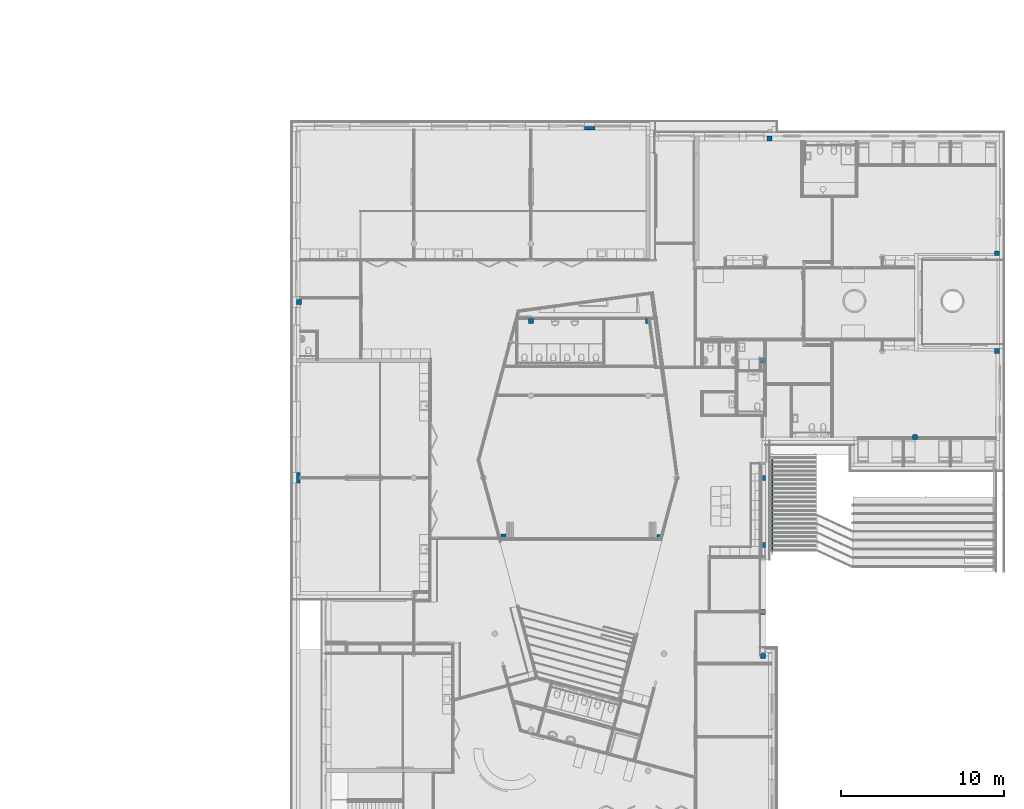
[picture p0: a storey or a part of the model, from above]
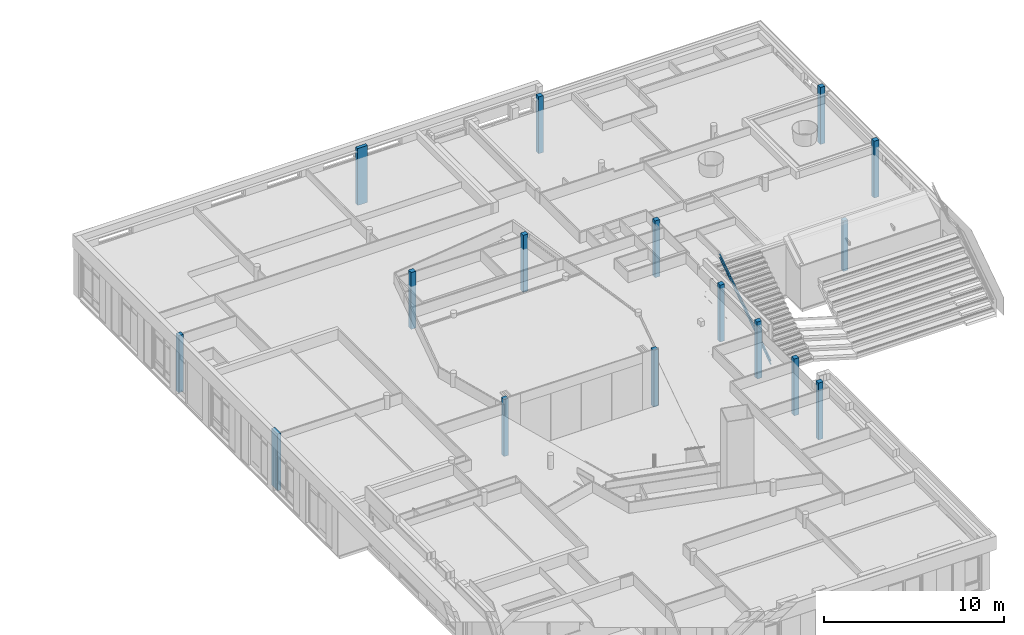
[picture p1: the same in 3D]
Properties of the parts of a building model (IFC2X3), part 1 of 5

# File
Description: ViewDefinition [9, SurfaceGeometryAddOnView, QuantityTakeOffAddOnView, SpaceBoundary2ndLevelAddOnView], Option [Elements to export: Selected elements only], Option [Partial Structure Display: Entire Model], Option [IFC Domain: All], Option [Structural Function: All Elements], Option [Convert Grid elements: On], Option [Convert IFC Annotations and ARCHICAD 2D elements: Off], Option [Convert 2D symbols of Doors and Windows: Off], Option [Export geometries that Participates in Collision Detection only: On], Option [Split complex elements: Off], Option [Material Preservation: Explode all], Option [IFC Site Location: At Project Origin], Option [Curtain Wall export mode: Container Element], Option [Railing export mode: Container Element], Option [Stair export mode: Container Element], Option [Properties To Export: Current Scheme properties only], Option [Space containment: On], Option [IFC Domain For Space Containment: Custom], Option [Bounding Box: On], Option [Geometry to type objects: On], Option [Element Properties: Off], Option [Building Material Properties: Off], Option [Element Parameters: Off], Option [Component Parameters: IFC Component Quantities Only], Option [IFC Base Quantities: On], Option [Door Window Parameters: Off], Option [IFC Space boundaries: On], Option [ARCHICAD Zone Categories as IFC Space classification data: Off], Option [Element Classifications: On]
File name: H:\21002 Kindcentrum De Terp Wieringerwerf\04 Projectgebonden Gegevens\06 Solibri\21002 KC De Terp Wieringerwerf.ifc
Time: 2022-05-06T11:51:14
Author: Architect
Organization: Naam bureau
Written by: The EXPRESS Data Manager Version 5.02.0100.09 : 26 Sep 2013
Made in: IFC file generated by GRAPHISOFT ARCHICAD 24.0.0 NED FULL Windows version (IFC add-on version: 7000 NED FULL).
Authorization: The authorising person

# IfcProject, Kindcentrum De Terp te Wieringerwerf
Phase: DEFINITIEF

# IfcSite, Site
RefLatitude: 51, 27, 0, 0; RefLongitude: 5, 29, 0, 0; RefElevation: 0 mm
BaseQuantities - GrossPerimeter: 0 mm; GrossArea: 0 m2

# IfcBuilding, Naam gebouw
BaseQuantities - GrossFloorArea: 0 m2

# IfcBuildingStorey (3)
In: Naam gebouw
BaseQuantities - NetHeight: 3960 mm; GrossHeight: 3960 mm; Height: 3960 mm; GrossFloorArea: 0 m2
Name | Elevation (mm)
Begane grond | 0
1e verdieping | 3960
2e verdieping | 7920

# IfcBeam: Metaal - Staal AFW 50 x 20 (15)
In: 1e verdieping
Type - PredefinedType: BEAM
Classification: 28.11 KOLOM-/LIGGERCONSTRUCTIES (NL/SfB (4 cijfers)); Balk (ARCHICAD Classification); Material: Metaal - Staal AFW
Pset_BeamCommon - Slope: 0 deg; LoadBearing: yes; IsExternal: no; Reference: Metaal - Staal AFW 50 x 20
BaseQuantities - Width: 50 mm; Depth: 20 mm; CrossSectionArea: 0.001 m2
Component Quantities - Component 1, Skin Thickness: 50 mm; Component 1, Rectangular Component Height: 20 mm; Component 1, Rectangular Component Width: 50 mm; Component 1, Component Cross Section Area: 0.001 m2
Name | Span (mm) | NetSurfaceAreaExtrudedSides (m2) = OuterSurfaceArea (m2) | Length (mm) | TotalSurfaceArea (m2) = GrossSurfaceArea (m2) = NetSurfaceArea (m2) | GrossVolume (m3) | NetVolume (m3) = Component 1, Skin/Component Volume (m3) | Component 1, Mass (kg) | Component 1, Projected Component/Skin Area (m2)
2 x 28_Balk_Regenwaterafvoer-x | 2574.4 | 0.356687 | 2548.45 | 0.358687 | 0.00258018 | 0.00254741 | 20.2519 | 0.0509482
2 x 28_Balk_Regenwaterafvoer-x | 2100.48 | 0.292317 | 2087.98 | 0.294317 | 0.00210625 | 0.00208798 | 16.5994 | 0.0417596
2 x 28_Balk_Regenwaterafvoer-x | 170 | 0.0238 | 170 | 0.0258 | 0.00017 | 0.00017 | 1.3515 | 0.0034
28_Balk_Regenwaterafvoer-x | 389.99 | 0.0545987 | 389.99 | 0.0565987 | 0.00038999 | 0.00038999 | 3.10042 | 0.00779981
2 x 28_Balk_Regenwaterafvoer-x | 390 | 0.0546 | 390 | 0.0566 | 0.00039 | 0.00039 | 3.1005 | 0.0078
28_Balk_Regenwaterafvoer-x | 4014.53 | 0.558376 | 3992.54 | 0.560376 | 0.0040203 | 0.0039884 | 31.7078 | 0.079768
28_Balk_Regenwaterafvoer-x | 4811.55 | 0.672968 | 4812 | 0.674968 | 0.00481732 | 0.00480749 | 38.2195 | 0.0961498
28_Balk_Regenwaterafvoer-x | 2100.48 | 0.292 | 2087.5 | 0.294 | 0.00210625 | 0.0020875 | 16.5956 | 0.04175
28_Balk_Regenwaterafvoer-x | 2100.48 | 0.29225 | 2087.5 | 0.29425 | 0.00210625 | 0.0020875 | 16.5956 | 0.04175
2 x 28_Balk_Regenwaterafvoer-x | 2574.4 | 0.356691 | 2548.45 | 0.358691 | 0.00258018 | 0.00254745 | 20.2522 | 0.050949

# IfcBeam: _TenW_24_tribunetrap tredes 250 x 180 (8)
Type - PredefinedType: BEAM
Classification: 28.11 KOLOM-/LIGGERCONSTRUCTIES (NL/SfB (4 cijfers)); Balk (ARCHICAD Classification)
Pset_BeamCommon - Span: 2000 mm; Slope: 0 deg; LoadBearing: yes; IsExternal: no; Reference: _TenW_24_tribunetrap tredes 250 x 180
BaseQuantities - NetSurfaceAreaExtrudedSides: 1.72 m2; Length: 2000 mm; CrossSectionArea: 0.0135 m2; OuterSurfaceArea: 1.72 m2; TotalSurfaceArea: 1.747 m2; GrossSurfaceArea: 1.747 m2; GrossVolume: 0.027 m3; NetSurfaceArea: 1.747 m2; NetVolume: 0.027 m3
Name | In
2 x 28_Balk_Regenwaterafvoer-x | Begane grond
6 x 28_Balk_Regenwaterafvoer-x | 1e verdieping

# IfcBeam: _TenW_27_installatiescherm 01 115 x 1322 (3)
In: 2e verdieping
Type - PredefinedType: BEAM
Classification: 28.11 KOLOM-/LIGGERCONSTRUCTIES (NL/SfB (4 cijfers)); Balk (ARCHICAD Classification)
Pset_BeamCommon - Slope: 0 deg; LoadBearing: yes; IsExternal: no; Reference: _TenW_27_installatiescherm 01 115 x 1322
BaseQuantities - CrossSectionArea: 0.0318769 m2
Name | Span (mm) | NetSurfaceAreaExtrudedSides (m2) = OuterSurfaceArea (m2) | Length (mm) | TotalSurfaceArea (m2) = GrossSurfaceArea (m2) = NetSurfaceArea (m2) | GrossVolume (m3) | NetVolume (m3)
28_Balk_Regenwaterafvoer-x | 3219.02 | 9.89401 | 3284.82 | 9.95776 | 0.103783 | 0.091714
28_Balk_Regenwaterafvoer-x | 3295.19 | 10.1403 | 3370.12 | 10.2041 | 0.106357 | 0.093978
28_Balk_Regenwaterafvoer-x | 7739.18 | 23.7591 | 7879.9 | 23.8228 | 0.249244 | 0.220283

# IfcBeam: _TenW_27_lichtstraatrand 01 331 x 1666 (3)
In: 2e verdieping
Type - PredefinedType: BEAM
Classification: 28.11 KOLOM-/LIGGERCONSTRUCTIES (NL/SfB (4 cijfers)); Balk (ARCHICAD Classification)
Pset_BeamCommon - Slope: 0 deg; LoadBearing: yes; IsExternal: no; Reference: _TenW_27_lichtstraatrand 01 331 x 1666
BaseQuantities - CrossSectionArea: 0.225205 m2
Name | Span (mm) = Length (mm) | NetSurfaceAreaExtrudedSides (m2) = OuterSurfaceArea (m2) | TotalSurfaceArea (m2) = GrossSurfaceArea (m2) = NetSurfaceArea (m2) | GrossVolume (m3) | NetVolume (m3)
28_Balk_Regenwaterafvoer-x | 9202.83 | 37.3986 | 37.849 | 2.07253 | 2.03806
28_Balk_Regenwaterafvoer-x | 7772.88 | 31.5423 | 31.9927 | 1.75049 | 1.72108
28_Balk_Regenwaterafvoer-x | 6361.7 | 25.7691 | 26.2195 | 1.43269 | 1.4081

# IfcBeam: _TenW_27_lichtstraatrand 02 232 x 1198 (2)
In: 2e verdieping
Type - PredefinedType: BEAM
Classification: 28.11 KOLOM-/LIGGERCONSTRUCTIES (NL/SfB (4 cijfers)); Balk (ARCHICAD Classification)
Pset_BeamCommon - Slope: 0 deg; LoadBearing: yes; IsExternal: no; Reference: _TenW_27_lichtstraatrand 02 232 x 1198
BaseQuantities - CrossSectionArea: 0.142348 m2
Name | Span (mm) = Length (mm) | NetSurfaceAreaExtrudedSides (m2) = OuterSurfaceArea (m2) | TotalSurfaceArea (m2) = GrossSurfaceArea (m2) = NetSurfaceArea (m2) | GrossVolume (m3) | NetVolume (m3)
28_Balk_Regenwaterafvoer-x | 8390.21 | 25.0766 | 25.3613 | 1.19433 | 1.16292
28_Balk_Regenwaterafvoer-x | 6979.04 | 20.8078 | 21.0925 | 0.993451 | 0.966851

# IfcBeam: _TenW_27_lichtstraatrand 02a 232 x 1198, 28_Balk_Regenwaterafvoer-x
In: 2e verdieping
Type - PredefinedType: BEAM
Classification: 28.11 KOLOM-/LIGGERCONSTRUCTIES (NL/SfB (4 cijfers)); Balk (ARCHICAD Classification)
Pset_BeamCommon - Span: 9820.16 mm; Slope: 0 deg; LoadBearing: yes; IsExternal: no; Reference: _TenW_27_lichtstraatrand 02a 232 x 1198
BaseQuantities - NetSurfaceAreaExtrudedSides: 27.0119 m2; Length: 9820.16 mm; CrossSectionArea: 0.142348 m2; OuterSurfaceArea: 27.0119 m2; TotalSurfaceArea: 27.2966 m2; GrossSurfaceArea: 27.2966 m2; GrossVolume: 1.39788 m3; NetSurfaceArea: 27.2966 m2; NetVolume: 1.35556 m3

# IfcBuildingElementPart (990)
Name | In | Material | Mass (kg) | Projected Component/Skin Area (m2) | Skin Thickness (mm) | Rectangular Component Height (mm) | Rectangular Component Width (mm) | Component Cross Section Area (m2) | Skin/Component Volume (m3)
2 x Gipsplaat watervast | Begane grond | Gipsplaat watervast | 85.6406 | 4.89375 | 12.5 | 3630 | 12.5 | 0.045375 | 0.0611719
Isolatie - Steenwol zacht | Begane grond | Isolatie - Steenwol zacht | 16.5164 | 4.89375 | 75 | 3630 | 75 | 0.27225 | 0.367031
Steen - Kalkzandsteen C | Begane grond | Steen - Kalkzandsteen C | 22965.8 | 40.2908 | 300 | 3050 | 300 | 0.915 | 12.0872
Isolatie - Steenwol zacht | Begane grond | Isolatie - Steenwol zacht | 375.609 | 42.0508 | 200 | 3050 | 200 | 0.61 | 8.34687
_TenW_21_Hout betimmering | Begane grond | _TenW_21_Hout betimmering | 420.772 | 42.5022 | 18 | 3050 | 18 | 0.0549 | 0.76504
Steen - Kalkzandsteen C | Begane grond | Steen - Kalkzandsteen C | 11337.6 | 27.8838 | 214 | 3050 | 214 | 0.6527 | 5.96713
Isolatie - Steenwol zacht | Begane grond | Isolatie - Steenwol zacht | 262.543 | 29.4088 | 200 | 3050 | 200 | 0.61 | 5.83429
_TenW_21_Hout betimmering | Begane grond | _TenW_21_Hout betimmering | 301.111 | 30.4153 | 18 | 3050 | 18 | 0.0549 | 0.547475
Steen - Kalkzandsteen C | Begane grond | Steen - Kalkzandsteen C | 16551.1 | 29.037 | 300 | 3050 | 300 | 0.915 | 8.71111
Isolatie - Steenwol zacht | Begane grond | Isolatie - Steenwol zacht | 278.644 | 31.0396 | 200 | 3050 | 200 | 0.61 | 6.19209
_TenW_21_Hout betimmering | Begane grond | _TenW_21_Hout betimmering | 315.021 | 31.8204 | 18 | 3050 | 18 | 0.0549 | 0.572766
Steen - Kalkzandsteen C | Begane grond | Steen - Kalkzandsteen C | 675.052 | 1.66669 | 214 | 3272 | 214 | 0.700208 | 0.355291
Isolatie - Steenwol zacht | Begane grond | Isolatie - Steenwol zacht | 34.1766 | 2.49829 | 304 | 3272 | 304 | 0.994688 | 0.759481
_TenW_21_Steen - Baksteen | Begane grond | _TenW_21_Steen - Baksteen | 81.9614 | 2.56129 | 20 | 3272 | 20 | 0.06544 | 0.0512258
Steen - Kalkzandsteen C | Begane grond | Steen - Kalkzandsteen C | 13204.7 | 32.476 | 214 | 3150 | 214 | 0.6741 | 6.94986
Isolatie - Steenwol zacht | Begane grond | Isolatie - Steenwol zacht | 362.955 | 35.8678 | 264 | 3150 | 264 | 0.8316 | 8.06566
_TenW_21_Steen - Baksteen | Begane grond | _TenW_21_Steen - Baksteen | 519.088 | 16.2215 | 20 | 3150 | 20 | 0.063 | 0.32443
Steen - Kalkzandsteen C | Begane grond | Steen - Kalkzandsteen C | 15236.3 | 37.4724 | 214 | 3150 | 214 | 0.6741 | 8.01909
Isolatie - Steenwol zacht | Begane grond | Isolatie - Steenwol zacht | 437.049 | 41.4889 | 264 | 3150 | 264 | 0.8316 | 9.71219
_TenW_21_Steen - Baksteen | Begane grond | _TenW_21_Steen - Baksteen | 653.201 | 20.4125 | 20 | 3150 | 20 | 0.063 | 0.40825
Steen - Kalkzandsteen C | Begane grond | Steen - Kalkzandsteen C | 2075.95 | 5.10563 | 214 | 3150 | 214 | 0.6741 | 1.0926
Isolatie - Steenwol zacht | Begane grond | Isolatie - Steenwol zacht | 69.2284 | 5.82731 | 264 | 3150 | 264 | 0.8316 | 1.53841
_TenW_21_Steen - Baksteen | Begane grond | _TenW_21_Steen - Baksteen | 213.085 | 6.65891 | 20 | 3150 | 20 | 0.063 | 0.133178
Gipsplaat watervast | Begane grond | Gipsplaat watervast | 225.918 | 12.9096 | 12.5 | 3630 | 12.5 | 0.045375 | 0.16137
Isolatie - Steenwol zacht | Begane grond | Isolatie - Steenwol zacht | 43.5699 | 12.9096 | 75 | 3630 | 75 | 0.27225 | 0.96822
Gipsplaat watervast | Begane grond | Gipsplaat watervast | 233.005 | 13.3146 | 12.5 | 3630 | 12.5 | 0.045375 | 0.166432
4 x Gipsplaat watervast | Begane grond | Gipsplaat watervast | 499.968 | 28.5696 | 12.5 | 3630 | 12.5 | 0.045375 | 0.35712
3 x Isolatie - Steenwol zacht | Begane grond | Isolatie - Steenwol zacht | 96.5743 | 28.6146 | 75 | 3630 | 75 | 0.27225 | 2.14609
Steen - Kalkzandsteen C | Begane grond | Steen - Kalkzandsteen C | 23079.8 | 40.4954 | 300 | 3630 | 300 | 1.089 | 12.1473
Isolatie - Steenwol zacht | Begane grond | Isolatie - Steenwol zacht | 404.639 | 44.9769 | 200 | 3630 | 200 | 0.726 | 8.99198
_TenW_21_Hout betimmering | Begane grond | _TenW_21_Hout betimmering | 477.966 | 48.2794 | 18 | 3630 | 18 | 0.06534 | 0.869028
Steen - Kalkzandsteen C | Begane grond | Steen - Kalkzandsteen C | 5193.13 | 12.7725 | 214 | 3630 | 214 | 0.77682 | 2.73323
Isolatie - Steenwol zacht | Begane grond | Isolatie - Steenwol zacht | 156.064 | 17.3421 | 200 | 3630 | 200 | 0.726 | 3.46809
_TenW_21_Hout betimmering | Begane grond | _TenW_21_Hout betimmering | 193.116 | 19.5067 | 18 | 3630 | 18 | 0.06534 | 0.35112
2 x Gipsplaat watervast | Begane grond | Gipsplaat watervast | 458.405 | 26.1946 | 12.5 | 3630 | 12.5 | 0.045375 | 0.327432
Isolatie - Steenwol zacht | Begane grond | Isolatie - Steenwol zacht | 88.5939 | 26.2501 | 75 | 3630 | 75 | 0.27225 | 1.96875
2 x Gipsplaat watervast | Begane grond | Gipsplaat watervast | 171.255 | 9.786 | 12.5 | 3630 | 12.5 | 0.045375 | 0.122325
2 x Isolatie - Steenwol zacht | Begane grond | Isolatie - Steenwol zacht | 31.6609 | 9.381 | 75 | 3630 | 75 | 0.27225 | 0.703575
2 x Gipsplaat watervast | Begane grond | Gipsplaat watervast | 164.167 | 9.381 | 12.5 | 3630 | 12.5 | 0.045375 | 0.117262
Gipsplaat watervast | Begane grond | Gipsplaat watervast | 282.88 | 16.1646 | 12.5 | 3630 | 12.5 | 0.045375 | 0.202057
Isolatie - Steenwol zacht | Begane grond | Isolatie - Steenwol zacht | 54.4036 | 16.1196 | 75 | 3630 | 75 | 0.27225 | 1.20897
Gipsplaat watervast | Begane grond | Gipsplaat watervast | 277.368 | 15.8496 | 12.5 | 3630 | 12.5 | 0.045375 | 0.19812
Gipsplaat watervast | Begane grond | Gipsplaat watervast | 469.534 | 26.8305 | 12.5 | 3630 | 12.5 | 0.045375 | 0.335381
Isolatie - Steenwol zacht | Begane grond | Isolatie - Steenwol zacht | 90.7402 | 26.886 | 75 | 3630 | 75 | 0.27225 | 2.01645
Gipsplaat watervast | Begane grond | Gipsplaat watervast | 455.542 | 26.031 | 12.5 | 3630 | 12.5 | 0.045375 | 0.325387
Gipsplaat watervast | Begane grond | Gipsplaat watervast | 486.715 | 27.8123 | 12.5 | 3630 | 12.5 | 0.045375 | 0.347654
Isolatie - Steenwol zacht | Begane grond | Isolatie - Steenwol zacht | 96.6002 | 28.6223 | 75 | 3630 | 75 | 0.27225 | 2.14667
Gipsplaat watervast | Begane grond | Gipsplaat watervast | 496.953 | 28.3973 | 12.5 | 3630 | 12.5 | 0.045375 | 0.354966
2 x Gipsplaat watervast | Begane grond | Gipsplaat watervast | 499.784 | 28.5591 | 12.5 | 3630 | 12.5 | 0.045375 | 0.356989
Steen - Kalkzandsteen C | Begane grond | Steen - Kalkzandsteen C | 2688.21 | 6.612 | 214 | 910 | 214 | 0.19474 | 1.41485
Isolatie - Steenwol zacht | Begane grond | Isolatie - Steenwol zacht | 141.331 | 16.9788 | 304 | 910 | 304 | 0.27664 | 3.14069
_TenW_21_Steen - Baksteen | Begane grond | _TenW_21_Steen - Baksteen | 544.486 | 17.0152 | 20 | 910 | 20 | 0.0182 | 0.340304
Steen - Kalkzandsteen C | Begane grond | Steen - Kalkzandsteen C | 3667.16 | 9.01909 | 214 | 910 | 214 | 0.19474 | 1.93008
Isolatie - Steenwol zacht | Begane grond | Isolatie - Steenwol zacht | 308.291 | 27.1253 | 304 | 910 | 304 | 0.27664 | 6.8509
_TenW_21_Steen - Baksteen | Begane grond | _TenW_21_Steen - Baksteen | 869.174 | 27.1617 | 20 | 910 | 20 | 0.0182 | 0.543234
Steen - Kalkzandsteen C | Begane grond | Steen - Kalkzandsteen C | 7966.47 | 19.5929 | 214 | 910 | 214 | 0.19474 | 4.19288
Isolatie - Steenwol zacht | Begane grond | Isolatie - Steenwol zacht | 555.269 | 46.1406 | 304 | 910 | 304 | 0.27664 | 12.3393
_TenW_21_Steen - Baksteen | Begane grond | _TenW_21_Steen - Baksteen | 1485.94 | 46.4355 | 20 | 910 | 20 | 0.0182 | 0.92871
Steen - Kalkzandsteen C | Begane grond | Steen - Kalkzandsteen C | 5615.37 | 13.8106 | 214 | 910 | 214 | 0.19474 | 2.95546
Isolatie - Steenwol zacht | Begane grond | Isolatie - Steenwol zacht | 363.505 | 26.572 | 304 | 910 | 304 | 0.27664 | 8.07789
_TenW_21_Steen - Baksteen | Begane grond | _TenW_21_Steen - Baksteen | 868.009 | 27.1253 | 20 | 910 | 20 | 0.0182 | 0.542506
Steen - Kalkzandsteen C | Begane grond | Steen - Kalkzandsteen C | 21.3239 | 0.0524444 | 214 | 910 | 214 | 0.19474 | 0.0112231
Isolatie - Steenwol zacht | Begane grond | Isolatie - Steenwol zacht | 4.02419 | 0.294166 | 304 | 910 | 304 | 0.27664 | 0.0894264
_TenW_21_Steen - Baksteen | Begane grond | _TenW_21_Steen - Baksteen | 18.2658 | 0.570806 | 20 | 910 | 20 | 0.0182 | 0.0114161
Gipsplaat watervast | Begane grond | Gipsplaat watervast | 62.2125 | 3.555 | 12.5 | 3630 | 12.5 | 0.045375 | 0.0444375
Isolatie - Steenwol zacht | Begane grond | Isolatie - Steenwol zacht | 11.2387 | 3.33 | 75 | 3630 | 75 | 0.27225 | 0.24975
Gipsplaat watervast | Begane grond | Gipsplaat watervast | 56.7 | 3.24 | 12.5 | 3630 | 12.5 | 0.045375 | 0.0405
Gipsplaat watervast | Begane grond | Gipsplaat watervast | 175.448 | 10.0256 | 12.5 | 3630 | 12.5 | 0.045375 | 0.12532
Isolatie - Steenwol zacht | Begane grond | Isolatie - Steenwol zacht | 47.773 | 10.6162 | 100 | 3630 | 100 | 0.363 | 1.06162
Gipsplaat watervast | Begane grond | Gipsplaat watervast | 186.522 | 10.6584 | 12.5 | 3630 | 12.5 | 0.045375 | 0.13323
2 x  | Begane grond |  |  |  |  |  |  |  | 0.089481
3 x _TenW_24_Hout - Multiplex | Begane grond | _TenW_24_Hout - Multiplex | 32.0279 |  |  |  |  |  | 0.0457542
3 x Glas | Begane grond | Glas | 14.8872 |  |  |  |  |  | 0.00682899
Gipsplaat watervast | Begane grond | Gipsplaat watervast | 53.4085 | 3.05192 | 12.5 | 3480 | 12.5 | 0.0435 | 0.0381489
Isolatie - Steenwol zacht | Begane grond | Isolatie - Steenwol zacht | 13.0704 | 2.90454 | 100 | 3480 | 100 | 0.348 | 0.290454
Gipsplaat watervast | Begane grond | Gipsplaat watervast | 46.3998 | 2.65142 | 12.5 | 3480 | 12.5 | 0.0435 | 0.0331427
Gipsplaat watervast | Begane grond | Gipsplaat watervast | 444.637 | 25.4079 | 12.5 | 3630 | 12.5 | 0.045375 | 0.317598
Isolatie - Steenwol zacht | Begane grond | Isolatie - Steenwol zacht | 87.3297 | 25.8755 | 75 | 3630 | 75 | 0.27225 | 1.94066
Gipsplaat watervast | Begane grond | Gipsplaat watervast | 430.082 | 24.5761 | 12.5 | 3630 | 12.5 | 0.045375 | 0.307201
 | Begane grond |  |  |  |  |  |  |  | 0.0799506
Gipsplaat watervast | Begane grond | Gipsplaat watervast | 290.794 | 16.6168 | 12.5 | 3630 | 12.5 | 0.045375 | 0.20771
Isolatie - Steenwol zacht | Begane grond | Isolatie - Steenwol zacht | 70.7551 | 16.659 | 100 | 3630 | 100 | 0.363 | 1.57233
Gipsplaat watervast | Begane grond | Gipsplaat watervast | 288.579 | 16.4902 | 12.5 | 3630 | 12.5 | 0.045375 | 0.206128
_TenW_21_Hout betimmering | Begane grond | _TenW_21_Hout betimmering | 269.164 | 27.1883 | 18 | 2865.85 | 18 | 0.0515853 | 0.48939
Isolatie - Steenwol zacht | Begane grond | Isolatie - Steenwol zacht | 230.2 | 25.5777 | 200 | 2865.85 | 200 | 0.57317 | 5.11554
Steen - Kalkzandsteen C | Begane grond | Steen - Kalkzandsteen C | 10060.4 | 24.7428 | 214 | 2865.85 | 214 | 0.613292 | 5.29496
Gipsplaat watervast | Begane grond | Gipsplaat watervast | 441.568 | 25.2445 | 12.5 | 3670 | 12.5 | 0.045875 | 0.315406
Isolatie - Steenwol zacht | Begane grond | Isolatie - Steenwol zacht | 85.0063 | 25.287 | 75 | 3670 | 75 | 0.27525 | 1.88903
Gipsplaat watervast | Begane grond | Gipsplaat watervast | 425.679 | 24.342 | 12.5 | 3670 | 12.5 | 0.045875 | 0.304056
4 x Gipsplaat watervast | Begane grond | Gipsplaat watervast | 276.58 | 15.8046 | 12.5 | 3670 | 12.5 | 0.045875 | 0.197557
2 x Isolatie - Steenwol zacht | Begane grond | Isolatie - Steenwol zacht | 53.4923 | 15.8496 | 75 | 3670 | 75 | 0.27525 | 1.18872
Gipsplaat watervast | Begane grond | Gipsplaat watervast | 118.403 | 6.76591 | 12.5 | 3990 | 12.5 | 0.049875 | 0.0845736
Isolatie - Steenwol zacht | Begane grond | Isolatie - Steenwol zacht | 22.9273 | 6.79326 | 75 | 3990 | 75 | 0.29925 | 0.509495
Gipsplaat watervast | Begane grond | Gipsplaat watervast | 115.623 | 6.60706 | 12.5 | 3990 | 12.5 | 0.049875 | 0.0825879
Steen - Kalkzandsteen C | Begane grond | Steen - Kalkzandsteen C | 9807.48 | 24.4002 | 214 | 3960 | 214 | 0.84744 | 5.16183
Isolatie - Steenwol zacht | Begane grond | Isolatie - Steenwol zacht | 238.299 | 26.4777 | 200 | 3960 | 200 | 0.792 | 5.29553
_TenW_21_Hout betimmering | Begane grond | _TenW_21_Hout betimmering | 252.537 | 25.6283 | 18 | 3960 | 18 | 0.07128 | 0.459159
Gipsplaat watervast | Begane grond | Gipsplaat watervast | 264.372 | 15.107 | 12.5 | 3630 | 12.5 | 0.045375 | 0.188837
Isolatie - Steenwol zacht | Begane grond | Isolatie - Steenwol zacht | 53.8627 | 16.4741 | 75 | 3630 | 75 | 0.27225 | 1.19695
Gipsplaat watervast | Begane grond | Gipsplaat watervast | 277.272 | 15.8441 | 12.5 | 3630 | 12.5 | 0.045375 | 0.198052
Cement | Begane grond | Cement | 213571 | 1605.8 | 70 |  |  |  | 112.406
Beton gewapend C vloer | Begane grond | Beton gewapend C vloer | 238222 | 1654.32 | 60 |  |  |  | 99.2592
Beton gewapend prefab vloer | Begane grond | Beton gewapend prefab vloer | 1032296 | 1654.32 | 260 |  |  |  | 430.123
Isolatie - Kunststof hard | Begane grond | Isolatie - Kunststof hard | 29777.8 | 1654.32 | 180 |  |  |  | 297.778
2 x Gipsplaat watervast | Begane grond | Gipsplaat watervast | 146.733 | 8.38473 | 12.5 | 2910 | 12.5 | 0.036375 | 0.104809
Isolatie - Steenwol zacht | Begane grond | Isolatie - Steenwol zacht | 28.2985 | 8.38473 | 75 | 2910 | 75 | 0.21825 | 0.628855
2 x Gipsplaat watervast | Begane grond | Gipsplaat watervast | 37.6523 | 2.15156 | 12.5 | 3630 | 12.5 | 0.045375 | 0.0268945
Isolatie - Steenwol zacht | Begane grond | Isolatie - Steenwol zacht | 7.40391 | 2.19375 | 75 | 3630 | 75 | 0.27225 | 0.164531
2 x Gipsplaat watervast | Begane grond | Gipsplaat watervast | 35.4375 | 2.025 | 12.5 | 3630 | 12.5 | 0.045375 | 0.0253125
Isolatie - Steenwol zacht | Begane grond | Isolatie - Steenwol zacht | 6.97676 | 2.06719 | 75 | 3630 | 75 | 0.27225 | 0.155039
Gipsplaat watervast | Begane grond | Gipsplaat watervast | 360.975 | 20.6271 | 12.5 | 3630 | 12.5 | 0.045375 | 0.257839
Isolatie - Steenwol zacht | Begane grond | Isolatie - Steenwol zacht | 89.6737 | 21.9518 | 100 | 3630 | 100 | 0.363 | 1.99275
Gipsplaat watervast | Begane grond | Gipsplaat watervast | 384.157 | 21.9518 | 12.5 | 3630 | 12.5 | 0.045375 | 0.274398
Gipsplaat watervast | Begane grond | Gipsplaat watervast | 253.437 | 14.4821 | 12.5 | 3480 | 12.5 | 0.0435 | 0.181027
Isolatie - Steenwol zacht | Begane grond | Isolatie - Steenwol zacht | 49.1619 | 14.5665 | 75 | 3480 | 75 | 0.261 | 1.09249
Gipsplaat watervast | Begane grond | Gipsplaat watervast | 249.007 | 14.229 | 12.5 | 3480 | 12.5 | 0.0435 | 0.177862
Gipsplaat watervast | Begane grond | Gipsplaat watervast | 364.235 | 20.8134 | 12.5 | 3630 | 12.5 | 0.045375 | 0.260168
Isolatie - Steenwol zacht | Begane grond | Isolatie - Steenwol zacht | 80.5038 | 20.8556 | 100 | 3630 | 100 | 0.363 | 1.78897
Gipsplaat watervast | Begane grond | Gipsplaat watervast | 360.544 | 20.6025 | 12.5 | 3630 | 12.5 | 0.045375 | 0.257531
Gipsplaat watervast | Begane grond | Gipsplaat watervast | 200.074 | 11.4328 | 12.5 | 3480 | 12.5 | 0.0435 | 0.14291
Isolatie - Steenwol zacht | Begane grond | Isolatie - Steenwol zacht | 37.0195 | 10.9688 | 75 | 3480 | 75 | 0.261 | 0.822656
Gipsplaat watervast | Begane grond | Gipsplaat watervast | 191.215 | 10.9266 | 12.5 | 3480 | 12.5 | 0.0435 | 0.136582
2 x Gipsplaat watervast | Begane grond | Gipsplaat watervast | 84.9023 | 4.85156 | 12.5 | 3480 | 12.5 | 0.0435 | 0.0606445
Isolatie - Steenwol zacht | Begane grond | Isolatie - Steenwol zacht | 16.5164 | 4.89375 | 75 | 3480 | 75 | 0.261 | 0.367031
Steen - Kalkzandsteen C | Begane grond | Steen - Kalkzandsteen C | 1382.03 | 4.84924 | 150 | 3680 | 150 | 0.552 | 0.727386
Isolatie - Steenwol zacht | Begane grond | Isolatie - Steenwol zacht | 60.5189 | 6.72432 | 200 | 3680 | 200 | 0.736 | 1.34486
_TenW_21_Hout betimmering | Begane grond | _TenW_21_Hout betimmering | 60.6015 | 6.12136 | 18 | 3680 | 18 | 0.06624 | 0.110185
Steen - Kalkzandsteen C | Begane grond | Steen - Kalkzandsteen C | 1382.03 | 4.84924 | 150 | 3630 | 150 | 0.5445 | 0.727386
Isolatie - Steenwol zacht | Begane grond | Isolatie - Steenwol zacht | 53.9849 | 5.99832 | 200 | 3630 | 200 | 0.726 | 1.19966
_TenW_21_Hout betimmering | Begane grond | _TenW_21_Hout betimmering | 59.9546 | 6.05602 | 18 | 3630 | 18 | 0.06534 | 0.109008
Gipsplaat watervast | Begane grond | Gipsplaat watervast | 199.598 | 11.4056 | 12.5 | 4060 | 12.5 | 0.05075 | 0.14257
Isolatie - Steenwol zacht | Begane grond | Isolatie - Steenwol zacht | 39.4051 | 11.6756 | 75 | 4060 | 75 | 0.3045 | 0.875669
Gipsplaat watervast | Begane grond | Gipsplaat watervast | 200.385 | 11.4506 | 12.5 | 4060 | 12.5 | 0.05075 | 0.143132
Gipsplaat watervast | Begane grond | Gipsplaat watervast | 47.9629 | 2.74074 | 12.5 | 4060 | 12.5 | 0.05075 | 0.0342592
Isolatie - Steenwol zacht | Begane grond | Isolatie - Steenwol zacht | 9.63473 | 2.85474 | 75 | 4060 | 75 | 0.3045 | 0.214105
Gipsplaat watervast | Begane grond | Gipsplaat watervast | 53.8954 | 3.07974 | 12.5 | 4060 | 12.5 | 0.05075 | 0.0384967
Gipsplaat watervast | Begane grond | Gipsplaat watervast | 84.5512 | 4.8315 | 12.5 | 3630 | 12.5 | 0.045375 | 0.0603937
Isolatie - Steenwol zacht | Begane grond | Isolatie - Steenwol zacht | 14.4656 | 4.2861 | 75 | 3630 | 75 | 0.27225 | 0.321457
Gipsplaat watervast | Begane grond | Gipsplaat watervast | 71.3842 | 4.0791 | 12.5 | 3630 | 12.5 | 0.045375 | 0.0509887
Gipsplaat watervast | Begane grond | Gipsplaat watervast | 33.6018 | 1.9201 | 12.5 | 3630 | 12.5 | 0.045375 | 0.0240013
Isolatie - Steenwol zacht | Begane grond | Isolatie - Steenwol zacht | 6.95621 | 2.0611 | 75 | 3630 | 75 | 0.27225 | 0.154582
Gipsplaat watervast | Begane grond | Gipsplaat watervast | 31.1867 | 1.7821 | 12.5 | 3630 | 12.5 | 0.045375 | 0.0222762
Gipsplaat watervast | Begane grond | Gipsplaat watervast | 232.059 | 13.2605 | 12.5 | 3630 | 12.5 | 0.045375 | 0.165757
Isolatie - Steenwol zacht | Begane grond | Isolatie - Steenwol zacht | 44.7543 | 13.2605 | 75 | 3630 | 75 | 0.27225 | 0.994539
Gipsplaat watervast | Begane grond | Gipsplaat watervast | 226.547 | 12.9455 | 12.5 | 3630 | 12.5 | 0.045375 | 0.161819
2 x Gipsplaat watervast | Begane grond | Gipsplaat watervast | 232.218 | 13.2696 | 12.5 | 3630 | 12.5 | 0.045375 | 0.16587
Isolatie - Steenwol zacht | Begane grond | Isolatie - Steenwol zacht | 44.9368 | 13.3146 | 75 | 3630 | 75 | 0.27225 | 0.998595
Gipsplaat watervast | Begane grond | Gipsplaat watervast | 133.077 | 7.60442 | 12.5 | 3630 | 12.5 | 0.045375 | 0.0950553
Isolatie - Steenwol zacht | Begane grond | Isolatie - Steenwol zacht | 25.7459 | 7.62842 | 75 | 3630 | 75 | 0.27225 | 0.572132
Gipsplaat watervast | Begane grond | Gipsplaat watervast | 131.922 | 7.53842 | 12.5 | 3630 | 12.5 | 0.045375 | 0.0942303
Gipsplaat watervast | Begane grond | Gipsplaat watervast | 20.9276 | 1.20189 | 12.5 | 3630 | 12.5 | 0.045375 | 0.0149483
Isolatie - Steenwol zacht | Begane grond | Isolatie - Steenwol zacht | 4.05084 | 1.23642 | 75 | 3630 | 75 | 0.27225 | 0.0900187
Gipsplaat watervast | Begane grond | Gipsplaat watervast | 23.6864 | 1.35954 | 12.5 | 3630 | 12.5 | 0.045375 | 0.0169188
Steen - Kalkzandsteen C | Begane grond | Steen - Kalkzandsteen C | 109.824 | 0.347872 | 214 | 910 | 214 | 0.19474 | 0.057802
Isolatie - Steenwol zacht | Begane grond | Isolatie - Steenwol zacht | 7.42294 | 0.542612 | 304 | 910 | 304 | 0.27664 | 0.164954
_TenW_21_Steen - Baksteen | Begane grond | _TenW_21_Steen - Baksteen | 26.2161 | 0.819252 | 20 | 910 | 20 | 0.0182 | 0.016385
2 x Gipsplaat watervast | Begane grond | Gipsplaat watervast | 138.989 | 7.94224 | 12.5 | 2318 | 12.5 | 0.028975 | 0.099278
Isolatie - Steenwol zacht | Begane grond | Isolatie - Steenwol zacht | 26.8051 | 7.94224 | 75 | 2318 | 75 | 0.17385 | 0.595668
Gipsplaat watervast | Begane grond | Gipsplaat watervast | 47.9248 | 3.15798 | 12.5 | 668 | 12.5 | 0.00835 | 0.034232
Isolatie - Steenwol zacht | Begane grond | Isolatie - Steenwol zacht | 16.4958 | 5.2369 | 75 | 668 | 75 | 0.0501 | 0.366574
Gipsplaat watervast | Begane grond | Gipsplaat watervast | 91.6458 | 5.2369 | 12.5 | 668 | 12.5 | 0.00835 | 0.0654613
Gipsplaat watervast | Begane grond | Gipsplaat watervast | 68.1552 | 3.89458 | 12.5 | 4060 | 12.5 | 0.05075 | 0.0486823
Isolatie - Steenwol zacht | Begane grond | Isolatie - Steenwol zacht | 13.6228 | 4.51071 | 75 | 4060 | 75 | 0.3045 | 0.302728
Gipsplaat watervast | Begane grond | Gipsplaat watervast | 69.0818 | 3.94754 | 12.5 | 4060 | 12.5 | 0.05075 | 0.0493441
Gipsplaat watervast | Begane grond | Gipsplaat watervast | 23.4798 | 1.3417 | 12.5 | 1660 | 12.5 | 0.02075 | 0.0167713
Isolatie - Steenwol zacht | Begane grond | Isolatie - Steenwol zacht | 5.11947 | 1.81075 | 75 | 1660 | 75 | 0.1245 | 0.113766
Gipsplaat watervast | Begane grond | Gipsplaat watervast | 26.6458 | 1.52262 | 12.5 | 1660 | 12.5 | 0.02075 | 0.0190327
4 x Gipsplaat watervast | Begane grond | Gipsplaat watervast | 31.5 | 1.8 | 12.5 | 3630 | 12.5 | 0.045375 | 0.0225
2 x Isolatie - Steenwol zacht | Begane grond | Isolatie - Steenwol zacht | 6.37875 | 1.89 | 75 | 3630 | 75 | 0.27225 | 0.14175
4 x Gipsplaat watervast | Begane grond | Gipsplaat watervast | 100.872 | 5.76413 | 12.5 | 3630 | 12.5 | 0.045375 | 0.0720516
Isolatie - Steenwol zacht | Begane grond | Isolatie - Steenwol zacht | 19.6396 | 5.81913 | 75 | 3630 | 75 | 0.27225 | 0.436435
Gipsplaat watervast | Begane grond | Gipsplaat watervast | 27.1082 | 1.54904 | 12.5 | 3630 | 12.5 | 0.045375 | 0.019363
Isolatie - Steenwol zacht | Begane grond | Isolatie - Steenwol zacht | 5.07809 | 1.51841 | 75 | 3630 | 75 | 0.27225 | 0.112846
Gipsplaat watervast | Begane grond | Gipsplaat watervast | 22.1061 | 1.278 | 12.5 | 3630 | 12.5 | 0.045375 | 0.0157901
Gipsplaat watervast | Begane grond | Gipsplaat watervast | 107.1 | 6.12 | 12.5 | 3630 | 12.5 | 0.045375 | 0.0765
Isolatie - Steenwol zacht | Begane grond | Isolatie - Steenwol zacht | 20.8069 | 6.165 | 75 | 3630 | 75 | 0.27225 | 0.462375
Gipsplaat watervast | Begane grond | Gipsplaat watervast | 112.612 | 6.435 | 12.5 | 3630 | 12.5 | 0.045375 | 0.0804375
Gipsplaat | Begane grond | Gipsplaat | 79.8093 | 8.45085 | 12.5 | 1470 | 12.5 | 0.018375 | 0.0997617
Isolatie - Glaswol zacht | Begane grond | Isolatie - Glaswol zacht | 13.9067 | 9.3715 | 125 | 1470 | 125 | 0.18375 | 0.993339
Gipsplaat | Begane grond | Gipsplaat | 65.9009 | 6.62464 | 12.5 | 1470 | 12.5 | 0.018375 | 0.0823762
Gipsplaat watervast | Begane grond | Gipsplaat watervast | 10.0192 | 0.572525 | 12.5 | 1470 | 12.5 | 0.018375 | 0.00715655
Isolatie - Steenwol zacht | Begane grond | Isolatie - Steenwol zacht | 2.7135 | 1.09712 | 75 | 1470 | 75 | 0.11025 | 0.0603
Gipsplaat watervast | Begane grond | Gipsplaat watervast | 19.1972 | 1.09701 | 12.5 | 1470 | 12.5 | 0.018375 | 0.0137123
Steen - Kalkzandsteen C | Begane grond | Steen - Kalkzandsteen C | 770.868 | 2.7048 | 150 | 750 | 150 | 0.1125 | 0.40572
Isolatie - Steenwol zacht | Begane grond | Isolatie - Steenwol zacht | 34.776 | 3.864 | 200 | 750 | 200 | 0.15 | 0.7728
_TenW_21_Hout betimmering | Begane grond | _TenW_21_Hout betimmering | 38.2536 | 3.864 | 18 | 750 | 18 | 0.0135 | 0.069552
Steen - Kalkzandsteen C | Begane grond | Steen - Kalkzandsteen C | 4608.84 | 9.32686 | 300 | 910 | 300 | 0.273 | 2.4257
Isolatie - Steenwol zacht | Begane grond | Isolatie - Steenwol zacht | 84.2935 | 9.36594 | 200 | 910 | 200 | 0.182 | 1.87319
_TenW_21_Hout betimmering | Begane grond | _TenW_21_Hout betimmering | 91.9916 | 9.29208 | 18 | 910 | 18 | 0.01638 | 0.167257
Gipsplaat watervast | Begane grond | Gipsplaat watervast | 135.163 | 7.72363 | 12.5 | 3480 | 12.5 | 0.0435 | 0.0965453
Isolatie - Steenwol zacht | Begane grond | Isolatie - Steenwol zacht | 31.5305 | 8.01894 | 100 | 3480 | 100 | 0.348 | 0.700677
Gipsplaat watervast | Begane grond | Gipsplaat watervast | 140.331 | 8.01894 | 12.5 | 3480 | 12.5 | 0.0435 | 0.100237
Gipsplaat watervast | Begane grond | Gipsplaat watervast | 356.592 | 20.3767 | 12.5 | 3988.57 | 12.5 | 0.0498571 | 0.254708
Isolatie - Steenwol zacht | Begane grond | Isolatie - Steenwol zacht | 80.5103 | 20.8556 | 100 | 3988.57 | 100 | 0.398857 | 1.78912
Gipsplaat watervast | Begane grond | Gipsplaat watervast | 364.973 | 20.8556 | 12.5 | 3988.57 | 12.5 | 0.0498571 | 0.260695
Gipsplaat watervast | Begane grond | Gipsplaat watervast | 232.575 | 13.29 | 12.5 | 3766.98 | 12.5 | 0.0470872 | 0.166125
Isolatie - Steenwol zacht | Begane grond | Isolatie - Steenwol zacht | 45.9929 | 13.6275 | 75 | 3766.98 | 75 | 0.282523 | 1.02206
Gipsplaat watervast | Begane grond | Gipsplaat watervast | 237.005 | 13.5431 | 12.5 | 3766.98 | 12.5 | 0.0470872 | 0.169289
Gipsplaat watervast | Begane grond | Gipsplaat watervast | 78.1777 | 4.46733 | 12.5 | 3211 | 12.5 | 0.0401375 | 0.0558412
Isolatie - Steenwol zacht | Begane grond | Isolatie - Steenwol zacht | 15.2116 | 4.50732 | 75 | 3211 | 75 | 0.240825 | 0.338036
Gipsplaat watervast | Begane grond | Gipsplaat watervast | 78.1806 | 4.46749 | 12.5 | 3211 | 12.5 | 0.0401375 | 0.0558433
Gipsplaat watervast | Begane grond | Gipsplaat watervast | 78.6644 | 4.49514 | 12.5 | 3234.97 | 12.5 | 0.0404371 | 0.0561889
Isolatie - Steenwol zacht | Begane grond | Isolatie - Steenwol zacht | 15.3065 | 4.53544 | 75 | 3234.97 | 75 | 0.242623 | 0.340144
Gipsplaat watervast | Begane grond | Gipsplaat watervast | 78.6673 | 4.49531 | 12.5 | 3234.97 | 12.5 | 0.0404371 | 0.056191
Steen - Kalkzandsteen C | Begane grond | Steen - Kalkzandsteen C | 3741.73 | 9.22263 | 214 | 3630 | 214 | 0.77682 | 1.96933
Isolatie - Steenwol zacht | Begane grond | Isolatie - Steenwol zacht | 65.2432 | 7.29492 | 200 | 3630 | 200 | 0.726 | 1.44985
_TenW_21_Hout betimmering | Begane grond | _TenW_21_Hout betimmering | 67.2307 | 6.79098 | 18 | 3630 | 18 | 0.06534 | 0.122238
2 x Gipsplaat watervast | Begane grond | Gipsplaat watervast | 178.763 | 10.2151 | 12.5 | 3670 | 12.5 | 0.045875 | 0.127688
Isolatie - Steenwol zacht | Begane grond | Isolatie - Steenwol zacht | 34.7796 | 10.3051 | 75 | 3670 | 75 | 0.27525 | 0.772879
Gipsplaat watervast | Begane grond | Gipsplaat watervast | 495.208 | 28.3055 | 12.5 | 3630 | 12.5 | 0.045375 | 0.35372
Isolatie - Steenwol zacht | Begane grond | Isolatie - Steenwol zacht | 95.659 | 28.3906 | 75 | 3630 | 75 | 0.27225 | 2.12576
Gipsplaat watervast | Begane grond | Gipsplaat watervast | 484.97 | 27.7205 | 12.5 | 3630 | 12.5 | 0.045375 | 0.346407
Gipsplaat watervast | Begane grond | Gipsplaat watervast | 188.151 | 10.8115 | 12.5 | 3940 | 12.5 | 0.04925 | 0.134393
Isolatie - Steenwol zacht | Begane grond | Isolatie - Steenwol zacht | 38.2348 | 11.6956 | 75 | 3940 | 75 | 0.2955 | 0.849663
Gipsplaat watervast | Begane grond | Gipsplaat watervast | 193.841 | 11.1377 | 12.5 | 3940 | 12.5 | 0.04925 | 0.138458
Gipsplaat watervast | Begane grond | Gipsplaat watervast | 76.153 | 4.35763 | 12.5 | 4060 | 12.5 | 0.05075 | 0.054395
Isolatie - Steenwol zacht | Begane grond | Isolatie - Steenwol zacht | 15.2192 | 4.54556 | 75 | 4060 | 75 | 0.3045 | 0.338204
Gipsplaat watervast | Begane grond | Gipsplaat watervast | 78.05 | 4.46603 | 12.5 | 4060 | 12.5 | 0.05075 | 0.05575
Gipsplaat watervast | Begane grond | Gipsplaat watervast | 59.9754 | 3.43315 | 12.5 | 3940 | 12.5 | 0.04925 | 0.0428396
Isolatie - Steenwol zacht | Begane grond | Isolatie - Steenwol zacht | 12.2788 | 3.79347 | 75 | 3940 | 75 | 0.2955 | 0.272862
Gipsplaat watervast | Begane grond | Gipsplaat watervast | 70.2806 | 4.02258 | 12.5 | 3940 | 12.5 | 0.04925 | 0.0502004
Gipsplaat watervast | Begane grond | Gipsplaat watervast | 45.6954 | 2.62167 | 12.5 | 3960 | 12.5 | 0.0495 | 0.0326396
Isolatie - Steenwol zacht | Begane grond | Isolatie - Steenwol zacht | 8.01461 | 2.40155 | 75 | 3960 | 75 | 0.297 | 0.178102
Gipsplaat watervast | Begane grond | Gipsplaat watervast | 41.6142 | 2.38243 | 12.5 | 3960 | 12.5 | 0.0495 | 0.0297244
Gipsplaat watervast | Begane grond | Gipsplaat watervast | 218.541 | 12.527 | 12.5 | 3960 | 12.5 | 0.0495 | 0.156101
Isolatie - Steenwol zacht | Begane grond | Isolatie - Steenwol zacht | 43.049 | 12.9891 | 75 | 3960 | 75 | 0.297 | 0.956644
Gipsplaat watervast | Begane grond | Gipsplaat watervast | 220.018 | 12.6114 | 12.5 | 3960 | 12.5 | 0.0495 | 0.157156
Gipsplaat watervast | Begane grond | Gipsplaat watervast | 327.887 | 18.7935 | 12.5 | 3960 | 12.5 | 0.0495 | 0.234205
Isolatie - Steenwol zacht | Begane grond | Isolatie - Steenwol zacht | 62.3665 | 18.8215 | 75 | 3960 | 75 | 0.297 | 1.38592
Gipsplaat watervast | Begane grond | Gipsplaat watervast | 322.764 | 18.5068 | 12.5 | 3960 | 12.5 | 0.0495 | 0.230546
Gipsplaat watervast | Begane grond | Gipsplaat watervast | 492.781 | 28.168 | 12.5 | 3960 | 12.5 | 0.0495 | 0.351986
Isolatie - Steenwol zacht | Begane grond | Isolatie - Steenwol zacht | 95.5612 | 28.3689 | 75 | 3960 | 75 | 0.297 | 2.12358
Gipsplaat watervast | Begane grond | Gipsplaat watervast | 495.004 | 28.295 | 12.5 | 3960 | 12.5 | 0.0495 | 0.353574
Gipsplaat watervast | Begane grond | Gipsplaat watervast | 571.943 | 32.6915 | 12.5 | 3960 | 12.5 | 0.0495 | 0.408531
Isolatie - Steenwol zacht | Begane grond | Isolatie - Steenwol zacht | 112.651 | 33.4324 | 75 | 3960 | 75 | 0.297 | 2.50335
Gipsplaat watervast | Begane grond | Gipsplaat watervast | 584.432 | 33.4052 | 12.5 | 3960 | 12.5 | 0.0495 | 0.417451
Gipsplaat watervast | Begane grond | Gipsplaat watervast | 135.933 | 7.76758 | 12.5 | 3670 | 12.5 | 0.045875 | 0.0970947
Isolatie - Steenwol zacht | Begane grond | Isolatie - Steenwol zacht | 26.5193 | 7.85758 | 75 | 3670 | 75 | 0.27525 | 0.589318
Gipsplaat watervast | Begane grond | Gipsplaat watervast | 141.445 | 8.08258 | 12.5 | 3670 | 12.5 | 0.045875 | 0.101032
Gipsplaat watervast | Begane grond | Gipsplaat watervast | 404.181 | 23.1091 | 12.5 | 3960 | 12.5 | 0.0495 | 0.288701
Isolatie - Steenwol zacht | Begane grond | Isolatie - Steenwol zacht | 81.165 | 24.1268 | 75 | 3960 | 75 | 0.297 | 1.80367
Gipsplaat watervast | Begane grond | Gipsplaat watervast | 420.174 | 24.0229 | 12.5 | 3960 | 12.5 | 0.0495 | 0.300124
Gipsplaat watervast | Begane grond | Gipsplaat watervast | 202.497 | 11.5808 | 12.5 | 2910 | 12.5 | 0.036375 | 0.144641
Isolatie - Steenwol zacht | Begane grond | Isolatie - Steenwol zacht | 38.957 | 11.5997 | 75 | 2910 | 75 | 0.21825 | 0.86571
Gipsplaat watervast | Begane grond | Gipsplaat watervast | 204.822 | 11.7136 | 12.5 | 2910 | 12.5 | 0.036375 | 0.146302
Gipsplaat watervast | Begane grond | Gipsplaat watervast | 120.634 | 6.89336 | 12.5 | 4060 | 12.5 | 0.05075 | 0.0861671
Isolatie - Steenwol zacht | Begane grond | Isolatie - Steenwol zacht | 22.9029 | 7.16775 | 75 | 4060 | 75 | 0.3045 | 0.508953
Gipsplaat watervast | Begane grond | Gipsplaat watervast | 106.865 | 6.10655 | 12.5 | 4060 | 12.5 | 0.05075 | 0.0763318
Gipsplaat watervast | Begane grond | Gipsplaat watervast | 328.954 | 18.8068 | 12.5 | 2630 | 12.5 | 0.032875 | 0.234967
Isolatie - Steenwol zacht | Begane grond | Isolatie - Steenwol zacht | 63.5679 | 18.9863 | 75 | 2630 | 75 | 0.19725 | 1.41262
Gipsplaat watervast | Begane grond | Gipsplaat watervast | 318.361 | 18.2161 | 12.5 | 2630 | 12.5 | 0.032875 | 0.227401
Gipsplaat watervast | Begane grond | Gipsplaat watervast | 144.541 | 8.25949 | 12.5 | 2590 | 12.5 | 0.032375 | 0.103244
Isolatie - Steenwol zacht | Begane grond | Isolatie - Steenwol zacht | 28.7368 | 8.51461 | 75 | 2590 | 75 | 0.19425 | 0.638596
Gipsplaat watervast | Begane grond | Gipsplaat watervast | 147.901 | 8.45149 | 12.5 | 2590 | 12.5 | 0.032375 | 0.105644
2 x Gipsplaat watervast | Begane grond | Gipsplaat watervast | 81.8221 | 4.67555 | 12.5 | 2590 | 12.5 | 0.032375 | 0.0584443
Isolatie - Steenwol zacht | Begane grond | Isolatie - Steenwol zacht | 15.885 | 4.70667 | 75 | 2590 | 75 | 0.19425 | 0.353
Gipsplaat watervast | Begane grond | Gipsplaat watervast | 55.9135 | 3.19506 | 12.5 | 4060 | 12.5 | 0.05075 | 0.0399382
Isolatie - Steenwol zacht | Begane grond | Isolatie - Steenwol zacht | 10.0239 | 2.97006 | 75 | 4060 | 75 | 0.3045 | 0.222754
Gipsplaat watervast | Begane grond | Gipsplaat watervast | 50.401 | 2.88006 | 12.5 | 4060 | 12.5 | 0.05075 | 0.0360007
2 x Gipsplaat watervast | Begane grond | Gipsplaat watervast | 92.9235 | 5.30992 | 12.5 | 3670 | 12.5 | 0.045875 | 0.0663739
Isolatie - Steenwol zacht | Begane grond | Isolatie - Steenwol zacht | 18.0728 | 5.35492 | 75 | 3670 | 75 | 0.27525 | 0.401619
Gipsplaat watervast | Begane grond | Gipsplaat watervast | 186.139 | 10.6426 | 12.5 | 3670 | 12.5 | 0.045875 | 0.132957
Isolatie - Steenwol zacht | Begane grond | Isolatie - Steenwol zacht | 37.4016 | 11.1002 | 75 | 3670 | 75 | 0.27525 | 0.831147
Gipsplaat watervast | Begane grond | Gipsplaat watervast | 186.934 | 10.6941 | 12.5 | 3670 | 12.5 | 0.045875 | 0.133524
Gipsplaat | Begane grond | Gipsplaat | 64.387 | 6.44225 | 12.5 | 1050 | 12.5 | 0.013125 | 0.0804837
Isolatie - Glaswol zacht | Begane grond | Isolatie - Glaswol zacht | 11.4995 | 6.58892 | 125 | 1050 | 125 | 0.13125 | 0.821393
Gipsplaat | Begane grond | Gipsplaat | 63.575 | 6.36105 | 12.5 | 1050 | 12.5 | 0.013125 | 0.0794687
Gipsplaat watervast | Begane grond | Gipsplaat watervast | 136.399 | 7.79663 | 12.5 | 928 | 12.5 | 0.0116 | 0.0974275
Isolatie - Steenwol zacht | Begane grond | Isolatie - Steenwol zacht | 25.8897 | 7.68559 | 75 | 928 | 75 | 0.0696 | 0.575327
Gipsplaat watervast | Begane grond | Gipsplaat watervast | 133.22 | 7.61499 | 12.5 | 928 | 12.5 | 0.0116 | 0.0951571
Steen - Kalkzandsteen C | Begane grond | Steen - Kalkzandsteen C | 4687.89 | 8.2362 | 300 | 730 | 300 | 0.219 | 2.46731
Isolatie - Steenwol zacht | Begane grond | Isolatie - Steenwol zacht | 74.998 | 8.33311 | 200 | 730 | 200 | 0.146 | 1.66662
_TenW_21_Hout betimmering | Begane grond | _TenW_21_Hout betimmering | 83.727 | 8.45727 | 18 | 730 | 18 | 0.01314 | 0.152231
Gipsplaat watervast | Begane grond | Gipsplaat watervast | 245.503 | 14.0287 | 12.5 | 3630 | 12.5 | 0.045375 | 0.175359
Isolatie - Steenwol zacht | Begane grond | Isolatie - Steenwol zacht | 48.1064 | 14.2537 | 75 | 3630 | 75 | 0.27225 | 1.06903
Gipsplaat watervast | Begane grond | Gipsplaat watervast | 235.413 | 13.4522 | 12.5 | 3630 | 12.5 | 0.045375 | 0.168152
2 x _TenW_21_Hout betimmering | Begane grond | _TenW_21_Hout betimmering | 151.576 | 15.3107 | 18 | 3630 | 18 | 0.06534 | 0.275593
Isolatie - Steenwol zacht | Begane grond | Isolatie - Steenwol zacht | 326.361 | 23.8568 | 304 | 3670 | 304 | 1.11568 | 7.25247
_TenW_21_Steen - Baksteen | Begane grond | _TenW_21_Steen - Baksteen | 754.778 | 23.5868 | 20 | 3670 | 20 | 0.0734 | 0.471736
Steen - Kalkzandsteen C | Begane grond | Steen - Kalkzandsteen C | 7903.69 | 19.4385 | 214 | 3630 | 214 | 0.77682 | 4.15984
Isolatie - Steenwol zacht | Begane grond | Isolatie - Steenwol zacht | 230.395 | 19.3935 | 264 | 3630 | 264 | 0.95832 | 5.11988
_TenW_21_Steen - Baksteen | Begane grond | _TenW_21_Steen - Baksteen | 611.952 | 19.1235 | 20 | 3630 | 20 | 0.0726 | 0.38247
7 x Beton gewapend prefab | Begane grond | Beton gewapend prefab | 2280.95 |  |  |  |  |  | 0.950398
8 x Beton gewapend prefab vloer | Begane grond | Beton gewapend prefab vloer | 1.8576 |  |  |  |  |  | 0.000773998
Beton gewapend prefab | Begane grond | Beton gewapend prefab | 2052.86 |  |  |  |  |  | 0.855358
Steen - Kalkzandsteen C | Begane grond | Steen - Kalkzandsteen C | 230.664 | 0.5673 | 214 | 3050 | 214 | 0.6527 | 0.121402
Isolatie - Steenwol zacht | Begane grond | Isolatie - Steenwol zacht | 10.98 | 1.22 | 200 | 3050 | 200 | 0.61 | 0.244
_TenW_21_Hout betimmering | Begane grond | _TenW_21_Hout betimmering | 19.8079 | 2.0008 | 18 | 3050 | 18 | 0.0549 | 0.0360144
Gipsplaat watervast | Begane grond | Gipsplaat watervast | 128.362 | 7.335 | 12.5 | 3630 | 12.5 | 0.045375 | 0.0916875
Isolatie - Steenwol zacht | Begane grond | Isolatie - Steenwol zacht | 25.8187 | 7.65 | 75 | 3630 | 75 | 0.27225 | 0.57375
Gipsplaat watervast | Begane grond | Gipsplaat watervast | 133.875 | 7.65 | 12.5 | 3630 | 12.5 | 0.045375 | 0.095625
2 x Gipsplaat watervast | Begane grond | Gipsplaat watervast | 57.5422 | 3.28812 | 12.5 | 3530 | 12.5 | 0.044125 | 0.0411016
Isolatie - Steenwol zacht | Begane grond | Isolatie - Steenwol zacht | 11.1282 | 3.29725 | 75 | 3530 | 75 | 0.26475 | 0.247294
Isolatie - Steenwol zacht | Begane grond | Isolatie - Steenwol zacht | 19.7435 | 5.85413 | 75 | 3630 | 75 | 0.27225 | 0.438745
Gipsplaat watervast | Begane grond | Gipsplaat watervast | 225.042 | 12.8595 | 12.5 | 3630 | 12.5 | 0.045375 | 0.160744
Isolatie - Steenwol zacht | Begane grond | Isolatie - Steenwol zacht | 44.616 | 13.2195 | 75 | 3630 | 75 | 0.27225 | 0.991466
Gipsplaat watervast | Begane grond | Gipsplaat watervast | 220.317 | 12.5895 | 12.5 | 3630 | 12.5 | 0.045375 | 0.157369
Gipsplaat watervast | Begane grond | Gipsplaat watervast | 110.992 | 6.35154 | 12.5 | 3630 | 12.5 | 0.045375 | 0.07928
Isolatie - Steenwol zacht | Begane grond | Isolatie - Steenwol zacht | 21.6872 | 6.44412 | 75 | 3630 | 75 | 0.27225 | 0.481938
Gipsplaat watervast | Begane grond | Gipsplaat watervast | 104.322 | 5.96609 | 12.5 | 3630 | 12.5 | 0.045375 | 0.0745158
Gipsplaat watervast | Begane grond | Gipsplaat watervast | 28.0948 | 1.60542 | 12.5 | 3630 | 12.5 | 0.045375 | 0.0200677
Isolatie - Steenwol zacht | Begane grond | Isolatie - Steenwol zacht | 5.72204 | 1.69542 | 75 | 3630 | 75 | 0.27225 | 0.127156
Gipsplaat watervast | Begane grond | Gipsplaat watervast | 39.1198 | 2.23542 | 12.5 | 3630 | 12.5 | 0.045375 | 0.0279427
21 x Beton gewapend prefab | Begane grond | Beton gewapend prefab | 417.137 |  |  |  |  |  | 0.173807
22 x Beton gewapend prefab vloer | Begane grond | Beton gewapend prefab vloer | 0.588825 |  |  |  |  |  | 0.000245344
Beton gewapend prefab | Begane grond | Beton gewapend prefab | 341.294 |  |  |  |  |  | 0.142206
Gipsplaat watervast | Begane grond | Gipsplaat watervast | 115.178 | 6.58764 | 12.5 | 3960 | 12.5 | 0.0495 | 0.0822702
Isolatie - Steenwol zacht | Begane grond | Isolatie - Steenwol zacht | 22.5965 | 6.73142 | 75 | 3960 | 75 | 0.297 | 0.502144
Gipsplaat watervast | Begane grond | Gipsplaat watervast | 116.655 | 6.67205 | 12.5 | 3960 | 12.5 | 0.0495 | 0.0833252
2 x Gipsplaat watervast | Begane grond | Gipsplaat watervast | 189 | 10.8 | 12.5 | 3630 | 12.5 | 0.045375 | 0.135
Isolatie - Steenwol zacht | Begane grond | Isolatie - Steenwol zacht | 36.5924 | 10.8422 | 75 | 3630 | 75 | 0.27225 | 0.813164
Gipsplaat watervast | Begane grond | Gipsplaat watervast | 103.95 | 5.94 | 12.5 | 3630 | 12.5 | 0.045375 | 0.07425
Isolatie - Steenwol zacht | Begane grond | Isolatie - Steenwol zacht | 20.3512 | 6.03 | 75 | 3630 | 75 | 0.27225 | 0.45225
Gipsplaat watervast | Begane grond | Gipsplaat watervast | 99.225 | 5.67 | 12.5 | 3630 | 12.5 | 0.045375 | 0.070875
Gipsplaat watervast | Begane grond | Gipsplaat watervast | 98.1914 | 5.61094 | 12.5 | 3630 | 12.5 | 0.045375 | 0.0701367
Isolatie - Steenwol zacht | Begane grond | Isolatie - Steenwol zacht | 25.2492 | 5.61094 | 100 | 3630 | 100 | 0.363 | 0.561094
Gipsplaat watervast | Begane grond | Gipsplaat watervast | 84.9023 | 4.85156 | 12.5 | 3630 | 12.5 | 0.045375 | 0.0606445
2 x Gipsplaat watervast | Begane grond | Gipsplaat watervast | 37.8 | 2.16 | 12.5 | 3630 | 12.5 | 0.045375 | 0.027
Isolatie - Steenwol zacht | Begane grond | Isolatie - Steenwol zacht | 7.44187 | 2.205 | 75 | 3630 | 75 | 0.27225 | 0.165375
2 x Gipsplaat watervast | Begane grond | Gipsplaat watervast | 35.8295 | 2.0474 | 12.5 | 3630 | 12.5 | 0.045375 | 0.0255925
Isolatie - Steenwol zacht | Begane grond | Isolatie - Steenwol zacht | 6.90998 | 2.0474 | 75 | 3630 | 75 | 0.27225 | 0.153555
Gipsplaat watervast | Begane grond | Gipsplaat watervast | 131.745 | 7.54221 | 12.5 | 3600 | 12.5 | 0.045 | 0.0941038
Isolatie - Steenwol zacht | Begane grond | Isolatie - Steenwol zacht | 25.2796 | 7.5682 | 75 | 3600 | 75 | 0.27 | 0.561769
Gipsplaat watervast | Begane grond | Gipsplaat watervast | 134.944 | 7.72408 | 12.5 | 3600 | 12.5 | 0.045 | 0.0963886
Gipsplaat watervast | Begane grond | Gipsplaat watervast | 42.8575 | 2.4525 | 12.5 | 3630 | 12.5 | 0.045375 | 0.0306125
Isolatie - Steenwol zacht | Begane grond | Isolatie - Steenwol zacht | 8.34806 | 2.4945 | 75 | 3630 | 75 | 0.27225 | 0.185512
Gipsplaat watervast | Begane grond | Gipsplaat watervast | 43.3213 | 2.4775 | 12.5 | 3630 | 12.5 | 0.045375 | 0.0309438
2 x Gipsplaat watervast | Begane grond | Gipsplaat watervast | 52.4051 | 2.99458 | 12.5 | 3630 | 12.5 | 0.045375 | 0.0374322
Isolatie - Steenwol zacht | Begane grond | Isolatie - Steenwol zacht | 10.2586 | 3.03958 | 75 | 3630 | 75 | 0.27225 | 0.227968
Gipsplaat watervast | Begane grond | Gipsplaat watervast | 278.705 | 15.926 | 12.5 | 3630 | 12.5 | 0.045375 | 0.199075
Isolatie - Steenwol zacht | Begane grond | Isolatie - Steenwol zacht | 56.484 | 16.736 | 75 | 3630 | 75 | 0.27225 | 1.2552
Gipsplaat watervast | Begane grond | Gipsplaat watervast | 288.942 | 16.511 | 12.5 | 3630 | 12.5 | 0.045375 | 0.206388
Gipsplaat watervast | Begane grond | Gipsplaat watervast | 86.3671 | 4.94251 | 12.5 | 2700 | 12.5 | 0.03375 | 0.0616908
Isolatie - Steenwol zacht | Begane grond | Isolatie - Steenwol zacht | 16.681 | 4.94251 | 75 | 2700 | 75 | 0.2025 | 0.370688
Gipsplaat watervast | Begane grond | Gipsplaat watervast | 84.3044 | 4.84056 | 12.5 | 2700 | 12.5 | 0.03375 | 0.0602175
_TenW_21_Hout betimmering | Begane grond | _TenW_21_Hout betimmering | 167.562 | 16.9255 | 18 | 3425 | 18 | 0.06165 | 0.304659
Isolatie - Steenwol zacht | Begane grond | Isolatie - Steenwol zacht | 162.35 | 18.0389 | 200 | 3425 | 200 | 0.685 | 3.60779
Steen - Kalkzandsteen C | Begane grond | Steen - Kalkzandsteen C | 7786.2 | 19.1495 | 214 | 3425 | 214 | 0.73295 | 4.098
Steen - Kalkzandsteen C | Begane grond | Steen - Kalkzandsteen C | 1713.78 | 4.21535 | 214 | 3388.27 | 214 | 0.72509 | 0.901991
Isolatie - Steenwol zacht | Begane grond | Isolatie - Steenwol zacht | 37.2728 | 4.14185 | 200 | 3388.27 | 200 | 0.677654 | 0.828284
_TenW_21_Hout betimmering | Begane grond | _TenW_21_Hout betimmering | 45.311 | 4.57691 | 18 | 3388.27 | 18 | 0.0609889 | 0.0823836
Gipsplaat watervast | Begane grond | Gipsplaat watervast | 30.0732 | 1.71847 | 12.5 | 3630 | 12.5 | 0.045375 | 0.0214808
Isolatie - Steenwol zacht | Begane grond | Isolatie - Steenwol zacht | 4.88857 | 1.44847 | 75 | 3630 | 75 | 0.27225 | 0.108635
Gipsplaat watervast | Begane grond | Gipsplaat watervast | 24.5607 | 1.40347 | 12.5 | 3630 | 12.5 | 0.045375 | 0.0175433
2 x Gipsplaat watervast | Begane grond | Gipsplaat watervast | 59.85 | 3.42 | 12.5 | 3630 | 12.5 | 0.045375 | 0.04275
Isolatie - Steenwol zacht | Begane grond | Isolatie - Steenwol zacht | 11.6944 | 3.465 | 75 | 3630 | 75 | 0.27225 | 0.259875
Gipsplaat watervast | Begane grond | Gipsplaat watervast | 222.067 | 12.6896 | 12.5 | 3630 | 12.5 | 0.045375 | 0.158619
Isolatie - Steenwol zacht | Begane grond | Isolatie - Steenwol zacht | 46.4723 | 13.7696 | 75 | 3630 | 75 | 0.27225 | 1.03272
Gipsplaat watervast | Begane grond | Gipsplaat watervast | 237.03 | 13.5446 | 12.5 | 3630 | 12.5 | 0.045375 | 0.169307
Gipsplaat watervast | Begane grond | Gipsplaat watervast | 300.65 | 17.18 | 12.5 | 3630 | 12.5 | 0.045375 | 0.21475
Isolatie - Steenwol zacht | Begane grond | Isolatie - Steenwol zacht | 59.0456 | 17.495 | 75 | 3630 | 75 | 0.27225 | 1.31212
Gipsplaat watervast | Begane grond | Gipsplaat watervast | 305.996 | 17.4975 | 12.5 | 3630 | 12.5 | 0.045375 | 0.218568
Gipsplaat watervast | Begane grond | Gipsplaat watervast | 58.7051 | 3.35458 | 12.5 | 3630 | 12.5 | 0.045375 | 0.0419322
Isolatie - Steenwol zacht | Begane grond | Isolatie - Steenwol zacht | 11.1698 | 3.30958 | 75 | 3630 | 75 | 0.27225 | 0.248218
Gipsplaat watervast | Begane grond | Gipsplaat watervast | 53.1926 | 3.03958 | 12.5 | 3630 | 12.5 | 0.045375 | 0.0379947
Gipsplaat watervast | Begane grond | Gipsplaat watervast | 20.6719 | 1.18125 | 12.5 | 3630 | 12.5 | 0.045375 | 0.0147656
Isolatie - Steenwol zacht | Begane grond | Isolatie - Steenwol zacht | 3.98672 | 1.18125 | 75 | 3630 | 75 | 0.27225 | 0.0885937
Gipsplaat watervast | Begane grond | Gipsplaat watervast | 15.5039 | 0.885938 | 12.5 | 3630 | 12.5 | 0.045375 | 0.0110742
2 x Gipsplaat watervast | Begane grond | Gipsplaat watervast | 102.827 | 5.87582 | 12.5 | 3630 | 12.5 | 0.045375 | 0.0734478
Isolatie - Steenwol zacht | Begane grond | Isolatie - Steenwol zacht | 19.119 | 5.66489 | 75 | 3630 | 75 | 0.27225 | 0.424866
2 x Gipsplaat watervast | Begane grond | Gipsplaat watervast | 97.6589 | 5.58051 | 12.5 | 3630 | 12.5 | 0.045375 | 0.0697564
Isolatie - Steenwol zacht | Begane grond | Isolatie - Steenwol zacht | 19.8309 | 5.87582 | 75 | 3630 | 75 | 0.27225 | 0.440687
Gipsplaat watervast | Begane grond | Gipsplaat watervast | 19.1953 | 1.09688 | 12.5 | 3630 | 12.5 | 0.045375 | 0.0137109
Isolatie - Steenwol zacht | Begane grond | Isolatie - Steenwol zacht | 2.99004 | 0.885938 | 75 | 3630 | 75 | 0.27225 | 0.0664453
Gipsplaat watervast | Begane grond | Gipsplaat watervast | 14.0273 | 0.801562 | 12.5 | 3630 | 12.5 | 0.045375 | 0.0100195
Gipsplaat watervast | Begane grond | Gipsplaat watervast | 362.271 | 20.7012 | 12.5 | 3630 | 12.5 | 0.045375 | 0.258765
Isolatie - Steenwol zacht | Begane grond | Isolatie - Steenwol zacht | 69.8666 | 20.7012 | 75 | 3630 | 75 | 0.27225 | 1.55259
Gipsplaat watervast | Begane grond | Gipsplaat watervast | 356.759 | 20.3862 | 12.5 | 3630 | 12.5 | 0.045375 | 0.254828
Gipsplaat watervast | Begane grond | Gipsplaat watervast | 6.46765 | 0.36958 | 12.5 | 3630 | 12.5 | 0.045375 | 0.00461975
Isolatie - Steenwol zacht | Begane grond | Isolatie - Steenwol zacht | 0.336083 | 0.09958 | 75 | 3630 | 75 | 0.27225 | 0.0074685
Gipsplaat watervast | Begane grond | Gipsplaat watervast | 0.95515 | 0.05458 | 12.5 | 3630 | 12.5 | 0.045375 | 0.00068225
2 x Hout AFW | Begane grond | Hout AFW | 3.85 |  |  | 140 | 25 | 0.0035 | 0.007
2 x Hout AFW | Begane grond | Hout AFW | 11 |  |  | 40 | 250 | 0.01 | 0.02
Gipsplaat watervast | Begane grond | Gipsplaat watervast | 17.8533 | 1.02019 | 12.5 | 1251.49 | 12.5 | 0.0156437 | 0.0127523
Isolatie - Steenwol zacht | Begane grond | Isolatie - Steenwol zacht | 2.74143 | 1.02019 | 75 | 1251.49 | 75 | 0.0938621 | 0.0609207
Gipsplaat watervast | Begane grond | Gipsplaat watervast | 10.5763 | 0.604362 | 12.5 | 1251.49 | 12.5 | 0.0156437 | 0.00755452
Gipsplaat watervast | Begane grond | Gipsplaat watervast | 67.524 | 3.86454 | 12.5 | 3630 | 12.5 | 0.045375 | 0.0482314
Isolatie - Steenwol zacht | Begane grond | Isolatie - Steenwol zacht | 13.1211 | 3.92392 | 75 | 3630 | 75 | 0.27225 | 0.291581
Gipsplaat watervast | Begane grond | Gipsplaat watervast | 66.4817 | 3.80498 | 12.5 | 3630 | 12.5 | 0.045375 | 0.0474869
Gipsplaat watervast | Begane grond | Gipsplaat watervast | 528.325 | 30.19 | 12.5 | 3630 | 12.5 | 0.045375 | 0.377375
Isolatie - Steenwol zacht | Begane grond | Isolatie - Steenwol zacht | 103.714 | 30.73 | 75 | 3630 | 75 | 0.27225 | 2.30475
Gipsplaat watervast | Begane grond | Gipsplaat watervast | 525.175 | 30.01 | 12.5 | 3630 | 12.5 | 0.045375 | 0.375125
Gipsplaat watervast | Begane grond | Gipsplaat watervast | 94.3425 | 5.391 | 12.5 | 3630 | 12.5 | 0.045375 | 0.0673875
Isolatie - Steenwol zacht | Begane grond | Isolatie - Steenwol zacht | 19.2577 | 5.706 | 75 | 3630 | 75 | 0.27225 | 0.42795
Gipsplaat watervast | Begane grond | Gipsplaat watervast | 91.98 | 5.256 | 12.5 | 3630 | 12.5 | 0.045375 | 0.0657
Gipsplaat watervast | Begane grond | Gipsplaat watervast | 287.333 | 16.4191 | 12.5 | 3630 | 12.5 | 0.045375 | 0.205238
Isolatie - Steenwol zacht | Begane grond | Isolatie - Steenwol zacht | 56.9331 | 16.8691 | 75 | 3630 | 75 | 0.27225 | 1.26518
Gipsplaat watervast | Begane grond | Gipsplaat watervast | 294.237 | 16.8136 | 12.5 | 3630 | 12.5 | 0.045375 | 0.210169
Gipsplaat watervast | Begane grond | Gipsplaat watervast | 324.013 | 18.5721 | 12.5 | 3960 | 12.5 | 0.0495 | 0.231438
Isolatie - Steenwol zacht | Begane grond | Isolatie - Steenwol zacht | 65.3078 | 19.5843 | 75 | 3960 | 75 | 0.297 | 1.45128
Gipsplaat watervast | Begane grond | Gipsplaat watervast | 343.309 | 19.6566 | 12.5 | 3960 | 12.5 | 0.0495 | 0.245221
Gipsplaat watervast | Begane grond | Gipsplaat watervast | 32.8695 | 1.88543 | 12.5 | 3940 | 12.5 | 0.04925 | 0.0234782
Isolatie - Steenwol zacht | Begane grond | Isolatie - Steenwol zacht | 7.50872 | 2.30361 | 75 | 3940 | 75 | 0.2955 | 0.16686
Gipsplaat watervast | Begane grond | Gipsplaat watervast | 33.7139 | 1.94339 | 12.5 | 3940 | 12.5 | 0.04925 | 0.0240813
Gipsplaat watervast | Begane grond | Gipsplaat watervast | 69.649 | 4.07769 | 12.5 | 3940 | 12.5 | 0.04925 | 0.0497493
Isolatie - Steenwol zacht | Begane grond | Isolatie - Steenwol zacht | 13.7565 | 4.11558 | 75 | 3940 | 75 | 0.2955 | 0.305699
Gipsplaat watervast | Begane grond | Gipsplaat watervast | 74.1949 | 4.2463 | 12.5 | 3940 | 12.5 | 0.04925 | 0.0529963
2 x Gipsplaat watervast | Begane grond | Gipsplaat watervast | 36.9427 | 2.11101 | 12.5 | 3630 | 12.5 | 0.045375 | 0.0263877
Isolatie - Steenwol zacht | Begane grond | Isolatie - Steenwol zacht | 7.27654 | 2.15601 | 75 | 3630 | 75 | 0.27225 | 0.161701
 | Begane grond |  |  |  |  |  |  |  | 1.2206
Beton gewapend prefab | Begane grond | Beton gewapend prefab | 4799.84 |  |  |  |  |  | 1.99993
Gipsplaat watervast | Begane grond | Gipsplaat watervast | 32.1815 | 1.84448 | 12.5 | 928 | 12.5 | 0.0116 | 0.0229868
Isolatie - Steenwol zacht | Begane grond | Isolatie - Steenwol zacht | 6.4347 | 1.92114 | 75 | 928 | 75 | 0.0696 | 0.142993
Gipsplaat watervast | Begane grond | Gipsplaat watervast | 34.3881 | 1.96746 | 12.5 | 928 | 12.5 | 0.0116 | 0.0245629
2 x Gipsplaat watervast | Begane grond | Gipsplaat watervast | 40.5617 | 2.31781 | 12.5 | 3530 | 12.5 | 0.044125 | 0.0289727
Isolatie - Steenwol zacht | Begane grond | Isolatie - Steenwol zacht | 7.84392 | 2.32412 | 75 | 3530 | 75 | 0.26475 | 0.174309
Steen - Kalkzandsteen C | Begane grond | Steen - Kalkzandsteen C | 5957.71 | 14.6535 | 214 | 3630 | 214 | 0.77682 | 3.13564
Isolatie - Steenwol zacht | Begane grond | Isolatie - Steenwol zacht | 147.001 | 16.3548 | 200 | 3630 | 200 | 0.726 | 3.26669
_TenW_21_Hout betimmering | Begane grond | _TenW_21_Hout betimmering | 186.719 | 18.8605 | 18 | 3630 | 18 | 0.06534 | 0.33949
2 x Gipsplaat watervast | Begane grond | Gipsplaat watervast | 86.1722 | 4.92413 | 12.5 | 3480 | 12.5 | 0.0435 | 0.0615516
Isolatie - Steenwol zacht | Begane grond | Isolatie - Steenwol zacht | 22.1586 | 4.92413 | 100 | 3480 | 100 | 0.348 | 0.492413
Gipsplaat watervast | Begane grond | Gipsplaat watervast | 42.6888 | 2.43936 | 12.5 | 3630 | 12.5 | 0.045375 | 0.030492
Isolatie - Steenwol zacht | Begane grond | Isolatie - Steenwol zacht | 9.29596 | 2.75436 | 75 | 3630 | 75 | 0.27225 | 0.206577
Gipsplaat watervast | Begane grond | Gipsplaat watervast | 48.2013 | 2.75436 | 12.5 | 3630 | 12.5 | 0.045375 | 0.0344295
Gipsplaat watervast | Begane grond | Gipsplaat watervast | 16.5375 | 0.945 | 12.5 | 3630 | 12.5 | 0.045375 | 0.0118125
Isolatie - Steenwol zacht | Begane grond | Isolatie - Steenwol zacht | 2.43 | 0.72 | 75 | 3630 | 75 | 0.27225 | 0.054
Gipsplaat watervast | Begane grond | Gipsplaat watervast | 11.025 | 0.63 | 12.5 | 3630 | 12.5 | 0.045375 | 0.007875
Steen - Kalkzandsteen C | 1e verdieping | Steen - Kalkzandsteen C | 3120.52 | 7.67468 | 214 | 3620 | 214 | 0.77468 | 1.64238
Isolatie - Steenwol zacht | 1e verdieping | Isolatie - Steenwol zacht | 52.7869 | 5.94432 | 200 | 3620 | 200 | 0.724 | 1.17304
_TenW_21_Hout betimmering | 1e verdieping | _TenW_21_Hout betimmering | 48.9575 | 4.9452 | 18 | 3620 | 18 | 0.06516 | 0.0890136
Steen - Kalkzandsteen C | 1e verdieping | Steen - Kalkzandsteen C | 2649.41 | 6.516 | 214 | 3620 | 214 | 0.77468 | 1.39442
Isolatie - Steenwol zacht | 1e verdieping | Isolatie - Steenwol zacht | 68.2069 | 5.74132 | 264 | 3620 | 264 | 0.95568 | 1.51571
_TenW_21_Steen - Baksteen | 1e verdieping | _TenW_21_Steen - Baksteen | 160.554 | 5.01732 | 20 | 3620 | 20 | 0.0724 | 0.100346
Steen - Kalkzandsteen C | 1e verdieping | Steen - Kalkzandsteen C | 17940 | 50.2241 | 214 | 3960 | 214 | 0.84744 | 9.44209
Isolatie - Steenwol zacht | 1e verdieping | Isolatie - Steenwol zacht | 533.741 | 52.6317 | 304 | 3960 | 304 | 1.20384 | 11.8609
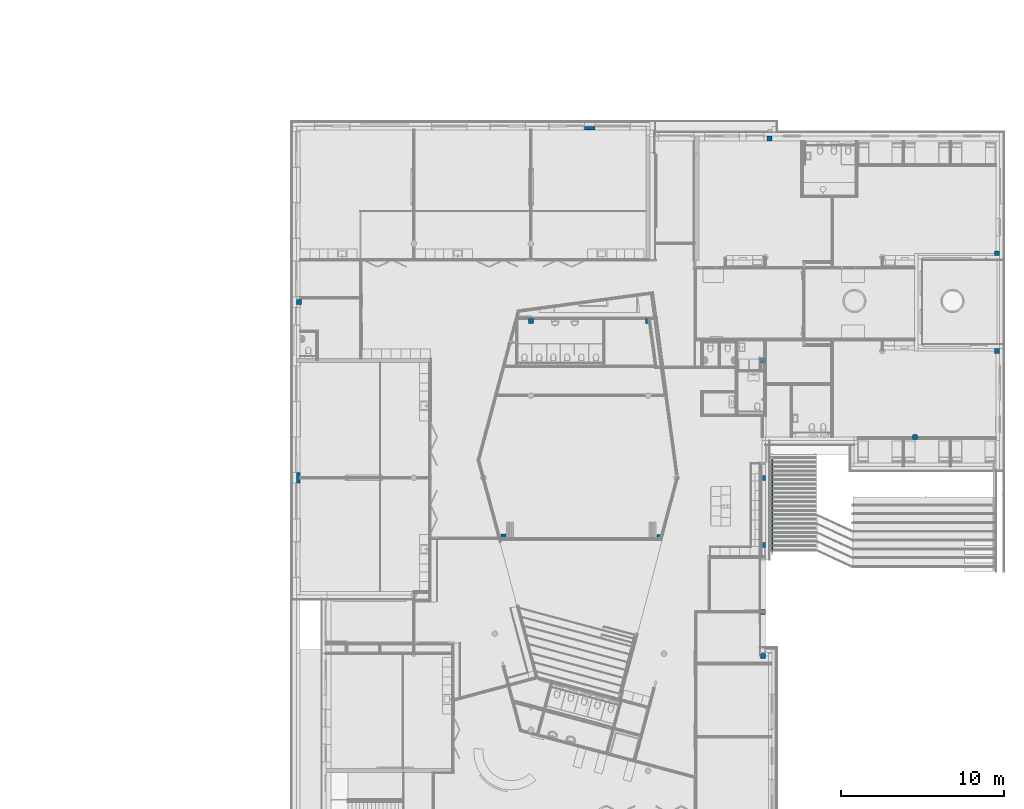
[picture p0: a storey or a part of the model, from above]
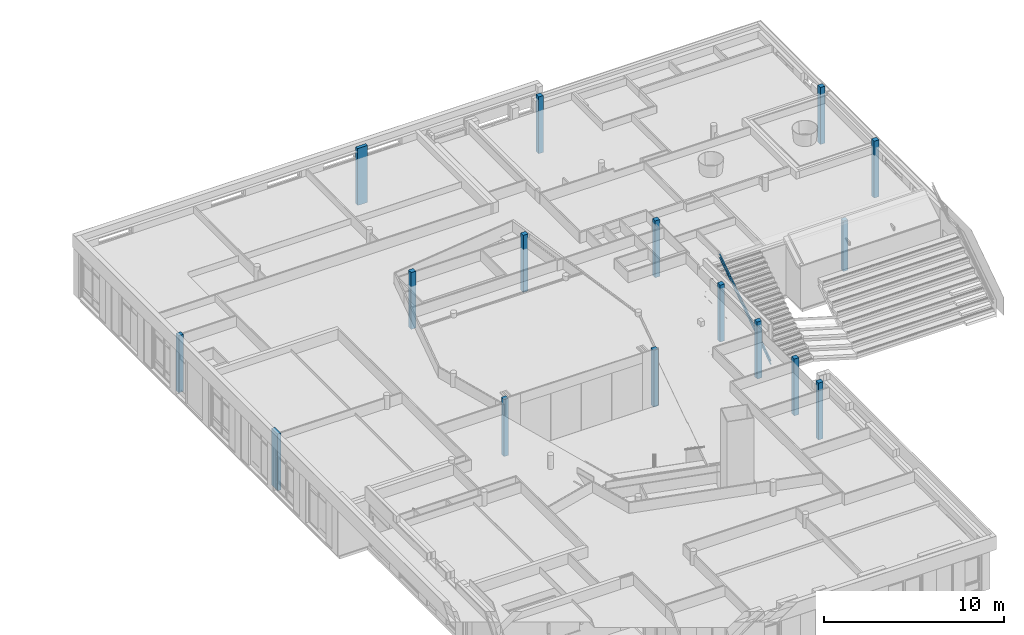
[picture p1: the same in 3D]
Properties of the parts of a building model (IFC2X3), part 2 of 5

# IfcBuildingElementPart (990)
Name | In | Material | Mass (kg) | Projected Component/Skin Area (m2) | Skin Thickness (mm) | Rectangular Component Height (mm) | Rectangular Component Width (mm) | Component Cross Section Area (m2) | Skin/Component Volume (m3)
_TenW_21_Steen - Baksteen | 1e verdieping | _TenW_21_Steen - Baksteen | 830.474 | 25.9523 | 20 | 3960 | 20 | 0.0792 | 0.519046
Steen - Kalkzandsteen C | 1e verdieping | Steen - Kalkzandsteen C | 22809.3 | 56.1127 | 214 | 3960 | 214 | 0.84744 | 12.0049
Isolatie - Steenwol zacht | 1e verdieping | Isolatie - Steenwol zacht | 732.058 | 68.4471 | 304 | 3960 | 304 | 1.20384 | 16.2679
_TenW_21_Steen - Baksteen | 1e verdieping | _TenW_21_Steen - Baksteen | 1313.24 | 41.0387 | 20 | 3960 | 20 | 0.0792 | 0.820773
Steen - Kalkzandsteen C | 1e verdieping | Steen - Kalkzandsteen C | 38285.8 | 94.1846 | 214 | 3960 | 214 | 0.84744 | 20.1504
Isolatie - Steenwol zacht | 1e verdieping | Isolatie - Steenwol zacht | 1201.49 | 113.298 | 304 | 3960 | 304 | 1.20384 | 26.6998
_TenW_21_Steen - Baksteen | 1e verdieping | _TenW_21_Steen - Baksteen | 2133.26 | 66.6643 | 20 | 3960 | 20 | 0.0792 | 1.33329
Steen - Kalkzandsteen C | 1e verdieping | Steen - Kalkzandsteen C | 22179.1 | 54.5628 | 214 | 3960 | 214 | 0.84744 | 11.6732
Isolatie - Steenwol zacht | 1e verdieping | Isolatie - Steenwol zacht | 699.105 | 66.0394 | 304 | 3960 | 304 | 1.20384 | 15.5357
_TenW_21_Steen - Baksteen | 1e verdieping | _TenW_21_Steen - Baksteen | 1308.09 | 40.878 | 20 | 3960 | 20 | 0.0792 | 0.817559
Steen - Kalkzandsteen C | 1e verdieping | Steen - Kalkzandsteen C | 10084.9 | 28.4412 | 214 | 3960 | 214 | 0.84744 | 5.30786
Isolatie - Steenwol zacht | 1e verdieping | Isolatie - Steenwol zacht | 375.287 | 30.2357 | 304 | 3960 | 304 | 1.20384 | 8.33972
_TenW_21_Steen - Baksteen | 1e verdieping | _TenW_21_Steen - Baksteen | 842.803 | 26.3376 | 20 | 3960 | 20 | 0.0792 | 0.526752
4 x Gipsplaat watervast | 1e verdieping | Gipsplaat watervast | 489.835 | 27.9906 | 12.5 | 3960 | 12.5 | 0.0495 | 0.349882
2 x Isolatie - Steenwol zacht | 1e verdieping | Isolatie - Steenwol zacht | 94.6673 | 28.0496 | 75 | 3960 | 75 | 0.297 | 2.10372
Gipsplaat watervast | 1e verdieping | Gipsplaat watervast | 380.892 | 21.7653 | 12.5 | 3960 | 12.5 | 0.0495 | 0.272066
Isolatie - Steenwol zacht | 1e verdieping | Isolatie - Steenwol zacht | 74.374 | 22.0368 | 75 | 3960 | 75 | 0.297 | 1.65276
Gipsplaat watervast | 1e verdieping | Gipsplaat watervast | 381.684 | 21.8105 | 12.5 | 3960 | 12.5 | 0.0495 | 0.272631
2 x Gipsplaat watervast | 1e verdieping | Gipsplaat watervast | 380.1 | 21.72 | 12.5 | 3960 | 12.5 | 0.0495 | 0.2715
Isolatie - Steenwol zacht | 1e verdieping | Isolatie - Steenwol zacht | 73.4577 | 21.7653 | 75 | 3960 | 75 | 0.297 | 1.63239
4 x Gipsplaat watervast | 1e verdieping | Gipsplaat watervast | 22.5185 | 1.28677 | 12.5 | 3960 | 12.5 | 0.0495 | 0.0160846
2 x Isolatie - Steenwol zacht | 1e verdieping | Isolatie - Steenwol zacht | 4.38926 | 1.30052 | 75 | 3960 | 75 | 0.297 | 0.097539
2 x Gipsplaat watervast | 1e verdieping | Gipsplaat watervast | 286.641 | 16.3795 | 12.5 | 3960 | 12.5 | 0.0495 | 0.204744
Isolatie - Steenwol zacht | 1e verdieping | Isolatie - Steenwol zacht | 55.2808 | 16.3795 | 75 | 3960 | 75 | 0.297 | 1.22846
Gipsplaat watervast | 1e verdieping | Gipsplaat watervast | 793.599 | 45.3485 | 12.5 | 3960 | 12.5 | 0.0495 | 0.566856
Isolatie - Steenwol zacht | 1e verdieping | Isolatie - Steenwol zacht | 155.037 | 45.9368 | 75 | 3960 | 75 | 0.297 | 3.44526
Gipsplaat watervast | 1e verdieping | Gipsplaat watervast | 799.142 | 45.6653 | 12.5 | 3960 | 12.5 | 0.0495 | 0.570816
2 x Gipsplaat watervast | 1e verdieping | Gipsplaat watervast | 363.182 | 20.7533 | 12.5 | 3960 | 12.5 | 0.0495 | 0.259416
Isolatie - Steenwol zacht | 1e verdieping | Isolatie - Steenwol zacht | 70.8058 | 20.9795 | 75 | 3960 | 75 | 0.297 | 1.57346
Gipsplaat watervast | 1e verdieping | Gipsplaat watervast | 444.186 | 25.3821 | 12.5 | 3960 | 12.5 | 0.0495 | 0.317276
Isolatie - Steenwol zacht | 1e verdieping | Isolatie - Steenwol zacht | 86.4091 | 25.6027 | 75 | 3960 | 75 | 0.297 | 1.9202
Gipsplaat watervast | 1e verdieping | Gipsplaat watervast | 443.414 | 25.3379 | 12.5 | 3960 | 12.5 | 0.0495 | 0.316724
2 x Gipsplaat watervast | 1e verdieping | Gipsplaat watervast | 442.401 | 25.2801 | 12.5 | 3960 | 12.5 | 0.0495 | 0.316001
Isolatie - Steenwol zacht | 1e verdieping | Isolatie - Steenwol zacht | 85.5156 | 25.3379 | 75 | 3960 | 75 | 0.297 | 1.90035
Gipsplaat watervast | 1e verdieping | Gipsplaat watervast | 443.355 | 25.3346 | 12.5 | 3960 | 12.5 | 0.0495 | 0.316682
Isolatie - Steenwol zacht | 1e verdieping | Isolatie - Steenwol zacht | 85.5042 | 25.3346 | 75 | 3960 | 75 | 0.297 | 1.90009
Gipsplaat watervast | 1e verdieping | Gipsplaat watervast | 442.563 | 25.2893 | 12.5 | 3960 | 12.5 | 0.0495 | 0.316117
Beton gewapend i.h.w. beton | 1e verdieping | Beton gewapend i.h.w. beton | 279956 | 1352.44 | 90 |  |  |  | 121.72
Beton gewapend C vloer | 1e verdieping | Beton gewapend C vloer | 941300 | 1352.44 | 290 |  |  |  | 392.208
Beton gewapend prefab vloer | 1e verdieping | Beton gewapend prefab vloer | 162293 | 1352.44 | 50 |  |  |  | 67.6221
Membraan - waterdicht | 1e verdieping | Membraan - waterdicht | 1319.31 | 251.302 | 5 |  |  |  | 1.25649
Isolatie - Steenwol hard | 1e verdieping | Isolatie - Steenwol hard | 9921.49 | 258.535 | 240 |  |  |  | 62.0093
Beton gewapend C vloer | 1e verdieping | Beton gewapend C vloer | 182451 | 262.143 | 290 |  |  |  | 76.0213
Beton gewapend prefab vloer | 1e verdieping | Beton gewapend prefab vloer | 31457.1 | 262.143 | 50 |  |  |  | 13.1071
Steen - Kalkzandsteen C | 1e verdieping | Steen - Kalkzandsteen C | 7257.81 | 17.85 | 214 | 1630 | 214 | 0.34882 | 3.8199
Isolatie - Steenwol zacht | 1e verdieping | Isolatie - Steenwol zacht | 205.031 | 22.7812 | 200 | 1630 | 200 | 0.326 | 4.55624
_TenW_21_Hout betimmering smal | 1e verdieping | _TenW_21_Hout betimmering smal | 226.49 | 22.8778 | 18 | 1630 | 18 | 0.02934 | 0.411801
Steen - Kalkzandsteen C | 1e verdieping | Steen - Kalkzandsteen C | 2334.42 | 5.74132 | 214 | 4050 | 214 | 0.8667 | 1.22864
Isolatie - Steenwol zacht | 1e verdieping | Isolatie - Steenwol zacht | 50.5197 | 5.6133 | 200 | 4050 | 200 | 0.81 | 1.12266
_TenW_21_Hout betimmering | 1e verdieping | _TenW_21_Hout betimmering | 52.6046 | 5.3136 | 18 | 4050 | 18 | 0.0729 | 0.0956448
Steen - Kalkzandsteen C | 1e verdieping | Steen - Kalkzandsteen C | 792.345 | 1.94871 | 214 | 3960 | 214 | 0.84744 | 0.417024
Isolatie - Steenwol zacht | 1e verdieping | Isolatie - Steenwol zacht | 37.2626 | 2.72387 | 304 | 3960 | 304 | 1.20384 | 0.828058
_TenW_21_Steen - Baksteen | 1e verdieping | _TenW_21_Steen - Baksteen | 125.687 | 3.92771 | 20 | 3960 | 20 | 0.0792 | 0.0785541
Gipsplaat watervast | 1e verdieping | Gipsplaat watervast | 358.573 | 20.6311 | 12.5 | 3950 | 12.5 | 0.049375 | 0.256123
Isolatie - Steenwol zacht | 1e verdieping | Isolatie - Steenwol zacht | 77.2567 | 28.8487 | 75 | 3950 | 75 | 0.29625 | 1.71682
Gipsplaat watervast | 1e verdieping | Gipsplaat watervast | 462.296 | 26.4289 | 12.5 | 3950 | 12.5 | 0.049375 | 0.330212
Gipsplaat watervast | 1e verdieping | Gipsplaat watervast | 223.142 | 12.7571 | 12.5 | 3960 | 12.5 | 0.0495 | 0.159387
Isolatie - Steenwol zacht | 1e verdieping | Isolatie - Steenwol zacht | 43.336 | 12.8767 | 75 | 3960 | 75 | 0.297 | 0.963021
Gipsplaat watervast | 1e verdieping | Gipsplaat watervast | 219.877 | 12.5704 | 12.5 | 3960 | 12.5 | 0.0495 | 0.157055
Gipsplaat watervast | 1e verdieping | Gipsplaat watervast | 328.087 | 18.7539 | 12.5 | 3960 | 12.5 | 0.0495 | 0.234348
Isolatie - Steenwol zacht | 1e verdieping | Isolatie - Steenwol zacht | 64.6212 | 19.1587 | 75 | 3960 | 75 | 0.297 | 1.43603
Gipsplaat watervast | 1e verdieping | Gipsplaat watervast | 328.942 | 18.7967 | 12.5 | 3960 | 12.5 | 0.0495 | 0.234958
Gipsplaat watervast | 1e verdieping | Gipsplaat watervast | 299.621 | 17.1212 | 12.5 | 3960 | 12.5 | 0.0495 | 0.214015
Isolatie - Steenwol zacht | 1e verdieping | Isolatie - Steenwol zacht | 59.6168 | 17.6642 | 75 | 3960 | 75 | 0.297 | 1.32482
Gipsplaat watervast | 1e verdieping | Gipsplaat watervast | 309.916 | 17.7095 | 12.5 | 3960 | 12.5 | 0.0495 | 0.221368
Gipsplaat watervast | 1e verdieping | Gipsplaat watervast | 182.132 | 10.4076 | 12.5 | 3960 | 12.5 | 0.0495 | 0.130095
Isolatie - Steenwol zacht | 1e verdieping | Isolatie - Steenwol zacht | 35.2783 | 10.4528 | 75 | 3960 | 75 | 0.297 | 0.783961
Gipsplaat watervast | 1e verdieping | Gipsplaat watervast | 177.381 | 10.1361 | 12.5 | 3960 | 12.5 | 0.0495 | 0.126701
Gipsplaat watervast | 1e verdieping | Gipsplaat watervast | 516.053 | 29.4887 | 12.5 | 3860 | 12.5 | 0.04825 | 0.368609
Isolatie - Steenwol zacht | 1e verdieping | Isolatie - Steenwol zacht | 99.6158 | 29.5887 | 75 | 3860 | 75 | 0.2895 | 2.21369
Gipsplaat watervast | 1e verdieping | Gipsplaat watervast | 517.803 | 29.5887 | 12.5 | 3860 | 12.5 | 0.04825 | 0.369859
2 x Gipsplaat watervast | 1e verdieping | Gipsplaat watervast | 183.716 | 10.4981 | 12.5 | 3960 | 12.5 | 0.0495 | 0.131226
Isolatie - Steenwol zacht | 1e verdieping | Isolatie - Steenwol zacht | 35.5837 | 10.5433 | 75 | 3960 | 75 | 0.297 | 0.790749
Gipsplaat watervast | 1e verdieping | Gipsplaat watervast | 223.528 | 12.8304 | 12.5 | 3960 | 12.5 | 0.0495 | 0.159663
Isolatie - Steenwol zacht | 1e verdieping | Isolatie - Steenwol zacht | 45.0465 | 13.6086 | 75 | 3960 | 75 | 0.297 | 1.00103
Gipsplaat watervast | 1e verdieping | Gipsplaat watervast | 232.859 | 13.3514 | 12.5 | 3960 | 12.5 | 0.0495 | 0.166328
Gipsplaat watervast | 1e verdieping | Gipsplaat watervast | 105.484 | 6.08804 | 12.5 | 3960 | 12.5 | 0.0495 | 0.075346
Isolatie - Steenwol zacht | 1e verdieping | Isolatie - Steenwol zacht | 21.4396 | 6.71652 | 75 | 3960 | 75 | 0.297 | 0.476436
Gipsplaat watervast | 1e verdieping | Gipsplaat watervast | 110.532 | 6.37923 | 12.5 | 3960 | 12.5 | 0.0495 | 0.0789511
Gipsplaat watervast | 1e verdieping | Gipsplaat watervast | 539.232 | 30.8163 | 12.5 | 3960 | 12.5 | 0.0495 | 0.385165
Isolatie - Steenwol zacht | 1e verdieping | Isolatie - Steenwol zacht | 105.746 | 31.3504 | 75 | 3960 | 75 | 0.297 | 2.3499
Gipsplaat watervast | 1e verdieping | Gipsplaat watervast | 539.932 | 30.8563 | 12.5 | 3960 | 12.5 | 0.0495 | 0.385665
2 x Gipsplaat watervast | 1e verdieping | Gipsplaat watervast | 99.3753 | 5.67859 | 12.5 | 3960 | 12.5 | 0.0495 | 0.0709824
Isolatie - Steenwol zacht | 1e verdieping | Isolatie - Steenwol zacht | 19.4576 | 5.76909 | 75 | 3960 | 75 | 0.297 | 0.432392
Gipsplaat watervast | 1e verdieping | Gipsplaat watervast | 212.222 | 12.127 | 12.5 | 3960 | 12.5 | 0.0495 | 0.151587
Isolatie - Steenwol zacht | 1e verdieping | Isolatie - Steenwol zacht | 41.4186 | 12.462 | 75 | 3960 | 75 | 0.297 | 0.920412
Gipsplaat watervast | 1e verdieping | Gipsplaat watervast | 218.085 | 12.462 | 12.5 | 3960 | 12.5 | 0.0495 | 0.155775
Gipsplaat watervast | 1e verdieping | Gipsplaat watervast | 293.127 | 16.7638 | 12.5 | 3720 | 12.5 | 0.0465 | 0.209376
Isolatie - Steenwol zacht | 1e verdieping | Isolatie - Steenwol zacht | 55.8568 | 16.7437 | 75 | 3720 | 75 | 0.279 | 1.24126
Gipsplaat watervast | 1e verdieping | Gipsplaat watervast | 278.389 | 15.9213 | 12.5 | 3720 | 12.5 | 0.0465 | 0.198849
Gipsplaat watervast | 1e verdieping | Gipsplaat watervast | 54.5899 | 3.11942 | 12.5 | 1000 | 12.5 | 0.0125 | 0.0389928
Isolatie - Steenwol zacht | 1e verdieping | Isolatie - Steenwol zacht | 10.5281 | 3.11942 | 75 | 1000 | 75 | 0.075 | 0.233957
Gipsplaat watervast | 1e verdieping | Gipsplaat watervast | 53.4962 | 3.05692 | 12.5 | 1000 | 12.5 | 0.0125 | 0.0382115
Gipsplaat watervast | 1e verdieping | Gipsplaat watervast | 202.778 | 11.5873 | 12.5 | 3720 | 12.5 | 0.0465 | 0.144841
Isolatie - Steenwol zacht | 1e verdieping | Isolatie - Steenwol zacht | 40.3289 | 11.9493 | 75 | 3720 | 75 | 0.279 | 0.896197
Gipsplaat watervast | 1e verdieping | Gipsplaat watervast | 207.529 | 11.8588 | 12.5 | 3720 | 12.5 | 0.0465 | 0.148235
2 x Gipsplaat watervast | 1e verdieping | Gipsplaat watervast | 215.39 | 12.308 | 12.5 | 3720 | 12.5 | 0.0465 | 0.15385
Isolatie - Steenwol zacht | 1e verdieping | Isolatie - Steenwol zacht | 41.6922 | 12.3532 | 75 | 3720 | 75 | 0.279 | 0.926494
Gipsplaat watervast | 1e verdieping | Gipsplaat watervast | 170.199 | 9.7378 | 12.5 | 3960 | 12.5 | 0.0495 | 0.121571
Isolatie - Steenwol zacht | 1e verdieping | Isolatie - Steenwol zacht | 34.6663 | 10.2715 | 75 | 3960 | 75 | 0.297 | 0.770362
Gipsplaat watervast | 1e verdieping | Gipsplaat watervast | 170.249 | 9.7285 | 12.5 | 3960 | 12.5 | 0.0495 | 0.121606
6 x Gipsplaat watervast | 1e verdieping | Gipsplaat watervast | 236.676 | 13.5243 | 12.5 | 3960 | 12.5 | 0.0495 | 0.169054
3 x Isolatie - Steenwol zacht | 1e verdieping | Isolatie - Steenwol zacht | 45.7973 | 13.5696 | 75 | 3960 | 75 | 0.297 | 1.01772
2 x Gipsplaat watervast | 1e verdieping | Gipsplaat watervast | 151.244 | 8.6425 | 12.5 | 3960 | 12.5 | 0.0495 | 0.108031
Isolatie - Steenwol zacht | 1e verdieping | Isolatie - Steenwol zacht | 30.2375 | 8.95925 | 75 | 3960 | 75 | 0.297 | 0.671944
2 x Gipsplaat watervast | 1e verdieping | Gipsplaat watervast | 202.573 | 11.5756 | 12.5 | 3860 | 12.5 | 0.04825 | 0.144695
Isolatie - Steenwol zacht | 1e verdieping | Isolatie - Steenwol zacht | 39.2204 | 11.6209 | 75 | 3860 | 75 | 0.2895 | 0.871565
Gipsplaat watervast | 1e verdieping | Gipsplaat watervast | 221.485 | 12.6563 | 12.5 | 3960 | 12.5 | 0.0495 | 0.158203
Isolatie - Steenwol zacht | 1e verdieping | Isolatie - Steenwol zacht | 43.7839 | 12.973 | 75 | 3960 | 75 | 0.297 | 0.972976
Gipsplaat watervast | 1e verdieping | Gipsplaat watervast | 222.276 | 12.7015 | 12.5 | 3960 | 12.5 | 0.0495 | 0.158769
Gipsplaat watervast | 1e verdieping | Gipsplaat watervast | 132.965 | 7.59802 | 12.5 | 3960 | 12.5 | 0.0495 | 0.0949753
Isolatie - Steenwol zacht | 1e verdieping | Isolatie - Steenwol zacht | 26.7124 | 7.91477 | 75 | 3960 | 75 | 0.297 | 0.593608
Gipsplaat watervast | 1e verdieping | Gipsplaat watervast | 137.717 | 7.86952 | 12.5 | 3960 | 12.5 | 0.0495 | 0.098369
2 x Gipsplaat watervast | 1e verdieping | Gipsplaat watervast | 72.471 | 4.1412 | 12.5 | 3960 | 12.5 | 0.0495 | 0.051765
2 x Isolatie - Steenwol zacht | 1e verdieping | Isolatie - Steenwol zacht | 13.9765 | 4.1412 | 75 | 3960 | 75 | 0.297 | 0.31059
2 x Gipsplaat watervast | 1e verdieping | Gipsplaat watervast | 67.7197 | 3.8697 | 12.5 | 3960 | 12.5 | 0.0495 | 0.0483712
2 x Gipsplaat watervast | 1e verdieping | Gipsplaat watervast | 61.6966 | 3.52552 | 12.5 | 3720 | 12.5 | 0.0465 | 0.044069
Isolatie - Steenwol zacht | 1e verdieping | Isolatie - Steenwol zacht | 12.2041 | 3.61602 | 75 | 3720 | 75 | 0.279 | 0.271202
Gipsplaat watervast | 1e verdieping | Gipsplaat watervast | 137.35 | 7.85465 | 12.5 | 3960 | 12.5 | 0.0495 | 0.0981074
Isolatie - Steenwol zacht | 1e verdieping | Isolatie - Steenwol zacht | 26.6566 | 7.93462 | 75 | 3960 | 75 | 0.297 | 0.592369
Gipsplaat watervast | 1e verdieping | Gipsplaat watervast | 131.114 | 7.49828 | 12.5 | 3960 | 12.5 | 0.0495 | 0.0936527
Gipsplaat watervast | 1e verdieping | Gipsplaat watervast | 240.639 | 13.76 | 12.5 | 3720 | 12.5 | 0.0465 | 0.171885
Isolatie - Steenwol zacht | 1e verdieping | Isolatie - Steenwol zacht | 48.4835 | 14.3839 | 75 | 3720 | 75 | 0.279 | 1.07741
Gipsplaat watervast | 1e verdieping | Gipsplaat watervast | 252.57 | 14.4356 | 12.5 | 3720 | 12.5 | 0.0465 | 0.180407
Gipsplaat watervast | 1e verdieping | Gipsplaat watervast | 19.1141 | 1.09829 | 12.5 | 3960 | 12.5 | 0.0495 | 0.0136529
Isolatie - Steenwol zacht | 1e verdieping | Isolatie - Steenwol zacht | 3.85388 | 1.17827 | 75 | 3960 | 75 | 0.297 | 0.0856419
Gipsplaat watervast | 1e verdieping | Gipsplaat watervast | 17.6288 | 1.01342 | 12.5 | 3960 | 12.5 | 0.0495 | 0.012592
Gipsplaat watervast | 1e verdieping | Gipsplaat watervast | 231.227 | 13.213 | 12.5 | 3960 | 12.5 | 0.0495 | 0.165162
Isolatie - Steenwol zacht | 1e verdieping | Isolatie - Steenwol zacht | 44.8993 | 13.3035 | 75 | 3960 | 75 | 0.297 | 0.997762
Gipsplaat watervast | 1e verdieping | Gipsplaat watervast | 227.268 | 12.9867 | 12.5 | 3960 | 12.5 | 0.0495 | 0.162334
Gipsplaat watervast | 1e verdieping | Gipsplaat watervast | 173.209 | 9.90373 | 12.5 | 3960 | 12.5 | 0.0495 | 0.123721
Isolatie - Steenwol zacht | 1e verdieping | Isolatie - Steenwol zacht | 33.8587 | 10.0686 | 75 | 3960 | 75 | 0.297 | 0.752415
Gipsplaat watervast | 1e verdieping | Gipsplaat watervast | 174.694 | 9.9886 | 12.5 | 3960 | 12.5 | 0.0495 | 0.124782
Gipsplaat watervast | 1e verdieping | Gipsplaat watervast | 9.52986 | 0.585516 | 12.5 | 3720 | 12.5 | 0.0465 | 0.00680704
Isolatie - Steenwol zacht | 1e verdieping | Isolatie - Steenwol zacht | 0.870396 | 0.503611 | 75 | 3720 | 75 | 0.279 | 0.0193421
Gipsplaat watervast | 1e verdieping | Gipsplaat watervast | 0.0158473 | 0.0121794 | 12.5 | 3720 | 12.5 | 0.0465 | 0.0000113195
2 x Gipsplaat watervast | 1e verdieping | Gipsplaat watervast | 309.165 | 17.6666 | 12.5 | 5260 | 12.5 | 0.06575 | 0.220832
Isolatie - Steenwol zacht | 1e verdieping | Isolatie - Steenwol zacht | 59.6247 | 17.6666 | 75 | 5260 | 75 | 0.3945 | 1.32499
Gipsplaat watervast | 1e verdieping | Gipsplaat watervast | 133.509 | 7.64213 | 12.5 | 3960 | 12.5 | 0.0495 | 0.0953633
Isolatie - Steenwol zacht | 1e verdieping | Isolatie - Steenwol zacht | 25.8803 | 7.74663 | 75 | 3960 | 75 | 0.297 | 0.575119
Gipsplaat watervast | 1e verdieping | Gipsplaat watervast | 125.557 | 7.18775 | 12.5 | 3960 | 12.5 | 0.0495 | 0.0896836
2 x Gipsplaat watervast | 1e verdieping | Gipsplaat watervast | 205.603 | 11.7487 | 12.5 | 3960 | 12.5 | 0.0495 | 0.146859
Isolatie - Steenwol zacht | 1e verdieping | Isolatie - Steenwol zacht | 39.8596 | 11.8102 | 75 | 3960 | 75 | 0.297 | 0.885769
Gipsplaat watervast | 1e verdieping | Gipsplaat watervast | 199.832 | 11.4764 | 12.5 | 3960 | 12.5 | 0.0495 | 0.142737
Isolatie - Steenwol zacht | 1e verdieping | Isolatie - Steenwol zacht | 36.5866 | 11.1849 | 75 | 3960 | 75 | 0.297 | 0.813036
Gipsplaat watervast | 1e verdieping | Gipsplaat watervast | 193.881 | 11.1363 | 12.5 | 3960 | 12.5 | 0.0495 | 0.138487
Gipsplaat watervast | 1e verdieping | Gipsplaat watervast | 273.293 | 15.6167 | 12.5 | 2150 | 12.5 | 0.026875 | 0.195209
Isolatie - Steenwol zacht | 1e verdieping | Isolatie - Steenwol zacht | 55.8234 | 18.8428 | 75 | 2150 | 75 | 0.16125 | 1.24052
Gipsplaat watervast | 1e verdieping | Gipsplaat watervast | 328.26 | 18.7618 | 12.5 | 2150 | 12.5 | 0.026875 | 0.234471
Gipsplaat watervast | 1e verdieping | Gipsplaat watervast | 314.247 | 18.3135 | 12.5 | 2150 | 12.5 | 0.026875 | 0.224462
Isolatie - Steenwol zacht | 1e verdieping | Isolatie - Steenwol zacht | 68.5122 | 21.4787 | 75 | 2150 | 75 | 0.16125 | 1.52249
Gipsplaat watervast | 1e verdieping | Gipsplaat watervast | 375.723 | 21.4705 | 12.5 | 2150 | 12.5 | 0.026875 | 0.268373
Steen - Kalkzandsteen C | 1e verdieping | Steen - Kalkzandsteen C | 5903.85 | 14.52 | 214 | 1200 | 214 | 0.2568 | 3.10729
Isolatie - Steenwol zacht | 1e verdieping | Isolatie - Steenwol zacht | 130.68 | 14.52 | 200 | 1200 | 200 | 0.24 | 2.90401
_TenW_21_Hout betimmering | 1e verdieping | _TenW_21_Hout betimmering | 143.748 | 14.52 | 18 | 1200 | 18 | 0.0216 | 0.261361
Steen - Kalkzandsteen C | 1e verdieping | Steen - Kalkzandsteen C | 1586.73 | 10.9028 | 214 | 526 | 214 | 0.112564 | 0.835121
Isolatie - Steenwol zacht | 1e verdieping | Isolatie - Steenwol zacht | 149.15 | 10.9028 | 304 | 526 | 304 | 0.159904 | 3.31445
_TenW_21_Steen - Baksteen | 1e verdieping | _TenW_21_Steen - Baksteen | 348.89 | 10.9028 | 20 | 526 | 20 | 0.01052 | 0.218056
Metaal - Staal AFW | 1e verdieping | Metaal - Staal AFW | 823.617 |  |  |  |  |  | 0.1036
Glas | 1e verdieping | Glas | 162.571 |  |  |  |  |  | 0.0745739
Metaal - Staal AFW | 1e verdieping | Metaal - Staal AFW | 834.627 |  |  |  |  |  | 0.104984
Glas | 1e verdieping | Glas | 165.943 |  |  |  |  |  | 0.0761206
Metaal - Staal AFW | 1e verdieping | Metaal - Staal AFW | 180.776 |  |  |  |  |  | 0.0227391
Glas | 1e verdieping | Glas | 49.9363 |  |  |  |  |  | 0.0229066
2 x Metaal - Staal AFW | 1e verdieping | Metaal - Staal AFW | 181.837 |  |  |  |  |  | 0.0228726
2 x Glas | 1e verdieping | Glas | 51.298 |  |  |  |  |  | 0.0235312
Metaal - Staal AFW | 1e verdieping | Metaal - Staal AFW | 182.885 |  |  |  |  |  | 0.0230044
Glas | 1e verdieping | Glas | 51.011 |  |  |  |  |  | 0.0233995
Gipsplaat watervast | 1e verdieping | Gipsplaat watervast | 35.9751 | 2.06491 | 12.5 | 3720 | 12.5 | 0.0465 | 0.0256965
Isolatie - Steenwol zacht | 1e verdieping | Isolatie - Steenwol zacht | 8.09717 | 2.41755 | 75 | 3720 | 75 | 0.279 | 0.179937
Gipsplaat watervast | 1e verdieping | Gipsplaat watervast | 40.019 | 2.28986 | 12.5 | 3720 | 12.5 | 0.0465 | 0.028585
Gipsplaat watervast | 1e verdieping | Gipsplaat watervast | 134.55 | 7.68859 | 12.5 | 3960 | 12.5 | 0.0495 | 0.0961074
Isolatie - Steenwol zacht | 1e verdieping | Isolatie - Steenwol zacht | 26.4071 | 7.82434 | 75 | 3960 | 75 | 0.297 | 0.586825
Gipsplaat watervast | 1e verdieping | Gipsplaat watervast | 140.093 | 8.00534 | 12.5 | 3960 | 12.5 | 0.0495 | 0.100067
Gipsplaat watervast | 1e verdieping | Gipsplaat watervast | 176.409 | 10.0819 | 12.5 | 3960 | 12.5 | 0.0495 | 0.126006
Isolatie - Steenwol zacht | 1e verdieping | Isolatie - Steenwol zacht | 35.1839 | 10.4545 | 75 | 3960 | 75 | 0.297 | 0.781864
Gipsplaat watervast | 1e verdieping | Gipsplaat watervast | 176.749 | 10.1031 | 12.5 | 3960 | 12.5 | 0.0495 | 0.126249
Gipsplaat watervast | 1e verdieping | Gipsplaat watervast | 328.628 | 18.7788 | 12.5 | 3960 | 12.5 | 0.0495 | 0.234734
Isolatie - Steenwol zacht | 1e verdieping | Isolatie - Steenwol zacht | 64.2946 | 19.0503 | 75 | 3960 | 75 | 0.297 | 1.42877
Gipsplaat watervast | 1e verdieping | Gipsplaat watervast | 327.836 | 18.7335 | 12.5 | 3960 | 12.5 | 0.0495 | 0.234169
2 x Gipsplaat watervast | 1e verdieping | Gipsplaat watervast | 220.114 | 12.5779 | 12.5 | 3960 | 12.5 | 0.0495 | 0.157224
Isolatie - Steenwol zacht | 1e verdieping | Isolatie - Steenwol zacht | 42.6581 | 12.6395 | 75 | 3960 | 75 | 0.297 | 0.947959
Steen - Kalkzandsteen C | 1e verdieping | Steen - Kalkzandsteen C | 715.34 | 1.75932 | 214 | 3960 | 214 | 0.84744 | 0.376494
Isolatie - Steenwol zacht | 1e verdieping | Isolatie - Steenwol zacht | 34.6718 | 2.53449 | 304 | 3960 | 304 | 1.20384 | 0.770484
_TenW_21_Steen - Baksteen | 1e verdieping | _TenW_21_Steen - Baksteen | 119.626 | 3.73832 | 20 | 3960 | 20 | 0.0792 | 0.0747664
Gipsplaat watervast | 1e verdieping | Gipsplaat watervast | 7.42149 | 0.42715 | 12.5 | 3960 | 12.5 | 0.0495 | 0.00530107
Isolatie - Steenwol zacht | 1e verdieping | Isolatie - Steenwol zacht | 1.6578 | 0.509584 | 75 | 3960 | 75 | 0.297 | 0.0368399
Gipsplaat watervast | 1e verdieping | Gipsplaat watervast | 13.766 | 0.789692 | 12.5 | 3960 | 12.5 | 0.0495 | 0.00983284
Gipsplaat watervast | 1e verdieping | Gipsplaat watervast | 14.5882 | 0.836673 | 12.5 | 3720 | 12.5 | 0.0465 | 0.0104201
Isolatie - Steenwol zacht | 1e verdieping | Isolatie - Steenwol zacht | 2.74243 | 0.830958 | 75 | 3720 | 75 | 0.279 | 0.0609429
Gipsplaat watervast | 1e verdieping | Gipsplaat watervast | 8.29428 | 0.477023 | 12.5 | 3720 | 12.5 | 0.0465 | 0.00592448
Gipsplaat watervast | 1e verdieping | Gipsplaat watervast | 145.013 | 8.28468 | 12.5 |  |  | 0.0424562 | 0.103581
Hout C | 1e verdieping | Hout C | 32.2978 | 8.38443 | 7 |  |  | 0.0237755 | 0.0587233
Isolatie - Steenwol zacht | 1e verdieping | Isolatie - Steenwol zacht | 135.295 | 10.1856 | 300 |  |  | 1.01895 | 3.00656
Hout C | 1e verdieping | Hout C | 44.9396 | 11.666 | 7 |  |  | 0.0237755 | 0.0817084
Hout C | 1e verdieping | Hout C | 182.69 | 11.8707 | 28 |  |  | 0.0951018 | 0.332164
_TenW_21_Hout betimmering | 1e verdieping | _TenW_21_Hout betimmering | 111.775 | 11.2921 | 18 |  |  | 0.0611369 | 0.203227
Gipsplaat watervast | 1e verdieping | Gipsplaat watervast | 127.697 | 7.29296 | 12.5 |  |  | 0.0424562 | 0.0912125
Hout C | 1e verdieping | Hout C | 28.4101 | 7.3738 | 7 |  |  | 0.0237755 | 0.0516547
Isolatie - Steenwol zacht | 1e verdieping | Isolatie - Steenwol zacht | 116.866 | 8.7395 | 300 |  |  | 1.01895 | 2.59701
Hout C | 1e verdieping | Hout C | 38.1812 | 9.90993 | 7 |  |  | 0.0237755 | 0.0694204
Hout C | 1e verdieping | Hout C | 154.906 | 10.0587 | 28 |  |  | 0.0951018 | 0.281648
_TenW_21_Hout betimmering | 1e verdieping | _TenW_21_Hout betimmering | 93.2706 | 9.41845 | 18 |  |  | 0.0611369 | 0.169583
Gipsplaat watervast | 1e verdieping | Gipsplaat watervast | 145.07 | 8.29576 | 12.5 | 3960 | 12.5 | 0.0495 | 0.103621
Isolatie - Steenwol zacht | 1e verdieping | Isolatie - Steenwol zacht | 28.1453 | 8.37573 | 75 | 3960 | 75 | 0.297 | 0.625452
Gipsplaat watervast | 1e verdieping | Gipsplaat watervast | 143.584 | 8.21089 | 12.5 | 3960 | 12.5 | 0.0495 | 0.10256
_TenW_21_Steen - Baksteen | 1e verdieping | _TenW_21_Steen - Baksteen | 41.6416 | 1.3013 | 20 | 910 | 20 | 0.0182 | 0.026026
Isolatie - Steenwol zacht | 1e verdieping | Isolatie - Steenwol zacht | 15.4594 | 1.3013 | 264 | 910 | 264 | 0.24024 | 0.343543
Steen - Kalkzandsteen C | 1e verdieping | Steen - Kalkzandsteen C | 279.09 | 0.6864 | 214 | 910 | 214 | 0.19474 | 0.14689
Gipsplaat watervast | 1e verdieping | Gipsplaat watervast | 326.222 | 18.8286 | 12.5 | 3720 | 12.5 | 0.0465 | 0.233015
Isolatie - Steenwol zacht | 1e verdieping | Isolatie - Steenwol zacht | 68.6656 | 20.6708 | 75 | 3720 | 75 | 0.279 | 1.5259
Gipsplaat watervast | 1e verdieping | Gipsplaat watervast | 357.672 | 20.5047 | 12.5 | 3720 | 12.5 | 0.0465 | 0.25548
Steen - Kalkzandsteen C | 1e verdieping | Steen - Kalkzandsteen C | 11730.7 | 28.8508 | 214 | 1630 | 214 | 0.34882 | 6.17407
Isolatie - Steenwol zacht | 1e verdieping | Isolatie - Steenwol zacht | 321.904 | 35.7671 | 200 | 1630 | 200 | 0.326 | 7.15342
_TenW_21_Hout betimmering smal | 1e verdieping | _TenW_21_Hout betimmering smal | 358.225 | 36.1844 | 18 | 1630 | 18 | 0.02934 | 0.651319
Gipsplaat watervast | 1e verdieping | Gipsplaat watervast | 72.0879 | 4.12537 | 12.5 | 3960 | 12.5 | 0.0495 | 0.0514914
Isolatie - Steenwol zacht | 1e verdieping | Isolatie - Steenwol zacht | 14.0703 | 4.20534 | 75 | 3960 | 75 | 0.297 | 0.312673
Gipsplaat watervast | 1e verdieping | Gipsplaat watervast | 70.1826 | 4.0165 | 12.5 | 3960 | 12.5 | 0.0495 | 0.0501304
Gipsplaat watervast | 1e verdieping | Gipsplaat watervast | 276.637 | 15.8078 | 12.5 | 3630 | 12.5 | 0.045375 | 0.197598
Isolatie - Steenwol zacht | 1e verdieping | Isolatie - Steenwol zacht | 53.3902 | 15.8193 | 75 | 3630 | 75 | 0.27225 | 1.18645
Gipsplaat watervast | 1e verdieping | Gipsplaat watervast | 271.584 | 15.5191 | 12.5 | 3630 | 12.5 | 0.045375 | 0.193988
Gipsplaat watervast | 1e verdieping | Gipsplaat watervast | 198.551 | 11.3458 | 12.5 | 3630 | 12.5 | 0.045375 | 0.141822
Isolatie - Steenwol zacht | 1e verdieping | Isolatie - Steenwol zacht | 38.5899 | 11.434 | 75 | 3630 | 75 | 0.27225 | 0.857554
Gipsplaat watervast | 1e verdieping | Gipsplaat watervast | 193.918 | 11.081 | 12.5 | 3630 | 12.5 | 0.045375 | 0.138513
2 x Gipsplaat watervast | 1e verdieping | Gipsplaat watervast | 236.435 | 13.5106 | 12.5 | 3960 | 12.5 | 0.0495 | 0.168882
Gipsplaat watervast | 1e verdieping | Gipsplaat watervast | 333.624 | 19.0643 | 12.5 | 3630 | 12.5 | 0.045375 | 0.238303
Isolatie - Steenwol zacht | 1e verdieping | Isolatie - Steenwol zacht | 65.5332 | 19.4172 | 75 | 3630 | 75 | 0.27225 | 1.45629
Gipsplaat watervast | 1e verdieping | Gipsplaat watervast | 343.663 | 19.6379 | 12.5 | 3630 | 12.5 | 0.045375 | 0.245473
2 x Gipsplaat watervast | 1e verdieping | Gipsplaat watervast | 98.7148 | 5.64243 | 12.5 | 3720 | 12.5 | 0.0465 | 0.0705106
Isolatie - Steenwol zacht | 1e verdieping | Isolatie - Steenwol zacht | 18.2738 | 5.42394 | 75 | 3720 | 75 | 0.279 | 0.406084
Gipsplaat watervast | 1e verdieping | Gipsplaat watervast | 107.738 | 6.1703 | 12.5 | 3960 | 12.5 | 0.0495 | 0.0769556
Isolatie - Steenwol zacht | 1e verdieping | Isolatie - Steenwol zacht | 21.544 | 6.46651 | 75 | 3960 | 75 | 0.297 | 0.478755
Gipsplaat watervast | 1e verdieping | Gipsplaat watervast | 116.291 | 6.65906 | 12.5 | 3960 | 12.5 | 0.0495 | 0.0830651
Gipsplaat watervast | 1e verdieping | Gipsplaat watervast | 127.264 | 7.31351 | 12.5 |  |  | 0.0427878 | 0.0909026
Hout C | 1e verdieping | Hout C | 28.5173 | 7.40334 | 7 |  |  | 0.0239612 | 0.0518496
Isolatie - Steenwol zacht | 1e verdieping | Isolatie - Steenwol zacht | 119.91 | 9.04273 | 300 |  |  | 1.02691 | 2.66468
Hout C | 1e verdieping | Hout C | 39.9451 | 10.3699 | 7 |  |  | 0.0239612 | 0.0726274
Hout C | 1e verdieping | Hout C | 162.435 | 10.5563 | 28 |  |  | 0.0958447 | 0.295337
_TenW_21_Hout betimmering | 1e verdieping | _TenW_21_Hout betimmering | 98.5202 | 9.95426 | 18 |  |  | 0.0616145 | 0.179128
Gipsplaat watervast | 1e verdieping | Gipsplaat watervast | 110.994 | 6.38164 | 12.5 |  |  | 0.0427878 | 0.0792813
Hout C | 1e verdieping | Hout C | 24.8621 | 6.45312 | 7 |  |  | 0.0239612 | 0.0452039
Isolatie - Steenwol zacht | 1e verdieping | Isolatie - Steenwol zacht | 102.429 | 7.66972 | 300 |  |  | 1.02691 | 2.27619
Hout C | 1e verdieping | Hout C | 33.4948 | 8.69382 | 7 |  |  | 0.0239612 | 0.0608997
Hout C | 1e verdieping | Hout C | 135.901 | 8.82561 | 28 |  |  | 0.0958447 | 0.247093
_TenW_21_Hout betimmering | 1e verdieping | _TenW_21_Hout betimmering | 80.834 | 8.16336 | 18 |  |  | 0.0616145 | 0.146971
Isolatie - Steenwol zacht | 1e verdieping | Isolatie - Steenwol zacht | 45.6446 | 13.5243 | 75 | 3960 | 75 | 0.297 | 1.01432
2 x Gipsplaat watervast | 1e verdieping | Gipsplaat watervast | 210.035 | 12.002 | 12.5 | 3630 | 12.5 | 0.045375 | 0.150025
Isolatie - Steenwol zacht | 1e verdieping | Isolatie - Steenwol zacht | 40.6557 | 12.0461 | 75 | 3630 | 75 | 0.27225 | 0.903459
6 x Hout AFW | 1e verdieping | Hout AFW | 3.85 |  |  | 140 | 25 | 0.0035 | 0.007
6 x Hout AFW | 1e verdieping | Hout AFW | 11 |  |  | 40 | 250 | 0.01 | 0.02
Gipsplaat watervast | 1e verdieping | Gipsplaat watervast | 37.5394 | 2.17276 | 12.5 | 3960 | 12.5 | 0.0495 | 0.0268138
Isolatie - Steenwol zacht | 1e verdieping | Isolatie - Steenwol zacht | 8.9431 | 2.743 | 75 | 3960 | 75 | 0.297 | 0.198735
Gipsplaat watervast | 1e verdieping | Gipsplaat watervast | 41.8937 | 2.40946 | 12.5 | 3960 | 12.5 | 0.0495 | 0.0299241
Gipsplaat watervast | 1e verdieping | Gipsplaat watervast | 76.9069 | 4.40681 | 12.5 | 3960 | 12.5 | 0.0495 | 0.0549335
Isolatie - Steenwol zacht | 1e verdieping | Isolatie - Steenwol zacht | 14.0415 | 4.2332 | 75 | 3960 | 75 | 0.297 | 0.312034
Gipsplaat watervast | 1e verdieping | Gipsplaat watervast | 66.417 | 3.80738 | 12.5 | 3960 | 12.5 | 0.0495 | 0.0474407
Gipsplaat watervast | 1e verdieping | Gipsplaat watervast | 74.1396 | 4.23961 | 12.5 | 3860 | 12.5 | 0.04825 | 0.0529569
Isolatie - Steenwol zacht | 1e verdieping | Isolatie - Steenwol zacht | 14.7586 | 4.3913 | 75 | 3860 | 75 | 0.2895 | 0.327968
Gipsplaat watervast | 1e verdieping | Gipsplaat watervast | 70.0957 | 4.01466 | 12.5 | 3860 | 12.5 | 0.04825 | 0.0500684
2 x Beton gewapend prefab | 1e verdieping | Beton gewapend prefab | 2851.2 |  |  |  |  |  | 1.188
3 x Beton gewapend prefab vloer | 1e verdieping | Beton gewapend prefab vloer | 2.3328 |  |  |  |  |  | 0.000972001
Beton gewapend prefab | 1e verdieping | Beton gewapend prefab | 2566.08 |  |  |  |  |  | 1.0692
Gipsplaat watervast | 1e verdieping | Gipsplaat watervast | 23.2707 | 1.35565 | 12.5 | 3960 | 12.5 | 0.0495 | 0.0166219
Isolatie - Steenwol zacht | 1e verdieping | Isolatie - Steenwol zacht | 5.25243 | 1.71165 | 75 | 3960 | 75 | 0.297 | 0.116721
Gipsplaat watervast | 1e verdieping | Gipsplaat watervast | 29.6152 | 1.71819 | 12.5 | 3960 | 12.5 | 0.0495 | 0.0211537
Gipsplaat watervast | 1e verdieping | Gipsplaat watervast | 371.155 | 21.2183 | 12.5 | 3720 | 12.5 | 0.0465 | 0.265111
Isolatie - Steenwol zacht | 1e verdieping | Isolatie - Steenwol zacht | 70.9191 | 21.3714 | 75 | 3720 | 75 | 0.279 | 1.57598
Gipsplaat watervast | 1e verdieping | Gipsplaat watervast | 367.769 | 21.0251 | 12.5 | 3720 | 12.5 | 0.0465 | 0.262692
Gipsplaat watervast | 1e verdieping | Gipsplaat watervast | 97.1169 | 5.55514 | 12.5 | 3960 | 12.5 | 0.0495 | 0.0693692
Isolatie - Steenwol zacht | 1e verdieping | Isolatie - Steenwol zacht | 18.1409 | 5.40915 | 75 | 3960 | 75 | 0.297 | 0.403132
Gipsplaat watervast | 1e verdieping | Gipsplaat watervast | 93.2059 | 5.33168 | 12.5 | 3960 | 12.5 | 0.0495 | 0.0665756
2 x Gipsplaat watervast | 1e verdieping | Gipsplaat watervast | 214.262 | 12.2436 | 12.5 | 3960 | 12.5 | 0.0495 | 0.153045
Isolatie - Steenwol zacht | 1e verdieping | Isolatie - Steenwol zacht | 41.3685 | 12.2573 | 75 | 3960 | 75 | 0.297 | 0.919299
Gipsplaat watervast | 1e verdieping | Gipsplaat watervast | 313.987 | 17.9421 | 12.5 | 3960 | 12.5 | 0.0495 | 0.224277
Isolatie - Steenwol zacht | 1e verdieping | Isolatie - Steenwol zacht | 60.842 | 18.0273 | 75 | 3960 | 75 | 0.297 | 1.35204
Gipsplaat watervast | 1e verdieping | Gipsplaat watervast | 304.485 | 17.3991 | 12.5 | 3960 | 12.5 | 0.0495 | 0.217489
2 x Gipsplaat watervast | 1e verdieping | Gipsplaat watervast | 201.088 | 11.4969 | 12.5 | 3960 | 12.5 | 0.0495 | 0.143634
Isolatie - Steenwol zacht | 1e verdieping | Isolatie - Steenwol zacht | 39.7059 | 11.7647 | 75 | 3960 | 75 | 0.297 | 0.882353
2 x Gipsplaat watervast | 1e verdieping | Gipsplaat watervast | 273.33 | 15.625 | 12.5 | 3720 | 12.5 | 0.0465 | 0.195236
Isolatie - Steenwol zacht | 1e verdieping | Isolatie - Steenwol zacht | 53.0219 | 15.747 | 75 | 3720 | 75 | 0.279 | 1.17827
Gipsplaat watervast | 1e verdieping | Gipsplaat watervast | 45.0101 | 2.57533 | 12.5 | 3960 | 12.5 | 0.0495 | 0.0321501
Isolatie - Steenwol zacht | 1e verdieping | Isolatie - Steenwol zacht | 9.13773 | 2.91542 | 75 | 3960 | 75 | 0.297 | 0.203061
Gipsplaat watervast | 1e verdieping | Gipsplaat watervast | 42.42 | 2.45322 | 12.5 | 3960 | 12.5 | 0.0495 | 0.0303
2 x Membraan - waterdicht | 2e verdieping | Membraan - waterdicht | 23.1863 |  |  |  |  | 0.000928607 | 0.0220822
2 x Hout - Multiplex | 2e verdieping | Hout - Multiplex | 98.2911 |  |  |  |  | 0.0091686 | 0.140416
2 x Hout C | 2e verdieping | Hout C | 61.808 |  |  |  |  | 0.00385343 | 0.112378
2 x Hout C | 2e verdieping | Hout C | 62.2302 |  |  |  |  | 0.00387961 | 0.113146
2 x Hout - Multiplex | 2e verdieping | Hout - Multiplex | 27.912 |  |  |  |  | 0.00136581 | 0.0398743
2 x Isolatie - Glaswol zacht | 2e verdieping | Isolatie - Glaswol zacht | 11.3485 |  |  |  |  | 0.0519974 | 0.810606
2 x Isolatie - Glaswol zacht | 2e verdieping | Isolatie - Glaswol zacht | 64.5809 |  |  | 509.061 | 304 | 0.154754 | 4.61292
2 x Hout - Multiplex | 2e verdieping | Hout - Multiplex | 171.89 |  |  |  |  | 0.00822821 | 0.245558
2 x _TenW_21_Steen - Baksteen | 2e verdieping | _TenW_21_Steen - Baksteen | 486.222 |  |  | 509.061 | 20 | 0.0101812 | 0.303889
2 x Metaal - Aluminium | 2e verdieping | Metaal - Aluminium | 23.3288 |  |  |  |  | 0.00027895 | 0.00833172
2 x Membraan - waterdicht | 2e verdieping | Membraan - waterdicht | 39.3971 |  |  |  |  | 0.000928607 | 0.0375211
2 x Hout - Multiplex | 2e verdieping | Hout - Multiplex | 170.122 |  |  |  |  | 0.0091686 | 0.243032
2 x Hout C | 2e verdieping | Hout C | 106.309 |  |  |  |  | 0.00385343 | 0.19329
2 x Hout C | 2e verdieping | Hout C | 107.032 |  |  |  |  | 0.00387961 | 0.194603
Hout - Multiplex | 2e verdieping | Hout - Multiplex | 48.1429 |  |  |  |  | 0.00136581 | 0.0687756
Isolatie - Glaswol zacht | 2e verdieping | Isolatie - Glaswol zacht | 19.4937 |  |  |  |  | 0.0519974 | 1.39241
2 x Isolatie - Glaswol zacht | 2e verdieping | Isolatie - Glaswol zacht | 109.195 |  |  | 509.061 | 304 | 0.154754 | 7.79962
2 x Hout - Multiplex | 2e verdieping | Hout - Multiplex | 288.73 |  |  |  |  | 0.00822821 | 0.412471
2 x _TenW_21_Steen - Baksteen | 2e verdieping | _TenW_21_Steen - Baksteen | 830.917 |  |  | 509.061 | 20 | 0.0101812 | 0.519323
2 x Metaal - Aluminium | 2e verdieping | Metaal - Aluminium | 39.8485 |  |  |  |  | 0.00027895 | 0.0142316
Membraan - waterdicht | 2e verdieping | Membraan - waterdicht | 7395.15 | 1408.6 | 5 |  |  |  | 7.043
Isolatie - Steenwol hard | 2e verdieping | Isolatie - Steenwol hard | 54801.8 | 1430.42 | 240 |  |  |  | 342.511
Beton gewapend C vloer | 2e verdieping | Beton gewapend C vloer | 1000344 | 1437.28 | 290 |  |  |  | 416.81
Beton gewapend prefab vloer | 2e verdieping | Beton gewapend prefab vloer | 172473 | 1437.28 | 50 |  |  |  | 71.8638
Hout - Multiplex | 2e verdieping | Hout - Multiplex | 48.1433 |  |  |  |  | 0.00136581 | 0.0687761
Isolatie - Glaswol zacht | 2e verdieping | Isolatie - Glaswol zacht | 19.6965 |  |  |  |  | 0.0519974 | 1.40689
Hout - Multiplex groen | 2e verdieping | Hout - Multiplex groen | 73.7339 |  |  |  |  | 0.0197532 | 0.105334
Isolatie - Kunststof hard | 2e verdieping | Isolatie - Kunststof hard | 19.6809 |  |  |  |  | 0.0301365 | 0.196809
Isolatie - Kunststof hard | 2e verdieping | Isolatie - Kunststof hard | 60.3425 |  |  |  |  | 0.0923998 | 0.603425
Isolatie - Kunststof hard | 2e verdieping | Isolatie - Kunststof hard | 17.3713 |  |  |  |  | 0.0265999 | 0.173713
Hout C | 2e verdieping | Hout C | 25.1041 |  |  |  |  | 0.00699999 | 0.0456438
2 x Hout C | 2e verdieping | Hout C | 25.1427 |  |  |  |  | 0.00699999 | 0.045714
Hout C | 2e verdieping | Hout C | 37.5582 |  |  |  |  | 0.0105604 | 0.0682876
Hout - Multiplex wit | 2e verdieping | Hout - Multiplex wit | 104.394 |  |  |  |  | 0.0240416 | 0.149134
Metaal - Aluminium | 2e verdieping | Metaal - Aluminium | 12.4455 |  |  |  |  | 0.000713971 | 0.00444482
Hout - Multiplex groen | 2e verdieping | Hout - Multiplex groen | 103.567 |  |  |  |  | 0.0197532 | 0.147954
Hout - Multiplex wit | 2e verdieping | Hout - Multiplex wit | 154.499 |  |  |  |  | 0.0240416 | 0.220712
Metaal - Aluminium | 2e verdieping | Metaal - Aluminium | 18.3975 |  |  |  |  | 0.000713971 | 0.00657054
Isolatie - Kunststof hard | 2e verdieping | Isolatie - Kunststof hard | 27.7341 |  |  |  |  | 0.0301365 | 0.277341
Isolatie - Kunststof hard | 2e verdieping | Isolatie - Kunststof hard | 85.034 |  |  |  |  | 0.0923998 | 0.85034
Isolatie - Kunststof hard | 2e verdieping | Isolatie - Kunststof hard | 24.4795 |  |  |  |  | 0.0265999 | 0.244795
Hout C | 2e verdieping | Hout C | 35.3776 |  |  |  |  | 0.00699999 | 0.0643229
2 x Hout C | 2e verdieping | Hout C | 35.4308 |  |  |  |  | 0.00699999 | 0.0644197
Hout C | 2e verdieping | Hout C | 53.452 |  |  |  |  | 0.0105604 | 0.0971854
Hout - Multiplex groen | 2e verdieping | Hout - Multiplex groen | 116.526 |  |  |  |  | 0.0175855 | 0.166466
Hout - Multiplex groen | 2e verdieping | Hout - Multiplex groen | 55.1217 |  |  |  |  | 0.0116937 | 0.0787452
Metaal - Aluminium | 2e verdieping | Metaal - Aluminium | 16.2974 |  |  |  |  | 0.00059271 | 0.00582051
Isolatie - Kunststof hard | 2e verdieping | Isolatie - Kunststof hard | 21.7386 |  |  | 158.119 | 140 | 0.0221367 | 0.217386
Isolatie - Kunststof hard | 2e verdieping | Isolatie - Kunststof hard | 35.9288 |  |  | 261.334 | 140 | 0.0365868 | 0.359288
Isolatie - Kunststof hard | 2e verdieping | Isolatie - Kunststof hard | 26.1216 |  |  | 190 | 140 | 0.0266 | 0.261216
3 x Hout C | 2e verdieping | Hout C | 37.8076 |  |  | 50 | 140 | 0.007 | 0.0687411
Hout C | 2e verdieping | Hout C | 33.2298 |  |  |  |  | 0.00615243 | 0.0604179
Hout - Multiplex groen | 2e verdieping | Hout - Multiplex groen | 87.475 |  |  |  |  | 0.0197532 | 0.124964
Hout - Multiplex wit | 2e verdieping | Hout - Multiplex wit | 130.281 |  |  |  |  | 0.0240416 | 0.186116
Metaal - Aluminium | 2e verdieping | Metaal - Aluminium | 15.5389 |  |  |  |  | 0.000713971 | 0.0055496
Isolatie - Kunststof hard | 2e verdieping | Isolatie - Kunststof hard | 23.4247 |  |  |  |  | 0.0301365 | 0.234247
Isolatie - Kunststof hard | 2e verdieping | Isolatie - Kunststof hard | 71.8212 |  |  |  |  | 0.0923998 | 0.718212
Isolatie - Kunststof hard | 2e verdieping | Isolatie - Kunststof hard | 20.6758 |  |  |  |  | 0.0265999 | 0.206758
Hout C | 2e verdieping | Hout C | 29.8804 |  |  |  |  | 0.00699999 | 0.054328
2 x Hout C | 2e verdieping | Hout C | 29.9255 |  |  |  |  | 0.00699999 | 0.05441
Hout C | 2e verdieping | Hout C | 45.1465 |  |  |  |  | 0.0105604 | 0.0820846
Hout - Multiplex wit | 2e verdieping | Hout - Multiplex wit | 102.88 |  |  |  |  | 0.0175855 | 0.146972
Hout - Multiplex groen | 2e verdieping | Hout - Multiplex groen | 47.0952 |  |  |  |  | 0.0116937 | 0.0672788
Metaal - Aluminium | 2e verdieping | Metaal - Aluminium | 13.9243 |  |  |  |  | 0.00059271 | 0.00497296
Isolatie - Kunststof hard | 2e verdieping | Isolatie - Kunststof hard | 18.5732 |  |  | 158.119 | 140 | 0.0221367 | 0.185732
Isolatie - Kunststof hard | 2e verdieping | Isolatie - Kunststof hard | 30.6971 |  |  | 261.334 | 140 | 0.0365868 | 0.306971
Isolatie - Kunststof hard | 2e verdieping | Isolatie - Kunststof hard | 22.318 |  |  | 190 | 140 | 0.0266 | 0.22318
3 x Hout C | 2e verdieping | Hout C | 32.3023 |  |  | 50 | 140 | 0.007 | 0.0587315
Hout C | 2e verdieping | Hout C | 28.3911 |  |  |  |  | 0.00615243 | 0.0516202
Hout - Multiplex groen | 2e verdieping | Hout - Multiplex groen | 71.5938 |  |  |  |  | 0.0197532 | 0.102277
Hout - Multiplex wit | 2e verdieping | Hout - Multiplex wit | 106.265 |  |  |  |  | 0.0240416 | 0.151807
Metaal - Aluminium | 2e verdieping | Metaal - Aluminium | 12.7178 |  |  |  |  | 0.000713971 | 0.00454207
Isolatie - Kunststof hard | 2e verdieping | Isolatie - Kunststof hard | 19.172 |  |  |  |  | 0.0301365 | 0.19172
Isolatie - Kunststof hard | 2e verdieping | Isolatie - Kunststof hard | 58.782 |  |  |  |  | 0.0923998 | 0.58782
Isolatie - Kunststof hard | 2e verdieping | Isolatie - Kunststof hard | 16.9221 |  |  |  |  | 0.0265999 | 0.169221
Hout C | 2e verdieping | Hout C | 24.4557 |  |  |  |  | 0.00699999 | 0.0444649
2 x Hout C | 2e verdieping | Hout C | 24.4925 |  |  |  |  | 0.00699999 | 0.0445318
Hout C | 2e verdieping | Hout C | 36.9501 |  |  |  |  | 0.0105604 | 0.0671821
Hout - Multiplex wit | 2e verdieping | Hout - Multiplex wit | 85.2439 |  |  |  |  | 0.0175855 | 0.121777
Hout - Multiplex groen | 2e verdieping | Hout - Multiplex groen | 39.1741 |  |  |  |  | 0.0116937 | 0.055963
Metaal - Aluminium | 2e verdieping | Metaal - Aluminium | 11.5823 |  |  |  |  | 0.00059271 | 0.00413654
Isolatie - Kunststof hard | 2e verdieping | Isolatie - Kunststof hard | 15.4493 |  |  | 158.119 | 140 | 0.0221367 | 0.154493
Isolatie - Kunststof hard | 2e verdieping | Isolatie - Kunststof hard | 25.5341 |  |  | 261.334 | 140 | 0.0365868 | 0.255341
Isolatie - Kunststof hard | 2e verdieping | Isolatie - Kunststof hard | 18.5642 |  |  | 190 | 140 | 0.0266 | 0.185642
3 x Hout C | 2e verdieping | Hout C | 26.8693 |  |  | 50 | 140 | 0.007 | 0.0488533
Hout C | 2e verdieping | Hout C | 23.6159 |  |  |  |  | 0.00615243 | 0.0429381
Hout - Multiplex | 2e verdieping | Hout - Multiplex | 36.8703 |  |  |  |  | 0.0197532 | 0.0526719
Metaal - Staal AFW | 2e verdieping | Metaal - Staal AFW | 55.3518 |  |  |  |  | 0.00212361 | 0.00696249
Hout C | 2e verdieping | Hout C | 8.81508 |  |  |  |  | 0.005 | 0.0160274
Hout C | 2e verdieping | Hout C | 8.82869 |  |  |  |  | 0.005 | 0.0160522
Hout - Multiplex | 2e verdieping | Hout - Multiplex | 37.8169 |  |  |  |  | 0.0197532 | 0.0540241
Metaal - Staal AFW | 2e verdieping | Metaal - Staal AFW | 56.6446 |  |  |  |  | 0.00212361 | 0.00712511
Hout C | 2e verdieping | Hout C | 9.02096 |  |  |  |  | 0.005 | 0.0164017
Hout C | 2e verdieping | Hout C | 9.0349 |  |  |  |  | 0.005 | 0.0164271
Hout - Multiplex | 2e verdieping | Hout - Multiplex | 88.4728 |  |  |  |  | 0.0197532 | 0.12639
Metaal - Staal AFW | 2e verdieping | Metaal - Staal AFW | 133.116 |  |  |  |  | 0.00212361 | 0.0167442
Hout C | 2e verdieping | Hout C | 21.1995 |  |  |  |  | 0.005 | 0.0385446
Hout C | 2e verdieping | Hout C | 21.2322 |  |  |  |  | 0.005 | 0.0386041

# IfcBuildingElementProxy: ALG - BINNENAFWERKING (6)
In: 2e verdieping
Type - ElementType: Massing; PredefinedType: USERDEFINED
Classification: Massa (ARCHICAD Classification); Material: ALG - BINNENAFWERKING
Name | Component 1, Mass (kg) | Component 1, Skin/Component Volume (m3)
3 x _Massa_OMG Morph | 153.252 | 0.191565
3 x _Massa_OMG Morph | 190.929 | 0.238661

# IfcBuildingElementProxy: ALG - BINNENAFWERKING 10 (122)
Classification: 23.21 VRIJDRAGENDE VLOEREN (NL/SfB (4 cijfers)); Vloer (ARCHICAD Classification); Material: ALG - BINNENAFWERKING
Component Quantities - Component 1, Skin Thickness: 10 mm
Name | In | Component 1, Mass (kg) | Component 1, Projected Component/Skin Area (m2) | Component 1, Skin/Component Volume (m3)
23__Vloer-x | Begane grond | 275.998 | 34.4998 | 0.344998
23__Vloer-x | Begane grond | 219.682 | 27.4603 | 0.274603
23__Vloer-x | Begane grond | 107.231 | 13.4039 | 0.134039
2 x 23__Vloer-x | Begane grond | 241.306 | 30.1633 | 0.301633
23__Vloer-x | Begane grond | 170.005 | 21.2506 | 0.212506
23__Vloer-x | Begane grond | 167.851 | 20.9814 | 0.209814
23__Vloer-x | Begane grond | 165.79 | 20.7237 | 0.207237
23__Vloer-x | Begane grond | 170.4 | 21.3 | 0.213
23__Vloer-x | Begane grond | 167.56 | 20.945 | 0.20945
23__Vloer-x | Begane grond | 75.5551 | 9.44438 | 0.0944438
23__Vloer-x | Begane grond | 248.749 | 31.0936 | 0.310936
23__Vloer-x | Begane grond | 166.254 | 20.7818 | 0.207818
23__Vloer-x | Begane grond | 48.756 | 6.09449 | 0.0609449
23__Vloer-x | Begane grond | 194.102 | 24.2627 | 0.242627
23__Vloer-x | Begane grond | 170.848 | 21.356 | 0.21356
23__Vloer-x | Begane grond | 60.458 | 7.55725 | 0.0755725
23__Vloer-x | Begane grond | 24.4267 | 3.05333 | 0.0305333
23__Vloer-x | Begane grond | 21.87 | 2.73375 | 0.0273375
23__Vloer-x | Begane grond | 34.5318 | 4.31648 | 0.0431648
23__Vloer-x | Begane grond | 112.856 | 14.107 | 0.14107
23__Vloer-x | Begane grond | 11.6383 | 1.45478 | 0.0145478
23__Vloer-x | Begane grond | 84.9756 | 10.622 | 0.10622
23__Vloer-x | Begane grond | 61.1464 | 7.6433 | 0.076433
23__Vloer-x | Begane grond | 93.2797 | 11.66 | 0.1166
23__Vloer-x | Begane grond | 41.9822 | 5.24778 | 0.0524778
23__Vloer-x | Begane grond | 23.2732 | 2.90915 | 0.0290915
23__Vloer-x | Begane grond | 83.0869 | 10.3859 | 0.103859
23__Vloer-x | Begane grond | 38.7328 | 4.8416 | 0.048416
23__Vloer-x | Begane grond | 5.49298 | 0.686623 | 0.00686623
23__Vloer-x | Begane grond | 65.4104 | 8.1763 | 0.081763
23__Vloer-x | Begane grond | 135.321 | 16.9151 | 0.169151
23__Vloer-x | Begane grond | 775.74 | 96.9675 | 0.969675
23__Vloer-x | Begane grond | 31.7687 | 3.97109 | 0.0397109
23__Vloer-x | Begane grond | 66.3327 | 8.29159 | 0.0829159
23__Vloer-x | Begane grond | 31.7515 | 3.96894 | 0.0396894
23__Vloer-x | Begane grond | 31.9125 | 3.98906 | 0.0398906
2 x 23__Vloer-x | Begane grond | 32.19 | 4.02375 | 0.0402375
23__Vloer-x | Begane grond | 32.0276 | 4.00345 | 0.0400345
23__Vloer-x | Begane grond | 323.109 | 54.1698 | 0.403886
23__Vloer-x | Begane grond | 50.7268 | 6.34085 | 0.0634085
23__Vloer-x | Begane grond | 448.69 | 56.0863 | 0.560863
23__Vloer-x | Begane grond | 79.7705 | 9.97132 | 0.0997132
23__Vloer-x | Begane grond | 323.623 | 40.4529 | 0.404529
23__Vloer-x | Begane grond | 97.1417 | 12.1427 | 0.121427
23__Vloer-x | Begane grond | 81.3925 | 10.1741 | 0.101741
23__Vloer-x | Begane grond | 709.657 | 88.7071 | 0.887071
23__Vloer-x | Begane grond | 22.703 | 2.83787 | 0.0283787
23__Vloer-x | Begane grond | 1081.68 | 135.21 | 1.3521
23__Vloer-x | Begane grond | 384.449 | 48.0561 | 0.480561
23__Vloer-x | Begane grond | 272.502 | 34.0627 | 0.340627
23__Vloer-x | Begane grond | 363.642 | 45.4553 | 0.454553
23__Vloer-x | Begane grond | 283.205 | 35.4006 | 0.354006
23__Vloer-x | Begane grond | 281.649 | 35.2061 | 0.352061
23__Vloer-x | Begane grond | 118.3 | 14.7875 | 0.147875
23__Vloer-x | Begane grond | 448.587 | 56.0734 | 0.560734
23__Vloer-x | Begane grond | 224.895 | 28.1118 | 0.281118
23__Vloer-x | Begane grond | 224.204 | 28.0273 | 0.280255
23__Vloer-x | Begane grond | 438.009 | 54.7511 | 0.547512
23__Vloer-x | Begane grond | 5.69423 | 0.711779 | 0.00711779
23__Vloer-x | Begane grond | 7.32429 | 0.915536 | 0.00915536
23__Vloer-x | Begane grond | 830.904 | 103.863 | 1.03863
23__Vloer-x | Begane grond | 24.1292 | 5.25387 | 0.0301615
23__Vloer-x | Begane grond | 32.5485 | 4.06856 | 0.0406856
23__Vloer-x | Begane grond | 72.4345 | 9.05431 | 0.0905431
23__Vloer-x | 1e verdieping | 419.448 | 52.431 | 0.52431
23__Vloer-x | 1e verdieping | 10.1152 | 1.26439 | 0.0126439
23__Vloer-x | 1e verdieping | 41.1791 | 5.14739 | 0.0514739
23__Vloer-x | 1e verdieping | 3226.7 | 403.338 | 4.03338
23__Vloer-x | 1e verdieping | 31.7517 | 3.96897 | 0.0396897
23__Vloer-x | 1e verdieping | 49.752 | 6.219 | 0.06219
23__Vloer-x | 1e verdieping | 104.348 | 13.0435 | 0.130435
23__Vloer-x | 1e verdieping | 5.36372 | 0.670465 | 0.00670465
23__Vloer-x | 1e verdieping | 28.2174 | 3.52717 | 0.0352717
23__Vloer-x | 1e verdieping | 100.069 | 12.5086 | 0.125086
23__Vloer-x | 1e verdieping | 17.5008 | 2.1876 | 0.021876
23__Vloer-x | 1e verdieping | 155.96 | 19.495 | 0.19495
23__Vloer-x | 1e verdieping | 461.322 | 57.6652 | 0.576652
23__Vloer-x | 1e verdieping | 27.0991 | 3.38739 | 0.0338739
23__Vloer-x | 1e verdieping | 96.8518 | 12.1065 | 0.121065
23__Vloer-x | 1e verdieping | 33.2601 | 4.15751 | 0.0415751
23__Vloer-x | 1e verdieping | 80.6208 | 10.0776 | 0.100776
23__Vloer-x | 1e verdieping | 398.267 | 49.7833 | 0.497833
23__Vloer-x | 1e verdieping | 411.655 | 51.4569 | 0.514569
2 x 23__Vloer-x | 1e verdieping | 63.512 | 7.939 | 0.07939
2 x 23__Vloer-x | 1e verdieping | 82.6437 | 10.3305 | 0.103305
2 x 23__Vloer-x | 1e verdieping | 421.5 | 52.6875 | 0.526875
23__Vloer-x | 1e verdieping | 402 | 50.25 | 0.5025
23__Vloer-x | 1e verdieping | 3.99 | 0.49875 | 0.0049875
23__Vloer-x | 1e verdieping | 23.9988 | 2.99985 | 0.0299985
23__Vloer-x | 1e verdieping | 14.396 | 1.7995 | 0.017995
2 x 23__Vloer-x | 1e verdieping | 6.16432 | 0.77054 | 0.0077054
2 x 23__Vloer-x | 1e verdieping | 27.2552 | 3.4069 | 0.034069
23__Vloer-x | 1e verdieping | 89.2793 | 11.1599 | 0.111599
23__Vloer-x | 1e verdieping | 134.697 | 16.8371 | 0.168371
23__Vloer-x | 1e verdieping | 415.8 | 51.975 | 0.51975
23__Vloer-x | 1e verdieping | 402.362 | 50.2953 | 0.502953
23__Vloer-x | 1e verdieping | 82.0352 | 10.2544 | 0.102544
23__Vloer-x | 1e verdieping | 397.5 | 49.6875 | 0.496875
23__Vloer-x | 1e verdieping | 42.8648 | 5.3581 | 0.053581
23__Vloer-x | 1e verdieping | 154.272 | 19.284 | 0.19284
23__Vloer-x | 1e verdieping | 169.761 | 21.2201 | 0.212201
23__Vloer-x | 1e verdieping | 420.386 | 52.5483 | 0.525483
23__Vloer-x | 1e verdieping | 960.842 | 120.105 | 1.20105
2 x 23__Vloer-x | 1e verdieping | 13.2632 | 1.6579 | 0.016579
2 x 23__Vloer-x | 1e verdieping | 13.0952 | 1.6369 | 0.016369
23__Vloer-x | 1e verdieping | 6.58157 | 0.822696 | 0.00822696
23__Vloer-x | 1e verdieping | 14.5376 | 1.8172 | 0.018172
23__Vloer-x | 1e verdieping | 24.0714 | 3.00892 | 0.0300892
23__Vloer-x | 1e verdieping | 4.06 | 0.5075 | 0.005075
23__Vloer-x | 1e verdieping | 4.76088 | 0.59511 | 0.0059511
23__Vloer-x | 1e verdieping | 36.635 | 4.57937 | 0.0457937
23__Vloer-x | 1e verdieping | 9.65046 | 1.20631 | 0.0120631
23__Vloer-x | 1e verdieping | 8.20161 | 1.0252 | 0.010252

# IfcBuildingElementProxy: ALG - BINNENAFWERKING 20, 23__Vloer-x
In: Begane grond
Classification: 23.21 VRIJDRAGENDE VLOEREN (NL/SfB (4 cijfers)); Vloer (ARCHICAD Classification); Material: ALG - BINNENAFWERKING
Component Quantities - Component 1, Mass: 88.3282 kg; Component 1, Projected Component/Skin Area: 5.52051 m2; Component 1, Skin Thickness: 20 mm; Component 1, Skin/Component Volume: 0.11041 m3

# IfcBuildingElementProxy: Afzuigkap 24, __FU - 004
In: Begane grond
Component Quantities - Component 1, Skin/Component Volume: 0.122556 m3

# IfcBuildingElementProxy: Biomassa boiler 24 (3)
In: 1e verdieping
Component Quantities - Component 1, Skin/Component Volume: 0.540936 m3

# IfcBuildingElementProxy: Boekenplank 01 24 (21)
Name | In | Component 1, Skin/Component Volume (m3)
__Object-x | Begane grond | 0.22436
__Object-x | Begane grond | 0.193956
__Object-x | Begane grond | 0.23328
__Object-x | Begane grond | 0.150669
__Object-x | Begane grond | 0.171757
__Object-x | Begane grond | 0.212441
__Object-x | Begane grond | 0.0966473
__Object-x | Begane grond | 0.0939953
__Object-x | Begane grond | 0.0915878
__Object-x | Begane grond | 0.08176
2 x __Object-x | Begane grond | 0.135768
2 x __Object-x | 1e verdieping | 0.140887
__Object-x | 1e verdieping | 0.16111
__Object-x | 1e verdieping | 0.138959
2 x __Object-x | 1e verdieping | 0.152416
2 x __Object-x | 1e verdieping | 0.170816
__Object-x | 1e verdieping | 0.24827

# IfcBuildingElementProxy: Boiler elektrisch 24 (3)
In: 1e verdieping
Component Quantities - Component 1, Skin/Component Volume: 0.312022 m3
Name
2 x __FU - 001
__FU - 002

# IfcBuildingElementProxy: Brandslanghaspelkast 24 KM (6)
Component Quantities - Component 1, Skin/Component Volume: 0.0160685 m3
Name | In
3 x __Object-x | Begane grond
3 x __Object-x | 1e verdieping

# IfcBuildingElementProxy: Digitaal bord 24 (19)
Component Quantities - Component 1, Skin/Component Volume: 0.0907383 m3
Name | In
9 x __object-x | Begane grond
10 x __object-x | 1e verdieping

# IfcBuildingElementProxy: Droger 24, __object-x
In: Begane grond
Component Quantities - Component 1, Skin/Component Volume: 0.0187356 m3

# IfcBuildingElementProxy: Glas 20, 23__Vloer-x
In: Begane grond
Classification: 23.21 VRIJDRAGENDE VLOEREN (NL/SfB (4 cijfers)); Vloer (ARCHICAD Classification); Material: Glas
Component Quantities - Component 1, Mass: 20.928 kg; Component 1, Projected Component/Skin Area: 0.48 m2; Component 1, Skin Thickness: 20 mm; Component 1, Skin/Component Volume: 0.0096 m3

# IfcBuildingElementProxy: Grond 30, 23__Vloer-x
In: 2e verdieping
Classification: 23.21 VRIJDRAGENDE VLOEREN (NL/SfB (4 cijfers)); Vloer (ARCHICAD Classification); Material: Grond
Component Quantities - Component 1, Mass: 15784.1 kg; Component 1, Projected Component/Skin Area: 292.299 m2; Component 1, Skin Thickness: 30 mm; Component 1, Skin/Component Volume: 8.76896 m3

# IfcBuildingElementProxy: IfcBuildingElementProxy (12)
Material: Metaal - RVS
Name | In | Classification
__Hoofdbaluster-x | Begane grond | Reling - baluster (ARCHICAD Classification) | Component Quantities - Component 1, Mass: 8.1314 kg; Component 1, Skin/Component Volume: 0.00102929 m3
__Hoofdbaluster-x | Begane grond | Reling - baluster (ARCHICAD Classification)
__Bovenregel-x | Begane grond | Reling - regel (ARCHICAD Classification) | Component Quantities - Component 1, Mass: 2.40062 kg; Component 1, Skin/Component Volume: 0.000303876 m3
6 x __Hoofdbaluster-x | 1e verdieping | Reling - baluster (ARCHICAD Classification)
3 x __Bovenregel-x | 1e verdieping | Reling - regel (ARCHICAD Classification)

# IfcBuildingElementProxy: Inbouwreservoir 24 KM (31)
Name | In | Component 1, Skin/Component Volume (m3)
15 x __Object-x | Begane grond | 0.078208
4 x __Object-x | Begane grond | 0.077975
12 x __Object-x | 1e verdieping | 0.078208

# IfcBuildingElementProxy: Invalidentoilet 24, __FU - 004
In: Begane grond
Component Quantities - Component 1, Skin/Component Volume: 0.0133638 m3

# IfcBuildingElementProxy: Kast basis 1D 24 (87)
Name | In | Component 1, Skin/Component Volume (m3)
2 x __Object-x | Begane grond | 0.167315
4 x __Object-x | Begane grond | 0.0781306
4 x __FU - 001 | Begane grond | 0.0753073
4 x __Object-x | Begane grond | 0.0954726
4 x __Object-x | Begane grond | 0.0917446
2 x __Object-x | Begane grond | 0.0818285
__Object-x | Begane grond | 0.0870312
2 x __Object-x | Begane grond | 0.104395
3 x __Object-x | Begane grond | 0.0843092
3 x __FU - 001 | Begane grond | 0.0879509
3 x __Object-x | Begane grond | 0.10459
3 x __Object-x | Begane grond | 0.0978632
__Object-x | Begane grond | 0.161072
__Object-x | Begane grond | 0.0834263
__Object-x | Begane grond | 0.0948425
__Object-x | Begane grond | 0.0710282
__Object-x | Begane grond | 0.0848944
2 x __Object-x | Begane grond | 0.0888252
2 x __Object-x | Begane grond | 0.0954175
2 x __Object-x | Begane grond | 0.101099
2 x __Object-x | Begane grond | 0.111691
__Object-x | 1e verdieping | 0.101086
__Object-x | 1e verdieping | 0.0848944
9 x __Object-x | 1e verdieping | 0.0843092
9 x __FU - 001 | 1e verdieping | 0.0879509
9 x __Object-x | 1e verdieping | 0.10459
9 x __Object-x | 1e verdieping | 0.0978632
__Object-x | 1e verdieping | 0.0869575

# IfcBuildingElementProxy: Kast basis 2D 24 (5)
In: Begane grond
Name | Component 1, Skin/Component Volume (m3)
__Object-x | 0.177168
__FU - 001 | 0.156181
__Object-x | 0.169173
__Object-x | 0.17977
__FU - 001 | 0.147116

# IfcBuildingElementProxy: Kast basis 3D 24 (2)
In: Begane grond
Name | Component 1, Skin/Component Volume (m3)
__Object-x | 0.541388
__Object-x | 0.414377

# IfcBuildingElementProxy: Kast basis multilade 24 (5)
In: Begane grond
Name | Component 1, Skin/Component Volume (m3)
__Object-x | 0.1073
__Object-x | 0.0542685
__Object-x | 0.0905699
__Object-x | 0.10332
__Object-x | 0.0950324

# IfcBuildingElementProxy: Kast basis vaatwasser 24 (2)
Name | In | Component 1, Skin/Component Volume (m3)
__Object-x | Begane grond | 0.0500081
__Object-x | 1e verdieping | 0.0991182

# IfcBuildingElementProxy: Kast hoog 1D 24 (71)
Name | In | Component 1, Skin/Component Volume (m3)
__Object-x | Begane grond | 0.212445
7 x __Object-x | Begane grond | 0.188212
7 x __Object-x | Begane grond | 0.215087
2 x __Object-x | Begane grond | 0.162875
__Object-x | Begane grond | 0.168085
__Object-x | Begane grond | 0.262105
11 x __Object-x | Begane grond | 0.196114
2 x __Object-x | Begane grond | 0.227202
2 x __Object-x | Begane grond | 0.261291
__Object-x | Begane grond | 0.203385
__Object-x | Begane grond | 0.187587
2 x __Object-x | Begane grond | 0.214658
__Object-x | Begane grond | 0.227483
__Object-x | Begane grond | 0.183556
__Object-x | 1e verdieping | 0.210409
2 x __Object-x | 1e verdieping | 0.250361
9 x __Object-x | 1e verdieping | 0.188212
9 x __Object-x | 1e verdieping | 0.215087
8 x __Object-x | 1e verdieping | 0.196114
2 x __Object-x | 1e verdieping | 0.227202

# IfcBuildingElementProxy: Kast hoog 1D inbouwapparatuur 24 (2)
Name | In | Component 1, Skin/Component Volume (m3)
__Object-x | Begane grond | 0.19023
__Object-x | 1e verdieping | 0.220246

# IfcBuildingElementProxy: Kast wand 1D 24 (20)
In: Begane grond
Name | Component 1, Skin/Component Volume (m3)
__Object-x | 0.0658452
2 x __Object-x | 0.0536494
__Object-x | 0.0389738
2 x __Object-x | 0.0394589
__Object-x | 0.0415394
__Object-x | 0.0562357
__Object-x | 0.0571751
__Object-x | 0.0510773
__Object-x | 0.0454042
2 x __Object-x | 0.0488762
__Object-x | 0.0588149
6 x __Object-x | 0.051117

# IfcBuildingElementProxy: Kast wand 2D 24 (3)
In: Begane grond
Component Quantities - Component 1, Skin/Component Volume: 0.0889901 m3

# IfcBuildingElementProxy: Koffiezetapparaat 24, __Object-x
In: 1e verdieping
Component Quantities - Component 1, Skin/Component Volume: 0.0753755 m3

# IfcBuildingElementProxy: Kookplaat inbouw 24 (2)
In: Begane grond
Component Quantities - Component 1, Skin/Component Volume: 0.00745847 m3

# IfcBuildingElementProxy: Magnetron 24 (2)
In: Begane grond
Component Quantities - Component 1, Skin/Component Volume: 0.03274 m3

# IfcBuildingElementProxy: Railing Type (4)
Classification: 34.21 BINNENLEUNINGEN (NL/SfB (4 cijfers)); Reling (ARCHICAD Classification)
Name | In
34__Reling-x | Begane grond
3 x 34__Reling-x | 1e verdieping

# IfcBuildingElementProxy: Sanitaire wanden 24 (9)
Name | In | Component 1, Skin/Component Volume (m3)
__Object-x | Begane grond | 0.130462
__Object-x | Begane grond | 0.344677
__Object-x | Begane grond | 0.0605043
__Object-x | Begane grond | 0.537673
__Object-x | Begane grond | 0.123614
2 x __Object-x | 1e verdieping | 0.228259
2 x __Object-x | 1e verdieping | 0.464013

# IfcBuildingElementProxy: Stapelbed 24 (12)
In: Begane grond
Name | Component 1, Skin/Component Volume (m3)
11 x __object-x | 0.358635
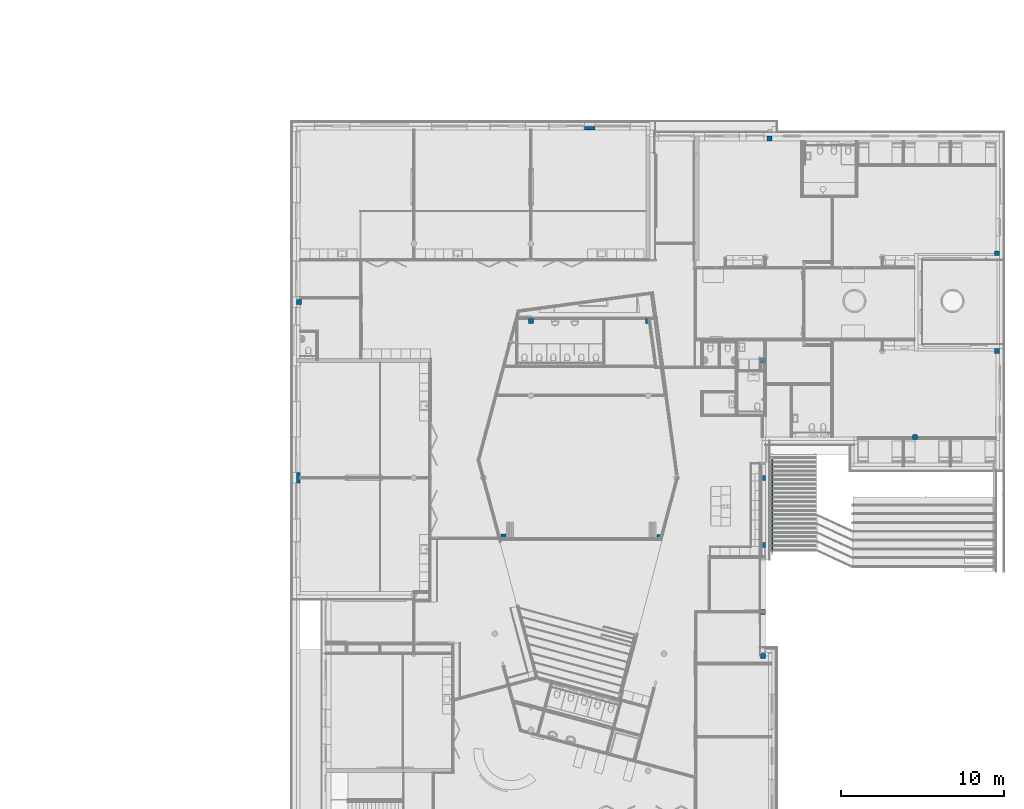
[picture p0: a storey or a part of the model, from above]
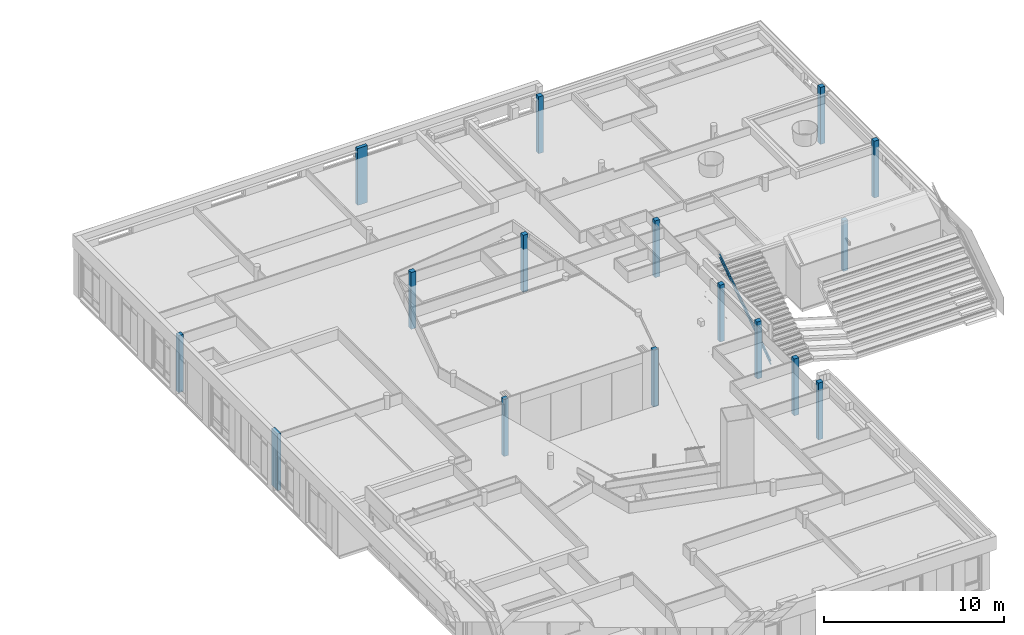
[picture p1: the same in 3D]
Properties of the parts of a building model (IFC2X3), part 3 of 5

# IfcBuildingElementProxy: Stapelbed 24 (12)
Name | Component 1, Skin/Component Volume (m3)
__object-x | 0.351462

# IfcBuildingElementProxy: Tekst 3D 24 (3)
In: 1e verdieping
Component Quantities - Component 1, Skin/Component Volume: 0.0763844 m3

# IfcBuildingElementProxy: Toilet 24 (9)
Component Quantities - Component 1, Skin/Component Volume: 0.0103977 m3
Name | In
7 x __FU - 003 | Begane grond
2 x __FU - 003 | 1e verdieping

# IfcBuildingElementProxy: Uitstortgootsteen 24 (2)
In: Begane grond
Component Quantities - Component 1, Skin/Component Volume: 0.0400417 m3

# IfcBuildingElementProxy: Vouwwand 24, __object-x
In: Begane grond
Material: Kunststof - massief
Component Quantities - Component 1, Mass: 2780.82 kg; Component 1, Skin/Component Volume: 2.00059 m3

# IfcBuildingElementProxy: Wasbak 24 (18)
Name | In | Component 1, Skin/Component Volume (m3)
2 x __FU - 005 | Begane grond | 0.000197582
__Object-x | Begane grond | 0.0338966
2 x __Object-x | Begane grond | 0.00213412
__FU - 005 | Begane grond | 0.000197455
3 x __object-x | Begane grond | 0.000197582
__Object-x | Begane grond | 0.0251184
2 x __Object-x | 1e verdieping | 0.00213412
4 x __FU - 005 | 1e verdieping | 0.000197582
__Object-x | 1e verdieping | 0.0338966
__Object-x | 1e verdieping | 0.0558365

# IfcBuildingElementProxy: Wasmachine 24, __object-x
In: Begane grond
Component Quantities - Component 1, Skin/Component Volume: 0.0504689 m3

# IfcBuildingElementProxy: Zonnepaneel 24 (57)
In: 2e verdieping
Name | Component 1, Skin/Component Volume (m3)
41 x __Object-x | 0.0916746
13 x __Object-x | 0.493724
3 x __Object-x | 0.31531

# IfcBuildingElementProxy: _TenW_21_Hout betimmering 10, 23__Vloer-x
In: Begane grond
Classification: 23.21 VRIJDRAGENDE VLOEREN (NL/SfB (4 cijfers)); Vloer (ARCHICAD Classification); Material: _TenW_21_Hout betimmering
Component Quantities - Component 1, Mass: 123.151 kg; Component 1, Projected Component/Skin Area: 22.3922 m2; Component 1, Skin Thickness: 10 mm; Component 1, Skin/Component Volume: 0.22391 m3

# IfcBuildingElementProxy: _TenW_21_Hout betimmering 50 (2)
In: 1e verdieping
Classification: 23.21 VRIJDRAGENDE VLOEREN (NL/SfB (4 cijfers)); Vloer (ARCHICAD Classification); Material: _TenW_21_Hout betimmering
Component Quantities - Component 1, Skin Thickness: 50 mm
Name | Component 1, Mass (kg) | Component 1, Projected Component/Skin Area (m2) | Component 1, Skin/Component Volume (m3)
23__Vloer-x | 94.8187 | 3.44795 | 0.172398
23__Vloer-x | 94.8959 | 3.45076 | 0.172538

# IfcBuildingElementProxy: _TenW_22_Gipsvezelplaat watervast 15 (11)
Classification: 22.13 SYSTEEMWANDEN VAST (NL/SfB (4 cijfers)); Material: _TenW_22_Gipsplaat watervast
Component Quantities - Component 1, Skin Thickness: 15 mm; Component 1, Rectangular Component Width: 15 mm
Name | In | Component 1, Mass (kg) | Component 1, Projected Component/Skin Area (m2) | Component 1, Rectangular Component Height (mm) | Component 1, Component Cross Section Area (m2) | Component 1, Skin/Component Volume (m3)
22__Wand-x | Begane grond | 390.569 | 18.5985 | 3640 | 0.0546 | 0.278978
22__Wand-x | Begane grond | 125.727 | 5.98698 | 3640 | 0.0546 | 0.0898047
22__Wand-x | Begane grond | 224.817 | 10.7056 | 2490 | 0.03735 | 0.160583
22__Wand-x | Begane grond | 74.13 | 3.53 | 3640 | 0.0546 | 0.05295
22__Wand-x | Begane grond | 116.157 | 5.53128 | 3325 | 0.049875 | 0.0829692
22__Wand-x | Begane grond | 216.891 | 10.3281 | 3325 | 0.049875 | 0.154922
2 x 22__Wand-x | Begane grond | 63.7883 | 3.03754 | 3155.89 | 0.0473383 | 0.0455631
22__Wand-x | 1e verdieping | 152.036 | 7.23982 | 3640 | 0.0546 | 0.108597
22__Wand-x | 1e verdieping | 340.605 | 16.2193 | 3640 | 0.0546 | 0.243289
22__Wand-x | 1e verdieping | 353.493 | 16.833 | 3640 | 0.0546 | 0.252495

# IfcBuildingElementProxy: _TenW_24_Hout - Multiplex 2, 23__Vloer-x
In: Begane grond
Classification: 23.21 VRIJDRAGENDE VLOEREN (NL/SfB (4 cijfers)); Vloer (ARCHICAD Classification); Material: _TenW_24_Hout - Multiplex
Component Quantities - Component 1, Mass: 3.78 kg; Component 1, Projected Component/Skin Area: 2.7 m2; Component 1, Skin Thickness: 2 mm; Component 1, Skin/Component Volume: 0.0054 m3

# IfcBuildingElementProxy: _TenW_24_Hout - Multiplex 20, 23__Vloer-x
In: Begane grond
Classification: 23.21 VRIJDRAGENDE VLOEREN (NL/SfB (4 cijfers)); Vloer (ARCHICAD Classification); Material: _TenW_24_Hout - Multiplex
Component Quantities - Component 1, Mass: 0.63 kg; Component 1, Projected Component/Skin Area: 0.045 m2; Component 1, Skin Thickness: 20 mm; Component 1, Skin/Component Volume: 0.0009 m3

# IfcBuildingElementProxy: _TenW_24_Hout - Multiplex 40 (2)
In: Begane grond
Classification: 23.21 VRIJDRAGENDE VLOEREN (NL/SfB (4 cijfers)); Vloer (ARCHICAD Classification); Material: _TenW_24_Hout - Multiplex
Component Quantities - Component 1, Skin Thickness: 40 mm
Name | Component 1, Mass (kg) | Component 1, Projected Component/Skin Area (m2) | Component 1, Skin/Component Volume (m3)
23__Vloer-x | 14.154 | 0.5055 | 0.02022
23__Vloer-x | 30.24 | 1.08 | 0.0432

# IfcBuildingElementProxy: _TenW_27_Betontegel 50 (93)
In: 2e verdieping
Classification: 23.21 VRIJDRAGENDE VLOEREN (NL/SfB (4 cijfers)); Vloer (ARCHICAD Classification); Material: _TenW_27_Betontegel
Component Quantities - Component 1, Mass: 30.0241 kg; Component 1, Projected Component/Skin Area: 0.250201 m2; Component 1, Skin Thickness: 50 mm; Component 1, Skin/Component Volume: 0.0125101 m3

# IfcBuildingElementProxy: _TenW_43_A2 Forbo Impressa 2 (9)
In: Begane grond
Classification: 23.21 VRIJDRAGENDE VLOEREN (NL/SfB (4 cijfers)); Vloer (ARCHICAD Classification); Material: _TenW_43_A2 Forbo Impressa
Component Quantities - Component 1, Skin Thickness: 2 mm
Name | Component 1, Mass (kg) | Component 1, Projected Component/Skin Area (m2) | Component 1, Skin/Component Volume (m3)
23__Vloer-x | 20.7905 | 12.994 | 0.0259881
23__Vloer-x | 90.0706 | 56.2941 | 0.112588
23__Vloer-x | 1.73351 | 1.08344 | 0.00216689
23__Vloer-x | 1.90644 | 1.19152 | 0.00238305
23__Vloer-x | 1.87535 | 1.17209 | 0.00234418
23__Vloer-x | 89.7492 | 56.0933 | 0.112187
23__Vloer-x | 30.8774 | 19.2984 | 0.0385968
23__Vloer-x | 33.8599 | 21.1624 | 0.0423249
23__Vloer-x | 87.605 | 54.7531 | 0.109506

# IfcBuildingElementProxy: _TenW_43_Flexx F15 2 (15)
Classification: 23.21 VRIJDRAGENDE VLOEREN (NL/SfB (4 cijfers)); Vloer (ARCHICAD Classification); Material: _TenW_43_Flexx F15
Component Quantities - Component 1, Skin Thickness: 2 mm
Name | In | Component 1, Mass (kg) | Component 1, Projected Component/Skin Area (m2) | Component 1, Skin/Component Volume (m3)
23__Vloer-x | Begane grond | 20.7582 | 12.9739 | 0.0259478
2 x 23__Vloer-x | Begane grond | 2.23862 | 1.39913 | 0.00279827
23__Vloer-x | Begane grond | 11.5381 | 7.21134 | 0.0144227
23__Vloer-x | Begane grond | 16.1983 | 10.124 | 0.0202479
23__Vloer-x | Begane grond | 2.32766 | 1.45478 | 0.00290957
23__Vloer-x | Begane grond | 22.5713 | 14.107 | 0.0282141
23__Vloer-x | Begane grond | 4.374 | 2.73375 | 0.0054675
23__Vloer-x | Begane grond | 6.90636 | 4.31648 | 0.00863296
23__Vloer-x | Begane grond | 4.65465 | 2.90915 | 0.00581831
23__Vloer-x | 1e verdieping | 20.8695 | 13.0434 | 0.0260869
23__Vloer-x | 1e verdieping | 2.04029 | 1.27518 | 0.00255036
23__Vloer-x | 1e verdieping | 20.0137 | 12.5086 | 0.0250172
23__Vloer-x | 1e verdieping | 3.33875 | 2.08672 | 0.00417343
23__Vloer-x | 1e verdieping | 2.04024 | 1.27515 | 0.0025503

# IfcBuildingElementProxy: _TenW_43_Green Welness 2 (6)
In: Begane grond
Classification: 23.21 VRIJDRAGENDE VLOEREN (NL/SfB (4 cijfers)); Vloer (ARCHICAD Classification); Material: _TenW_43_Green Welness
Component Quantities - Component 1, Skin Thickness: 2 mm
Name | Component 1, Mass (kg) | Component 1, Projected Component/Skin Area (m2) | Component 1, Skin/Component Volume (m3)
2 x 23__Vloer-x | 6.549 | 4.09312 | 0.00818625
23__Vloer-x | 6.51596 | 4.07247 | 0.00814495
23__Vloer-x | 6.35375 | 3.97109 | 0.00794219
23__Vloer-x | 6.3825 | 3.98906 | 0.00797812
23__Vloer-x | 6.3503 | 3.96894 | 0.00793787

# IfcBuildingElementProxy: _TenW_43_Marmoleum Salsa Verde 2 (50)
Classification: 23.21 VRIJDRAGENDE VLOEREN (NL/SfB (4 cijfers)); Vloer (ARCHICAD Classification); Material: _TenW_43_Marmoleum Salsa Verde
Component Quantities - Component 1, Skin Thickness: 2 mm
Name | In | Component 1, Mass (kg) | Component 1, Projected Component/Skin Area (m2) | Component 1, Skin/Component Volume (m3)
23__Vloer-x | Begane grond | 13.0821 | 8.1763 | 0.0163526
23__Vloer-x | Begane grond | 21.3675 | 13.3547 | 0.0267094
23__Vloer-x | Begane grond | 82.8125 | 51.7578 | 0.103516
23__Vloer-x | Begane grond | 82.6252 | 51.6408 | 0.103282
23__Vloer-x | Begane grond | 83.738 | 52.3363 | 0.104673
23__Vloer-x | Begane grond | 43.8302 | 27.3938 | 0.0547877
23__Vloer-x | Begane grond | 15.9938 | 9.99613 | 0.0199923
23__Vloer-x | Begane grond | 8.0841 | 5.05256 | 0.0101051
23__Vloer-x | Begane grond | 43.2461 | 27.0288 | 0.0540576
23__Vloer-x | Begane grond | 89.1347 | 55.7092 | 0.111418
23__Vloer-x | Begane grond | 90.153 | 56.3456 | 0.112691
2 x 23__Vloer-x | Begane grond | 88.0706 | 55.0441 | 0.110088
23__Vloer-x | Begane grond | 13.2696 | 8.2935 | 0.016587
23__Vloer-x | Begane grond | 18.6559 | 11.66 | 0.0233199
23__Vloer-x | Begane grond | 89.2006 | 55.7504 | 0.111501
23__Vloer-x | Begane grond | 16.2785 | 10.1741 | 0.0203481
23__Vloer-x | Begane grond | 232.129 | 145.081 | 0.290161
23__Vloer-x | Begane grond | 313.505 | 195.941 | 0.391881
23__Vloer-x | Begane grond | 8.82489 | 5.51556 | 0.0110311
23__Vloer-x | Begane grond | 133.038 | 83.1488 | 0.166298
23__Vloer-x | Begane grond | 83.4097 | 52.131 | 0.104262
23__Vloer-x | 1e verdieping | 19.3704 | 12.1065 | 0.024213
23__Vloer-x | 1e verdieping | 20.5946 | 12.8716 | 0.0257433
23__Vloer-x | 1e verdieping | 84.7471 | 52.9669 | 0.105934
23__Vloer-x | 1e verdieping | 85.2292 | 53.2683 | 0.106537
2 x 23__Vloer-x | 1e verdieping | 12.7024 | 7.939 | 0.015878
2 x 23__Vloer-x | 1e verdieping | 17.7616 | 11.101 | 0.022202
23__Vloer-x | 1e verdieping | 85.851 | 53.6569 | 0.107314
2 x 23__Vloer-x | 1e verdieping | 86.9526 | 54.3454 | 0.108691
23__Vloer-x | 1e verdieping | 86.6963 | 54.1852 | 0.10837
23__Vloer-x | 1e verdieping | 33.9537 | 21.2211 | 0.0424421
23__Vloer-x | 1e verdieping | 86.6706 | 54.1692 | 0.108338
23__Vloer-x | 1e verdieping | 9.91182 | 6.19489 | 0.0123898
23__Vloer-x | 1e verdieping | 85.113 | 53.1956 | 0.106391
23__Vloer-x | 1e verdieping | 86.0675 | 53.7922 | 0.107584
23__Vloer-x | 1e verdieping | 85.2866 | 53.3041 | 0.106608
23__Vloer-x | 1e verdieping | 17.335 | 10.8344 | 0.0216688
23__Vloer-x | 1e verdieping | 17.0959 | 10.685 | 0.0213699
23__Vloer-x | 1e verdieping | 26.9394 | 16.8371 | 0.0336742
23__Vloer-x | 1e verdieping | 92.5269 | 57.8293 | 0.115659
23__Vloer-x | 1e verdieping | 5.41982 | 3.38738 | 0.00677477
23__Vloer-x | 1e verdieping | 9.9504 | 6.219 | 0.012438
23__Vloer-x | 1e verdieping | 188.726 | 117.954 | 0.235908
23__Vloer-x | 1e verdieping | 295.612 | 184.758 | 0.369516
23__Vloer-x | 1e verdieping | 116.215 | 72.6346 | 0.145269
23__Vloer-x | 1e verdieping | 152.918 | 95.5739 | 0.191148

# IfcBuildingElementProxy: _TenW_43_Schoonlooptapijt_Coral Duo 2 (5)
Classification: 23.21 VRIJDRAGENDE VLOEREN (NL/SfB (4 cijfers)); Vloer (ARCHICAD Classification); Material: _TenW_43_Schoonlooptapijt_Coral Duo
Component Quantities - Component 1, Skin Thickness: 2 mm
Name | In | Component 1, Mass (kg) | Component 1, Projected Component/Skin Area (m2) | Component 1, Skin/Component Volume (m3)
23__Vloer-x | Begane grond | 17.3534 | 10.8458 | 0.0216917
23__Vloer-x | Begane grond | 21.4463 | 13.4039 | 0.0268078
23__Vloer-x | Begane grond | 23.4226 | 14.6392 | 0.0292783
23__Vloer-x | Begane grond | 11.53 | 7.20624 | 0.0144125
23__Vloer-x | 1e verdieping | 19.5762 | 12.2351 | 0.0244702

# IfcBuildingElementProxy: _TenW_43_gietvloer Bolidt dolphine grey 2 (2)
In: Begane grond
Classification: 23.21 VRIJDRAGENDE VLOEREN (NL/SfB (4 cijfers)); Vloer (ARCHICAD Classification); Material: _TenW_43_gietvloer Bolidt dolphine grey
Component Quantities - Component 1, Skin Thickness: 2 mm
Name | Component 1, Mass (kg) | Component 1, Projected Component/Skin Area (m2) | Component 1, Skin/Component Volume (m3)
23__Vloer-x | 155.172 | 96.9828 | 0.193966
23__Vloer-x | 27.1631 | 16.9769 | 0.0339539

# IfcBuildingElementProxy: _TenW_82_afw bamboe 30 (5)
Classification: 23.21 VRIJDRAGENDE VLOEREN (NL/SfB (4 cijfers)); Vloer (ARCHICAD Classification); Material: _TenW_82_afw bamboe
Component Quantities - Component 1, Skin Thickness: 30 mm
Name | In | Component 1, Mass (kg) | Component 1, Projected Component/Skin Area (m2) | Component 1, Skin/Component Volume (m3)
23__Vloer-x | Begane grond | 2.7784 | 0.168388 | 0.00505164
4 x 23__Vloer-x | 1e verdieping | 2.64 | 0.16 | 0.0048

# IfcColumn: Beton gewapend C 214 x 647, 28_Kolom_Kolom-x
In: Begane grond
Type - PredefinedType: COLUMN
Classification: Kolom (ARCHICAD Classification); 28.11 KOLOM-/LIGGERCONSTRUCTIES (NL/SfB (4 cijfers)); Material: Beton gewapend C
Pset_ColumnCommon - Slope: 90 deg; LoadBearing: yes; IsExternal: no; Reference: Beton gewapend C 214 x 647
BaseQuantities - Length: 3860 mm; Width: 214.001 mm; Depth: 646.6 mm; CrossSectionArea: 0.138373 m2; OuterSurfaceArea: 6.64384 m2; TotalSurfaceArea: 6.92059 m2; GrossSurfaceArea: 6.92059 m2; GrossVolume: 0.53412 m3; NetVolume: 0.53412 m3
Component Quantities - Component 1, Mass: 1228.48 kg; Component 1, Skin Thickness: 214.001 mm; Component 1, Rectangular Component Height: 646.6 mm; Component 1, Rectangular Component Width: 214.001 mm; Component 1, Component Cross Section Area: 0.138373 m2; Component 1, Skin/Component Volume: 0.53412 m3

# IfcColumn: Beton gewapend C 300 x 300 (24)
Type - PredefinedType: COLUMN
Classification: Kolom (ARCHICAD Classification); 28.11 KOLOM-/LIGGERCONSTRUCTIES (NL/SfB (4 cijfers)); Material: Beton gewapend C
Pset_ColumnCommon - Slope: 90 deg; LoadBearing: yes; IsExternal: no; Reference: Beton gewapend C 300 x 300
BaseQuantities - Length: 3860 mm
Name | In | Width (mm) = Depth (mm) = Component 1, Skin Thickness (mm) = Component 1, Rectangular Component Height (mm) = Component 1, Rectangular Component Width (mm) | CrossSectionArea (m2) = Component 1, Component Cross Section Area (m2) | OuterSurfaceArea (m2) | TotalSurfaceArea (m2) = GrossSurfaceArea (m2) | GrossVolume (m3) = NetVolume (m3) = Component 1, Skin/Component Volume (m3) | Component 1, Mass (kg)
12 x 28_Kolom_Kolom-x | Begane grond | 300 | 0.09 | 4.632 | 4.812 | 0.3474 | 799.02
28_Kolom_Kolom-x | Begane grond | 300.03 | 0.090018 | 4.63246 | 4.8125 | 0.347469 | 799.18
11 x 28_Kolom_Kolom-x | 1e verdieping | 300 | 0.09 | 4.632 | 4.812 | 0.3474 | 799.02

# IfcColumn: Beton gewapend C 647 x 214, 28_Kolom_Kolom-x
In: Begane grond
Type - PredefinedType: COLUMN
Classification: Kolom (ARCHICAD Classification); 28.11 KOLOM-/LIGGERCONSTRUCTIES (NL/SfB (4 cijfers)); Material: Beton gewapend C
Pset_ColumnCommon - Slope: 90 deg; LoadBearing: yes; IsExternal: no; Reference: Beton gewapend C 647 x 214
BaseQuantities - Length: 3860 mm; Width: 646.604 mm; Depth: 214 mm; CrossSectionArea: 0.138373 m2; OuterSurfaceArea: 6.64387 m2; TotalSurfaceArea: 6.92061 m2; GrossSurfaceArea: 6.92061 m2; GrossVolume: 0.534121 m3; NetVolume: 0.534121 m3
Component Quantities - Component 1, Mass: 1228.48 kg; Component 1, Skin Thickness: 646.604 mm; Component 1, Rectangular Component Height: 214 mm; Component 1, Rectangular Component Width: 646.604 mm; Component 1, Component Cross Section Area: 0.138373 m2; Component 1, Skin/Component Volume: 0.534121 m3

# IfcColumn: Beton gewapend C D350 (33)
Type - PredefinedType: COLUMN
Classification: Kolom (ARCHICAD Classification); 28.11 KOLOM-/LIGGERCONSTRUCTIES (NL/SfB (4 cijfers)); Material: Beton gewapend C
Pset_ColumnCommon - Slope: 90 deg; LoadBearing: yes; IsExternal: no; Reference: Beton gewapend C D350
BaseQuantities - Length: 3860 mm; Width: 350 mm; Depth: 350 mm; CrossSectionArea: 0.0962113 m2; OuterSurfaceArea: 4.23748 m2; TotalSurfaceArea: 4.42867 m2; GrossSurfaceArea: 4.42867 m2; GrossVolume: 0.368994 m3; NetVolume: 0.368994 m3
Component Quantities - Component 1, Mass: 848.686 kg; Component 1, Skin Thickness: 350 mm; Component 1, Component Cross Section Area: 0.0962113 m2; Component 1, Skin/Component Volume: 0.368994 m3
Name | In
18 x 28_Kolom_Kolom-x | Begane grond
15 x 28_Kolom_Kolom-x | 1e verdieping

# IfcColumn: HEA140 140 x 133 (3)
In: Begane grond
Type - PredefinedType: COLUMN
Classification: Kolom (ARCHICAD Classification); 28.11 KOLOM-/LIGGERCONSTRUCTIES (NL/SfB (4 cijfers)); Material: Metaal - Staal C
Pset_ColumnCommon - Slope: 90 deg; LoadBearing: yes; IsExternal: no; Reference: HEA140 140 x 133
BaseQuantities - CrossSectionArea: 0.003018 m2
Component Quantities - Component 1, Component Cross Section Area: 0.003018 m2
Name | Length (mm) | OuterSurfaceArea (m2) | TotalSurfaceArea (m2) = GrossSurfaceArea (m2) | GrossVolume (m3) = NetVolume (m3) = Component 1, Skin/Component Volume (m3) | Component 1, Mass (kg)
2 x 28_Kolom_Kolom-x | 2437 | 1.98615 | 1.99219 | 0.00735487 | 58.4712
28_Kolom_Kolom-x | 3530 | 2.87695 | 2.88299 | 0.0106535 | 84.6956

# IfcColumn: Metaal - Staal AFW 25 x 50 (8)
In: 1e verdieping
Type - PredefinedType: COLUMN
Classification: Kolom (ARCHICAD Classification); 28.11 KOLOM-/LIGGERCONSTRUCTIES (NL/SfB (4 cijfers)); Material: Metaal - Staal AFW
Pset_ColumnCommon - Slope: 90 deg; LoadBearing: yes; IsExternal: no; Reference: Metaal - Staal AFW 25 x 50
BaseQuantities - Length: 1820 mm; Width: 25 mm; Depth: 50 mm; CrossSectionArea: 0.00125 m2; OuterSurfaceArea: 0.273 m2; TotalSurfaceArea: 0.2755 m2; GrossSurfaceArea: 0.2755 m2; GrossVolume: 0.002275 m3; NetVolume: 0.002275 m3
Component Quantities - Component 1, Mass: 18.0862 kg; Component 1, Skin Thickness: 25 mm; Component 1, Rectangular Component Height: 50 mm; Component 1, Rectangular Component Width: 25 mm; Component 1, Component Cross Section Area: 0.00125 m2; Component 1, Skin/Component Volume: 0.002275 m3

# IfcColumn: Metaal - Staal AFW 50 x 20 (2)
In: 1e verdieping
Type - PredefinedType: COLUMN
Classification: Kolom (ARCHICAD Classification); 28.11 KOLOM-/LIGGERCONSTRUCTIES (NL/SfB (4 cijfers)); Material: Metaal - Staal AFW
Pset_ColumnCommon - LoadBearing: yes; IsExternal: no; Reference: Metaal - Staal AFW 50 x 20
BaseQuantities - Width: 50 mm; Depth: 20 mm; CrossSectionArea: 0.001 m2
Component Quantities - Component 1, Skin Thickness: 50 mm; Component 1, Rectangular Component Height: 20 mm; Component 1, Rectangular Component Width: 50 mm; Component 1, Component Cross Section Area: 0.001 m2
Name | Slope (deg) | Length (mm) | OuterSurfaceArea (m2) | TotalSurfaceArea (m2) = GrossSurfaceArea (m2) | GrossVolume (m3) = NetVolume (m3) = Component 1, Skin/Component Volume (m3) | Component 1, Mass (kg)
28_Kolom_Kolom-x | 78.3125 | 2046.48 | 0.285928 | 0.28797 | 0.00204234 | 16.2366
28_Kolom_Kolom-x | 78.3045 | 2046.54 | 0.285936 | 0.287979 | 0.0020424 | 16.2371

# IfcColumn: Metaal - Staal AFW 50 x 50 (15)
In: 1e verdieping
Type - PredefinedType: COLUMN
Classification: Kolom (ARCHICAD Classification); 28.11 KOLOM-/LIGGERCONSTRUCTIES (NL/SfB (4 cijfers)); Material: Metaal - Staal AFW
Pset_ColumnCommon - Slope: 90 deg; LoadBearing: yes; IsExternal: no; Reference: Metaal - Staal AFW 50 x 50
BaseQuantities - Length: 1950 mm; Width: 50 mm; Depth: 50 mm; CrossSectionArea: 0.0025 m2; OuterSurfaceArea: 0.39 m2; TotalSurfaceArea: 0.395 m2; GrossSurfaceArea: 0.395 m2; GrossVolume: 0.004875 m3; NetVolume: 0.004875 m3
Component Quantities - Component 1, Mass: 38.7563 kg; Component 1, Skin Thickness: 50 mm; Component 1, Rectangular Component Height: 50 mm; Component 1, Rectangular Component Width: 50 mm; Component 1, Component Cross Section Area: 0.0025 m2; Component 1, Skin/Component Volume: 0.004875 m3

# IfcColumn: Profiel vierkant 80 x 80 (9)
In: 2e verdieping
Type - PredefinedType: COLUMN
Classification: Kolom (ARCHICAD Classification); 28.11 KOLOM-/LIGGERCONSTRUCTIES (NL/SfB (4 cijfers)); Material: Metaal - RVS
Pset_ColumnCommon - Slope: 90 deg; LoadBearing: yes; IsExternal: no; Reference: Profiel vierkant 80 x 80
BaseQuantities - Length: 1250 mm; CrossSectionArea: 0.00230401 m2; OuterSurfaceArea: 0.72 m2; TotalSurfaceArea: 0.724608 m2; GrossSurfaceArea: 0.724608 m2; GrossVolume: 0.00288001 m3; NetVolume: 0.00288001 m3
Component Quantities - Component 1, Mass: 22.7521 kg; Component 1, Component Cross Section Area: 0.00230401 m2; Component 1, Skin/Component Volume: 0.00288001 m3

# IfcColumn: kolom raveling 300 x 300, 28_Kolom_Kolom-x
In: Begane grond
Type - PredefinedType: COLUMN
Classification: Kolom (ARCHICAD Classification); 28.11 KOLOM-/LIGGERCONSTRUCTIES (NL/SfB (4 cijfers)); Material: Beton gewapend prefab
Pset_ColumnCommon - Slope: 90 deg; LoadBearing: yes; IsExternal: no; Reference: kolom raveling 300 x 300
BaseQuantities - Length: 3425 mm; CrossSectionArea: 0.0890994 m2; OuterSurfaceArea: 3.98958 m2; TotalSurfaceArea: 4.16778 m2; GrossSurfaceArea: 4.16778 m2; GrossVolume: 0.305165 m3; NetVolume: 0.305165 m3
Component Quantities - Component 1, Mass: 732.397 kg; Component 1, Component Cross Section Area: 0.0890994 m2; Component 1, Skin/Component Volume: 0.305165 m3

# IfcCurtainWall: Curtain Wall Type (5)
Pset_CurtainWallCommon - Reference: Type vliesgevel; IsExternal: yes
BaseQuantities - Width: 250 mm
Name | In | Classification | Length (mm) | Height (mm) | GrossSideArea (m2) = NetSideArea (m2)
_Vliesgevel_Vl-01 | 1e verdieping | Vliesgevel (ARCHICAD Classification) | 20700 | 7420 | 77.9782
21_Vliesgevel_Wand-x | 2e verdieping | Vliesgevel (ARCHICAD Classification); 21.14 VLIESWANDEN (NL/SfB (4 cijfers)) | 6198.11 | 1117.15 | 4.19404
21_Vliesgevel_Wand-x | 2e verdieping | Vliesgevel (ARCHICAD Classification); 21.14 VLIESWANDEN (NL/SfB (4 cijfers)) | 9752.97 | 1182.26 | 11.1913
21_Vliesgevel_Wand-x | 2e verdieping | Vliesgevel (ARCHICAD Classification); 21.14 VLIESWANDEN (NL/SfB (4 cijfers)) | 8382.07 | 1182.26 | 9.57051
21_Vliesgevel_Wand-x | 2e verdieping | Vliesgevel (ARCHICAD Classification); 21.14 VLIESWANDEN (NL/SfB (4 cijfers)) | 6972.5 | 1182.26 | 7.90403

# IfcDoor: D1 24 (12)
Type - OperationType: SINGLE_SWING_LEFT; ParameterTakesPrecedence: no; Sizeable: no
OverallHeight: 2367 mm; Classification: Deur (ARCHICAD Classification); 32.31 DRAAIDEUREN (NL/SfB (4 cijfers))
Pset_DoorCommon - Reference: 32_n.v.t.; IsExternal: no
Material - Frame / Draaiend deel: n.v.t.; Deurblad: n.v.t.; Onderdorpel: n.v.t.; Stofdorpel: n.v.t.; Vensterbank: n.v.t.; Ventilatierooster: n.v.t.; Spouwlat: n.v.t.; Rollaag / Latei: n.v.t.; Afwerking dagkant buiten: n.v.t.; Afwerking dagkant binnen: n.v.t.; Zonwering - behuizing: n.v.t.; Zonwering - isolatie: n.v.t.; Glas: Glas - algemeen
BaseQuantities - Height: 2367 mm
Name | In | OverallWidth (mm) | Width (mm) | Perimeter (mm) | Area (m2) | Volume (m3) = NetVolume (m3) = Component 1, Skin/Component Volume (m3) | Depth (mm) | FireRating
32_Deur_He-05 | Begane grond | 1084 | 1084 | 6902 | 2.56583 | 0.130814 | 488
32_Deur_Hi-02 | Begane grond | 1034 | 1034 | 6802 | 2.44748 | 0.125832 | 100 | n.v.t.
32_Deur_Hi-05a | Begane grond | 1034 | 1034 | 6802 | 2.44748 | 0.0770825 | 100 | n.v.t.
32_Deur_Hi-01a | Begane grond | 1034 | 1034 | 6802 | 2.44748 | 0.0938825 | 100 | n.v.t.
32_Deur_He-05a | Begane grond | 1284 | 1284 | 7302 | 3.03923 | 0.150742 | 488
32_Deur_Hi-01 | Begane grond | 1034 | 969.979 | 6673.96 | 2.29594 | 0.0650825 | 60 | n.v.t.
2 x 32_Deur_Hi-01a | 1e verdieping | 1034 | 1034 | 6802 | 2.44748 | 0.0938825 | 100 | n.v.t.
4 x 32_Deur_Hi-01 | 1e verdieping | 1034 | 1034 | 6802 | 2.44748 | 0.125832 | 100 | n.v.t.

# IfcDoor: D1 24 (18)
Type - OperationType: SINGLE_SWING_RIGHT; ParameterTakesPrecedence: no; Sizeable: no
OverallWidth: 1034 mm
Pset_DoorCommon - IsExternal: no
Material - Frame / Draaiend deel: n.v.t.; Deurblad: n.v.t.; Onderdorpel: n.v.t.; Stofdorpel: n.v.t.; Vensterbank: n.v.t.; Ventilatierooster: n.v.t.; Spouwlat: n.v.t.; Rollaag / Latei: n.v.t.; Afwerking dagkant buiten: n.v.t.; Afwerking dagkant binnen: n.v.t.; Zonwering - behuizing: n.v.t.; Zonwering - isolatie: n.v.t.; Glas: Glas - algemeen
BaseQuantities - Depth: 100 mm
Name | In | OverallHeight (mm) | Classification | Reference | FireRating | Height (mm) | Width (mm) | Perimeter (mm) | Area (m2) | Volume (m3) = NetVolume (m3) = Component 1, Skin/Component Volume (m3)
32_Deur_Hi-10 | Begane grond | 1600 | Deur (ARCHICAD Classification); 32.31 DRAAIDEUREN (NL/SfB (4 cijfers)) | 32_n.v.t. | n.v.t. | 1600 | 1034 | 5268 | 1.6544 | 0.0865038
32_Deur_Hi-01s | Begane grond | 2367 | Deur (ARCHICAD Classification); 32.31 DRAAIDEUREN (NL/SfB (4 cijfers)) | 32_n.v.t. | n.v.t. | 2318 | 1034 | 6704 | 2.39681 | 0.125832
4 x 32_Deur_Hi-01s | Begane grond | 2367 | Deur (ARCHICAD Classification); 32.31 DRAAIDEUREN (NL/SfB (4 cijfers)) | 32_n.v.t. | n.v.t. | 2367 | 1034 | 6802 | 2.44748 | 0.125832
32_Deur_Hi-01s | Begane grond | 2367 | Deur (ARCHICAD Classification); 32.31 DRAAIDEUREN (NL/SfB (4 cijfers)) | 32_n.v.t. | n.v.t. | 2367 | 1015.43 | 6764.85 | 2.40352 | 0.0650825
32_Deur_Hi-01as | Begane grond | 2367 | Deur (ARCHICAD Classification); 32.31 DRAAIDEUREN (NL/SfB (4 cijfers)) | 32_n.v.t. | n.v.t. | 2367 | 1034 | 6802 | 2.44748 | 0.0938825
_Deur_lift | Begane grond | 2367 | Deur (ARCHICAD Classification) | _n.v.t. | n.v.t. | 2367 | 1034 | 6802 | 2.44748 | 0.125832
_Deur_Hi-01s | Begane grond | 2367 | Deur (ARCHICAD Classification) | _n.v.t. | n.v.t. | 2367 | 1034 | 6802 | 2.44748 | 0.125832
32_Deur_Hi-05 | Begane grond | 2367 | Deur (ARCHICAD Classification); 32.31 DRAAIDEUREN (NL/SfB (4 cijfers)) | 32_n.v.t. | 30 | 2367 | 1034 | 6802 | 2.44748 | 0.0770825
4 x 32_Deur_Hi-01s | 1e verdieping | 2367 | Deur (ARCHICAD Classification); 32.31 DRAAIDEUREN (NL/SfB (4 cijfers)) | 32_n.v.t. | n.v.t. | 2367 | 1034 | 6802 | 2.44748 | 0.125832
2 x 32_Deur_Hi-03 | 1e verdieping | 2367 | Deur (ARCHICAD Classification); 32.31 DRAAIDEUREN (NL/SfB (4 cijfers)) | 32_n.v.t. | 30 | 2367 | 1034 | 6802 | 2.44748 | 0.125832
32_Deur_lift | 1e verdieping | 2367 | Deur (ARCHICAD Classification); 32.31 DRAAIDEUREN (NL/SfB (4 cijfers)) | 32_n.v.t. |  | 2367 | 1034 | 6802 | 2.44748 | 0.125832

# IfcDoor: D1 bl 24 (5)
Type - OperationType: SINGLE_SWING_LEFT; ParameterTakesPrecedence: no; Sizeable: no
OverallHeight: 2800 mm; Classification: Deur (ARCHICAD Classification); 32.31 DRAAIDEUREN (NL/SfB (4 cijfers))
Pset_DoorCommon - Reference: 32_n.v.t.; FireRating: n.v.t.; IsExternal: no
Material - Frame / Draaiend deel: n.v.t.; Deurblad: n.v.t.; Onderdorpel: n.v.t.; Stofdorpel: n.v.t.; Vensterbank: n.v.t.; Ventilatierooster: n.v.t.; Spouwlat: n.v.t.; Rollaag / Latei: n.v.t.; Afwerking dagkant buiten: n.v.t.; Afwerking dagkant binnen: n.v.t.; Zonwering - behuizing: n.v.t.; Zonwering - isolatie: n.v.t.; Glas: Glas - algemeen
BaseQuantities - Height: 2800 mm; Depth: 100 mm
Name | In | OverallWidth (mm) = Width (mm) | Perimeter (mm) | Area (m2) | Volume (m3) = NetVolume (m3) = Component 1, Skin/Component Volume (m3)
2 x 32_Deur_Hi-06 | Begane grond | 1134 | 7868 | 3.1752 | 0.150961
2 x 32_Deur_Hi-07 | Begane grond | 1034 | 7668 | 2.8952 | 0.140142
32_Deur_Hi-07 | 1e verdieping | 1034 | 7668 | 2.8952 | 0.140142

# IfcDoor: D1 bl 24 (8)
Type - OperationType: SINGLE_SWING_RIGHT; ParameterTakesPrecedence: no; Sizeable: no
Pset_DoorCommon - IsExternal: no
Material - Frame / Draaiend deel: n.v.t.; Deurblad: n.v.t.; Onderdorpel: n.v.t.; Stofdorpel: n.v.t.; Vensterbank: n.v.t.; Ventilatierooster: n.v.t.; Spouwlat: n.v.t.; Rollaag / Latei: n.v.t.; Afwerking dagkant buiten: n.v.t.; Afwerking dagkant binnen: n.v.t.; Zonwering - behuizing: n.v.t.; Zonwering - isolatie: n.v.t.; Glas: Glas - algemeen
Name | In | OverallHeight (mm) = Height (mm) | OverallWidth (mm) = Width (mm) | Classification | Reference | Perimeter (mm) | Area (m2) | Volume (m3) = NetVolume (m3) = Component 1, Skin/Component Volume (m3) | Depth (mm)
6 x 32_Deur_He-06 | Begane grond | 2800 | 1084 | Deur (ARCHICAD Classification); 32.31 DRAAIDEUREN (NL/SfB (4 cijfers)) | 32_n.v.t. | 7768 | 3.0352 | 0.0949719 | 574
32_Deur_He-01 | Begane grond | 3050 | 1084 | Deur (ARCHICAD Classification); 32.31 DRAAIDEUREN (NL/SfB (4 cijfers)) | 32_n.v.t. | 8268 | 3.3062 | 0.0987909 | 498
_Deur_Hi-07s | 1e verdieping | 2800 | 1034 | Deur (ARCHICAD Classification) | _n.v.t. | 7668 | 2.8952 | 0.140142 | 100 | Pset_DoorCommon - FireRating: n.v.t.

# IfcDoor: D1 bl zl1-b 24 (13)
Type - OperationType: SINGLE_SWING_LEFT; ParameterTakesPrecedence: no; Sizeable: no
Classification: Deur (ARCHICAD Classification); 32.31 DRAAIDEUREN (NL/SfB (4 cijfers))
Pset_DoorCommon - Reference: 32_n.v.t.; IsExternal: no
Material - Frame / Draaiend deel: n.v.t.; Deurblad: n.v.t.; Onderdorpel: n.v.t.; Stofdorpel: n.v.t.; Vensterbank: n.v.t.; Ventilatierooster: n.v.t.; Spouwlat: n.v.t.; Rollaag / Latei: n.v.t.; Afwerking dagkant buiten: n.v.t.; Afwerking dagkant binnen: n.v.t.; Zonwering - behuizing: n.v.t.; Zonwering - isolatie: n.v.t.; Glas: Glas - algemeen
Name | In | OverallHeight (mm) = Height (mm) | OverallWidth (mm) = Width (mm) | Perimeter (mm) | Area (m2) | Volume (m3) = NetVolume (m3) | Depth (mm) | Component 1, Skin/Component Volume (m3) | FireRating
4 x 32_Deur_He-08s | Begane grond | 3050 | 2190 | 10480 | 6.6795 | 0.146479 | 498 | 0.146479
32_Deur_Hi-43s | Begane grond | 2800 | 1900 | 9400 | 5.32 | 0.142064 | 100 |  | n.v.t.
32_Deur_Hi-16 | Begane grond | 2800 | 1500 | 8600 | 4.2 | 0.132534 | 100 |  | n.v.t.
32_Deur_Hi-50 | Begane grond | 2800 | 1600 | 8800 | 4.48 | 0.121933 | 100 | 0.121933 | n.v.t.
32_Deur_Hi-14 | Begane grond | 2800 | 3000 | 11600 | 8.4 | 0.15529 | 100 | 0.15529 | n.v.t.
32_Deur_He-07 | Begane grond | 2800 | 3951.44 | 13502.9 | 11.064 | 0.164008 | 424 | 0.164008
32_Deur_Hi-52 | Begane grond | 2800 | 2100 | 9800 | 5.88 | 0.133846 | 100 | 0.133846 | n.v.t.
32_Deur_Hi-42s | 1e verdieping | 2800 | 1586 | 8772 | 4.4408 | 0.1096 | 100 | 0.1096 | n.v.t.
32_Deur_Hi-52 | 1e verdieping | 2800 | 2100 | 9800 | 5.88 | 0.133846 | 100 | 0.133846 | n.v.t.
32_Deur_Hi-50 | 1e verdieping | 2800 | 1600 | 8800 | 4.48 | 0.121933 | 100 | 0.121933 | n.v.t.

# IfcDoor: D1 bl zl1-b 24 (13)
Type - OperationType: SINGLE_SWING_RIGHT; ParameterTakesPrecedence: no; Sizeable: no
Classification: Deur (ARCHICAD Classification); 32.31 DRAAIDEUREN (NL/SfB (4 cijfers))
Pset_DoorCommon - Reference: 32_n.v.t.; IsExternal: no
Material - Frame / Draaiend deel: n.v.t.; Deurblad: n.v.t.; Onderdorpel: n.v.t.; Stofdorpel: n.v.t.; Vensterbank: n.v.t.; Ventilatierooster: n.v.t.; Spouwlat: n.v.t.; Rollaag / Latei: n.v.t.; Afwerking dagkant buiten: n.v.t.; Afwerking dagkant binnen: n.v.t.; Zonwering - behuizing: n.v.t.; Zonwering - isolatie: n.v.t.; Glas: Glas - algemeen
Name | In | OverallHeight (mm) = Height (mm) | OverallWidth (mm) = Width (mm) | Perimeter (mm) | Area (m2) | Volume (m3) = NetVolume (m3) | Depth (mm) | Component 1, Skin/Component Volume (m3) | FireRating
2 x 32_Deur_He-08 | Begane grond | 3050 | 2190 | 10480 | 6.6795 | 0.146479 | 498 | 0.146479
32_Deur_Hi-43 | Begane grond | 2800 | 1900 | 9400 | 5.32 | 0.142064 | 125 |  | n.v.t.
32_Deur_Hi-13 | Begane grond | 2800 | 2300 | 10200 | 6.44 | 0.138611 | 100 | 0.138611 | n.v.t.
32_Deur_He-07s | Begane grond | 2800 | 3951.44 | 13502.9 | 11.064 | 0.164008 | 424 | 0.164008
32_Deur_Hi-52s | Begane grond | 2800 | 2100 | 9800 | 5.88 | 0.133846 | 100 | 0.133846 | n.v.t.
32_Deur_Hi-44 | Begane grond | 2800 | 3350 | 12300 | 9.38 | 0.163629 | 100 | 0.163629 | 30
32_Deur_Hi-42 | 1e verdieping | 2800 | 1586 | 8772 | 4.4408 | 0.1096 | 100 | 0.1096 | n.v.t.
32_Deur_Hi-44 | 1e verdieping | 2800 | 3350 | 12300 | 9.38 | 0.163629 | 100 | 0.163629 | 30
32_Deur_Hi-50s | 1e verdieping | 2800 | 1600 | 8800 | 4.48 | 0.121933 | 100 | 0.121933 | n.v.t.
32_Deur_Hi-11 | 1e verdieping | 2800 | 2000 | 9600 | 5.6 | 0.131464 | 100 | 0.131464 | n.v.t.
32_Deur_Hi-52s | 1e verdieping | 2800 | 2100 | 9800 | 5.88 | 0.133846 | 100 | 0.133846 | n.v.t.
32_Deur_Hi-12 | 1e verdieping | 2800 | 2300 | 10200 | 6.44 | 0.138611 | 100 | 0.138611 | n.v.t.

# IfcDoor: D1 bl zl2 24 (2)
Type - OperationType: USERDEFINED; ParameterTakesPrecedence: no; Sizeable: no
OverallHeight: 2800 mm
Pset_DoorCommon - IsExternal: no
Material - Frame / Draaiend deel: n.v.t.; Deurblad: n.v.t.; Onderdorpel: n.v.t.; Stofdorpel: n.v.t.; Vensterbank: n.v.t.; Ventilatierooster: n.v.t.; Spouwlat: n.v.t.; Rollaag / Latei: n.v.t.; Afwerking dagkant buiten: n.v.t.; Afwerking dagkant binnen: n.v.t.; Zonwering - behuizing: n.v.t.; Zonwering - isolatie: n.v.t.; Glas: Glas - algemeen
BaseQuantities - Height: 2800 mm
Name | In | OverallWidth (mm) = Width (mm) | Classification | Reference | Perimeter (mm) | Area (m2) | Volume (m3) = NetVolume (m3) = Component 1, Skin/Component Volume (m3) | Depth (mm)
32_Deur_He-02 | Begane grond | 3839.85 | Deur (ARCHICAD Classification); 32.31 DRAAIDEUREN (NL/SfB (4 cijfers)) | 32_n.v.t. | 13279.7 | 10.7516 | 0.178507 | 488
_Deur_Hi-15 | 1e verdieping | 2800 | Deur (ARCHICAD Classification) | _n.v.t. | 11200 | 7.84 | 0.169897 | 100 | Pset_DoorCommon - FireRating: n.v.t.

# IfcDoor: D2 24 (5)
In: Begane grond
Type - OperationType: DOUBLE_DOOR_SINGLE_SWING; ParameterTakesPrecedence: no; Sizeable: no
OverallHeight: 2367 mm
Pset_DoorCommon - FireRating: n.v.t.; IsExternal: no
Material - Frame / Draaiend deel: n.v.t.; Deurblad: n.v.t.; Onderdorpel: n.v.t.; Stofdorpel: n.v.t.; Vensterbank: n.v.t.; Ventilatierooster: n.v.t.; Spouwlat: n.v.t.; Rollaag / Latei: n.v.t.; Afwerking dagkant buiten: n.v.t.; Afwerking dagkant binnen: n.v.t.; Zonwering - behuizing: n.v.t.; Zonwering - isolatie: n.v.t.; Glas: Glas - algemeen
BaseQuantities - Height: 2367 mm; Depth: 100 mm
Name | OverallWidth (mm) = Width (mm) | Classification | Reference | Perimeter (mm) | Area (m2) | Volume (m3) = NetVolume (m3) = Component 1, Skin/Component Volume (m3)
2 x 32_Deur_Hi-09 | 1865 | Deur (ARCHICAD Classification); 32.31 DRAAIDEUREN (NL/SfB (4 cijfers)) | 32_n.v.t. | 8464 | 4.41446 | 0.208632
3 x _Deur_Hi-08 | 1831 | Deur (ARCHICAD Classification) | _n.v.t. | 8396 | 4.33398 | 0.205244

# IfcDoor: D2 bl 24, 32_Deur_Hi-17
In: Begane grond
Type - OperationType: DOUBLE_DOOR_SINGLE_SWING; ParameterTakesPrecedence: no; Sizeable: no
OverallHeight: 2800 mm; OverallWidth: 1831 mm; Classification: Deur (ARCHICAD Classification); 32.31 DRAAIDEUREN (NL/SfB (4 cijfers))
Pset_DoorCommon - Reference: 32_n.v.t.; FireRating: 30; IsExternal: no
Material - Frame / Draaiend deel: n.v.t.; Deurblad: n.v.t.; Onderdorpel: n.v.t.; Stofdorpel: n.v.t.; Vensterbank: n.v.t.; Ventilatierooster: n.v.t.; Spouwlat: n.v.t.; Rollaag / Latei: n.v.t.; Afwerking dagkant buiten: n.v.t.; Afwerking dagkant binnen: n.v.t.; Zonwering - behuizing: n.v.t.; Zonwering - isolatie: n.v.t.; Glas: Glas - algemeen
BaseQuantities - Height: 2800 mm; Width: 1831 mm; Perimeter: 9262 mm; Area: 5.1268 m2; Volume: 0.140343 m3; Depth: 100 mm; NetVolume: 0.140343 m3
Component Quantities - Component 1, Skin/Component Volume: 0.140343 m3

# IfcDoor: D2 bl zl1 24 (2)
In: Begane grond
Type - OperationType: USERDEFINED; ParameterTakesPrecedence: no; Sizeable: no
OverallHeight: 2800 mm; Classification: Deur (ARCHICAD Classification); 32.31 DRAAIDEUREN (NL/SfB (4 cijfers))
Pset_DoorCommon - Reference: 32_n.v.t.; FireRating: 30; IsExternal: no
Material - Frame / Draaiend deel: n.v.t.; Deurblad: n.v.t.; Onderdorpel: n.v.t.; Stofdorpel: n.v.t.; Vensterbank: n.v.t.; Ventilatierooster: n.v.t.; Spouwlat: n.v.t.; Rollaag / Latei: n.v.t.; Afwerking dagkant buiten: n.v.t.; Afwerking dagkant binnen: n.v.t.; Zonwering - behuizing: n.v.t.; Zonwering - isolatie: n.v.t.; Glas: Glas - algemeen
BaseQuantities - Height: 2800 mm; Depth: 100 mm
Name | OverallWidth (mm) = Width (mm) | Perimeter (mm) | Area (m2) | Volume (m3) = NetVolume (m3) = Component 1, Skin/Component Volume (m3)
32_Deur_Hi-18 | 2424.27 | 10448.5 | 6.78796 | 0.172788
32_Deur_Hi-19 | 2995.12 | 11590.2 | 8.38634 | 0.186389

# IfcDoor: D2 bl zl2 24 (13)
Type - OperationType: USERDEFINED; ParameterTakesPrecedence: no; Sizeable: no
Classification: Deur (ARCHICAD Classification); 32.31 DRAAIDEUREN (NL/SfB (4 cijfers))
Pset_DoorCommon - Reference: 32_n.v.t.; IsExternal: no
Material - Frame / Draaiend deel: n.v.t.; Deurblad: n.v.t.; Onderdorpel: n.v.t.; Stofdorpel: n.v.t.; Vensterbank: n.v.t.; Ventilatierooster: n.v.t.; Spouwlat: n.v.t.; Rollaag / Latei: n.v.t.; Afwerking dagkant buiten: n.v.t.; Afwerking dagkant binnen: n.v.t.; Zonwering - behuizing: n.v.t.; Zonwering - isolatie: n.v.t.; Glas: Glas - algemeen
Name | In | OverallHeight (mm) = Height (mm) | OverallWidth (mm) = Width (mm) | Perimeter (mm) | Area (m2) | Volume (m3) = NetVolume (m3) = Component 1, Skin/Component Volume (m3) | Depth (mm) | FireRating
32_Deur_He-04 | Begane grond | 3050 | 2621.72 | 11343.4 | 7.99625 | 0.173977 | 574
32_Deur_He-03 | Begane grond | 3050 | 2366 | 10832 | 7.2163 | 0.168225 | 574
32_Deur_Hi-51 | Begane grond | 2800 | 3150 | 11900 | 8.82 | 0.209172 | 100 | n.v.t.
32_Deur_Hi-21 | Begane grond | 2800 | 2550 | 10700 | 7.14 | 0.194876 | 100 | n.v.t.
32_Deur_Hi-20 | Begane grond | 2800 | 2350 | 10300 | 6.58 | 0.190111 | 100 | n.v.t.
32_Deur_Hi-23 | Begane grond | 2800 | 3700 | 13000 | 10.36 | 0.222276 | 100 | 30
32_Deur_Hi-24 | Begane grond | 2800 | 4300 | 14200 | 12.04 | 0.236572 | 100 | n.v.t.
32_Deur_Hi-25 | Begane grond | 2800 | 4300 | 14200 | 12.04 | 0.237508 | 100 | 30
32_Deur_Hi-51 | 1e verdieping | 2800 | 3150 | 11900 | 8.82 | 0.209172 | 100 | n.v.t.
32_Deur_Hi-26 | 1e verdieping | 2800 | 4500 | 14600 | 12.6 | 0.246318 | 100 | 30
32_Deur_Hi-27 | 1e verdieping | 2800 | 4650 | 14900 | 13.02 | 0.249892 | 100 | 30
32_Deur_Hi-54 | 1e verdieping | 2800 | 3150 | 11900 | 8.82 | 0.209172 | 100 | n.v.t.
32_Deur_Hi-22 | 1e verdieping | 2800 | 3300 | 12200 | 9.24 | 0.217727 | 100 | 30

# IfcDoor: DS1 in wand 24 (11)
In: Begane grond
Type - OperationType: USERDEFINED; ParameterTakesPrecedence: no; Sizeable: no
Classification: Deur (ARCHICAD Classification); 32.31 DRAAIDEUREN (NL/SfB (4 cijfers))
Pset_DoorCommon - Reference: 32_n.v.t.; IsExternal: no
Material - Frame / Draaiend deel: n.v.t.; Deurblad: n.v.t.; Onderdorpel: n.v.t.; Stofdorpel: n.v.t.; Vensterbank: n.v.t.; Spouwlat: n.v.t.; Rollaag / Latei: n.v.t.; Afwerking dagkant buiten: n.v.t.; Afwerking dagkant binnen: n.v.t.; Zonwering - behuizing: n.v.t.; Zonwering - isolatie: n.v.t.; Glas: Glas - algemeen
BaseQuantities - Depth: 125 mm
Name | OverallHeight (mm) = Height (mm) | OverallWidth (mm) = Width (mm) | FireRating | Perimeter (mm) | Area (m2) | Volume (m3) = NetVolume (m3) = Component 1, Skin/Component Volume (m3)
2 x 32_Deur_Si-05 | 2370 | 1075 | n.v.t. | 6890 | 2.54775 | 0.203929
32_Deur_Si-05s | 2300 | 1034 | n.v.t. | 6668 | 2.3782 | 0.197661
32_Deur_Si-05s | 2370 | 1075 | n.v.t. | 6890 | 2.54775 | 0.203929
3 x 32_Deur_Si-04 | 2370 | 1075 | n.v.t. | 6890 | 2.54775 | 0.203929
32_Deur_Si-06 | 2370 | 1075 | 30 | 6890 | 2.54775 | 0.203929
3 x 32_Deur_Si-04s | 2370 | 1075 | n.v.t. | 6890 | 2.54775 | 0.203929

# IfcDoor: DV1 24 (9)
Type - OperationType: FOLDING_TO_LEFT; ParameterTakesPrecedence: no; Sizeable: no
OverallHeight: 2800 mm; Classification: Deur (ARCHICAD Classification); 32.31 DRAAIDEUREN (NL/SfB (4 cijfers))
Pset_DoorCommon - Reference: 32_n.v.t.; FireRating: n.v.t.; IsExternal: no
Material - Frame / Draaiend deel: n.v.t.; Deurblad: n.v.t.; Onderdorpel: n.v.t.; Stofdorpel: n.v.t.; Vensterbank: n.v.t.; Ventilatierooster: n.v.t.; Spouwlat: n.v.t.; Rollaag / Latei: n.v.t.; Afwerking dagkant buiten: n.v.t.; Afwerking dagkant binnen: n.v.t.; Zonwering - behuizing: n.v.t.; Zonwering - isolatie: n.v.t.; Glas: Glas - algemeen
BaseQuantities - Height: 2800 mm; Depth: 100 mm
Name | In | OverallWidth (mm) = Width (mm) | Perimeter (mm) | Area (m2) | Volume (m3) = NetVolume (m3) = Component 1, Skin/Component Volume (m3)
2 x 32_Deur_Si-02 | Begane grond | 3000 | 11600 | 8.4 | 0.150028
2 x 32_Deur_Si-03 | Begane grond | 2700 | 11000 | 7.56 | 0.14542
32_Deur_Si-01 | Begane grond | 3000 | 11600 | 8.4 | 0.150028
4 x 32_Deur_Si-02 | 1e verdieping | 3000 | 11600 | 8.4 | 0.150028

# IfcDoor: DV1 24 (10)
Type - OperationType: FOLDING_TO_RIGHT; ParameterTakesPrecedence: no; Sizeable: no
OverallHeight: 2800 mm; OverallWidth: 3000 mm; Classification: Deur (ARCHICAD Classification); 32.31 DRAAIDEUREN (NL/SfB (4 cijfers))
Pset_DoorCommon - Reference: 32_n.v.t.; FireRating: n.v.t.; IsExternal: no
Material - Frame / Draaiend deel: n.v.t.; Deurblad: n.v.t.; Onderdorpel: n.v.t.; Stofdorpel: n.v.t.; Vensterbank: n.v.t.; Ventilatierooster: n.v.t.; Spouwlat: n.v.t.; Rollaag / Latei: n.v.t.; Afwerking dagkant buiten: n.v.t.; Afwerking dagkant binnen: n.v.t.; Zonwering - behuizing: n.v.t.; Zonwering - isolatie: n.v.t.; Glas: Glas - algemeen
BaseQuantities - Height: 2800 mm; Width: 3000 mm; Perimeter: 11600 mm; Area: 8.4 m2; Volume: 0.150028 m3; Depth: 100 mm; NetVolume: 0.150028 m3
Component Quantities - Component 1, Skin/Component Volume: 0.150028 m3
Name | In
4 x 32_Deur_Si-02s | Begane grond
6 x 32_Deur_Si-02s | 1e verdieping

# IfcMember: Boundary Frame 50 x 220 (64)
In: 1e verdieping
Type - PredefinedType: MULLION
Classification: Vliesgevel - kader (ARCHICAD Classification); Material: Metaal - Staal AFW
BaseQuantities - CrossSectionArea: 0.011 m2
Name | Slope (deg) | Length (mm) | OuterSurfaceArea (m2) | TotalSurfaceArea (m2) = GrossSurfaceArea (m2) | GrossVolume (m3) = NetVolume (m3)
_Vliesgevel - kader_Kader-x | 90 | 1190.04 | 0.642622 | 0.664622 | 0.0130905 | Component Quantities - Component 1, Mass: 99.3387 kg; Component 1, Skin/Component Volume: 0.0124954 m3
_Vliesgevel - kader_Kader-x | 0 | 1250 | 0.675 | 0.697 | 0.01375 | Component Quantities - Component 1, Mass: 104.344 kg; Component 1, Skin/Component Volume: 0.013125 m3
17 x _Vliesgevel - kader_Kader-x | 0 | 1250 | 0.675 | 0.697 | 0.01375
2 x _Vliesgevel - kader_Kader-x | 0 | 1225.01 | 0.661504 | 0.683504 | 0.0134751 | Component Quantities - Component 1, Mass: 102.307 kg; Component 1, Skin/Component Volume: 0.0128688 m3
_Vliesgevel - kader_Kader-x | 0 | 349.96 | 0.188978 | 0.210978 | 0.00384956 | Component Quantities - Component 1, Mass: 29.2129 kg; Component 1, Skin/Component Volume: 0.00367458 m3
_Vliesgevel - kader_Kader-x | 0 | 899.965 | 0.485981 | 0.507981 | 0.00989961 | Component Quantities - Component 1, Mass: 75.1246 kg; Component 1, Skin/Component Volume: 0.00944963 m3
_Vliesgevel - kader_Kader-x | 0 | 24.9597 | 0.0134783 | 0.0354783 | 0.000274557 | Component Quantities - Component 1, Mass: 0.00000141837 kg; Component 1, Skin/Component Volume: 1.78411e-10 m3
_Vliesgevel - kader_Kader-x | 0 | 350.035 | 0.189019 | 0.211019 | 0.00385039 | Component Quantities - Component 1, Mass: 29.2192 kg; Component 1, Skin/Component Volume: 0.00367537 m3
_Vliesgevel - kader_Kader-x | 90 | 3915 | 2.1141 | 2.1361 | 0.043065 | Component Quantities - Component 1, Mass: 326.854 kg; Component 1, Skin/Component Volume: 0.0411137 m3
_Vliesgevel - kader_Kader-x | 90 | 1265.56 | 0.683402 | 0.705402 | 0.0139212 | Component Quantities - Component 1, Mass: 105.593 kg; Component 1, Skin/Component Volume: 0.0132821 m3
_Vliesgevel - kader_Kader-x | 0 | 925 | 0.4995 | 0.5215 | 0.010175 | Component Quantities - Component 1, Mass: 77.1647 kg; Component 1, Skin/Component Volume: 0.00970625 m3
_Vliesgevel - kader_Kader-x | 0 | 350 | 0.189 | 0.211 | 0.00385 | Component Quantities - Component 1, Mass: 29.2163 kg; Component 1, Skin/Component Volume: 0.003675 m3
4 x _Vliesgevel - kader_Kader-x | 0 | 350 | 0.189 | 0.211 | 0.00385
_Vliesgevel - kader_Kader-x | 0 | 1275 | 0.6885 | 0.7105 | 0.014025 | Component Quantities - Component 1, Mass: 106.381 kg; Component 1, Skin/Component Volume: 0.0133813 m3
_Vliesgevel - kader_Kader-x | 90 | 1220.56 | 0.659102 | 0.681102 | 0.0134262 | Component Quantities - Component 1, Mass: 101.886 kg; Component 1, Skin/Component Volume: 0.0128159 m3
_Vliesgevel - kader_Kader-x | 90 | 3410 | 1.8414 | 1.8634 | 0.03751 | Component Quantities - Component 1, Mass: 284.749 kg; Component 1, Skin/Component Volume: 0.0358175 m3
_Vliesgevel - kader_Kader-x | 0 | 324.984 | 0.175491 | 0.197491 | 0.00357482 | Component Quantities - Component 1, Mass: 27.1777 kg; Component 1, Skin/Component Volume: 0.00341858 m3
_Vliesgevel - kader_Kader-x | 0.00000447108 | 900 | 0.486 | 0.508 | 0.0099 | Component Quantities - Component 1, Mass: 75.1275 kg; Component 1, Skin/Component Volume: 0.00945 m3
_Vliesgevel - kader_Kader-x | 0.00000447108 | 350 | 0.189 | 0.211 | 0.00385
6 x _Vliesgevel - kader_Kader-x | 0 | 900 | 0.486 | 0.508 | 0.0099
_Vliesgevel - kader_Kader-x | 7.26984e-14 | 350 | 0.189 | 0.211 | 0.00385
_Vliesgevel - kader_Kader-x | 2.82703e-14 | 900.04 | 0.486022 | 0.508022 | 0.00990044 | Component Quantities - Component 1, Mass: 75.1309 kg; Component 1, Skin/Component Volume: 0.00945042 m3
_Vliesgevel - kader_Kader-x | 0 | 349.96 | 0.188978 | 0.210978 | 0.00384956
_Vliesgevel - kader_Kader-x | 0 | 350.035 | 0.189019 | 0.211019 | 0.00385038 | Component Quantities - Component 1, Mass: 29.2192 kg; Component 1, Skin/Component Volume: 0.00367537 m3
_Vliesgevel - kader_Kader-x | 0 | 899.965 | 0.485981 | 0.507981 | 0.00989962 | Component Quantities - Component 1, Mass: 75.1246 kg; Component 1, Skin/Component Volume: 0.00944963 m3
_Vliesgevel - kader_Kader-x | 90 | 634.956 | 0.342876 | 0.364876 | 0.00698452 | Component Quantities - Component 1, Mass: 53.0526 kg; Component 1, Skin/Component Volume: 0.00667329 m3
_Vliesgevel - kader_Kader-x | 90 | 1240.56 | 0.669902 | 0.691902 | 0.0136462 | Component Quantities - Component 1, Mass: 103.556 kg; Component 1, Skin/Component Volume: 0.0130259 m3
_Vliesgevel - kader_Kader-x | 90 | 1174.96 | 0.634478 | 0.656478 | 0.0129245 | Component Quantities - Component 1, Mass: 98.1294 kg; Component 1, Skin/Component Volume: 0.0123433 m3
_Vliesgevel - kader_Kader-x | 90 | 1550 | 0.837 | 0.859 | 0.01705 | Component Quantities - Component 1, Mass: 129.386 kg; Component 1, Skin/Component Volume: 0.016275 m3
_Vliesgevel - kader_Kader-x | 0 | 325 | 0.1755 | 0.1975 | 0.003575 | Component Quantities - Component 1, Mass: 27.1791 kg; Component 1, Skin/Component Volume: 0.00341875 m3
_Vliesgevel - kader_Kader-x | 0.00000671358 | 350 | 0.189 | 0.211 | 0.00385
_Vliesgevel - kader_Kader-x | 0.00000671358 | 324.984 | 0.175491 | 0.197491 | 0.00357482 | Component Quantities - Component 1, Mass: 27.1777 kg; Component 1, Skin/Component Volume: 0.00341858 m3
_Vliesgevel - kader_Kader-x | 0.00000945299 | 900 | 0.486 | 0.508 | 0.0099 | Component Quantities - Component 1, Mass: 71.55 kg; Component 1, Skin/Component Volume: 0.009 m3
_Vliesgevel - kader_Kader-x | 0.0000272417 | 375 | 0.2025 | 0.2245 | 0.004125 | Component Quantities - Component 1, Mass: 29.8125 kg; Component 1, Skin/Component Volume: 0.00375 m3
_Vliesgevel - kader_Kader-x | 0.00000984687 | 925 | 0.4995 | 0.5215 | 0.010175 | Component Quantities - Component 1, Mass: 73.5375 kg; Component 1, Skin/Component Volume: 0.00925 m3
_Vliesgevel - kader_Kader-x | 0.00000945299 | 350 | 0.189 | 0.211 | 0.00385 | Component Quantities - Component 1, Mass: 27.825 kg; Component 1, Skin/Component Volume: 0.0035 m3
_Vliesgevel - kader_Kader-x | 90 | 1579.48 | 0.852922 | 0.874922 | 0.0173743 | Component Quantities - Component 1, Mass: 131.847 kg; Component 1, Skin/Component Volume: 0.0165846 m3
_Vliesgevel - kader_Kader-x | 0 | 1300 | 0.702 | 0.724 | 0.0143 | Component Quantities - Component 1, Mass: 103.35 kg; Component 1, Skin/Component Volume: 0.013 m3
_Vliesgevel - kader_Kader-x | 0 | 1300 | 0.702 | 0.724 | 0.0143

# IfcMember: Boundary Frame 80 x 250 (84)
In: 2e verdieping
Type - PredefinedType: MULLION
Classification: Vliesgevel - kader (ARCHICAD Classification); Material: Metaal - Staal AFW
BaseQuantities - CrossSectionArea: 0.02 m2
Name | Slope (deg) | Length (mm) | OuterSurfaceArea (m2) | TotalSurfaceArea (m2) = GrossSurfaceArea (m2) | GrossVolume (m3) = NetVolume (m3)
_Vliesgevel - kader_Kader-x | 19.3701 | 183.284 | 0.120967 | 0.160967 | 0.00366568 | Component Quantities - Component 1, Mass: 28.5008 kg; Component 1, Skin/Component Volume: 0.00358501 m3
_Vliesgevel - kader_Kader-x | 4.84674e-08 | 657.188 | 0.433744 | 0.473744 | 0.0131438 | Component Quantities - Component 1, Mass: 101.511 kg; Component 1, Skin/Component Volume: 0.0127687 m3
_Vliesgevel - kader_Kader-x | 7.3372e-08 | 1000 | 0.66 | 0.7 | 0.02 | Component Quantities - Component 1, Mass: 154.23 kg; Component 1, Skin/Component Volume: 0.0194 m3
22 x _Vliesgevel - kader_Kader-x | 0 | 1000 | 0.66 | 0.7 | 0.02
21 x _Vliesgevel - kader_Kader-x | 1.27222e-14 | 1000 | 0.66 | 0.7 | 0.02
_Vliesgevel - kader_Kader-x | 6.95339e-07 | 444.185 | 0.293162 | 0.333162 | 0.00888369 | Component Quantities - Component 1, Mass: 68.642 kg; Component 1, Skin/Component Volume: 0.00863421 m3
_Vliesgevel - kader_Kader-x | 2.79665 | 1010.33 | 0.66682 | 0.70682 | 0.0202067 | Component Quantities - Component 1, Mass: 155.824 kg; Component 1, Skin/Component Volume: 0.0196005 m3
4 x _Vliesgevel - kader_Kader-x | 2.79665 | 1010.33 | 0.66682 | 0.70682 | 0.0202067
_Vliesgevel - kader_Kader-x | 2.79665 | 624.529 | 0.412189 | 0.452189 | 0.0124906 | Component Quantities - Component 1, Mass: 96.4011 kg; Component 1, Skin/Component Volume: 0.0121259 m3
_Vliesgevel - kader_Kader-x | 19.8332 | 1040.08 | 0.686451 | 0.726451 | 0.0208015 | Component Quantities - Component 1, Mass: 160.668 kg; Component 1, Skin/Component Volume: 0.0202098 m3
_Vliesgevel - kader_Kader-x | 2.79665 | 310.34 | 0.204825 | 0.244825 | 0.00620681 | Component Quantities - Component 1, Mass: 47.985 kg; Component 1, Skin/Component Volume: 0.00603585 m3
_Vliesgevel - kader_Kader-x | 19.3896 | 128.355 | 0.0847142 | 0.124714 | 0.0025671 | Component Quantities - Component 1, Mass: 19.8895 kg; Component 1, Skin/Component Volume: 0.00250182 m3
_Vliesgevel - kader_Kader-x | 1.96586e-14 | 647.159 | 0.427125 | 0.467125 | 0.0129432 | Component Quantities - Component 1, Mass: 99.9047 kg; Component 1, Skin/Component Volume: 0.0125666 m3
_Vliesgevel - kader_Kader-x | 5.27199e-07 | 1000 | 0.66 | 0.7 | 0.02
_Vliesgevel - kader_Kader-x | 0.00000208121 | 469 | 0.30954 | 0.34954 | 0.00938 | Component Quantities - Component 1, Mass: 72.4281 kg; Component 1, Skin/Component Volume: 0.00911045 m3
_Vliesgevel - kader_Kader-x | 19.4354 | 127.689 | 0.084275 | 0.124275 | 0.00255379 | Component Quantities - Component 1, Mass: 19.7878 kg; Component 1, Skin/Component Volume: 0.00248903 m3
_Vliesgevel - kader_Kader-x | 19.4355 | 1005.29 | 0.663493 | 0.703493 | 0.0201059 | Component Quantities - Component 1, Mass: 155.197 kg; Component 1, Skin/Component Volume: 0.0195217 m3
_Vliesgevel - kader_Kader-x | 0 | 731.069 | 0.482505 | 0.522505 | 0.0146214 | Component Quantities - Component 1, Mass: 112.904 kg; Component 1, Skin/Component Volume: 0.0142017 m3
2 x _Vliesgevel - kader_Kader-x | 5.5589e-07 | 1000 | 0.66 | 0.7 | 0.02
_Vliesgevel - kader_Kader-x | 4.43793e-07 | 920.156 | 0.607303 | 0.647303 | 0.0184031 | Component Quantities - Component 1, Mass: 142.068 kg; Component 1, Skin/Component Volume: 0.0178702 m3
_Vliesgevel - kader_Kader-x | 19.3896 | 1007.2 | 0.664755 | 0.704755 | 0.0201441 | Component Quantities - Component 1, Mass: 155.494 kg; Component 1, Skin/Component Volume: 0.0195589 m3
_Vliesgevel - kader_Kader-x | 1.41372e-07 | 798.599 | 0.527075 | 0.567075 | 0.015972 | Component Quantities - Component 1, Mass: 123.262 kg; Component 1, Skin/Component Volume: 0.0155047 m3
2 x _Vliesgevel - kader_Kader-x | 19.4355 | 127.689 | 0.084275 | 0.124275 | 0.00255379
_Vliesgevel - kader_Kader-x | 19.4355 | 574.773 | 0.37935 | 0.41935 | 0.0114955 | Component Quantities - Component 1, Mass: 88.6473 kg; Component 1, Skin/Component Volume: 0.0111506 m3
_Vliesgevel - kader_Kader-x | 19.4355 | 430.519 | 0.284143 | 0.324143 | 0.00861039 | Component Quantities - Component 1, Mass: 66.5499 kg; Component 1, Skin/Component Volume: 0.00837106 m3
_Vliesgevel - kader_Kader-x | 0 | 60.6676 | 0.0400406 | 0.0800406 | 0.00121335 | Component Quantities - Component 1, Mass: 9.50769 kg; Component 1, Skin/Component Volume: 0.00119594 m3
_Vliesgevel - kader_Kader-x | 19.3896 | 68.0192 | 0.0448927 | 0.0848927 | 0.00136038 | Component Quantities - Component 1, Mass: 10.4906 kg; Component 1, Skin/Component Volume: 0.00131957 m3
_Vliesgevel - kader_Kader-x | 19.3896 | 60.3356 | 0.0398215 | 0.0798215 | 0.00120671 | Component Quantities - Component 1, Mass: 9.39888 kg; Component 1, Skin/Component Volume: 0.00118225 m3
_Vliesgevel - kader_Kader-x | 5.27199e-07 | 946.668 | 0.624801 | 0.664801 | 0.0189334 | Component Quantities - Component 1, Mass: 146.098 kg; Component 1, Skin/Component Volume: 0.0183771 m3
_Vliesgevel - kader_Kader-x | 0.00000652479 | 219.665 | 0.144979 | 0.184979 | 0.00439329 | Component Quantities - Component 1, Mass: 34.0313 kg; Component 1, Skin/Component Volume: 0.00428066 m3
2 x _Vliesgevel - kader_Kader-x | 19.3896 | 1007.2 | 0.664755 | 0.704755 | 0.0201441
_Vliesgevel - kader_Kader-x | 19.3896 | 128.355 | 0.0847142 | 0.124714 | 0.0025671
_Vliesgevel - kader_Kader-x | 5.27199e-07 | 226.446 | 0.149454 | 0.189454 | 0.00452892 | Component Quantities - Component 1, Mass: 35.0181 kg; Component 1, Skin/Component Volume: 0.00440479 m3
_Vliesgevel - kader_Kader-x | 0.0000026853 | 499.443 | 0.329632 | 0.369632 | 0.00998885 | Component Quantities - Component 1, Mass: 77.1814 kg; Component 1, Skin/Component Volume: 0.00970835 m3
_Vliesgevel - kader_Kader-x | 0.0000124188 | 109.248 | 0.0721037 | 0.112104 | 0.00218496 | Component Quantities - Component 1, Mass: 16.9435 kg; Component 1, Skin/Component Volume: 0.00213126 m3
_Vliesgevel - kader_Kader-x | 19.4355 | 1005.29 | 0.663493 | 0.703493 | 0.0201059
_Vliesgevel - kader_Kader-x | 5.5589e-07 | 371.317 | 0.245069 | 0.285069 | 0.00742633 | Component Quantities - Component 1, Mass: 57.4191 kg; Component 1, Skin/Component Volume: 0.00722253 m3

# IfcMember: IfcMember (4)
Classification: Trap - constructie (ARCHICAD Classification); Material: Metaal - Staal C
Name | In | GrossVolume (m3) = NetVolume (m3) = Component 1, Skin/Component Volume (m3) | Component 1, Mass (kg)
2 x _Trap - constructie_Trapconstructie-x | Begane grond | 0.0344035 | 273.508
2 x _Trap - constructie_Trapconstructie-x | 1e verdieping | 0.0192835 | 153.304

# IfcMember: IfcMember (21)
Type - ElementType: Rail; PredefinedType: USERDEFINED
Classification: Reling - regel (ARCHICAD Classification); Material: Metaal - RVS
Name | In | GrossVolume (m3) = NetVolume (m3) | Length (mm) | Component 1, Mass (kg) | Component 1, Skin/Component Volume (m3)
2 x _Reling - regel_Einde bovenregel-x | Begane grond | 0.0001 | 100 | 0.79 | 0.0001
_Reling - regel_Bovenregel-x | Begane grond | 0.00461958 | 4619.58 | 36.4947 | 0.00461958
6 x _Reling - regel_Einde handregel 1-x | Begane grond | 0.0001872 | 200 | 1.47888 | 0.0001872
_Reling - regel_Handregel-x | Begane grond | 0.00637836 | 6814.49 | 50.3891 | 0.00637836
2 x _Reling - regel_Handregel-x | Begane grond | 0.00424941 | 4542.99 | 33.5703 | 0.00424941
2 x _Reling - regel_Handregel-x | Begane grond | 0.000951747 | 1022.88 | 7.5188 | 0.000951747
2 x _Reling - regel_Handregel-x | Begane grond | 0.00182528 | 1953.11 | 14.4197 | 0.00182528
2 x _Reling - regel_Einde handregel 1-x | Begane grond | 0.0001872 | 200
_Reling - regel_Handregel-x | Begane grond | 0.00637836 | 6814.49
_Reling - regel_Bovenregel-x | 1e verdieping | 0.00124731 | 1596.21 | 9.85371 | 0.00124731
_Reling - regel_Regel-x | 1e verdieping | 0.00124731 | 1596.21 | 9.85371 | 0.00124731

# IfcMember: IfcMember (31)
Type - ElementType: Stair Riser; PredefinedType: USERDEFINED
Classification: Trap - stootbord (ARCHICAD Classification)
Name | In | Material | GrossVolume (m3) = NetVolume (m3) = Component 1, Skin/Component Volume (m3) | Component 1, Mass (kg)
_Trap - stootbord_Stootbord-x | Begane grond | Hout - Vloer | 0.0424259 | 23.3342
_Trap - stootbord_Stootbord-x | Begane grond | Hout - Vloer | 0.0407482 | 22.4115
_Trap - stootbord_Stootbord-x | Begane grond | Hout - Vloer | 0.0390705 | 21.4888
_Trap - stootbord_Stootbord-x | Begane grond | Hout - Vloer | 0.0373928 | 20.566
_Trap - stootbord_Stootbord-x | Begane grond | Hout - Vloer | 0.0357151 | 19.6433
_Trap - stootbord_Stootbord-x | Begane grond | Hout - Vloer | 0.0340374 | 18.7206
_Trap - stootbord_Stootbord-x | Begane grond | Hout - Vloer | 0.0323597 | 17.7978
_Trap - stootbord_Stootbord-x | Begane grond | Hout - Vloer | 0.030682 | 16.8751
8 x _Trap - stootbord_Stootbord-x | Begane grond | Beton gewapend prefab vloer | 0.0633598 | 152.064
6 x _Trap - stootbord_Stootbord-x | 1e verdieping | Hout - Vloer | 0.00338688 | 1.86278
6 x _Trap - stootbord_Stootbord-x | 1e verdieping | Hout - Vloer | 0.00350802 | 1.92941
3 x _Trap - stootbord_Stootbord-x | 1e verdieping | Beton gewapend prefab vloer | 0.0792 | 190.08

# IfcMember: IfcMember (53)
Type - ElementType: Stair Tread; PredefinedType: USERDEFINED
Classification: Trap - trede (ARCHICAD Classification)
Name | In | GrossVolume (m3) = NetVolume (m3)
_Trap - trede_Traptrede-x | Begane grond | 0.141235 | Material: Hout - Vloer; Component Quantities - Component 1, Mass: 77.6793 kg; Component 1, Skin/Component Volume: 0.141235 m3
_Trap - trede_Traptrede-x | Begane grond | 0.135537 | Material: Hout - Vloer; Component Quantities - Component 1, Mass: 74.5456 kg; Component 1, Skin/Component Volume: 0.135537 m3
_Trap - trede_Traptrede-x | Begane grond | 0.12984 | Material: Hout - Vloer; Component Quantities - Component 1, Mass: 71.4119 kg; Component 1, Skin/Component Volume: 0.12984 m3
_Trap - trede_Traptrede-x | Begane grond | 0.124142 | Material: Hout - Vloer; Component Quantities - Component 1, Mass: 68.2781 kg; Component 1, Skin/Component Volume: 0.124142 m3
_Trap - trede_Traptrede-x | Begane grond | 0.118444 | Material: Hout - Vloer; Component Quantities - Component 1, Mass: 65.1444 kg; Component 1, Skin/Component Volume: 0.118444 m3
_Trap - trede_Traptrede-x | Begane grond | 0.112747 | Material: Hout - Vloer; Component Quantities - Component 1, Mass: 62.0107 kg; Component 1, Skin/Component Volume: 0.112747 m3
_Trap - trede_Traptrede-x | Begane grond | 0.107049 | Material: Hout - Vloer; Component Quantities - Component 1, Mass: 58.8769 kg; Component 1, Skin/Component Volume: 0.107049 m3
_Trap - trede_Traptrede-x | Begane grond | 0.0979284 | Material: Hout - Vloer; Component Quantities - Component 1, Mass: 53.8606 kg; Component 1, Skin/Component Volume: 0.0979284 m3
7 x _Trap - trede_Traptrede-x | Begane grond | 0.951172
_Trap - trede_Traptrede-x | Begane grond | 0.856132
21 x _Trap - trede_Traptrede-x | Begane grond | 0.174052
_Trap - trede_Traptrede-x | Begane grond | 0.142451
5 x _Trap - trede_Traptrede-x | 1e verdieping | 0.00528192 | Material: Hout - Vloer; Component Quantities - Component 1, Mass: 2.90506 kg; Component 1, Skin/Component Volume: 0.00528192 m3
_Trap - trede_Traptrede-x | 1e verdieping | 0.0048384 | Material: Hout - Vloer; Component Quantities - Component 1, Mass: 2.66112 kg; Component 1, Skin/Component Volume: 0.0048384 m3
5 x _Trap - trede_Traptrede-x | 1e verdieping | 0.00547084 | Material: Hout - Vloer; Component Quantities - Component 1, Mass: 3.00896 kg; Component 1, Skin/Component Volume: 0.00547084 m3
_Trap - trede_Traptrede-x | 1e verdieping | 0.00501145 | Material: Hout - Vloer; Component Quantities - Component 1, Mass: 2.7563 kg; Component 1, Skin/Component Volume: 0.00501145 m3
2 x _Trap - trede_Traptrede-x | 1e verdieping | 1.18897
_Trap - trede_Traptrede-x | 1e verdieping | 1.07017

# IfcMember: IfcMember (14)
In: 1e verdieping
Type - PredefinedType: MEMBER
Classification: Onderdeel (ARCHICAD Classification); Material: Hout AFW
BaseQuantities - GrossVolume: 0.00021375 m3; Length: 2137.5 mm; NetVolume: 0.00021375 m3
Name
_Onderdeel_Spijlen-x | Component Quantities - Component 1, Mass: 0.117563 kg; Component 1, Skin/Component Volume: 0.00021375 m3
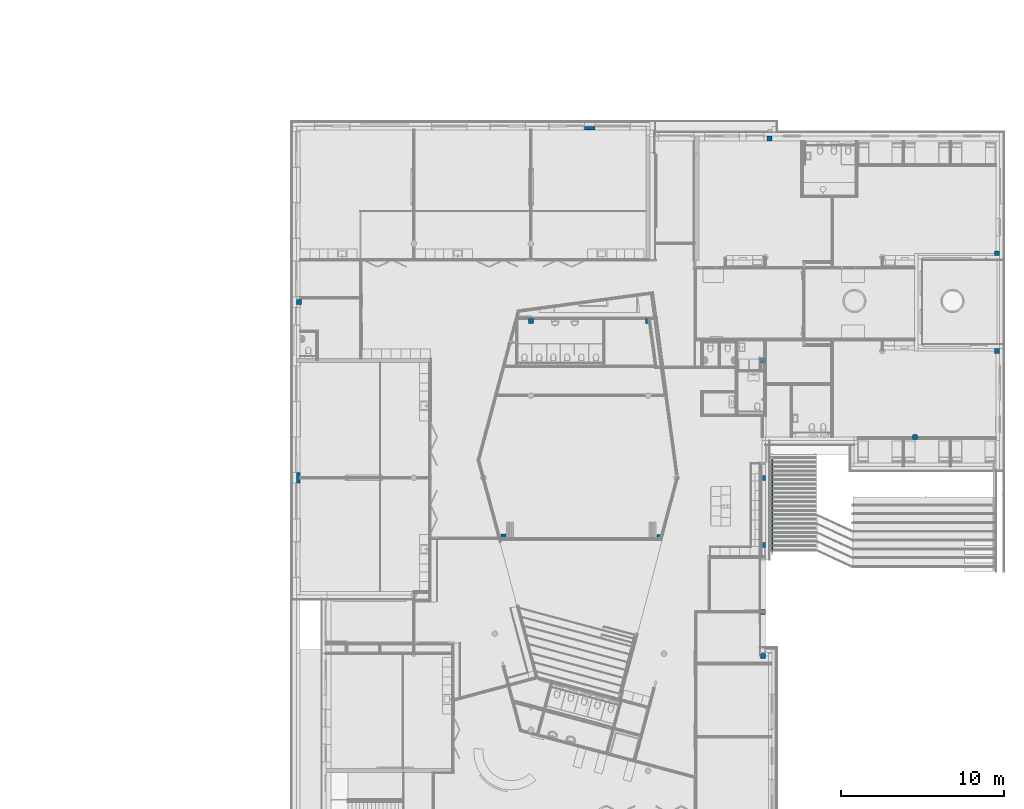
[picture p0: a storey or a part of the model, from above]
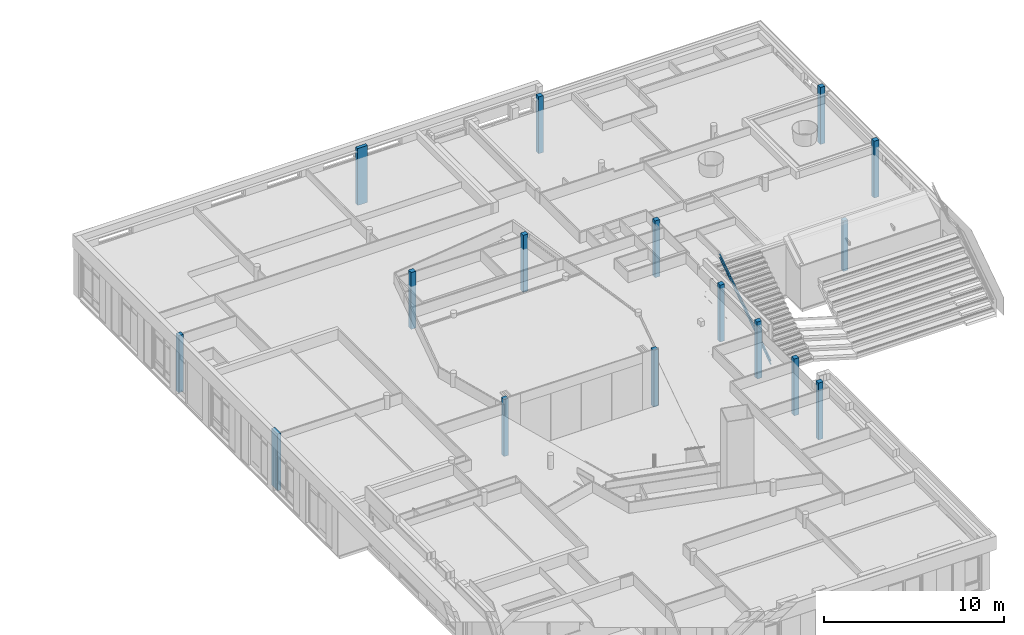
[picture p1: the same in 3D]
Properties of the parts of a building model (IFC2X3), part 4 of 5

# IfcMember: IfcMember (14)
Name
13 x _Onderdeel_Spijlen-x

# IfcMember: IfcMember (3)
In: 1e verdieping
Type - PredefinedType: POST
Classification: Reling - baluster (ARCHICAD Classification); Material: Metaal - RVS
BaseQuantities - GrossVolume: 0.000167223 m3; Length: 2140 mm; NetVolume: 0.000167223 m3
Name
_Reling - baluster_Hoofdbaluster-x | Component Quantities - Component 1, Mass: 1.32106 kg; Component 1, Skin/Component Volume: 0.000167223 m3
_Reling - baluster_Hoofdbaluster-x
_Reling - baluster_Baluster-x

# IfcMember: Mullion Frame 50 x 220 (39)
In: 1e verdieping
Type - PredefinedType: MULLION
Classification: Vliesgevel - kader (ARCHICAD Classification); Material: Metaal - Staal AFW
Pset_MemberCommon - Slope: 90 deg
BaseQuantities - CrossSectionArea: 0.011 m2
Name | Length (mm) | OuterSurfaceArea (m2) | TotalSurfaceArea (m2) = GrossSurfaceArea (m2) | GrossVolume (m3) = NetVolume (m3)
_Vliesgevel - kader_Kader-x | 1190.04 | 0.642622 | 0.664622 | 0.0130905 | Component Quantities - Component 1, Mass: 94.6083 kg; Component 1, Skin/Component Volume: 0.0119004 m3
_Vliesgevel - kader_Kader-x | 1215.04 | 0.656122 | 0.678122 | 0.0133655 | Component Quantities - Component 1, Mass: 96.5958 kg; Component 1, Skin/Component Volume: 0.0121504 m3
2 x _Vliesgevel - kader_Kader-x | 1190.04 | 0.642622 | 0.664622 | 0.0130905
_Vliesgevel - kader_Kader-x | 3890 | 2.1006 | 2.1226 | 0.04279 | Component Quantities - Component 1, Mass: 309.255 kg; Component 1, Skin/Component Volume: 0.0389 m3
_Vliesgevel - kader_Kader-x | 3890 | 2.1006 | 2.1226 | 0.04279
_Vliesgevel - kader_Kader-x | 584.956 | 0.315876 | 0.337876 | 0.00643452 | Component Quantities - Component 1, Mass: 46.504 kg; Component 1, Skin/Component Volume: 0.00584956 m3
_Vliesgevel - kader_Kader-x | 584.956 | 0.315876 | 0.337876 | 0.00643451
5 x _Vliesgevel - kader_Kader-x | 584.956 | 0.315876 | 0.337876 | 0.00643452
_Vliesgevel - kader_Kader-x | 2139.44 | 1.1553 | 1.1773 | 0.0235338 | Component Quantities - Component 1, Mass: 170.086 kg; Component 1, Skin/Component Volume: 0.0213944 m3
7 x _Vliesgevel - kader_Kader-x | 2139.44 | 1.1553 | 1.1773 | 0.0235338
_Vliesgevel - kader_Kader-x | 3430 | 1.8522 | 1.8742 | 0.03773 | Component Quantities - Component 1, Mass: 272.685 kg; Component 1, Skin/Component Volume: 0.0343 m3
4 x _Vliesgevel - kader_Kader-x | 3430 | 1.8522 | 1.8742 | 0.03773
_Vliesgevel - kader_Kader-x | 609.956 | 0.329376 | 0.351376 | 0.00670952 | Component Quantities - Component 1, Mass: 48.4915 kg; Component 1, Skin/Component Volume: 0.00609956 m3
_Vliesgevel - kader_Kader-x | 2725.04 | 1.47152 | 1.49352 | 0.0299755 | Component Quantities - Component 1, Mass: 216.641 kg; Component 1, Skin/Component Volume: 0.0272504 m3
_Vliesgevel - kader_Kader-x | 2699.96 | 1.45798 | 1.47998 | 0.0296995 | Component Quantities - Component 1, Mass: 214.647 kg; Component 1, Skin/Component Volume: 0.0269996 m3
_Vliesgevel - kader_Kader-x | 1240.56 | 0.669902 | 0.691902 | 0.0136462 | Component Quantities - Component 1, Mass: 98.6245 kg; Component 1, Skin/Component Volume: 0.0124056 m3
_Vliesgevel - kader_Kader-x | 1149.96 | 0.620978 | 0.642978 | 0.0126495 | Component Quantities - Component 1, Mass: 91.4217 kg; Component 1, Skin/Component Volume: 0.0114996 m3
_Vliesgevel - kader_Kader-x | 1550 | 0.837 | 0.859 | 0.01705 | Component Quantities - Component 1, Mass: 123.225 kg; Component 1, Skin/Component Volume: 0.0155 m3
_Vliesgevel - kader_Kader-x | 2699.96 | 1.45798 | 1.47998 | 0.0296995
_Vliesgevel - kader_Kader-x | 2725.04 | 1.47152 | 1.49352 | 0.0299755
_Vliesgevel - kader_Kader-x | 1579.48 | 0.852922 | 0.874922 | 0.0173743 | Component Quantities - Component 1, Mass: 125.569 kg; Component 1, Skin/Component Volume: 0.0157948 m3
_Vliesgevel - kader_Kader-x | 1504.48 | 0.812422 | 0.834422 | 0.0165493 | Component Quantities - Component 1, Mass: 119.607 kg; Component 1, Skin/Component Volume: 0.0150448 m3
3 x _Vliesgevel - kader_Kader-x | 1504.48 | 0.812422 | 0.834422 | 0.0165493

# IfcMember: Mullion Frame 80 x 250 (54)
In: 2e verdieping
Type - PredefinedType: MULLION
Classification: Vliesgevel - kader (ARCHICAD Classification); Material: Metaal - Staal AFW
Pset_MemberCommon - Slope: 20 deg
BaseQuantities - CrossSectionArea: 0.02 m2
Name | Length (mm) | OuterSurfaceArea (m2) | TotalSurfaceArea (m2) = GrossSurfaceArea (m2) | GrossVolume (m3) = NetVolume (m3)
_Vliesgevel - kader_Kader-x | 185.594 | 0.122492 | 0.162492 | 0.00371188 | Component Quantities - Component 1, Mass: 27.7388 kg; Component 1, Skin/Component Volume: 0.00348916 m3
_Vliesgevel - kader_Kader-x | 329.724 | 0.217618 | 0.257618 | 0.00659449 | Component Quantities - Component 1, Mass: 49.2806 kg; Component 1, Skin/Component Volume: 0.00619882 m3
_Vliesgevel - kader_Kader-x | 473.855 | 0.312744 | 0.352744 | 0.0094771 | Component Quantities - Component 1, Mass: 70.8224 kg; Component 1, Skin/Component Volume: 0.00890848 m3
_Vliesgevel - kader_Kader-x | 617.986 | 0.407871 | 0.447871 | 0.0123597 | Component Quantities - Component 1, Mass: 92.3641 kg; Component 1, Skin/Component Volume: 0.0116181 m3
_Vliesgevel - kader_Kader-x | 762.116 | 0.502997 | 0.542997 | 0.0152423 | Component Quantities - Component 1, Mass: 113.906 kg; Component 1, Skin/Component Volume: 0.0143278 m3
_Vliesgevel - kader_Kader-x | 906.247 | 0.598123 | 0.638123 | 0.0181249 | Component Quantities - Component 1, Mass: 135.448 kg; Component 1, Skin/Component Volume: 0.0170374 m3
_Vliesgevel - kader_Kader-x | 947.282 | 0.625206 | 0.665206 | 0.0189456 | Component Quantities - Component 1, Mass: 141.581 kg; Component 1, Skin/Component Volume: 0.0178089 m3
23 x _Vliesgevel - kader_Kader-x | 947.282 | 0.625206 | 0.665206 | 0.0189456
_Vliesgevel - kader_Kader-x | 74.9742 | 0.0494829 | 0.0894829 | 0.00149948 | Component Quantities - Component 1, Mass: 11.2056 kg; Component 1, Skin/Component Volume: 0.00140951 m3
22 x _Vliesgevel - kader_Kader-x | 74.9741 | 0.0494829 | 0.0894829 | 0.00149948
_Vliesgevel - kader_Kader-x | 42.2383 | 0.0278773 | 0.0678773 | 0.000844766 | Component Quantities - Component 1, Mass: 9.76394 kg; Component 1, Skin/Component Volume: 0.00122817 m3

# IfcMember: Transom Frame 50 x 220 (12)
In: 1e verdieping
Type - PredefinedType: MULLION
Classification: Vliesgevel - kader (ARCHICAD Classification); Material: Metaal - Staal AFW
Pset_MemberCommon - Slope: 0 deg
BaseQuantities - CrossSectionArea: 0.011 m2
Name | Length (mm) | OuterSurfaceArea (m2) | TotalSurfaceArea (m2) = GrossSurfaceArea (m2) | GrossVolume (m3) = NetVolume (m3)
_Vliesgevel - kader_Kader-x | 1200 | 0.648 | 0.67 | 0.0132 | Component Quantities - Component 1, Mass: 85.86 kg; Component 1, Skin/Component Volume: 0.0108 m3
3 x _Vliesgevel - kader_Kader-x | 1200 | 0.648 | 0.67 | 0.0132
_Vliesgevel - kader_Kader-x | 1175.01 | 0.634504 | 0.656504 | 0.0129251 | Component Quantities - Component 1, Mass: 84.0718 kg; Component 1, Skin/Component Volume: 0.0105751 m3
_Vliesgevel - kader_Kader-x | 299.96 | 0.161978 | 0.183978 | 0.00329956 | Component Quantities - Component 1, Mass: 21.4621 kg; Component 1, Skin/Component Volume: 0.00269964 m3
_Vliesgevel - kader_Kader-x | 849.965 | 0.458981 | 0.480981 | 0.00934962 | Component Quantities - Component 1, Mass: 60.815 kg; Component 1, Skin/Component Volume: 0.00764969 m3
_Vliesgevel - kader_Kader-x | 300.035 | 0.162019 | 0.184019 | 0.00330038 | Component Quantities - Component 1, Mass: 21.4675 kg; Component 1, Skin/Component Volume: 0.00270031 m3
4 x _Vliesgevel - kader_Kader-x | 1175.01 | 0.634504 | 0.656504 | 0.0129251

# IfcMember: Transom Frame 70 x 175 (26)
In: 2e verdieping
Type - PredefinedType: MULLION
Classification: Vliesgevel - kader (ARCHICAD Classification); Material: Metaal - Staal AFW
Pset_MemberCommon - Slope: 0 deg
BaseQuantities - CrossSectionArea: 0.01225 m2
Name | Length (mm) | OuterSurfaceArea (m2) | TotalSurfaceArea (m2) = GrossSurfaceArea (m2) | GrossVolume (m3) = NetVolume (m3)
_Vliesgevel - kader_Kader-x | 594.426 | 0.291269 | 0.315769 | 0.00728172 | Component Quantities - Component 1, Mass: 46.548 kg; Component 1, Skin/Component Volume: 0.0058551 m3
_Vliesgevel - kader_Kader-x | 920 | 0.4508 | 0.4753 | 0.01127 | Component Quantities - Component 1, Mass: 72.0429 kg; Component 1, Skin/Component Volume: 0.009062 m3
20 x _Vliesgevel - kader_Kader-x | 920 | 0.4508 | 0.4753 | 0.01127
_Vliesgevel - kader_Kader-x | 415.221 | 0.203458 | 0.227958 | 0.00508646 | Component Quantities - Component 1, Mass: 32.5149 kg; Component 1, Skin/Component Volume: 0.00408993 m3
_Vliesgevel - kader_Kader-x | 744.82 | 0.364962 | 0.389462 | 0.00912404 | Component Quantities - Component 1, Mass: 58.325 kg; Component 1, Skin/Component Volume: 0.00733648 m3
_Vliesgevel - kader_Kader-x | 173.713 | 0.0851194 | 0.109619 | 0.00212798 | Component Quantities - Component 1, Mass: 13.603 kg; Component 1, Skin/Component Volume: 0.00171107 m3
_Vliesgevel - kader_Kader-x | 55.4689 | 0.0271798 | 0.0516798 | 0.000679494 | Component Quantities - Component 1, Mass: 4.34363 kg; Component 1, Skin/Component Volume: 0.000546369 m3

# IfcOpeningElement (401)
Name | In | Depth (mm) | Height (mm) | Width (mm) | Area (m2) | Volume (m3)
3 x 31_Raam_He-12s | Begane grond | 574 | 2800 | 1084 | 3.0352 | 0.0880103
3 x 31_Raam_He-15 | Begane grond | 574 | 2800 | 1084 | 3.0352 | 0.0717972
3 x 31_Raam_He-12 | Begane grond | 574 | 2800 | 1084 | 3.0352 | 0.0880103
4 x 31_Raam_He-11 | Begane grond | 574 | 2800 | 2190 | 6.132 | 0.146623
31_Raam_He-11s | Begane grond | 574 | 2800 | 2190 | 6.132 | 0.146623
6 x 32_Deur_He-06 | Begane grond | 574 | 2800 | 1084 | 3.0352 | 0.0949719
_Lege opening_Doorvoer-x | Begane grond | 300 | 250 | 2159.92 | 0.53998 | 0.161994 | Classification: Lege opening (ARCHICAD Classification)
2 x 31_Raam_He-12s | Begane grond | 488 | 2800 | 1084 | 3.0352 | 0.0880103
2 x 31_Raam_He-11 | Begane grond | 488 | 2800 | 2190 | 6.132 | 0.146623
3 x 31_Raam_He-11s | Begane grond | 488 | 2800 | 2190 | 6.132 | 0.146623
32_Deur_He-04 | Begane grond | 574 | 3050 | 2621.72 | 7.99625 | 0.173977
4 x _Lege opening_Doorvoer-x | Begane grond | 300 | 250 | 1087.52 | 0.27188 | 0.081564 | Classification: Lege opening (ARCHICAD Classification)
15 x 31_Raam_- | Begane grond | 498 | 0 | 0 | 0 | 0
2 x 31_Raam_He-16 | Begane grond | 498 | 3050 | 2190 | 6.6795 | 0.157953
4 x 32_Deur_He-08s | Begane grond | 498 | 3050 | 2190 | 6.6795 | 0.146479
2 x 32_Deur_He-08 | Begane grond | 498 | 3050 | 2190 | 6.6795 | 0.146479
2 x 31_Raam_He-10 | Begane grond | 498 | 3050 | 2190 | 6.6795 | 0.152631
2 x 31_Raam_He-16 | Begane grond | 498 | 3050 | 2190 | 6.6795 | 0.166185
32_Deur_He-01 | Begane grond | 498 | 3050 | 1084 | 3.3062 | 0.0987909
3 x 31_Raam_He-18 | Begane grond | 574 | 2800 | 1084 | 3.0352 | 0.189281
31_Raam_He-09s | Begane grond | 574 | 2800 | 1082.52 | 3.03106 | 0.0879553
32_Deur_He-03 | Begane grond | 574 | 3050 | 2366 | 7.2163 | 0.168225
_Lege opening_Doorvoer-x | Begane grond | 574 | 480 | 2190 | 1.0512 | 0.603389 | Classification: Lege opening (ARCHICAD Classification)
_Lege opening_Doorvoer-x | Begane grond | 500 | 730 | 2168.34 | 1.58288 | 0.791442 | Classification: Lege opening (ARCHICAD Classification)
_Lege opening_Doorvoer-x | Begane grond | 500 | 730 | 1082.52 | 0.79024 | 0.39512 | Classification: Lege opening (ARCHICAD Classification)
2 x 31_Raam_He-09 | Begane grond | 488 | 2800 | 1082.52 | 3.03106 | 0.0879553
_Lege opening_Doorvoer-x | Begane grond | 414 | 500 | 2159.92 | 1.07996 | 0.447103 | Classification: Lege opening (ARCHICAD Classification)
_Lege opening_Doorvoer-x | Begane grond | 414 | 505 | 1083.94 | 0.54739 | 0.226619 | Classification: Lege opening (ARCHICAD Classification)
4 x 31_Raam_Hi-53 | Begane grond | 100 | 1600 | 2350 | 3.76 | 0.0891331
31_Raam_Hi-40 | Begane grond | 100 | 1600 | 1989.19 | 3.18271 | 0.0686434
2 x 32_Deur_Si-02 | Begane grond | 100 | 2800 | 3000 | 8.4 | 0.150028
4 x 32_Deur_Si-02s | Begane grond | 100 | 2800 | 3000 | 8.4 | 0.150028
_Lege opening_Doorvoer-x | Begane grond | 414 | 480 | 2159.9 | 1.03675 | 0.429215 | Classification: Lege opening (ARCHICAD Classification)
_Lege opening_Doorvoer-x | Begane grond | 470 | 480 | 2159.9 | 1.03675 | 0.487273 | Classification: Lege opening (ARCHICAD Classification)
5 x _Lege opening_Doorvoer-x | Begane grond | 488 | 460 | 2190 | 1.0074 | 0.487681 | Classification: Lege opening (ARCHICAD Classification)
6 x _Lege opening_Doorvoer-x | Begane grond | 488 | 460 | 2190 | 1.0074 | 0.491611 | Classification: Lege opening (ARCHICAD Classification)
31_Raam_Hi-49 | Begane grond | 125 | 595 | 1925 | 1.14538 | 0.0364485
32_Deur_Hi-43 | Begane grond | 125 | 2800 | 1900 | 5.32 | 0.142064
31_Raam_Hi-48 | Begane grond | 125 | 1200 | 825 | 0.99 | 0.0288869
2 x 32_Deur_Si-05 | Begane grond | 125 | 2370 | 1075 | 2.54775 | 0.203929
31_Raam_Hi-49 | Begane grond | 100 | 595 | 1925 | 1.14538 | 0.0364485
31_Raam_Hi-41 | Begane grond | 100 | 596.073 | 2345 | 1.39779 | 0.0428808
31_Raam_Hi-35 | Begane grond | 100 | 2800 | 2271.8 | 6.36103 | 0.0529332
31_Raam_Merk-x | Begane grond | 100 | 1270 | 1653.48 | 2.09993 | 0
32_Deur_Hi-43s | Begane grond | 100 | 2800 | 1900 | 5.32 | 0.142064
32_Deur_Hi-16 | Begane grond | 100 | 2800 | 1500 | 4.2 | 0.132534
31_Raam_Hi-38 | Begane grond | 125 | 1200 | 809.749 | 0.971699 | 0.0286539
32_Deur_Si-05s | Begane grond | 125 | 2300 | 1034 | 2.3782 | 0.197661
32_Deur_Hi-50 | Begane grond | 100 | 2800 | 1600 | 4.48 | 0.121933
32_Deur_Hi-14 | Begane grond | 100 | 2800 | 3000 | 8.4 | 0.15529
32_Deur_Hi-13 | Begane grond | 100 | 2800 | 2300 | 6.44 | 0.138611
31_Raam_Hi-29 | Begane grond | 100 | 2800 | 741.763 | 2.07694 | 0.0372927
31_Raam_Hi-33 | Begane grond | 100 | 2800 | 2100 | 5.88 | 0.0510915
32_Deur_He-05 | Begane grond | 488 | 2367 | 1084 | 2.56583 | 0.130814
31_Raam_Merk-x | Begane grond | 100 | 1689.83 | 2348.74 | 1.98449 | 0
32_Deur_Hi-10 | Begane grond | 100 | 1600 | 1034 | 1.6544 | 0.0865038
31_Raam_Merk-x | Begane grond | 125 | 1270 | 1640.98 | 2.08405 | 0
32_Deur_Si-05s | Begane grond | 125 | 2370 | 1075 | 2.54775 | 0.203929
3 x 32_Deur_Si-04 | Begane grond | 125 | 2370 | 1075 | 2.54775 | 0.203929
32_Deur_He-07s | Begane grond | 424 | 2800 | 3951.44 | 11.064 | 0.164008
32_Deur_He-07 | Begane grond | 424 | 2800 | 3951.44 | 11.064 | 0.164008
32_Deur_Hi-51 | Begane grond | 100 | 2800 | 3150 | 8.82 | 0.209172
32_Deur_Hi-21 | Begane grond | 100 | 2800 | 2550 | 7.14 | 0.194876
32_Deur_Hi-20 | Begane grond | 100 | 2800 | 2350 | 6.58 | 0.190111
32_Deur_Hi-52 | Begane grond | 100 | 2800 | 2100 | 5.88 | 0.133846
32_Deur_Hi-02 | Begane grond | 100 | 2367 | 1034 | 2.44748 | 0.125832
32_Deur_Hi-52s | Begane grond | 100 | 2800 | 2100 | 5.88 | 0.133846
32_Deur_Hi-01s | Begane grond | 100 | 2318 | 1034 | 2.39681 | 0.125832
4 x 32_Deur_Hi-01s | Begane grond | 100 | 2367 | 1034 | 2.44748 | 0.125832
32_Deur_Hi-01s | Begane grond | 100 | 2367 | 1015.43 | 2.40352 | 0.0650825
31_Raam_Merk-x | Begane grond | 100 | 1394.92 | 1747.4 | 1.27955 | 0
4 x _Lege opening_Doorvoer-x | Begane grond | 574 | 480 | 1087.52 | 0.52201 | 0.299634 | Classification: Lege opening (ARCHICAD Classification)
31_Raam_Hi-48a | Begane grond | 125 | 1200 | 825 | 0.99 | 0.0288869
32_Deur_Si-06 | Begane grond | 125 | 2370 | 1075 | 2.54775 | 0.203929
3 x 32_Deur_Si-04s | Begane grond | 125 | 2370 | 1075 | 2.54775 | 0.203929
32_Deur_He-02 | Begane grond | 488 | 2800 | 3839.85 | 10.7516 | 0.178507
2 x 31_Raam_Hi-47 | Begane grond | 100 | 1800 | 1800 | 3.24 | 0.0371555
32_Deur_Hi-23 | Begane grond | 100 | 2800 | 3700 | 10.36 | 0.222276
31_Raam_Hi-36 | Begane grond | 100 | 1100 | 706.829 | 0.777512 | 0.0179327
31_Raam_Hi-37 | Begane grond | 100 | 2200 | 1317.14 | 2.89772 | 0.0362673
32_Deur_Hi-05a | Begane grond | 100 | 2367 | 1034 | 2.44748 | 0.0770825
2 x 32_Deur_Hi-09 | Begane grond | 100 | 2367 | 1865 | 4.41446 | 0.208632
32_Deur_Hi-01a | Begane grond | 100 | 2367 | 1034 | 2.44748 | 0.0938825
32_Deur_Hi-01as | Begane grond | 100 | 2367 | 1034 | 2.44748 | 0.0938825
31_Raam_- | Begane grond | 100 | 1351.41 | 2195.5 | 1.48351 | 0
_Deur_lift | Begane grond | 100 | 2367 | 1034 | 2.44748 | 0.125832
3 x _Lege opening_Doorvoer-x | Begane grond | 574 | 480 | 2159.9 | 1.03675 | 0.595096 | Classification: Lege opening (ARCHICAD Classification)
3 x _Lege opening_Doorvoer-x | Begane grond | 574 | 480 | 1082.52 | 0.51961 | 0.298256 | Classification: Lege opening (ARCHICAD Classification)
31_Raam_- | Begane grond | 488 | 2419.79 | 3630.08 | 4.39201 | 0
32_Deur_He-05a | Begane grond | 488 | 2367 | 1284 | 3.03923 | 0.150742
_Lege opening_Doorvoer-x | Begane grond | 414 | 480 | 2159.97 | 1.03679 | 0.429229 | Classification: Lege opening (ARCHICAD Classification)
_Lege opening_Doorvoer-x | Begane grond | 414 | 480 | 1082.52 | 0.51961 | 0.215118 | Classification: Lege opening (ARCHICAD Classification)
_Lege opening_Doorvoer-x | Begane grond | 15 | 1200 | 2000 | 2.4 | 0.036 | Classification: Lege opening (ARCHICAD Classification)
32_Deur_Hi-24 | Begane grond | 100 | 2800 | 4300 | 12.04 | 0.236572
2 x 32_Deur_Hi-06 | Begane grond | 100 | 2800 | 1134 | 3.1752 | 0.150961
2 x 32_Deur_Hi-07 | Begane grond | 100 | 2800 | 1034 | 2.8952 | 0.140142
32_Deur_Hi-17 | Begane grond | 100 | 2800 | 1831 | 5.1268 | 0.140343
32_Deur_Hi-18 | Begane grond | 100 | 2800 | 2424.27 | 6.78796 | 0.172788
_Deur_Hi-01s | Begane grond | 100 | 2367 | 1034 | 2.44748 | 0.125832
32_Deur_Hi-44 | Begane grond | 100 | 2800 | 3350 | 9.38 | 0.163629
2 x 32_Deur_Si-03 | Begane grond | 100 | 2800 | 2700 | 7.56 | 0.14542
53 x Slab Opening | Begane grond
3 x _Deur_Hi-08 | Begane grond | 100 | 2367 | 1831 | 4.33398 | 0.205244
31_Raam_Hi-39 | Begane grond | 100 | 1600 | 1150 | 1.84 | 0.0486488
31_Raam_Merk-x | Begane grond | 100 | 1129.9 | 1484.8 | 0.838836 | 0
32_Deur_Hi-19 | Begane grond | 100 | 2800 | 2995.12 | 8.38634 | 0.186389
32_Deur_Si-01 | Begane grond | 100 | 2800 | 3000 | 8.4 | 0.150028
32_Deur_Hi-05 | Begane grond | 100 | 2367 | 1034 | 2.44748 | 0.0770825
32_Deur_Hi-25 | Begane grond | 100 | 2800 | 4300 | 12.04 | 0.237508
32_Deur_Hi-01 | Begane grond | 60 | 2367 | 969.979 | 2.29594 | 0.0650825
31_Raam_He-11 | 1e verdieping | 488 | 2800 | 2190 | 6.132 | 0.146623
36 x 31_Raam_- | 1e verdieping | 538 | 0 | 0 | 0 | 0
8 x 31_Raam_He-13 | 1e verdieping | 538 | 3235 | 2190 | 7.08465 | 0.179981
9 x 31_Raam_He-13s | 1e verdieping | 538 | 3235 | 2190 | 7.08465 | 0.179981
11 x 31_Raam_He-14 | 1e verdieping | 538 | 3235 | 2190 | 7.08465 | 0.193899
31_Raam_- | 1e verdieping | 538 | 3235 | 2954.8 | 9.55878 | 0.0217817
31_Raam_He-13s | 1e verdieping | 538 | 3235 | 2190 | 7.08465 | 0.17866
31_Raam_He-13 | 1e verdieping | 538 | 3235 | 2190 | 7.08465 | 0.17866
32_Deur_Hi-42s | 1e verdieping | 100 | 2800 | 1586 | 4.4408 | 0.1096
32_Deur_Hi-42 | 1e verdieping | 100 | 2800 | 1586 | 4.4408 | 0.1096
6 x 31_Raam_Hi-53 | 1e verdieping | 100 | 1600 | 2350 | 3.76 | 0.0891331
6 x 32_Deur_Si-02s | 1e verdieping | 100 | 2800 | 3000 | 8.4 | 0.150028
32_Deur_Hi-44 | 1e verdieping | 100 | 2800 | 3350 | 9.38 | 0.163629
4 x 32_Deur_Si-02 | 1e verdieping | 100 | 2800 | 3000 | 8.4 | 0.150028
19 x Slab Opening | 1e verdieping
31_Raam_Hi-34 | 1e verdieping | 100 | 2200 | 2200 | 4.84 | 0.141509
2 x 31_Raam_Hi-45 | 1e verdieping | 100 | 1100 | 1100 | 1.21 | 0.0315602
31_Raam_Hi-46 | 1e verdieping | 100 | 1800 | 1800 | 3.24 | 0.103491
2 x 32_Deur_Hi-01a | 1e verdieping | 100 | 2367 | 1034 | 2.44748 | 0.0938825
4 x 32_Deur_Hi-01s | 1e verdieping | 100 | 2367 | 1034 | 2.44748 | 0.125832
4 x 32_Deur_Hi-01 | 1e verdieping | 100 | 2367 | 1034 | 2.44748 | 0.125832
_Deur_Hi-15 | 1e verdieping | 100 | 2800 | 2800 | 7.84 | 0.169897
32_Deur_Hi-52 | 1e verdieping | 100 | 2800 | 2100 | 5.88 | 0.133846
32_Deur_Hi-07 | 1e verdieping | 100 | 2800 | 1034 | 2.8952 | 0.140142
32_Deur_Hi-50 | 1e verdieping | 100 | 2800 | 1600 | 4.48 | 0.121933
32_Deur_Hi-50s | 1e verdieping | 100 | 2800 | 1600 | 4.48 | 0.121933
32_Deur_Hi-51 | 1e verdieping | 100 | 2800 | 3150 | 8.82 | 0.209172
32_Deur_Hi-11 | 1e verdieping | 100 | 2800 | 2000 | 5.6 | 0.131464
2 x 32_Deur_Hi-03 | 1e verdieping | 100 | 2367 | 1034 | 2.44748 | 0.125832
31_Raam_Merk-x | 1e verdieping | 100 | 1000 | 1142.62 | 0.571312 | 0
31_Raam_Merk-x | 1e verdieping | 100 | 994.873 | 1136.77 | 0.565469 | 0
31_Raam_Hi-30 | 1e verdieping | 100 | 1825.6 | 920.712 | 1.68085 | 0.028004
32_Deur_lift | 1e verdieping | 100 | 2367 | 1034 | 2.44748 | 0.125832
32_Deur_Hi-26 | 1e verdieping | 100 | 2800 | 4500 | 12.6 | 0.246318
32_Deur_- | 1e verdieping | 100 | 2600 | 1410.58 | 3.66751 | 0
32_Deur_- | 1e verdieping | 100 | 2367 | 2170.73 | 5.13812 | 0
31_Raam_- | 1e verdieping | 488 | 1630 | 2411.85 | 1.96566 | 0
32_Deur_Hi-27 | 1e verdieping | 100 | 2800 | 4650 | 13.02 | 0.249892
32_Deur_Hi-52s | 1e verdieping | 100 | 2800 | 2100 | 5.88 | 0.133846
_Deur_Hi-07s | 1e verdieping | 100 | 2800 | 1034 | 2.8952 | 0.140142
32_Deur_Hi-54 | 1e verdieping | 100 | 2800 | 3150 | 8.82 | 0.209172
2 x 31_Raam_Merk-x | 1e verdieping | 10 | 2000 | 400 | 0.4 | 0
31_Raam_Hi-31 | 1e verdieping | 100 | 1100 | 1100 | 1.21 | 0.0221475
31_Raam_Hi-32 | 1e verdieping | 100 | 1800 | 1800 | 3.24 | 0.0371555
32_Deur_Hi-22 | 1e verdieping | 100 | 2800 | 3300 | 9.24 | 0.217727
32_Deur_Hi-12 | 1e verdieping | 100 | 2800 | 2300 | 6.44 | 0.138611
31_Raam_Hi-46a | 1e verdieping | 100 | 1800 | 1800 | 3.24 | 0.0371555
5 x Slab Opening | 2e verdieping
31_Raam_- | 2e verdieping | 150 | 449.988 | 6046.08 | 1.8509 | 0
31_Raam_- | 2e verdieping | 150 | 460.398 | 1240.22 | 0.291715 | 0
31_Raam_- | 2e verdieping | 150 | 132.808 | 368.642 | 0.0244794 | 0

# IfcPlate: 1250 x 5 x 20 (5)
In: 1e verdieping
Type - PredefinedType: CURTAIN_PANEL
Classification: Vliesgevel - paneel (ARCHICAD Classification)
Name | Width (mm) | Perimeter (mm) | GrossArea (m2) | NetArea (m2) | GrossVolume (m3) | NetVolume (m3)
_Vliesgevel - paneel_Paneel-x | 2450 | 10249.9 | 6.8649 | 6.55365 | 0.137298 | 0.131073
_Vliesgevel - paneel_Paneel-x | 1175.01 | 5350.01 | 1.92676 | 1.76251 | 0.0385352 | 0.0352502
2 x _Vliesgevel - paneel_Paneel-x | 1200 | 5408.97 | 1.9714 | 1.80538 | 0.039428 | 0.0361076
_Vliesgevel - paneel_Paneel-x | 1175.01 | 5408.98 | 1.96317 | 1.79716 | 0.0392635 | 0.0359431

# IfcPlate: 350 x 5 x 20, _Vliesgevel - paneel_Paneel-x
In: 1e verdieping
Type - PredefinedType: CURTAIN_PANEL
Classification: Vliesgevel - paneel (ARCHICAD Classification)
BaseQuantities - Width: 2450 mm; Perimeter: 10350.1 mm; GrossArea: 6.99061 m2; NetArea: 6.67636 m2; GrossVolume: 0.139812 m3; NetVolume: 0.133527 m3

# IfcPlate: Distinct Panel 233 x 100 x 20, _Vliesgevel - paneel_Paneel-x
In: 2e verdieping
Type - PredefinedType: CURTAIN_PANEL
Classification: Vliesgevel - paneel (ARCHICAD Classification); Material: Metaal - Aluminium
BaseQuantities - Width: 165.045 mm; Perimeter: 401.345 mm; GrossArea: 0.0220944 m2; NetArea: 0.00639963 m2; GrossVolume: 0.000441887 m3; NetVolume: 0.000127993 m3
Component Quantities - Component 1, Mass: 1.23728 kg; Component 1, Skin/Component Volume: 0.000441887 m3

# IfcPlate: Distinct Panel 451 x 100 x 20, _Vliesgevel - paneel_Paneel-x
In: 2e verdieping
Type - PredefinedType: CURTAIN_PANEL
Classification: Vliesgevel - paneel (ARCHICAD Classification); Material: Metaal - Aluminium
BaseQuantities - Width: 406.899 mm; Perimeter: 885.357 mm; GrossArea: 0.0462864 m2; NetArea: 0.0160755 m2; GrossVolume: 0.000925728 m3; NetVolume: 0.00032151 m3
Component Quantities - Component 1, Mass: 2.59204 kg; Component 1, Skin/Component Volume: 0.000925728 m3

# IfcPlate: Distinct Panel 954 x 100 x 20, _Vliesgevel - paneel_Paneel-x
In: 2e verdieping
Type - PredefinedType: CURTAIN_PANEL
Classification: Vliesgevel - paneel (ARCHICAD Classification); Material: Metaal - Aluminium
BaseQuantities - Width: 885.267 mm; Perimeter: 1841.79 mm; GrossArea: 0.094098 m2; NetArea: 0.0351899 m2; GrossVolume: 0.00188196 m3; NetVolume: 0.000703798 m3
Component Quantities - Component 1, Mass: 5.26949 kg; Component 1, Skin/Component Volume: 0.00188196 m3

# IfcPlate: Distinct Panel 980 x 100 x 20 (10)
In: 2e verdieping
Type - PredefinedType: CURTAIN_PANEL
Classification: Vliesgevel - paneel (ARCHICAD Classification); Material: Metaal - Aluminium
BaseQuantities - Width: 920 mm; Perimeter: 1919.95 mm; NetArea: 0.0367762 m2; GrossVolume: 0.00195949 m3; NetVolume: 0.000735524 m3
Name | GrossArea (m2)
_Vliesgevel - paneel_Paneel-x | 0.0979747 | Component Quantities - Component 1, Mass: 5.48658 kg; Component 1, Skin/Component Volume: 0.00195949 m3
9 x _Vliesgevel - paneel_Paneel-x | 0.0979746

# IfcPlate: Main Panel 117 x 972 x 20, _Vliesgevel - paneel_Paneel-x
In: 2e verdieping
Type - PredefinedType: CURTAIN_PANEL
Classification: Vliesgevel - paneel (ARCHICAD Classification); Material: Glas
BaseQuantities - Width: 280.691 mm; Perimeter: 2194.48 mm; GrossArea: 0.226617 m2; NetArea: 0.157132 m2; GrossVolume: 0.00453233 m3; NetVolume: 0.00314264 m3
Component Quantities - Component 1, Mass: 9.88049 kg; Component 1, Skin/Component Volume: 0.00453233 m3

# IfcPlate: Main Panel 1250 x 5 x 20 (5)
In: 1e verdieping
Type - PredefinedType: CURTAIN_PANEL
Classification: Vliesgevel - paneel (ARCHICAD Classification); Material: Glas
Name | Width (mm) | Perimeter (mm) | GrossArea (m2) | NetArea (m2) | GrossVolume (m3) | NetVolume (m3) | Component 1, Mass (kg) | Component 1, Skin/Component Volume (m3)
_Vliesgevel - paneel_Paneel-x | 1175.01 | 4630.1 | 1.48221 | 1.33956 | 0.0296442 | 0.0267911 | 64.6243 | 0.0296442
_Vliesgevel - paneel_Paneel-x | 1175.01 | 4731.13 | 1.5446 | 1.39892 | 0.030892 | 0.0279783 | 67.3446 | 0.030892
_Vliesgevel - paneel_Paneel-x | 1200 | 4680.08 | 1.51195 | 1.36805 | 0.030239 | 0.027361 | 65.9211 | 0.030239
_Vliesgevel - paneel_Paneel-x | 1200 | 4680.08 | 1.51195 | 1.36805 | 0.030239 | 0.027361
_Vliesgevel - paneel_Paneel-x | 1175.01 | 4599.93 | 1.46361 | 1.32183 | 0.0292721 | 0.0264367 | 63.8133 | 0.0292721

# IfcPlate: Main Panel 197 x 795 x 20, _Vliesgevel - paneel_Paneel-x
In: 2e verdieping
Type - PredefinedType: CURTAIN_PANEL
Classification: Vliesgevel - paneel (ARCHICAD Classification); Material: Glas
BaseQuantities - Width: 128.549 mm; Perimeter: 1182.3 mm; GrossArea: 0.0782572 m2; NetArea: 0.0333607 m2; GrossVolume: 0.00156514 m3; NetVolume: 0.000667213 m3
Component Quantities - Component 1, Mass: 3.41201 kg; Component 1, Skin/Component Volume: 0.00156514 m3

# IfcPlate: Main Panel 350 x 5 x 20 (2)
In: 1e verdieping
Type - PredefinedType: CURTAIN_PANEL
Classification: Vliesgevel - paneel (ARCHICAD Classification); Material: Glas
Name | Width (mm) | Perimeter (mm) | GrossArea (m2) | NetArea (m2) | GrossVolume (m3) = Component 1, Skin/Component Volume (m3) | NetVolume (m3) | Component 1, Mass (kg)
_Vliesgevel - paneel_Paneel-x | 300.035 | 8330.07 | 1.41329 | 1.15964 | 0.0282657 | 0.0231927 | 61.6193
_Vliesgevel - paneel_Paneel-x | 299.96 | 8329.92 | 1.41299 | 1.15934 | 0.0282598 | 0.0231869 | 61.6064

# IfcPlate: Main Panel 38 x 160 x 20, _Vliesgevel - paneel_Paneel-x
In: 2e verdieping
Type - PredefinedType: CURTAIN_PANEL
Classification: Vliesgevel - paneel (ARCHICAD Classification); Material: Glas
BaseQuantities - Width: 0 mm; Perimeter: 0 mm; GrossArea: 0.00303852 m2; NetArea: 0 m2; GrossVolume: 0.0000607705 m3; NetVolume: 0 m3
Component Quantities - Component 1, Mass: 0.13248 kg; Component 1, Skin/Component Volume: 0.0000607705 m3

# IfcPlate: Main Panel 423 x 968 x 20, _Vliesgevel - paneel_Paneel-x
In: 2e verdieping
Type - PredefinedType: CURTAIN_PANEL
Classification: Vliesgevel - paneel (ARCHICAD Classification); Material: Glas
BaseQuantities - Width: 358.771 mm; Perimeter: 2465.57 mm; GrossArea: 0.356026 m2; NetArea: 0.278442 m2; GrossVolume: 0.00712052 m3; NetVolume: 0.00556885 m3
Component Quantities - Component 1, Mass: 15.5227 kg; Component 1, Skin/Component Volume: 0.00712052 m3

# IfcPlate: Main Panel 477 x 972 x 20 (2)
In: 2e verdieping
Type - PredefinedType: CURTAIN_PANEL
Classification: Vliesgevel - paneel (ARCHICAD Classification); Material: Glas
Name | Width (mm) | Perimeter (mm) | GrossArea (m2) | NetArea (m2) | GrossVolume (m3) = Component 1, Skin/Component Volume (m3) | NetVolume (m3) | Component 1, Mass (kg)
_Vliesgevel - paneel_Paneel-x | 640.443 | 2913.98 | 0.576397 | 0.485327 | 0.0115279 | 0.00970655 | 25.1309
_Vliesgevel - paneel_Paneel-x | 408.327 | 2442.84 | 0.346386 | 0.269446 | 0.00692772 | 0.00538893 | 15.1024

# IfcPlate: Main Panel 5 x 20 x 20 (21)
In: 1e verdieping
Type - PredefinedType: CURTAIN_PANEL
Classification: Vliesgevel - paneel (ARCHICAD Classification); Material: Glas
Name | Width (mm) | Perimeter (mm) | GrossArea (m2) | NetArea (m2) | GrossVolume (m3) | NetVolume (m3) | Component 1, Mass (kg) | Component 1, Skin/Component Volume (m3)
3 x _Vliesgevel - paneel_Paneel-x | 1200 | 6678.88 | 2.77169 | 2.56733 | 0.0554339 | 0.0513466 | 120.846 | 0.0554339
_Vliesgevel - paneel_Paneel-x | 300 | 7320 | 1.20149 | 0.978736 | 0.0240297 | 0.0195747 | 52.3848 | 0.0240297
_Vliesgevel - paneel_Paneel-x | 299.96 | 7409.92 | 1.24741 | 1.02136 | 0.0249482 | 0.0204273 | 54.3871 | 0.0249482
_Vliesgevel - paneel_Paneel-x | 1200 | 9210 | 4.36605 | 4.086 | 0.087321 | 0.08172 | 190.36 | 0.087321
_Vliesgevel - paneel_Paneel-x | 1200 | 9210 | 4.36605 | 4.086 | 0.087321 | 0.08172
_Vliesgevel - paneel_Paneel-x | 850.04 | 5978.96 | 2.00818 | 1.81861 | 0.0401636 | 0.0363722 | 87.5568 | 0.0401636
2 x _Vliesgevel - paneel_Paneel-x | 1200 | 6678.88 | 2.77169 | 2.56733 | 0.0554339 | 0.0513466
2 x _Vliesgevel - paneel_Paneel-x | 850 | 5978.88 | 2.00189 | 1.81852 | 0.0400378 | 0.0363705 | 87.2824 | 0.0400378
_Vliesgevel - paneel_Paneel-x | 300 | 4878.88 | 0.792199 | 0.641832 | 0.015844 | 0.0128366 | 34.5399 | 0.015844
_Vliesgevel - paneel_Paneel-x | 300.035 | 7410.07 | 1.24767 | 1.02162 | 0.0249534 | 0.0204324 | 54.3985 | 0.0249534
_Vliesgevel - paneel_Paneel-x | 300 | 4878.88 | 0.792199 | 0.641832 | 0.015844 | 0.0128366
_Vliesgevel - paneel_Paneel-x | 849.965 | 8509.93 | 3.15318 | 2.89413 | 0.0630636 | 0.0578826 | 137.479 | 0.0630636
_Vliesgevel - paneel_Paneel-x | 274.984 | 7269.97 | 1.14584 | 0.923946 | 0.0229169 | 0.0184789 | 49.9588 | 0.0229169
_Vliesgevel - paneel_Paneel-x | 1200 | 3569.91 | 0.812794 | 0.701947 | 0.0162559 | 0.0140389 | 35.4378 | 0.0162559
2 x _Vliesgevel - paneel_Paneel-x | 1200 | 3569.91 | 0.812795 | 0.701947 | 0.0162559 | 0.0140389 | 35.4378 | 0.0162559
_Vliesgevel - paneel_Paneel-x | 1200 | 3569.91 | 0.812795 | 0.701947 | 0.0162559 | 0.0140389

# IfcPlate: Main Panel 5 x 660 x 20, _Vliesgevel - paneel_Paneel-x
In: 1e verdieping
Type - PredefinedType: CURTAIN_PANEL
Classification: Vliesgevel - paneel (ARCHICAD Classification); Material: Glas
BaseQuantities - Width: 1175.01 mm; Perimeter: 3519.93 mm; GrossArea: 0.7967 m2; NetArea: 0.687327 m2; GrossVolume: 0.015934 m3; NetVolume: 0.0137465 m3
Component Quantities - Component 1, Mass: 34.7361 kg; Component 1, Skin/Component Volume: 0.015934 m3

# IfcPlate: Main Panel 634 x 244 x 20, _Vliesgevel - paneel_Paneel-x
In: 2e verdieping
Type - PredefinedType: CURTAIN_PANEL
Classification: Vliesgevel - paneel (ARCHICAD Classification); Material: Glas
BaseQuantities - Width: 565.868 mm; Perimeter: 1396.62 mm; GrossArea: 0.123018 m2; NetArea: 0.0774218 m2; GrossVolume: 0.00246035 m3; NetVolume: 0.00154844 m3
Component Quantities - Component 1, Mass: 5.36356 kg; Component 1, Skin/Component Volume: 0.00246035 m3

# IfcPlate: Main Panel 654 x 100 x 20, _Vliesgevel - paneel_Paneel-x
In: 2e verdieping
Type - PredefinedType: CURTAIN_PANEL
Classification: Vliesgevel - paneel (ARCHICAD Classification); Material: Glas
BaseQuantities - Width: 585.758 mm; Perimeter: 1242.77 mm; GrossArea: 0.0641548 m2; NetArea: 0.0232173 m2; GrossVolume: 0.0012831 m3; NetVolume: 0.000464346 m3
Component Quantities - Component 1, Mass: 2.79715 kg; Component 1, Skin/Component Volume: 0.0012831 m3

# IfcPlate: Main Panel 781 x 100 x 20, _Vliesgevel - paneel_Paneel-x
In: 2e verdieping
Type - PredefinedType: CURTAIN_PANEL
Classification: Vliesgevel - paneel (ARCHICAD Classification); Material: Glas
BaseQuantities - Width: 736.498 mm; Perimeter: 1544.56 mm; GrossArea: 0.0792378 m2; NetArea: 0.0292509 m2; GrossVolume: 0.00158476 m3; NetVolume: 0.000585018 m3
Component Quantities - Component 1, Mass: 3.45477 kg; Component 1, Skin/Component Volume: 0.00158476 m3

# IfcPlate: Main Panel 807 x 972 x 20, _Vliesgevel - paneel_Paneel-x
In: 2e verdieping
Type - PredefinedType: CURTAIN_PANEL
Classification: Vliesgevel - paneel (ARCHICAD Classification); Material: Glas
BaseQuantities - Width: 920 mm; Perimeter: 3517.27 mm; GrossArea: 0.889783 m2; NetArea: 0.780748 m2; GrossVolume: 0.0177957 m3; NetVolume: 0.015615 m3
Component Quantities - Component 1, Mass: 38.7945 kg; Component 1, Skin/Component Volume: 0.0177957 m3

# IfcPlate: Main Panel 897 x 972 x 20, _Vliesgevel - paneel_Paneel-x
In: 2e verdieping
Type - PredefinedType: CURTAIN_PANEL
Classification: Vliesgevel - paneel (ARCHICAD Classification); Material: Glas
BaseQuantities - Width: 829.041 mm; Perimeter: 3284.26 mm; GrossArea: 0.755438 m2; NetArea: 0.653256 m2; GrossVolume: 0.0151088 m3; NetVolume: 0.0130651 m3
Component Quantities - Component 1, Mass: 32.9371 kg; Component 1, Skin/Component Volume: 0.0151088 m3

# IfcPlate: Main Panel 900 x 5 x 20, _Vliesgevel - paneel_Paneel-x
In: 1e verdieping
Type - PredefinedType: CURTAIN_PANEL
Classification: Vliesgevel - paneel (ARCHICAD Classification); Material: Glas
BaseQuantities - Width: 849.965 mm; Perimeter: 9429.93 mm; GrossArea: 3.57176 m2; NetArea: 3.28511 m2; GrossVolume: 0.0714353 m3; NetVolume: 0.0657023 m3
Component Quantities - Component 1, Mass: 155.729 kg; Component 1, Skin/Component Volume: 0.0714353 m3

# IfcPlate: Main Panel 91 x 100 x 20, _Vliesgevel - paneel_Paneel-x
In: 2e verdieping
Type - PredefinedType: CURTAIN_PANEL
Classification: Vliesgevel - paneel (ARCHICAD Classification); Material: Glas
BaseQuantities - Width: 47.1474 mm; Perimeter: 165.853 mm; GrossArea: 0.0103205 m2; NetArea: 0.00169472 m2; GrossVolume: 0.00020641 m3; NetVolume: 0.0000338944 m3
Component Quantities - Component 1, Mass: 0.449973 kg; Component 1, Skin/Component Volume: 0.00020641 m3

# IfcPlate: Main Panel 980 x 100 x 20 (10)
In: 2e verdieping
Type - PredefinedType: CURTAIN_PANEL
Classification: Vliesgevel - paneel (ARCHICAD Classification); Material: Glas
BaseQuantities - Width: 920 mm; Perimeter: 1919.95 mm; GrossArea: 0.0979746 m2; NetArea: 0.0367762 m2; GrossVolume: 0.00195949 m3; NetVolume: 0.000735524 m3
Name
_Vliesgevel - paneel_Paneel-x | Component Quantities - Component 1, Mass: 4.27169 kg; Component 1, Skin/Component Volume: 0.00195949 m3
9 x _Vliesgevel - paneel_Paneel-x

# IfcPlate: Main Panel 980 x 247 x 20, _Vliesgevel - paneel_Paneel-x
In: 2e verdieping
Type - PredefinedType: CURTAIN_PANEL
Classification: Vliesgevel - paneel (ARCHICAD Classification); Material: Glas
BaseQuantities - Width: 920 mm; Perimeter: 2364.82 mm; GrossArea: 0.31161 m2; NetArea: 0.237046 m2; GrossVolume: 0.00623219 m3; NetVolume: 0.00474093 m3
Component Quantities - Component 1, Mass: 13.5862 kg; Component 1, Skin/Component Volume: 0.00623219 m3

# IfcPlate: Main Panel 980 x 391 x 20, _Vliesgevel - paneel_Paneel-x
In: 2e verdieping
Type - PredefinedType: CURTAIN_PANEL
Classification: Vliesgevel - paneel (ARCHICAD Classification); Material: Glas
BaseQuantities - Width: 920 mm; Perimeter: 2653.09 mm; GrossArea: 0.452858 m2; NetArea: 0.369647 m2; GrossVolume: 0.00905715 m3; NetVolume: 0.00739293 m3
Component Quantities - Component 1, Mass: 19.7446 kg; Component 1, Skin/Component Volume: 0.00905715 m3

# IfcPlate: Main Panel 980 x 536 x 20, _Vliesgevel - paneel_Paneel-x
In: 2e verdieping
Type - PredefinedType: CURTAIN_PANEL
Classification: Vliesgevel - paneel (ARCHICAD Classification); Material: Glas
BaseQuantities - Width: 920 mm; Perimeter: 2941.35 mm; GrossArea: 0.594106 m2; NetArea: 0.502247 m2; GrossVolume: 0.0118821 m3; NetVolume: 0.0100449 m3
Component Quantities - Component 1, Mass: 25.903 kg; Component 1, Skin/Component Volume: 0.0118821 m3

# IfcPlate: Main Panel 980 x 680 x 20, _Vliesgevel - paneel_Paneel-x
In: 2e verdieping
Type - PredefinedType: CURTAIN_PANEL
Classification: Vliesgevel - paneel (ARCHICAD Classification); Material: Glas
BaseQuantities - Width: 920 mm; Perimeter: 3229.61 mm; GrossArea: 0.735354 m2; NetArea: 0.634847 m2; GrossVolume: 0.0147071 m3; NetVolume: 0.0126969 m3
Component Quantities - Component 1, Mass: 32.0614 kg; Component 1, Skin/Component Volume: 0.0147071 m3

# IfcPlate: Main Panel 980 x 824 x 20, _Vliesgevel - paneel_Paneel-x
In: 2e verdieping
Type - PredefinedType: CURTAIN_PANEL
Classification: Vliesgevel - paneel (ARCHICAD Classification); Material: Glas
BaseQuantities - Width: 920 mm; Perimeter: 3517.87 mm; GrossArea: 0.876602 m2; NetArea: 0.767447 m2; GrossVolume: 0.017532 m3; NetVolume: 0.0153489 m3
Component Quantities - Component 1, Mass: 38.2198 kg; Component 1, Skin/Component Volume: 0.017532 m3

# IfcPlate: Main Panel 980 x 972 x 20 (21)
In: 2e verdieping
Type - PredefinedType: CURTAIN_PANEL
Classification: Vliesgevel - paneel (ARCHICAD Classification); Material: Glas
BaseQuantities - Width: 920 mm; Perimeter: 3664.56 mm; GrossArea: 0.952836 m2; NetArea: 0.839299 m2; GrossVolume: 0.0190567 m3; NetVolume: 0.016786 m3
Name
2 x _Vliesgevel - paneel_Paneel-x | Component Quantities - Component 1, Mass: 41.5437 kg; Component 1, Skin/Component Volume: 0.0190567 m3
19 x _Vliesgevel - paneel_Paneel-x

# IfcRailing: Railing Type (6)
Classification: 34.21 BINNENLEUNINGEN (NL/SfB (4 cijfers)); Reling (ARCHICAD Classification)
Pset_RailingCommon - IsExternal: no
Name | In | GrossVolume (m3) = NetVolume (m3) | Length (mm)
34_Reling_Reling-x | Begane grond | 0.00481958 | 4619.58
2 x 34_Reling_Reling-x | Begane grond | 0.00675276 | 6814.49
2 x 34_Reling_Reling-x | Begane grond | 0.00740083 | 7506.87
34_Reling_Reling-x | 1e verdieping | 0.00598878 | 1596.21

# IfcSlab: ALG - CONSTRUCTIEF 180 (13)
Classification: Vloer (ARCHICAD Classification); 23.21 VRIJDRAGENDE VLOEREN (NL/SfB (4 cijfers)); Material: ALG - CONSTRUCTIEF
Pset_SlabCommon - LoadBearing: yes; IsExternal: no
BaseQuantities - Width: 180 mm
Component Quantities - Component 1, Skin Thickness: 180 mm
Name | In | Perimeter (mm) | GrossArea (m2) | NetArea (m2) = Component 1, Projected Component/Skin Area (m2) | GrossVolume (m3) | NetVolume (m3) = Component 1, Skin/Component Volume (m3) | Component 1, Mass (kg)
4 x 23_Vloer_Vloer-x | Begane grond | 4399.35 | 0.521089 | 0.521089 | 0.093796 | 0.093796 | 215.731
23_Vloer_Vloer-x | Begane grond | 29630.3 | 12.3815 | 12.3815 | 2.22867 | 2.22866 | 5125.92
23_Vloer_Vloer-x | 1e verdieping | 19673.9 | 9.12529 | 9.12529 | 1.64255 | 1.64255 | 3777.87
6 x 23_Vloer_Vloer-x | 1e verdieping | 4399.35 | 0.521089 | 0.521089 | 0.093796 | 0.093796 | 215.731
23_Vloer_Vloer-x | 1e verdieping | 4399.35 | 0.521089 | 0.521085 | 0.093796 | 0.0937954 | 215.729

# IfcSlab: ALG - CONSTRUCTIEF 250, 23_Vloer_Vloer-x
In: 1e verdieping
Classification: Vloer (ARCHICAD Classification); 23.21 VRIJDRAGENDE VLOEREN (NL/SfB (4 cijfers)); Material: ALG - CONSTRUCTIEF
Pset_SlabCommon - LoadBearing: yes; IsExternal: no
BaseQuantities - Width: 250 mm; Perimeter: 19589.3 mm; GrossArea: 13.7779 m2; NetArea: 13.7779 m2; GrossVolume: 3.44448 m3; NetVolume: 3.44448 m3
Component Quantities - Component 1, Mass: 7922.31 kg; Component 1, Projected Component/Skin Area: 13.7779 m2; Component 1, Skin Thickness: 250 mm; Component 1, Skin/Component Volume: 3.44448 m3

# IfcSlab: Beton gewapend i.h.w. beton 200, 23_Vloer_Vloer-x
In: Begane grond
Classification: Vloer (ARCHICAD Classification); 23.21 VRIJDRAGENDE VLOEREN (NL/SfB (4 cijfers)); Material: Beton gewapend i.h.w. beton
Pset_SlabCommon - LoadBearing: yes; IsExternal: no
BaseQuantities - Width: 200 mm; Perimeter: 19778 mm; GrossArea: 24.405 m2; NetArea: 24.405 m2; GrossVolume: 4.881 m3; NetVolume: 4.881 m3
Component Quantities - Component 1, Mass: 11226.3 kg; Component 1, Projected Component/Skin Area: 24.405 m2; Component 1, Skin Thickness: 200 mm; Component 1, Skin/Component Volume: 4.881 m3

# IfcSlab: Beton gewapend prefab 200 (2)
Classification: Vloer (ARCHICAD Classification); 23.21 VRIJDRAGENDE VLOEREN (NL/SfB (4 cijfers)); Material: Beton gewapend prefab
Pset_SlabCommon - LoadBearing: yes; IsExternal: no
BaseQuantities - Width: 200 mm
Component Quantities - Component 1, Skin Thickness: 200 mm
Name | In | Perimeter (mm) | GrossArea (m2) = NetArea (m2) = Component 1, Projected Component/Skin Area (m2) | GrossVolume (m3) = NetVolume (m3) = Component 1, Skin/Component Volume (m3) | Component 1, Mass (kg)
23_Vloer_Vloer-x | Begane grond | 8801.11 | 3.51936 | 0.703872 | 1689.29
23_Vloer_Vloer-x | 1e verdieping | 6278.86 | 2.46309 | 0.492619 | 1182.28

# IfcSlab: Hout - Hardhout 180 (8)
Classification: Vloer (ARCHICAD Classification); 23.21 VRIJDRAGENDE VLOEREN (NL/SfB (4 cijfers)); Material: Hout - Hardhout
Pset_SlabCommon - LoadBearing: yes; IsExternal: no
BaseQuantities - Width: 180 mm
Component Quantities - Component 1, Skin Thickness: 180 mm
Name | In | Perimeter (mm) | GrossArea (m2) = NetArea (m2) = Component 1, Projected Component/Skin Area (m2) | GrossVolume (m3) = NetVolume (m3) = Component 1, Skin/Component Volume (m3) | Component 1, Mass (kg)
23_Vloer_Vloer-x | Begane grond | 5967.31 | 1.232 | 0.221761 | 155.232
23_Vloer_Vloer-x | Begane grond | 5967.32 | 1.232 | 0.221761 | 155.233
23_Vloer_Vloer-x | Begane grond | 5967.33 | 1.23201 | 0.221761 | 155.233
23_Vloer_Vloer-x | Begane grond | 5967.33 | 1.23201 | 0.221762 | 155.233
23_Vloer_Vloer-x | 1e verdieping | 5967.34 | 1.23201 | 0.221762 | 155.233
23_Vloer_Vloer-x | 1e verdieping | 5967.35 | 1.23201 | 0.221762 | 155.234
23_Vloer_Vloer-x | 1e verdieping | 5967.35 | 1.23202 | 0.221763 | 155.234
23_Vloer_Vloer-x | 1e verdieping | 6760.6 | 2.35061 | 0.423111 | 296.177

# IfcSlab: _TenW_23_260mm Kanaalplaat+dv+iso RC 4,5 570, 23_Vloer_Vloer-x
In: Begane grond
Classification: Vloer (ARCHICAD Classification); 23.21 VRIJDRAGENDE VLOEREN (NL/SfB (4 cijfers))
Pset_SlabCommon - LoadBearing: yes; IsExternal: no
BaseQuantities - Width: 570 mm; Perimeter: 200015 mm; GrossArea: 1654.32 m2; NetArea: 1605.8 m2; GrossVolume: 967.224 m3; NetVolume: 939.566 m3

# IfcSlab: _TenW_23_300mm Breedplaatvloer 430, 23_Vloer_Vloer-x
In: 1e verdieping
Classification: Vloer (ARCHICAD Classification); 23.21 VRIJDRAGENDE VLOEREN (NL/SfB (4 cijfers))
Pset_SlabCommon - LoadBearing: yes; IsExternal: no
BaseQuantities - Width: 430 mm; Perimeter: 164100 mm; GrossArea: 1459.86 m2; NetArea: 1352.44 m2; GrossVolume: 627.74 m3; NetVolume: 581.55 m3

# IfcSlab: _TenW_27_Breedplaat+dv+iso RC 6,0 585 (2)
Classification: Vloer (ARCHICAD Classification); 23.21 VRIJDRAGENDE VLOEREN (NL/SfB (4 cijfers))
Pset_SlabCommon - LoadBearing: yes; IsExternal: no
BaseQuantities - Width: 585 mm
Name | In | Perimeter (mm) | GrossArea (m2) | NetArea (m2) | GrossVolume (m3) | NetVolume (m3)
23_Vloer_Vloer-x | 1e verdieping | 66228 | 265.229 | 251.296 | 160.545 | 152.394
23_Vloer_Vloer-x | 2e verdieping | 159197 | 1471.61 | 1408.6 | 875.087 | 838.228

# IfcSlab: _TenW_90-stoep 50, 23_Vloer_Vloer-x
In: 1e verdieping
Classification: Vloer (ARCHICAD Classification); 23.21 VRIJDRAGENDE VLOEREN (NL/SfB (4 cijfers)); Material: _TenW_90-stoep
Pset_SlabCommon - LoadBearing: yes; IsExternal: no
BaseQuantities - Width: 50 mm; Perimeter: 64799.9 mm; GrossArea: 252.242 m2; NetArea: 244.832 m2; GrossVolume: 12.6136 m3; NetVolume: 12.2431 m3
Component Quantities - Component 1, Mass: 26934.9 kg; Component 1, Projected Component/Skin Area: 244.892 m2; Component 1, Skin Thickness: 50 mm; Component 1, Skin/Component Volume: 12.2431 m3

# IfcStair (8)
Pset_StairCommon - IsExternal: no
Name | In | Classification | Length (mm) | Height (mm) | GrossVolume (m3) = NetVolume (m3)
_Trap_Trap-x | Begane grond | Trap (ARCHICAD Classification) | 4000 | 2880 | 6.0312
24_Trap_Trap-x | Begane grond | Trap (ARCHICAD Classification); 24.10 ALGEMEEN (NL/SfB (4 cijfers)) | 3360 | 2520 | 1.32659
_Trap_Trap-x | Begane grond | Trap (ARCHICAD Classification) | 4320 | 2880 | 8.17309
_Trap_Trap-x | Begane grond | Trap (ARCHICAD Classification) | 5940 | 3960 | 3.88624
_Trap_Trap-x | 1e verdieping | Trap (ARCHICAD Classification) | 1440 | 1080 | 0.604108
_Trap_Trap-x | 1e verdieping | Trap (ARCHICAD Classification) | 1440 | 1080 | 0.625714
24_Trap_Trap-x | 1e verdieping | Trap (ARCHICAD Classification); 24.10 ALGEMEEN (NL/SfB (4 cijfers)) | 1920 | 1440 | 0.746315
_Trap_Trap-x | 1e verdieping | Trap (ARCHICAD Classification) | 1620 | 1080 | 3.74386

# IfcStairFlight: IfcStairFlight (8)
Name | In | Classification | Material | Component 1, Mass (kg) | Component 1, Skin/Component Volume (m3)
_Trapsegment_Trapsegment-x | Begane grond | Trapsegment (ARCHICAD Classification) | Beton C | 11452.4 | 4.77185
24_Trapsegment_Trapsegment-x | Begane grond | Trapsegment (ARCHICAD Classification); 24.10 ALGEMEEN (NL/SfB (4 cijfers)) | Beton C | 3018.68 | 1.25778
_Trapsegment_Trapsegment-x | Begane grond | Trapsegment (ARCHICAD Classification) | Metaal - Staal C | 1207.44 | 0.15188
_Trapsegment_Trapsegment-x | Begane grond | Trapsegment (ARCHICAD Classification) | Metaal - Staal C | 705.117 | 0.0886939
_Trapsegment_Trapsegment-x | 1e verdieping | Trapsegment (ARCHICAD Classification) | Beton C | 1326.09 | 0.552538
_Trapsegment_Trapsegment-x | 1e verdieping | Trapsegment (ARCHICAD Classification) | Beton C | 1373.52 | 0.572301
24_Trapsegment_Trapsegment-x | 1e verdieping | Trapsegment (ARCHICAD Classification); 24.10 ALGEMEEN (NL/SfB (4 cijfers)) | Beton C | 1698.6 | 0.707748
_Trapsegment_Trapsegment-x | 1e verdieping | Trapsegment (ARCHICAD Classification) | Metaal - Staal C | 462.207 | 0.0581392

# IfcWall: ALG - BINNENAFWERKING 80 (8)
In: Begane grond
Classification: 22.13 SYSTEEMWANDEN VAST (NL/SfB (4 cijfers)); Wand (ARCHICAD Classification); Material: ALG - BINNENAFWERKING
Pset_WallCommon - LoadBearing: no; IsExternal: no
BaseQuantities - Length: 979.959 mm; Height: 3600 mm; Width: 80 mm; GrossFootprintArea: 0.0783968 m2; NetFootprintArea: 0.0783968 m2; GrossSideArea: 3.51609 m2; NetSideArea: 3.51609 m2; GrossVolume: 0.281288 m3; NetVolume: 0.281288 m3
Component Quantities - Component 1, Mass: 225.03 kg; Component 1, Projected Component/Skin Area: 3.51609 m2; Component 1, Skin Thickness: 80 mm; Component 1, Rectangular Component Height: 3630 mm; Component 1, Rectangular Component Width: 80 mm; Component 1, Component Cross Section Area: 0.2904 m2; Component 1, Skin/Component Volume: 0.281288 m3

# IfcWall: ALG - CONSTRUCTIEF 250, 22_Wand_Wand-x
In: Begane grond
Classification: 22.13 SYSTEEMWANDEN VAST (NL/SfB (4 cijfers)); Wand (ARCHICAD Classification); Material: ALG - CONSTRUCTIEF
Pset_WallCommon - LoadBearing: no; IsExternal: no
BaseQuantities - Length: 8245 mm; Height: 3630 mm; Width: 250 mm; GrossFootprintArea: 2.06125 m2; NetFootprintArea: 2.06125 m2; GrossSideArea: 29.9293 m2; NetSideArea: 29.9293 m2; GrossVolume: 7.48234 m3; NetVolume: 7.48234 m3
Component Quantities - Component 1, Mass: 17209.4 kg; Component 1, Projected Component/Skin Area: 29.9293 m2; Component 1, Skin Thickness: 250 mm; Component 1, Rectangular Component Height: 3630 mm; Component 1, Rectangular Component Width: 250 mm; Component 1, Component Cross Section Area: 0.9075 m2; Component 1, Skin/Component Volume: 7.48234 m3

# IfcWall: Beton gewapend prefab vloer 200, 21_Wand_Wand-x
In: Begane grond
Classification: Wand (ARCHICAD Classification); 21.22 SPOUWWANDEN (NL/SfB (4 cijfers)); Material: Beton gewapend prefab vloer
Pset_WallCommon - LoadBearing: yes; IsExternal: yes
BaseQuantities - Length: 9006.33 mm; Height: 1127.77 mm; Width: 200 mm; GrossFootprintArea: 3.39913 m2; NetFootprintArea: 3.39913 m2; GrossSideArea: 16.8958 m2; NetSideArea: 16.8958 m2; GrossVolume: 3.37915 m3; NetVolume: 3.37915 m3
Component Quantities - Component 1, Mass: 8109.97 kg; Component 1, Projected Component/Skin Area: 18.8999 m2; Component 1, Skin Thickness: 200 mm; Component 1, Component Cross Section Area: 0.431192 m2; Component 1, Skin/Component Volume: 3.37915 m3

# IfcWall: Beton gewapend prefab vloer 25 (8)
Classification: Wand (ARCHICAD Classification); 21.22 SPOUWWANDEN (NL/SfB (4 cijfers)); Material: Beton gewapend prefab vloer
Pset_WallCommon - LoadBearing: yes; IsExternal: yes
BaseQuantities - Length: 2423.67 mm; Height: 180 mm; Width: 25 mm; GrossFootprintArea: 0.0605916 m2; NetFootprintArea: 0.0605916 m2; GrossSideArea: 0.43626 m2; NetSideArea: 0.43626 m2; GrossVolume: 0.0109065 m3; NetVolume: 0.0109065 m3
Component Quantities - Component 1, Mass: 26.1756 kg; Component 1, Projected Component/Skin Area: 0.43626 m2; Component 1, Skin Thickness: 25 mm; Component 1, Rectangular Component Height: 180 mm; Component 1, Rectangular Component Width: 25 mm; Component 1, Component Cross Section Area: 0.0045 m2; Component 1, Skin/Component Volume: 0.0109065 m3
Name | In
5 x 21_Wand_Wand-x | Begane grond
3 x 21_Wand_Wand-x | 1e verdieping

# IfcWall: Betonwand 250 250 (8)
Classification: 22.13 SYSTEEMWANDEN VAST (NL/SfB (4 cijfers)); Wand (ARCHICAD Classification); Material: Beton gewapend C
Pset_WallCommon - LoadBearing: no; IsExternal: no
BaseQuantities - Width: 250 mm
Component Quantities - Component 1, Skin Thickness: 250 mm; Component 1, Rectangular Component Width: 250 mm
Name | In | Length (mm) | Height (mm) | GrossFootprintArea (m2) = NetFootprintArea (m2) | GrossSideArea (m2) = NetSideArea (m2) = Component 1, Projected Component/Skin Area (m2) | GrossVolume (m3) = NetVolume (m3) = Component 1, Skin/Component Volume (m3) | Component 1, Mass (kg) | Component 1, Rectangular Component Height (mm) | Component 1, Component Cross Section Area (m2)
2 x 22_Wand_Wand-x | Begane grond | 7850 | 3630 | 1.9625 | 28.4955 | 7.12387 | 16384.9 | 3630 | 0.9075
22_Wand_Wand-x | Begane grond | 8245 | 3630 | 2.06125 | 29.9293 | 7.48234 | 17209.4 | 3630 | 0.9075
22_Wand_Wand-x | Begane grond | 7651 | 3630 | 1.91275 | 27.7731 | 6.94328 | 15969.5 | 3630 | 0.9075
22_Wand_Wand-x | 1e verdieping | 7995 | 3960 | 1.99875 | 31.6602 | 7.91505 | 18204.6 | 3960 | 0.99
22_Wand_Wand-x | 1e verdieping | 7195 | 3960 | 1.79875 | 28.4922 | 7.12305 | 16383 | 3960 | 0.99
22_Wand_Wand-x | 1e verdieping | 6150 | 3620 | 1.5625 | 22.625 | 5.65625 | 13009.4 | 3960 | 0.99
22_Wand_Wand-x | 1e verdieping | 6250 | 3720 | 1.5625 | 23.25 | 5.8125 | 13368.8 | 3720 | 0.93

# IfcWall: Gipsplaat 12 (3)
In: Begane grond
Classification: Wand (ARCHICAD Classification); 21.22 SPOUWWANDEN (NL/SfB (4 cijfers)); Material: Gipsplaat
Pset_WallCommon - LoadBearing: yes; IsExternal: yes
BaseQuantities - Height: 3600 mm; Width: 12 mm
Component Quantities - Component 1, Skin Thickness: 12 mm; Component 1, Rectangular Component Height: 3670 mm; Component 1, Rectangular Component Width: 12 mm; Component 1, Component Cross Section Area: 0.04404 m2
Name | Length (mm) | GrossFootprintArea (m2) = NetFootprintArea (m2) | GrossSideArea (m2) = NetSideArea (m2) = Component 1, Projected Component/Skin Area (m2) | GrossVolume (m3) = NetVolume (m3) = Component 1, Skin/Component Volume (m3) | Component 1, Mass (kg)
21_Wand_Wand-x | 360 | 0.00432 | 1.296 | 0.015552 | 12.4416
2 x 21_Wand_Wand-x | 60 | 0.00072 | 0.216 | 0.002592 | 2.0736

# IfcWall: Hout - Spaanplaat 20 (61)
Classification: Wand (ARCHICAD Classification); 21.22 SPOUWWANDEN (NL/SfB (4 cijfers)); Material: Hout - Spaanplaat
Pset_WallCommon - LoadBearing: yes; IsExternal: yes
BaseQuantities - Width: 20 mm
Component Quantities - Component 1, Skin Thickness: 20 mm; Component 1, Rectangular Component Width: 20 mm
Name | In | Length (mm) | Height (mm) = Component 1, Rectangular Component Height (mm) | GrossFootprintArea (m2) = NetFootprintArea (m2) | GrossSideArea (m2) | NetSideArea (m2) | GrossVolume (m3) | NetVolume (m3) = Component 1, Skin/Component Volume (m3) | Component 1, Mass (kg) | Component 1, Projected Component/Skin Area (m2) | Component 1, Component Cross Section Area (m2)
21_Wand_Wand-x | Begane grond | 4460 | 250 | 0.0892 | 1.115 | 1.115 | 0.0223 | 0.0223 | 13.38 | 1.115 | 0.005
21_Wand_Wand-x | Begane grond | 4460 | 100 | 0.0892 | 0.446 | 0.446 | 0.00892 | 0.00892 | 5.352 | 0.446 | 0.002
21_Wand_Wand-x | Begane grond | 3799.05 | 250 | 0.0759809 | 0.949761 | 0.949761 | 0.0189952 | 0.0189952 | 11.3971 | 0.949761 | 0.005
21_Wand_Wand-x | Begane grond | 3799.05 | 100 | 0.0759809 | 0.379905 | 0.379905 | 0.00759809 | 0.00759809 | 4.55885 | 0.379905 | 0.002
21_Wand_Wand-x | Begane grond | 3336.46 | 250 | 0.0667291 | 0.834114 | 0.834114 | 0.0166823 | 0.0166823 | 10.0094 | 0.834114 | 0.005
21_Wand_Wand-x | Begane grond | 3336.46 | 100 | 0.0667291 | 0.333646 | 0.333646 | 0.00667291 | 0.00667291 | 4.00375 | 0.333646 | 0.002
21_Wand_Wand-x | Begane grond | 982.772 | 1200 | 0.0196554 | 1.17933 | 1.17933 | 0.0235865 | 0.0235865 | 14.1519 | 1.17933 | 0.024
21_Wand_Wand-x | Begane grond | 259.08 | 1200 | 0.0051816 | 0.325896 | 0.322896 | 0.00651792 | 0.00621792 | 3.73075 | 0.310896 | 0.024
21_Wand_Wand-x | Begane grond | 309.92 | 1200 | 0.0061984 | 0.371904 | 0.371904 | 0.00743808 | 0.00743808 | 4.46285 | 0.371904 | 0.024
21_Wand_Wand-x | Begane grond | 910.515 | 1200 | 0.0184691 | 1.10815 | 1.10815 | 0.0221629 | 0.0221629 | 13.2978 | 1.11136 | 0.024
21_Wand_Wand-x | Begane grond | 210 | 1200 | 0.0044 | 0.264 | 0.264 | 0.00528 | 0.00528 | 3.168 | 0.264 | 0.024
21_Wand_Wand-x | Begane grond | 1240.75 | 1200 | 0.0238493 | 1.4319 | 1.4244 | 0.0286379 | 0.0286192 | 17.1715 | 1.4319 | 0.024
21_Wand_Wand-x | Begane grond | 2172.58 | 1200 | 0.0428859 | 2.57409 | 2.56659 | 0.0514818 | 0.0514631 | 30.8778 | 2.57409 | 0.024
21_Wand_Wand-x | Begane grond | 260 | 1200 | 0.005 | 0.3 | 0.3 | 0.006 | 0.006 | 3.6 | 0.3 | 0.024
21_Wand_Wand-x | Begane grond | 675 | 1200 | 0.01375 | 0.825 | 0.825 | 0.0165 | 0.0165 | 9.9 | 0.825 | 0.024
21_Wand_Wand-x | Begane grond | 880 | 1200 | 0.0176 | 1.056 | 1.056 | 0.02112 | 0.02112 | 12.672 | 1.056 | 0.024
21_Wand_Wand-x | Begane grond | 3720.05 | 1200 | 0.0744011 | 4.46406 | 4.46406 | 0.0892813 | 0.0892813 | 53.5688 | 4.46406 | 0.024
21_Wand_Wand-x | Begane grond | 430 | 1200 | 0.0086 | 0.516 | 0.516 | 0.01032 | 0.01032 | 6.192 | 0.516 | 0.024
21_Wand_Wand-x | Begane grond | 2059.23 | 1200 | 0.0414435 | 2.50161 | 2.49861 | 0.0500322 | 0.0497322 | 29.8393 | 2.48983 | 0.024
21_Wand_Wand-x | Begane grond | 138.89 | 1200 | 0.00303662 | 0.182197 | 0.182197 | 0.00364395 | 0.00364395 | 2.18637 | 0.185413 | 0.024
21_Wand_Wand-x | Begane grond | 1489.67 | 1200 | 0.0297933 | 1.7876 | 1.7876 | 0.035752 | 0.035752 | 21.4512 | 1.7876 | 0.024
21_Wand_Wand-x | Begane grond | 1490.5 | 1200 | 0.02981 | 1.7886 | 1.7886 | 0.035772 | 0.035772 | 21.4632 | 1.7886 | 0.024
21_Wand_Wand-x | Begane grond | 144.833 | 1200 | 0.00289665 | 0.173799 | 0.173799 | 0.00347598 | 0.00347598 | 2.08559 | 0.173799 | 0.024
21_Wand_Wand-x | Begane grond | 214.946 | 1200 | 0.00429892 | 0.257935 | 0.257935 | 0.0051587 | 0.0051587 | 3.09522 | 0.257935 | 0.024
21_Wand_Wand-x | Begane grond | 489.852 | 1200 | 0.00979703 | 0.587822 | 0.587822 | 0.0117564 | 0.0117564 | 7.05386 | 0.587822 | 0.024
21_Wand_Wand-x | Begane grond | 4179.74 | 1200 | 0.0835947 | 5.01568 | 5.01568 | 0.100314 | 0.100314 | 60.1882 | 5.01568 | 0.024
21_Wand_Wand-x | Begane grond | 490.281 | 1200 | 0.00980563 | 0.588338 | 0.588338 | 0.0117668 | 0.0117668 | 7.06005 | 0.588338 | 0.024
21_Wand_Wand-x | Begane grond | 3790 | 1200 | 0.0758 | 4.548 | 4.548 | 0.09096 | 0.09096 | 54.576 | 4.548 | 0.024
21_Wand_Wand-x | Begane grond | 700 | 1200 | 0.014 | 0.84 | 0.84 | 0.0168 | 0.0168 | 10.08 | 0.84 | 0.024
21_Wand_Wand-x | Begane grond | 1561 | 1200 | 0.03122 | 1.8732 | 1.8732 | 0.037464 | 0.037464 | 22.4784 | 1.8732 | 0.024
21_Wand_Wand-x | Begane grond | 3850 | 1200 | 0.077 | 4.62 | 4.62 | 0.0924 | 0.0924 | 55.44 | 4.62 | 0.024
21_Wand_Wand-x | Begane grond | 371 | 1200 | 0.00742 | 0.4452 | 0.4452 | 0.008904 | 0.008904 | 5.3424 | 0.4452 | 0.024
21_Wand_Wand-x | Begane grond | 182.454 | 1200 | 0.00389908 | 0.233945 | 0.233945 | 0.0046789 | 0.0046789 | 2.80734 | 0.233945 | 0.024
21_Wand_Wand-x | Begane grond | 421.901 | 1200 | 0.00843802 | 0.506281 | 0.506281 | 0.0101256 | 0.0101256 | 6.07538 | 0.506281 | 0.024
21_Wand_Wand-x | Begane grond | 3151.56 | 1200 | 0.0632812 | 3.79687 | 3.79687 | 0.0759374 | 0.0759374 | 45.5624 | 3.79687 | 0.024
21_Wand_Wand-x | Begane grond | 940.558 | 1200 | 0.0188112 | 1.12867 | 1.12867 | 0.0225734 | 0.0225734 | 13.544 | 1.12867 | 0.024
21_Wand_Wand-x | 1e verdieping | 3590 | 1200 | 0.0718 | 4.308 | 4.308 | 0.08616 | 0.08616 | 51.696 | 4.308 | 0.024
21_Wand_Wand-x | 1e verdieping | 966 | 1200 | 0.01932 | 1.1592 | 1.1592 | 0.023184 | 0.023184 | 13.9104 | 1.1592 | 0.024
21_Wand_Wand-x | 1e verdieping | 950 | 1200 | 0.019 | 1.155 | 1.152 | 0.0231 | 0.0228 | 13.68 | 1.14 | 0.024
21_Wand_Wand-x | 1e verdieping | 375 | 1200 | 0.0075 | 0.45 | 0.45 | 0.009 | 0.009 | 5.4 | 0.45 | 0.024
21_Wand_Wand-x | 1e verdieping | 3616.45 | 1200 | 0.0723291 | 4.33975 | 4.33975 | 0.0867949 | 0.0867949 | 52.0769 | 4.33975 | 0.024
21_Wand_Wand-x | 1e verdieping | 3631.05 | 1200 | 0.0728709 | 4.37226 | 4.37226 | 0.0874451 | 0.0874451 | 52.4671 | 4.37226 | 0.024
21_Wand_Wand-x | 1e verdieping | 3758.93 | 1200 | 0.0751787 | 4.51072 | 4.51072 | 0.0902144 | 0.0902144 | 54.1286 | 4.51072 | 0.024
21_Wand_Wand-x | 1e verdieping | 865.278 | 1200 | 0.0173056 | 1.03833 | 1.03833 | 0.0207667 | 0.0207667 | 12.46 | 1.03833 | 0.024
21_Wand_Wand-x | 1e verdieping | 425.665 | 1200 | 0.00851331 | 0.525798 | 0.522798 | 0.010516 | 0.010216 | 6.12958 | 0.510798 | 0.024
21_Wand_Wand-x | 1e verdieping | 388.464 | 1200 | 0.00776928 | 0.466157 | 0.466157 | 0.00932313 | 0.00932313 | 5.59388 | 0.466157 | 0.024
21_Wand_Wand-x | 1e verdieping | 283.002 | 1200 | 0.00566004 | 0.339602 | 0.339602 | 0.00679205 | 0.00679205 | 4.07523 | 0.339602 | 0.024
21_Wand_Wand-x | 1e verdieping | 950 | 1200 | 0.01925 | 1.155 | 1.155 | 0.0231 | 0.0231 | 13.86 | 1.155 | 0.024
21_Wand_Wand-x | 1e verdieping | 941 | 1200 | 0.01882 | 1.1292 | 1.1292 | 0.022584 | 0.022584 | 13.5504 | 1.1292 | 0.024
21_Wand_Wand-x | 1e verdieping | 3577.5 | 1200 | 0.07155 | 4.293 | 4.293 | 0.08586 | 0.08586 | 51.516 | 4.293 | 0.024
2 x 21_Wand_Wand-x | 1e verdieping | 1210 | 1200 | 0.0242 | 1.452 | 1.452 | 0.02904 | 0.02904 | 17.424 | 1.452 | 0.024
21_Wand_Wand-x | 1e verdieping | 961.271 | 1200 | 0.0192254 | 1.16852 | 1.16552 | 0.0233705 | 0.0230705 | 13.8423 | 1.15352 | 0.024
21_Wand_Wand-x | 1e verdieping | 297.35 | 1200 | 0.00594701 | 0.372359 | 0.369251 | 0.00744718 | 0.00713641 | 4.28184 | 0.360065 | 0.024
21_Wand_Wand-x | 1e verdieping | 1010.64 | 1200 | 0.0202129 | 1.21277 | 1.21277 | 0.0242554 | 0.0242554 | 14.5533 | 1.21277 | 0.024
2 x 21_Wand_Wand-x | 1e verdieping | 1143.98 | 1200 | 0.0228795 | 1.37277 | 1.37277 | 0.0274555 | 0.0274555 | 16.4733 | 1.37277 | 0.024
21_Wand_Wand-x | 1e verdieping | 508.712 | 1200 | 0.0101742 | 0.610454 | 0.610454 | 0.0122091 | 0.0122091 | 7.32545 | 0.610454 | 0.024
21_Wand_Wand-x | 1e verdieping | 685.919 | 1200 | 0.0139684 | 0.838102 | 0.838102 | 0.016762 | 0.016762 | 10.0572 | 0.838102 | 0.024
21_Wand_Wand-x | 1e verdieping | 185.66 | 1200 | 0.0039632 | 0.237792 | 0.237792 | 0.00475583 | 0.00475583 | 2.8535 | 0.237792 | 0.024
21_Wand_Wand-x | 1e verdieping | 924.34 | 1200 | 0.0184868 | 1.12421 | 1.12121 | 0.0224842 | 0.0221842 | 13.3105 | 1.10921 | 0.024

# IfcWall: Hout - Spaanplaat 25 (40)
Classification: Wand (ARCHICAD Classification); 21.22 SPOUWWANDEN (NL/SfB (4 cijfers)); Material: Hout - Spaanplaat
Pset_WallCommon - LoadBearing: yes; IsExternal: yes
BaseQuantities - Width: 25 mm
Component Quantities - Component 1, Skin Thickness: 25 mm
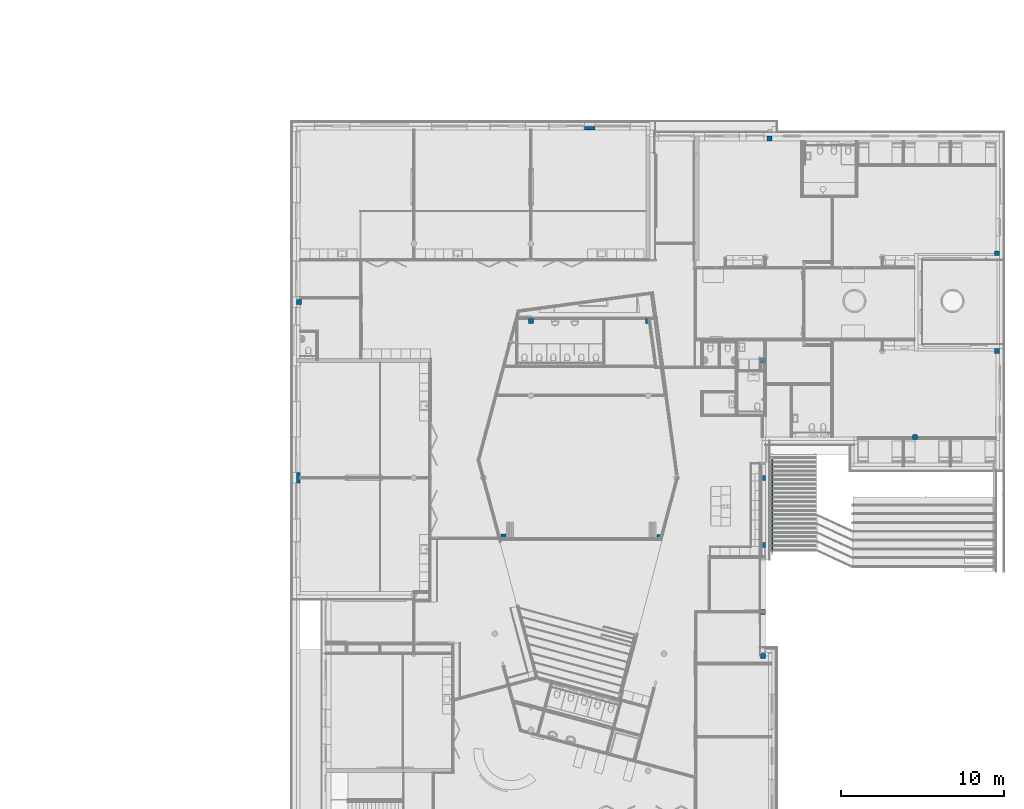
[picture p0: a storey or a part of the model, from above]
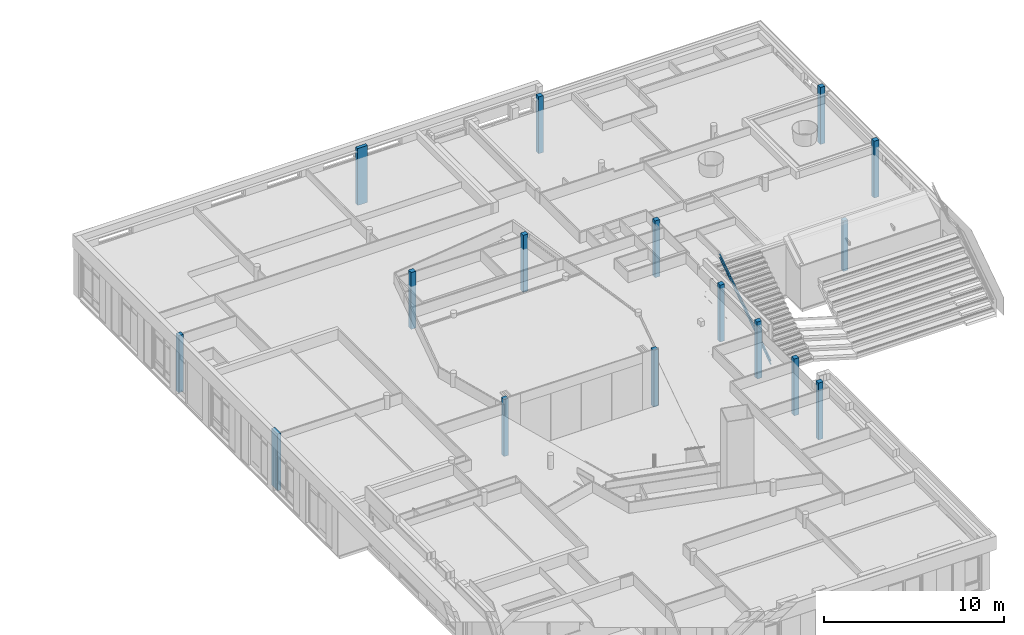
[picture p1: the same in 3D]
Properties of the parts of a building model (IFC2X3), part 5 of 5

# IfcWall: Hout - Spaanplaat 25 (40)
Name | In | Length (mm) | Height (mm) | GrossFootprintArea (m2) = NetFootprintArea (m2) | GrossSideArea (m2) = NetSideArea (m2) | GrossVolume (m3) = NetVolume (m3) = Component 1, Skin/Component Volume (m3) | Component 1, Mass (kg) | Component 1, Projected Component/Skin Area (m2) | Component 1, Component Cross Section Area (m2) | Component 1, Rectangular Component Height (mm) | Component 1, Rectangular Component Width (mm)
2 x 21_Wand_Wand-x | Begane grond | 2086.81 | 845 | 0.0495206 | 1.77243 | 0.0443107 | 26.5864 | 1.77468 | 0.0212057
21_Wand_Wand-x | Begane grond | 6028.1 | 730 | 0.148828 | 4.09478 | 0.10237 | 61.4217 | 4.09484 | 0.01825 | 730 | 25
21_Wand_Wand-x | Begane grond | 7025 | 420 | 0.175937 | 2.95575 | 0.0738937 | 44.3362 | 2.95575 | 0.0105 | 420 | 25
21_Wand_Wand-x | Begane grond | 7000 | 420 | 0.175 | 2.94 | 0.0735 | 44.1 | 2.94 | 0.0105 | 420 | 25
21_Wand_Wand-x | Begane grond | 14536 | 420 | 0.361837 | 6.07887 | 0.151972 | 91.183 | 6.07887 | 0.0105 | 420 | 25
21_Wand_Wand-x | Begane grond | 6175 | 420 | 0.154375 | 2.5935 | 0.0648375 | 38.9025 | 2.5935 | 0.0105 | 420 | 25
21_Wand_Wand-x | Begane grond | 7025 | 420 | 0.175938 | 2.95575 | 0.0738938 | 44.3363 | 2.95575 | 0.0105 | 420 | 25
21_Wand_Wand-x | Begane grond | 6936 | 420 | 0.173712 | 2.91837 | 0.0729593 | 43.7756 | 2.91837 | 0.0105 | 420 | 25
21_Wand_Wand-x | Begane grond | 562.5 | 100 | 0.014375 | 0.0575 | 0.0014375 | 0.8625 | 0.0575 | 0.0025 | 100 | 25
21_Wand_Wand-x | Begane grond | 5107.5 | 100 | 0.127375 | 0.5005 | 0.0125125 | 7.5075 | 0.5005 | 0.0025 | 100 | 25
2 x 21_Wand_Wand-x | Begane grond | 2086.81 | 845 | 0.0499732 | 1.7548 | 0.0438166 | 26.29 | 1.75937 | 0.0212057
21_Wand_Wand-x | Begane grond | 575 | 100 | 0.0146875 | 0.05875 | 0.00146875 | 0.88125 | 0.05875 | 0.0025 | 100 | 25
21_Wand_Wand-x | Begane grond | 2507.5 | 100 | 0.062375 | 0.2495 | 0.0062375 | 3.7425 | 0.2495 | 0.0025 | 100 | 25
21_Wand_Wand-x | Begane grond | 3350 | 420 | 0.08375 | 1.407 | 0.035175 | 21.105 | 1.407 | 0.0105 | 420 | 25
21_Wand_Wand-x | Begane grond | 7100 | 420 | 0.1775 | 2.982 | 0.07455 | 44.73 | 2.982 | 0.0105 | 420 | 25
21_Wand_Wand-x | Begane grond | 3250.86 | 420 | 0.0812714 | 1.36536 | 0.034134 | 20.4804 | 1.36536 | 0.0105 | 420 | 25
21_Wand_Wand-x | 1e verdieping | 20727.8 | 650 | 0.514446 | 13.3756 | 0.334389 | 200.633 | 13.3756 | 0.01625 | 650 | 25
21_Wand_Wand-x | 1e verdieping | 10287.5 | 550 | 0.255625 | 5.62375 | 0.140594 | 84.3563 | 5.62375 | 0.01375 | 550 | 25
21_Wand_Wand-x | 1e verdieping | 3400.63 | 820 | 0.0850157 | 2.78852 | 0.0697129 | 41.8277 | 2.78852 | 0.0205 | 820 | 25
21_Wand_Wand-x | 1e verdieping | 10852.5 | 550 | 0.271625 | 5.94125 | 0.148531 | 89.1188 | 5.94125 | 0.01375 | 550 | 25
21_Wand_Wand-x | 1e verdieping | 7337.5 | 550 | 0.18375 | 4.0425 | 0.101062 | 60.6375 | 4.0425 | 0.01375 | 550 | 25
21_Wand_Wand-x | 1e verdieping | 14948.5 | 550 | 0.3734 | 8.2148 | 0.20537 | 123.222 | 8.2148 | 0.01375 | 550 | 25
21_Wand_Wand-x | 1e verdieping | 28123.5 | 550 | 0.69965 | 15.3923 | 0.384808 | 230.885 | 15.3923 | 0.01375 | 550 | 25
21_Wand_Wand-x | 1e verdieping | 17323.5 | 550 | 0.429023 | 9.43855 | 0.235964 | 141.578 | 9.43855 | 0.01375 | 550 | 25
21_Wand_Wand-x | 1e verdieping | 9113 | 1160 | 0.228471 | 9.0463 | 0.218405 | 131.043 | 10.606 | 0.03625 | 1450 | 25
21_Wand_Wand-x | 1e verdieping | 1265.7 | 1405 | 0.0322881 | 1.42522 | 0.0436144 | 26.1687 | 1.80418 | 0.035125 | 1405 | 25
21_Wand_Wand-x | 1e verdieping | 7658.24 | 1160 | 0.191457 | 7.58052 | 0.183019 | 109.811 | 8.88855 | 0.03625 | 1450 | 25
21_Wand_Wand-x | 1e verdieping | 1268.21 | 1450 | 0.0317053 | 1.82612 | 0.0456531 | 27.3919 | 1.83811 | 0.03625 | 1450 | 25
21_Wand_Wand-x | 1e verdieping | 8304.85 | 1160 | 0.206975 | 8.19733 | 0.197881 | 118.729 | 9.61129 | 0.03625 | 1450 | 25
21_Wand_Wand-x | 1e verdieping | 6206.74 | 1160 | 0.155815 | 6.16856 | 0.148934 | 89.3605 | 7.23365 | 0.03625 | 1450 | 25
21_Wand_Wand-x | 1e verdieping | 1269.44 | 1405 | 0.0317361 | 1.40644 | 0.0403921 | 24.2353 | 1.78188 | 0.035125 | 1405 | 25
21_Wand_Wand-x | 1e verdieping | 6852.7 | 1160 | 0.171316 | 6.78524 | 0.163792 | 98.275 | 7.95672 | 0.03625 | 1450 | 25
21_Wand_Wand-x | 1e verdieping | 1264.36 | 1405 | 0.0309638 | 1.72569 | 0.0435027 | 26.1016 | 1.74914 | 0.035125 | 1405 | 25
21_Wand_Wand-x | 1e verdieping | 1256.03 | 1405 | 0.0310778 | 1.382 | 0.0424912 | 25.4947 | 1.75064 | 0.035125 | 1405 | 25
21_Wand_Wand-x | 1e verdieping | 1258.62 | 1405 | 0.031142 | 1.74819 | 0.0437049 | 26.2229 | 1.75486 | 0.035125 | 1405 | 25
21_Wand_Wand-x | 1e verdieping | 2850 | 550 | 0.07125 | 1.5675 | 0.0391875 | 23.5125 | 1.5675 | 0.01375 | 550 | 25
21_Wand_Wand-x | 1e verdieping | 14948.5 | 550 | 0.371525 | 8.17355 | 0.204339 | 122.603 | 8.17355 | 0.01375 | 550 | 25
21_Wand_Wand-x | 1e verdieping | 10852.5 | 550 | 0.269125 | 5.92075 | 0.148019 | 88.8113 | 5.92075 | 0.01375 | 550 | 25

# IfcWall: Hout C 20 (2)
In: Begane grond
Classification: Wand (ARCHICAD Classification); 21.22 SPOUWWANDEN (NL/SfB (4 cijfers)); Material: Hout C
Pset_WallCommon - LoadBearing: yes; IsExternal: yes
BaseQuantities - Length: 1625.98 mm; Width: 20 mm; GrossFootprintArea: 0.0325197 m2; NetFootprintArea: 0.0325197 m2
Component Quantities - Component 1, Skin Thickness: 20 mm; Component 1, Rectangular Component Width: 20 mm
Name | Height (mm) = Component 1, Rectangular Component Height (mm) | GrossSideArea (m2) = NetSideArea (m2) = Component 1, Projected Component/Skin Area (m2) | GrossVolume (m3) = NetVolume (m3) = Component 1, Skin/Component Volume (m3) | Component 1, Mass (kg) | Component 1, Component Cross Section Area (m2)
21_Wand_Wand-x | 250 | 0.406496 | 0.00812992 | 4.47146 | 0.005
21_Wand_Wand-x | 100 | 0.162598 | 0.00325197 | 1.78858 | 0.002

# IfcWall: Isolatie - Glaswol zacht 200, 21_Wand_Wand-x
In: Begane grond
Classification: Wand (ARCHICAD Classification); 21.22 SPOUWWANDEN (NL/SfB (4 cijfers)); Material: Isolatie - Glaswol zacht
Pset_WallCommon - LoadBearing: yes; IsExternal: yes
BaseQuantities - Length: 8729.8 mm; Height: 1014.15 mm; Width: 200 mm; GrossFootprintArea: 3.29477 m2; NetFootprintArea: 3.29477 m2; GrossSideArea: 15.5049 m2; NetSideArea: 15.5049 m2; GrossVolume: 3.19209 m3; NetVolume: 3.19209 m3
Component Quantities - Component 1, Mass: 44.6893 kg; Component 1, Projected Component/Skin Area: 17.7721 m2; Component 1, Skin Thickness: 200 mm; Component 1, Component Cross Section Area: 0.422542 m2; Component 1, Skin/Component Volume: 3.19209 m3

# IfcWall: Metaal - Staal AFW 10 (5)
In: 1e verdieping
Classification: 22.13 SYSTEEMWANDEN VAST (NL/SfB (4 cijfers)); Wand (ARCHICAD Classification); Material: Metaal - Staal AFW
Pset_WallCommon - LoadBearing: no; IsExternal: no
BaseQuantities - Width: 10 mm
Component Quantities - Component 1, Skin Thickness: 10 mm; Component 1, Rectangular Component Width: 10 mm
Name | Length (mm) | Height (mm) | GrossFootprintArea (m2) = NetFootprintArea (m2) | GrossSideArea (m2) | NetSideArea (m2) = Component 1, Projected Component/Skin Area (m2) | GrossVolume (m3) | NetVolume (m3) = Component 1, Skin/Component Volume (m3) | Component 1, Mass (kg) | Component 1, Rectangular Component Height (mm) | Component 1, Component Cross Section Area (m2)
22_Wand_Wand-x | 4811.55 | 1960 | 0.0479737 | 9.36771 | 8.61739 | 0.0936771 | 0.0861739 | 685.083 | 2000 | 0.02
22_Wand_Wand-x | 2562.86 | 1780 | 0.0254736 | 4.5343 | 4.5343 | 0.045343 | 0.045343 | 360.477 | 1800 | 0.018
22_Wand_Wand-x | 2100.48 | 1780 | 0.0208798 | 3.71661 | 3.71661 | 0.0371661 | 0.0371661 | 295.47 | 1800 | 0.018
22_Wand_Wand-x | 2100.48 | 1780 | 0.020875 | 3.71575 | 3.71575 | 0.0371575 | 0.0371575 | 295.402 | 1800 | 0.018
22_Wand_Wand-x | 2562.86 | 1780 | 0.025474 | 4.53438 | 4.53438 | 0.0453438 | 0.0453438 | 360.483 | 1800 | 0.018

# IfcWall: _TenW_21_E-BOARD_304mm+20mm 324, 21_Wand_Wand-x
In: Begane grond
Classification: Wand (ARCHICAD Classification); 21.22 SPOUWWANDEN (NL/SfB (4 cijfers))
Pset_WallCommon - LoadBearing: yes; IsExternal: yes
BaseQuantities - Length: 6626.89 mm; Height: 3600 mm; Width: 324 mm; GrossFootprintArea: 2.14561 m2; NetFootprintArea: 2.14561 m2; GrossSideArea: 23.7218 m2; NetSideArea: 23.7218 m2; GrossVolume: 7.7242 m3; NetVolume: 7.7242 m3

# IfcWall: _TenW_21_E-BOARD_V1_standaard 538 (15)
Classification: Wand (ARCHICAD Classification); 21.22 SPOUWWANDEN (NL/SfB (4 cijfers))
Pset_WallCommon - LoadBearing: yes; IsExternal: yes
BaseQuantities - Width: 538 mm
Name | In | Length (mm) | Height (mm) | GrossFootprintArea (m2) = NetFootprintArea (m2) | GrossSideArea (m2) | NetSideArea (m2) | GrossVolume (m3) | NetVolume (m3)
21_Wand_Wand-x | Begane grond | 303.359 | 3272 | 0.364275 | 2.10623 | 2.10623 | 1.166 | 1.166
21_Wand_Wand-x | Begane grond | 18160 | 910 | 7.99934 | 12.8486 | 11.8136 | 5.79605 | 4.89584
21_Wand_Wand-x | Begane grond | 29310 | 910 | 13.1817 | 20.5801 | 18.0904 | 11.7185 | 9.32422
21_Wand_Wand-x | Begane grond | 50510 | 910 | 23.8897 | 36.0259 | 33.0142 | 20.3576 | 17.4609
21_Wand_Wand-x | Begane grond | 29310 | 910 | 15.6302 | 20.4679 | 20.4679 | 11.5759 | 11.5759
21_Wand_Wand-x | Begane grond | 378.259 | 910 | 0.134197 | 0.311625 | 0.311625 | 0.112066 | 0.112066
21_Wand_Wand-x | Begane grond | 782.317 | 910 | 0.351581 | 0.532822 | 0.532822 | 0.239141 | 0.239141
21_Wand_Wand-x | 1e verdieping | 18160 | 3960 | 9.9474 | 69.6925 | 35.0197 | 37.9339 | 21.822
21_Wand_Wand-x | 1e verdieping | 29310 | 3960 | 15.9074 | 111.951 | 48.5753 | 60.8688 | 29.0936
21_Wand_Wand-x | 1e verdieping | 50510 | 3960 | 27.0636 | 191.872 | 80.4239 | 103.959 | 48.1835
21_Wand_Wand-x | 1e verdieping | 29310 | 3960 | 15.6302 | 111.097 | 47.72 | 59.802 | 28.0265
21_Wand_Wand-x | 1e verdieping | 11084.2 | 3960 | 6.00203 | 42.2 | 25.5602 | 22.749 | 14.1743
21_Wand_Wand-x | 1e verdieping | 807.317 | 3960 | 0.36522 | 2.93821 | 2.93821 | 1.32364 | 1.32364
21_Wand_Wand-x | 1e verdieping | 20727.8 | 526 | 11.1515 | 7.37909 | 7.37909 | 4.36763 | 4.36763
21_Wand_Wand-x | 1e verdieping | 755 | 3960 | 0.337073 | 2.74882 | 2.74882 | 1.22174 | 1.22174

# IfcWall: _TenW_21_E-BOARD_bg_standaard 498 (6)
Classification: Wand (ARCHICAD Classification); 21.22 SPOUWWANDEN (NL/SfB (4 cijfers))
Pset_WallCommon - LoadBearing: yes; IsExternal: yes
BaseQuantities - Width: 498 mm
Name | In | Length (mm) | Height (mm) | GrossFootprintArea (m2) = NetFootprintArea (m2) | GrossSideArea (m2) | NetSideArea (m2) | GrossVolume (m3) | NetVolume (m3)
21_Wand_Wand-x | Begane grond | 21815 | 3150 | 8.51141 | 68.7001 | 24.3487 | 34.0542 | 15.34
21_Wand_Wand-x | Begane grond | 28870 | 3150 | 10.8647 | 90.8173 | 28.9425 | 45.1048 | 18.1395
21_Wand_Wand-x | Begane grond | 1885.42 | 3150 | 0.880992 | 5.88227 | 5.88227 | 2.76419 | 2.76419
21_Wand_Wand-x | Begane grond | 5349.58 | 3600 | 2.68394 | 19.281 | 19.281 | 9.66219 | 9.66219
21_Wand_Wand-x | 1e verdieping | 1556 | 3620 | 0.831624 | 5.76666 | 5.76666 | 3.01048 | 3.01048
21_Wand_Wand-x | 1e verdieping | 1430 | 910 | 0.71214 | 0.99385 | 0.99385 | 0.516459 | 0.516459

# IfcWall: _TenW_21_OK HSB buitenwand RC 4,5 373 (4)
In: 1e verdieping
Classification: 22.13 SYSTEEMWANDEN VAST (NL/SfB (4 cijfers)); Wand (ARCHICAD Classification)
Pset_WallCommon - LoadBearing: no; IsExternal: no
BaseQuantities - Width: 372.5 mm
Name | Length (mm) | Height (mm) | GrossFootprintArea (m2) = NetFootprintArea (m2) | GrossSideArea (m2) = NetSideArea (m2) | GrossVolume (m3) = NetVolume (m3)
22_Wand_Wand-x | 3046.24 | 3345.46 | 1.10274 | 9.80121 | 3.78596
22_Wand_Wand-x | 3046.24 | 2981.13 | 1.10274 | 8.36552 | 3.26053
22_Wand_Wand-x | 3044.24 | 3023.97 | 1.10223 | 8.64441 | 3.35452
22_Wand_Wand-x | 3044.24 | 2667.78 | 1.10223 | 7.28002 | 2.85564

# IfcWall: _TenW_21_Spouwmuur ht-150-kz RC 4,7 424 (3)
In: Begane grond
Classification: Wand (ARCHICAD Classification); 21.22 SPOUWWANDEN (NL/SfB (4 cijfers))
Pset_WallCommon - LoadBearing: yes; IsExternal: yes
BaseQuantities - Width: 424 mm
Name | Length (mm) | Height (mm) | GrossFootprintArea (m2) = NetFootprintArea (m2) | GrossSideArea (m2) | NetSideArea (m2) | GrossVolume (m3) | NetVolume (m3)
21_Wand_Wand-x | 5011 | 3630 | 1.54331 | 16.6876 | 5.4853 | 7.26489 | 2.53225
21_Wand_Wand-x | 5011 | 3630 | 1.49985 | 16.655 | 5.45263 | 7.10713 | 2.37449
21_Wand_Wand-x | 5152 | 750 | 2.18445 | 3.2844 | 3.2844 | 1.46446 | 1.46446

# IfcWall: _TenW_21_Spouwmuur ht-kz-214- RC 4,7 488 (12)
BaseQuantities - Width: 488 mm
Name | In | Classification | LoadBearing = IsExternal | Length (mm) | Height (mm) | GrossFootprintArea (m2) = NetFootprintArea (m2) | GrossSideArea (m2) | NetSideArea (m2) | GrossVolume (m3) | NetVolume (m3)
21_Wand_Wand-x | Begane grond | Wand (ARCHICAD Classification); 21.22 SPOUWWANDEN (NL/SfB (4 cijfers)) | yes | 17481 | 3050 | 4.26916 | 53.6159 | 29.1496 | 26.0266 | 14.0395
21_Wand_Wand-x | Begane grond | Wand (ARCHICAD Classification); 21.22 SPOUWWANDEN (NL/SfB (4 cijfers)) | yes | 7399 | 3630 | 2.94671 | 26.2282 | 16.1396 | 12.8112 | 7.63565
22_Wand_Wand-x | Begane grond | 22.13 SYSTEEMWANDEN VAST (NL/SfB (4 cijfers)); Wand (ARCHICAD Classification) | no | 8755 | 2865.85 | 4.35318 | 25.9656 | 25.9656 | 12.4196 | 12.4196
21_Wand_Wand-x | Begane grond | Wand (ARCHICAD Classification); 21.22 SPOUWWANDEN (NL/SfB (4 cijfers)) | yes | 7304.21 | 3960 | 3.0959 | 27.3214 | 24.7565 | 13.6142 | 12.362
21_Wand_Wand-x | Begane grond | Wand (ARCHICAD Classification); 21.22 SPOUWWANDEN (NL/SfB (4 cijfers)) | yes | 5576 | 3405 | 2.33243 | 18.8928 | 8.00681 | 9.23255 | 3.92734
21_Wand_Wand-x | Begane grond | Wand (ARCHICAD Classification); 21.22 SPOUWWANDEN (NL/SfB (4 cijfers)) | yes | 430 | 3050 | 0.165212 | 1.28405 | 1.28405 | 0.503897 | 0.503897
22_Wand_Wand-x | Begane grond | 22.13 SYSTEEMWANDEN VAST (NL/SfB (4 cijfers)); Wand (ARCHICAD Classification) | no | 5401 | 3425 | 2.71076 | 18.0375 | 18.0375 | 8.97225 | 8.97225
22_Wand_Wand-x | Begane grond | 22.13 SYSTEEMWANDEN VAST (NL/SfB (4 cijfers)); Wand (ARCHICAD Classification) | no | 1600 | 3388.27 | 0.691544 | 4.39568 | 4.39568 | 2.06341 | 2.06341
21_Wand_Wand-x | Begane grond | Wand (ARCHICAD Classification); 21.22 SPOUWWANDEN (NL/SfB (4 cijfers)) | yes | 7526 | 3630 | 2.96405 | 26.8055 | 16.7569 | 12.9349 | 7.7841
21_Wand_Wand-x | 1e verdieping | Wand (ARCHICAD Classification); 21.22 SPOUWWANDEN (NL/SfB (4 cijfers)) | yes | 3535 | 3620 | 1.71297 | 12.4419 | 6.30994 | 6.20096 | 3.19272
21_Wand_Wand-x | 1e verdieping | Wand (ARCHICAD Classification); 21.22 SPOUWWANDEN (NL/SfB (4 cijfers)) | yes | 1556 | 4050 | 0.7147 | 5.52746 | 5.52746 | 2.74859 | 2.74859
21_Wand_Wand-x | 1e verdieping | Wand (ARCHICAD Classification); 21.22 SPOUWWANDEN (NL/SfB (4 cijfers)) | yes | 12100 | 1200 | 5.90482 | 14.52 | 14.52 | 7.08578 | 7.08578

# IfcWall: _TenW_21_Spouwmuur ht-kz-214- RC 4,7 smal 488 (2)
In: 1e verdieping
Classification: Wand (ARCHICAD Classification); 21.22 SPOUWWANDEN (NL/SfB (4 cijfers))
Pset_WallCommon - LoadBearing: yes; IsExternal: yes
BaseQuantities - Height: 1630 mm; Width: 488 mm
Name | Length (mm) | GrossFootprintArea (m2) = NetFootprintArea (m2) | GrossSideArea (m2) | NetSideArea (m2) | GrossVolume (m3) | NetVolume (m3)
21_Wand_Wand-x | 13706 | 6.89127 | 20.3639 | 20.3639 | 10.0675 | 10.0675
21_Wand_Wand-x | 23178.9 | 11.2667 | 34.4832 | 32.5176 | 16.9593 | 16

# IfcWall: _TenW_21_Spouwmuur ht-kz-300- RC 4,7 574 (5)
In: Begane grond
Classification: Wand (ARCHICAD Classification); 21.22 SPOUWWANDEN (NL/SfB (4 cijfers))
Pset_WallCommon - LoadBearing: yes; IsExternal: yes
BaseQuantities - Width: 574 mm
Name | Length (mm) | Height (mm) | GrossFootprintArea (m2) = NetFootprintArea (m2) | GrossSideArea (m2) | NetSideArea (m2) | GrossVolume (m3) | NetVolume (m3)
21_Wand_Wand-x | 27417 | 3050 | 7.0846 | 84.4057 | 41.3965 | 48.3264 | 23.5731
21_Wand_Wand-x | 20767 | 3050 | 5.3583 | 63.3119 | 30.4287 | 36.1533 | 17.2483
21_Wand_Wand-x | 21201 | 3630 | 9.18318 | 75.4228 | 44.3874 | 42.9878 | 24.7005
21_Wand_Wand-x | 20767 | 910 | 9.44051 | 11.3975 | 9.30947 | 6.16547 | 4.98737
21_Wand_Wand-x | 27173 | 480 | 9.9143 | 12.9778 | 8.34673 | 7.37627 | 4.75826

# IfcWall: _TenW_21_buitenmuur ht-uittimmer-214- ht 488, 21_Wand_Wand-x
In: Begane grond
Classification: Wand (ARCHICAD Classification); 21.22 SPOUWWANDEN (NL/SfB (4 cijfers))
Pset_WallCommon - LoadBearing: yes; IsExternal: yes
BaseQuantities - Length: 6265 mm; Height: 3630 mm; Width: 488 mm; GrossFootprintArea: 2.43073 m2; NetFootprintArea: 2.43073 m2; GrossSideArea: 22.742 m2; NetSideArea: 15.3107 m2; GrossVolume: 11.0981 m3; NetVolume: 7.47163 m3

# IfcWall: _TenW_22_Metalstud 100 enkel gipsvezelplaat 100 (186)
Classification: 22.13 SYSTEEMWANDEN VAST (NL/SfB (4 cijfers)); Wand (ARCHICAD Classification)
Pset_WallCommon - LoadBearing: no; IsExternal: no
BaseQuantities - Width: 100 mm
Name | In | Length (mm) | Height (mm) | GrossFootprintArea (m2) = NetFootprintArea (m2) | GrossSideArea (m2) | NetSideArea (m2) | GrossVolume (m3) | NetVolume (m3)
22_Wand_Wand-x | Begane grond | 1450 | 3375 | 0.145 | 4.89375 | 4.89375 | 0.489375 | 0.489375
22_Wand_Wand-x | Begane grond | 3736 | 3600 | 0.360006 | 13.1121 | 13.1121 | 1.29602 | 1.29602
2 x 22_Wand_Wand-x | Begane grond | 7936 | 3600 | 0.794537 | 28.5696 | 28.5696 | 2.86033 | 2.86033
22_Wand_Wand-x | Begane grond | 7273.35 | 3600 | 0.758272 | 26.1946 | 26.1946 | 2.62362 | 2.62362
2 x 22_Wand_Wand-x | Begane grond | 2750 | 3600 | 0.291406 | 9.5835 | 9.5835 | 0.943162 | 0.943162
22_Wand_Wand-x | Begane grond | 4436 | 3600 | 0.467969 | 16.0071 | 16.0071 | 1.60915 | 1.60915
22_Wand_Wand-x | Begane grond | 7450 | 3600 | 0.773125 | 26.4307 | 26.4307 | 2.67722 | 2.67722
22_Wand_Wand-x | Begane grond | 14625 | 3600 | 0.862656 | 52.2675 | 28.1048 | 5.26556 | 2.84929
22_Wand_Wand-x | Begane grond | 7936 | 3600 | 0.794537 | 28.5591 | 28.5591 | 2.86007 | 2.86007
22_Wand_Wand-x | Begane grond | 950 | 3600 | 0.0929688 | 3.3975 | 3.3975 | 0.334687 | 0.334687
22_Wand_Wand-x | Begane grond | 13510 | 3600 | 0.617691 | 45.9131 | 24.992 | 4.65757 | 2.56546
22_Wand_Wand-x | Begane grond | 12600 | 3600 | 0.559029 | 44.5902 | 24.7697 | 4.49651 | 2.50849
2 x 22_Wand_Wand-x | Begane grond | 4386 | 3600 | 0.460937 | 15.8046 | 15.8046 | 1.58383 | 1.58383
22_Wand_Wand-x | Begane grond | 4200 | 3600 | 0.130092 | 14.9442 | 6.68646 | 1.49748 | 0.676656
22_Wand_Wand-x | Begane grond | 4551.15 | 3600 | 0.454177 | 15.4756 | 15.4756 | 1.58384 | 1.58384
22_Wand_Wand-x | Begane grond | 4200 | 2880 | 0.3166 | 12.096 | 8.38473 | 1.2096 | 0.838473
22_Wand_Wand-x | Begane grond | 637.5 | 3375 | 0.0646875 | 2.15156 | 2.15156 | 0.21832 | 0.21832
22_Wand_Wand-x | Begane grond | 600 | 3375 | 0.0609375 | 2.025 | 2.025 | 0.205664 | 0.205664
22_Wand_Wand-x | Begane grond | 4291 | 3375 | 0.430037 | 14.3556 | 14.3556 | 1.45138 | 1.45138
22_Wand_Wand-x | Begane grond | 3350 | 3375 | 0.326562 | 11.1797 | 11.1797 | 1.10215 | 1.10215
22_Wand_Wand-x | Begane grond | 1437.5 | 3375 | 0.144687 | 4.85156 | 4.85156 | 0.48832 | 0.48832
22_Wand_Wand-x | Begane grond | 3201.56 | 3600 | 0.343587 | 11.4281 | 11.4281 | 1.16137 | 1.16137
22_Wand_Wand-x | Begane grond | 3329.23 | 3600 | 0.015892 | 11.9507 | 2.91024 | 1.19091 | 0.286861
22_Wand_Wand-x | Begane grond | 3515 | 3600 | 0.068525 | 11.7618 | 4.4553 | 1.16439 | 0.43284
22_Wand_Wand-x | Begane grond | 2396 | 3600 | 0.0091 | 8.5956 | 1.8511 | 0.87531 | 0.20086
22_Wand_Wand-x | Begane grond | 6075 | 3600 | 0.392656 | 21.5775 | 13.103 | 2.16956 | 1.32211
22_Wand_Wand-x | Begane grond | 3686 | 3600 | 0.369538 | 13.2696 | 13.2696 | 1.33033 | 1.33033
22_Wand_Wand-x | Begane grond | 3868.17 | 3600 | 0.169005 | 13.5984 | 7.57142 | 1.36412 | 0.761417
22_Wand_Wand-x | Begane grond | 320.462 | 3600 | 0.0341491 | 1.27469 | 1.27469 | 0.121886 | 0.121886
22_Wand_Wand-x | Begane grond | 4460.33 | 2318 | 0.342633 | 10.3391 | 7.94224 | 1.03391 | 0.794224
22_Wand_Wand-x | Begane grond | 7839.67 | 668 | 0.783967 | 3.90416 | 3.90416 | 0.466267 | 0.466267
22_Wand_Wand-x | Begane grond | 1700.02 | 4030 | 0.108005 | 6.44091 | 3.92106 | 0.652741 | 0.400755
22_Wand_Wand-x | Begane grond | 1090.82 | 1660 | 0.109082 | 1.43216 | 1.43216 | 0.14957 | 0.14957
2 x 22_Wand_Wand-x | Begane grond | 500 | 3600 | 0.051875 | 1.8 | 1.8 | 0.18675 | 0.18675
22_Wand_Wand-x | Begane grond | 1601.15 | 3600 | 0.16199 | 5.76413 | 5.86913 | 0.583163 | 0.580538
22_Wand_Wand-x | Begane grond | 1050 | 3600 | 0.107969 | 3.8025 | 1.41352 | 0.388687 | 0.147999
22_Wand_Wand-x | Begane grond | 1750 | 3600 | 0.172031 | 6.2775 | 6.2775 | 0.619313 | 0.619313
22_Wand_Wand-x | Begane grond | 1697.4 | 1334.04 | 0.00421613 | 2.01439 | 0.834742 | 0.198543 | 0.0811688
22_Wand_Wand-x | Begane grond | 4012.78 | 3375 | 0.402216 | 13.4166 | 13.4166 | 1.35748 | 1.35748
22_Wand_Wand-x | Begane grond | 1475 | 3181 | 0.169837 | 4.46738 | 4.46738 | 0.44972 | 0.44972
22_Wand_Wand-x | Begane grond | 1475 | 3204.97 | 0.169837 | 4.49519 | 4.49519 | 0.452524 | 0.452524
22_Wand_Wand-x | Begane grond | 2837.52 | 3600 | 0.285627 | 10.2151 | 10.2151 | 1.02826 | 1.02826
22_Wand_Wand-x | Begane grond | 8628 | 3600 | 0.856632 | 30.4526 | 28.0051 | 3.07063 | 2.82588
22_Wand_Wand-x | Begane grond | 3906.17 | 3940 | 0.401413 | 14.154 | 10.914 | 1.44651 | 1.12251
22_Wand_Wand-x | Begane grond | 4234.01 | 3600 | 0.0495969 | 15.0248 | 4.4058 | 1.51025 | 0.448349
22_Wand_Wand-x | Begane grond | 992.095 | 3940 | 0.0995467 | 3.72132 | 3.72132 | 0.365902 | 0.365902
22_Wand_Wand-x | Begane grond | 1527.03 | 3600 | 0.0372933 | 5.0114 | 2.49155 | 0.492452 | 0.240466
22_Wand_Wand-x | Begane grond | 4489.02 | 3600 | 0.45484 | 16.2055 | 12.5303 | 1.63742 | 1.2699
22_Wand_Wand-x | Begane grond | 6797.86 | 3600 | 0.672061 | 24.2775 | 18.59 | 2.41942 | 1.85067
22_Wand_Wand-x | Begane grond | 10364.6 | 3600 | 0.665374 | 37.3124 | 28.2224 | 3.73814 | 2.82914
22_Wand_Wand-x | Begane grond | 9297.87 | 3600 | 0.924815 | 33.0393 | 33.0393 | 3.32933 | 3.32933
22_Wand_Wand-x | Begane grond | 2887.52 | 3600 | 0.28672 | 10.3726 | 7.92508 | 1.03219 | 0.787445
22_Wand_Wand-x | Begane grond | 7316.8 | 3600 | 0.733233 | 26.0005 | 23.553 | 2.63724 | 2.39249
22_Wand_Wand-x | Begane grond | 4562.57 | 2880 | 0.456482 | 13.1212 | 11.6377 | 1.305 | 1.15665
22_Wand_Wand-x | Begane grond | 1719.32 | 4030 | 0.178963 | 6.49995 | 6.49995 | 0.671451 | 0.671451
22_Wand_Wand-x | Begane grond | 7120.65 | 2630 | 0.718462 | 18.5099 | 18.5099 | 1.87499 | 1.87499
22_Wand_Wand-x | Begane grond | 3299.99 | 2560 | 0.334999 | 8.35549 | 8.35549 | 0.847483 | 0.847483
22_Wand_Wand-x | Begane grond | 1825.02 | 2560 | 0.187502 | 4.67555 | 4.67555 | 0.469889 | 0.469889
22_Wand_Wand-x | Begane grond | 1549.98 | 3600 | 0.0495664 | 5.55742 | 3.03756 | 0.550679 | 0.298693
22_Wand_Wand-x | Begane grond | 1474.98 | 3600 | 0.148435 | 5.30992 | 5.30992 | 0.534367 | 0.534367
22_Wand_Wand-x | Begane grond | 3040.48 | 3600 | 0.304897 | 10.6592 | 10.6592 | 1.09763 | 1.09763
22_Wand_Wand-x | Begane grond | 8288.03 | 928 | 0.827491 | 7.70338 | 7.70338 | 0.767911 | 0.767911
22_Wand_Wand-x | Begane grond | 3925 | 3600 | 0.392656 | 13.7405 | 13.7405 | 1.41254 | 1.41254
22_Wand_Wand-x | Begane grond | 2075 | 3600 | 0.211406 | 7.4925 | 7.4925 | 0.761062 | 0.761062
22_Wand_Wand-x | Begane grond | 4312.5 | 3530 | 0.005 | 15.2231 | 3.28812 | 1.52562 | 0.329497
22_Wand_Wand-x | Begane grond | 1601.15 | 3600 | 0.16199 | 5.76413 | 5.77673 | 0.583163 | 0.582848
22_Wand_Wand-x | Begane grond | 4551.15 | 3600 | 0.340777 | 15.9791 | 12.7245 | 1.63504 | 1.30958
22_Wand_Wand-x | Begane grond | 4911.49 | 3600 | 0.0986322 | 17.1597 | 6.15183 | 1.74825 | 0.635734
22_Wand_Wand-x | Begane grond | 1450 | 3600 | 0.0256625 | 5.175 | 1.92042 | 0.500625 | 0.175167
22_Wand_Wand-x | Begane grond | 3779.53 | 3600 | 0.136497 | 13.5815 | 6.62382 | 1.36351 | 0.667739
22_Wand_Wand-x | Begane grond | 3200 | 3375 | 0.320937 | 10.8 | 10.8 | 1.08316 | 1.08316
22_Wand_Wand-x | Begane grond | 1650 | 3600 | 0.165938 | 5.805 | 5.805 | 0.597375 | 0.597375
22_Wand_Wand-x | Begane grond | 600 | 3600 | 0.0609375 | 2.16 | 2.16 | 0.219375 | 0.219375
22_Wand_Wand-x | Begane grond | 580 | 3530 | 0.058 | 2.0474 | 2.0474 | 0.20474 | 0.20474
22_Wand_Wand-x | Begane grond | 2823.89 | 3600 | 0.175561 | 10.0219 | 7.50203 | 1.00425 | 0.752261
22_Wand_Wand-x | Begane grond | 3330 | 3530 | 0.001 | 12.036 | 2.4615 | 1.2054 | 0.247069
22_Wand_Wand-x | Begane grond | 831.827 | 3600 | 0.0841202 | 2.99458 | 2.99458 | 0.302833 | 0.302833
22_Wand_Wand-x | Begane grond | 10200 | 3600 | 0.450156 | 36.3255 | 16.2185 | 3.67226 | 1.66066
22_Wand_Wand-x | Begane grond | 1851.13 | 2670 | 0.185113 | 4.89154 | 4.89154 | 0.492597 | 0.492597
22_Wand_Wand-x | Begane grond | 439.852 | 3600 | 0.0410164 | 1.56097 | 1.56097 | 0.147659 | 0.147659
22_Wand_Wand-x | Begane grond | 950 | 3600 | 0.0959375 | 3.42 | 3.42 | 0.345375 | 0.345375
22_Wand_Wand-x | Begane grond | 7500 | 3600 | 0.229919 | 26.5035 | 13.1171 | 2.69929 | 1.36064
22_Wand_Wand-x | Begane grond | 7800 | 3600 | 0.475123 | 27.7827 | 17.3327 | 2.79044 | 1.74544
22_Wand_Wand-x | Begane grond | 881.827 | 3600 | 0.0911515 | 3.19708 | 3.19708 | 0.328145 | 0.328145
22_Wand_Wand-x | Begane grond | 300 | 3375 | 0.0339062 | 1.03359 | 1.03359 | 0.114434 | 0.114434
22_Wand_Wand-x | Begane grond | 1703.48 | 3375 | 0.168317 | 5.72817 | 5.72817 | 0.568071 | 0.568071
22_Wand_Wand-x | Begane grond | 1690.98 | 3375 | 0.173005 | 5.72817 | 5.72817 | 0.583891 | 0.583891
22_Wand_Wand-x | Begane grond | 287.5 | 3375 | 0.0267187 | 0.949219 | 0.949219 | 0.0901758 | 0.0901758
22_Wand_Wand-x | Begane grond | 5700.34 | 3600 | 0.57394 | 20.5437 | 20.5437 | 2.06618 | 2.06618
22_Wand_Wand-x | Begane grond | 61 | 3600 | 0.0245313 | 0.21208 | 0.21208 | 0.0127705 | 0.0127705
22_Wand_Wand-x | Begane grond | 1535.18 | 1251.49 | 0.00503824 | 1.62006 | 0.809765 | 0.162258 | 0.0812276
22_Wand_Wand-x | Begane grond | 3454.77 | 3600 | 0.046935 | 12.4247 | 3.82873 | 1.2469 | 0.387299
22_Wand_Wand-x | Begane grond | 17600 | 3600 | 0.875626 | 63.45 | 30.1 | 6.39225 | 3.05725
22_Wand_Wand-x | Begane grond | 3575 | 3600 | 0.101094 | 13.0725 | 5.3235 | 1.33594 | 0.561037
22_Wand_Wand-x | Begane grond | 4523.35 | 3600 | 0.466866 | 16.6163 | 16.6163 | 1.68059 | 1.68059
22_Wand_Wand-x | Begane grond | 5913.06 | 3600 | 0.603525 | 21.5168 | 19.0693 | 2.17269 | 1.92794
22_Wand_Wand-x | Begane grond | 547.721 | 3940 | 0.0679144 | 1.90298 | 1.90298 | 0.21442 | 0.21442
22_Wand_Wand-x | Begane grond | 1073.34 | 3940 | 0.10426 | 3.9795 | 3.9795 | 0.408445 | 0.408445
22_Wand_Wand-x | Begane grond | 1286.35 | 3600 | 0.0261728 | 4.63087 | 2.11101 | 0.466462 | 0.214476
22_Wand_Wand-x | Begane grond | 2095.15 | 928 | 0.205326 | 1.90199 | 1.90199 | 0.190543 | 0.190543
22_Wand_Wand-x | Begane grond | 4312.5 | 3305 | 0.005 | 14.2528 | 2.31781 | 1.42838 | 0.232255
22_Wand_Wand-x | Begane grond | 715.1 | 3600 | 0.0754163 | 2.59686 | 2.59686 | 0.271498 | 0.271498
22_Wand_Wand-x | Begane grond | 225 | 3600 | 0.0204688 | 0.7875 | 0.7875 | 0.0736875 | 0.0736875
2 x 22_Wand_Wand-x | 1e verdieping | 7736 | 3620 | 0.774538 | 27.9906 | 27.9906 | 2.80348 | 2.80348
22_Wand_Wand-x | 1e verdieping | 6050 | 3620 | 0.607031 | 21.7879 | 21.7879 | 2.19745 | 2.19745
22_Wand_Wand-x | 1e verdieping | 6000 | 3620 | 0.600938 | 21.72 | 21.72 | 2.17539 | 2.17539
2 x 22_Wand_Wand-x | 1e verdieping | 1586 | 820 | 0 | 5.72757 | 1.28677 | 0.573788 | 0.129708
22_Wand_Wand-x | 1e verdieping | 10725 | 3620 | 0.4125 | 37.9195 | 16.3795 | 3.79195 | 1.63795
22_Wand_Wand-x | 1e verdieping | 25125 | 3620 | 1.30578 | 90.3749 | 45.5069 | 9.07063 | 4.58293
22_Wand_Wand-x | 1e verdieping | 11400 | 3620 | 0.545938 | 41.3013 | 20.7533 | 4.14799 | 2.09229
22_Wand_Wand-x | 1e verdieping | 7036 | 3620 | 0.707038 | 25.36 | 25.36 | 2.5542 | 2.5542
22_Wand_Wand-x | 1e verdieping | 6986 | 3620 | 0.7036 | 25.2801 | 25.2801 | 2.53235 | 2.53235
22_Wand_Wand-x | 1e verdieping | 7036 | 3620 | 0.699693 | 25.3119 | 25.3119 | 2.53289 | 2.53289
22_Wand_Wand-x | 1e verdieping | 9853.34 | 3950 | 0.995718 | 33.8971 | 23.3971 | 3.35315 | 2.30315
22_Wand_Wand-x | 1e verdieping | 3534.1 | 3620 | 0.353443 | 12.6577 | 12.6577 | 1.27946 | 1.27946
22_Wand_Wand-x | 1e verdieping | 5265.68 | 3620 | 0.526335 | 18.7692 | 18.7692 | 1.90533 | 1.90533
22_Wand_Wand-x | 1e verdieping | 6194.32 | 3620 | 0.414663 | 22.3103 | 17.4154 | 2.2497 | 1.7602
22_Wand_Wand-x | 1e verdieping | 2875.02 | 3620 | 0.287502 | 10.2718 | 10.2718 | 1.04076 | 1.04076
22_Wand_Wand-x | 1e verdieping | 8109.87 | 3620 | 0.817237 | 29.5387 | 29.5387 | 2.95215 | 2.95215
22_Wand_Wand-x | 1e verdieping | 2900.02 | 3620 | 0.290939 | 10.4981 | 10.4981 | 1.0532 | 1.0532
22_Wand_Wand-x | 1e verdieping | 5036.74 | 3620 | 0.301841 | 17.9354 | 13.0405 | 1.81652 | 1.32702
22_Wand_Wand-x | 1e verdieping | 3906.17 | 3710 | 0.115269 | 14.0128 | 6.17279 | 1.41473 | 0.630733
22_Wand_Wand-x | 1e verdieping | 8579.91 | 3620 | 0.862081 | 30.8332 | 30.8332 | 3.12073 | 3.12073
22_Wand_Wand-x | 1e verdieping | 1568.67 | 3620 | 0.15862 | 5.67859 | 5.69018 | 0.574646 | 0.574357
22_Wand_Wand-x | 1e verdieping | 3350 | 3720 | 0.335 | 12.2945 | 12.2945 | 1.22778 | 1.22778
22_Wand_Wand-x | 1e verdieping | 4569.54 | 3720 | 0.462998 | 16.3292 | 16.3292 | 1.64949 | 1.64949
22_Wand_Wand-x | 1e verdieping | 3119.42 | 1000 | 0.311161 | 3.08817 | 3.08817 | 0.311161 | 0.311161
22_Wand_Wand-x | 1e verdieping | 5700 | 3620 | 0.257537 | 20.4982 | 11.7231 | 2.06679 | 1.18927
22_Wand_Wand-x | 1e verdieping | 3400 | 3620 | 0.340937 | 12.308 | 12.308 | 1.23419 | 1.23419
22_Wand_Wand-x | 1e verdieping | 4075 | 3620 | 0.244654 | 14.2071 | 9.72709 | 1.46154 | 1.01354
2 x 22_Wand_Wand-x | 1e verdieping | 3736 | 3620 | 0.374537 | 13.5243 | 13.5243 | 1.35583 | 1.35583
22_Wand_Wand-x | 1e verdieping | 3700 | 3620 | 0.209062 | 13.1105 | 8.6425 | 1.33571 | 0.888006
22_Wand_Wand-x | 1e verdieping | 3197.68 | 3620 | 0.320706 | 11.5756 | 11.5756 | 1.16095 | 1.16095
22_Wand_Wand-x | 1e verdieping | 7604.63 | 3620 | 0.239682 | 27.0989 | 12.6789 | 2.73195 | 1.28995
22_Wand_Wand-x | 1e verdieping | 2850 | 3620 | 0.1816 | 10.1813 | 7.73377 | 1.0317 | 0.786952
2 x 22_Wand_Wand-x | 1e verdieping | 1143.98 | 3620 | 0.11346 | 4.00545 | 4.00545 | 0.410726 | 0.410726
22_Wand_Wand-x | 1e verdieping | 1650 | 3620 | 0.063475 | 5.973 | 3.52552 | 0.604087 | 0.35934
22_Wand_Wand-x | 1e verdieping | 2156.4 | 3620 | 0.21661 | 7.6704 | 7.6704 | 0.784129 | 0.784129
22_Wand_Wand-x | 1e verdieping | 4644.12 | 3620 | 0.359155 | 16.5392 | 14.0917 | 1.67445 | 1.4297
22_Wand_Wand-x | 1e verdieping | 289.999 | 3620 | 0.0309079 | 1.0498 | 1.0498 | 0.111887 | 0.111887
22_Wand_Wand-x | 1e verdieping | 3700 | 3620 | 0.366094 | 13.0999 | 13.0999 | 1.32526 | 1.32526
22_Wand_Wand-x | 1e verdieping | 2745.88 | 3620 | 0.276496 | 9.9401 | 9.9401 | 1.00092 | 1.00092
22_Wand_Wand-x | 1e verdieping | 90.503 | 3620 | 0.00722666 | 0.292758 | 0.292758 | 0.0261605 | 0.0261605
22_Wand_Wand-x | 1e verdieping | 3358.66 | 5260 | 0.335866 | 17.6666 | 17.6666 | 1.76666 | 1.76666
22_Wand_Wand-x | 1e verdieping | 2075 | 3620 | 0.209991 | 7.40188 | 7.40188 | 0.760166 | 0.760166
22_Wand_Wand-x | 1e verdieping | 3250 | 3620 | 0.325938 | 11.7487 | 11.7487 | 1.17949 | 1.17949
22_Wand_Wand-x | 1e verdieping | 3130.02 | 3620 | 0.302282 | 11.249 | 11.249 | 1.09426 | 1.09426
22_Wand_Wand-x | 1e verdieping | 9151.45 | 2150 | 0.914174 | 17.7586 | 17.1873 | 1.72733 | 1.6702
22_Wand_Wand-x | 1e verdieping | 10253.9 | 2150 | 1.02539 | 20.1011 | 19.5356 | 2.07188 | 2.01533
22_Wand_Wand-x | 1e verdieping | 1101.96 | 3620 | 0.111134 | 3.85211 | 2.17126 | 0.402304 | 0.234219
22_Wand_Wand-x | 1e verdieping | 2950.02 | 3620 | 0.180508 | 10.2944 | 7.84696 | 1.02775 | 0.782999
22_Wand_Wand-x | 1e verdieping | 6333.16 | 3620 | 0.183847 | 22.6421 | 10.0911 | 2.29241 | 1.03412
22_Wand_Wand-x | 1e verdieping | 5212.5 | 3620 | 0.524219 | 18.7561 | 18.7561 | 1.89767 | 1.89767
22_Wand_Wand-x | 1e verdieping | 3336 | 3620 | 0.355938 | 12.5779 | 12.5779 | 1.26241 | 1.26241
22_Wand_Wand-x | 1e verdieping | 173.533 | 3620 | 0.0143574 | 0.605356 | 0.605356 | 0.0519738 | 0.0519738
22_Wand_Wand-x | 1e verdieping | 174.353 | 3620 | 0.0213501 | 0.653784 | 0.653784 | 0.0772875 | 0.0772875
22_Wand_Wand-x | 1e verdieping | 2278.25 | 3620 | 0.229733 | 8.24726 | 8.24726 | 0.831633 | 0.831633
22_Wand_Wand-x | 1e verdieping | 9479.96 | 3620 | 0.371154 | 32.9045 | 19.5468 | 3.37657 | 2.0144
22_Wand_Wand-x | 1e verdieping | 4722.89 | 3620 | 0.00919734 | 17.0849 | 4.06487 | 1.71629 | 0.414294
22_Wand_Wand-x | 1e verdieping | 6861 | 3530 | 0.385163 | 24.0635 | 15.6635 | 2.41804 | 1.57804
22_Wand_Wand-x | 1e verdieping | 5700 | 3530 | 0.257537 | 19.9886 | 11.2134 | 2.01541 | 1.13789
22_Wand_Wand-x | 1e verdieping | 3736 | 3620 | 0.374537 | 13.5106 | 13.5106 | 1.35548 | 1.35548
22_Wand_Wand-x | 1e verdieping | 11350 | 3530 | 0.532032 | 39.8991 | 19.3511 | 3.99577 | 1.94007
22_Wand_Wand-x | 1e verdieping | 1570.75 | 3620 | 0.151134 | 5.64085 | 5.64085 | 0.547106 | 0.547106
22_Wand_Wand-x | 1e verdieping | 2445.25 | 3620 | 0.140667 | 8.84831 | 6.40083 | 0.883523 | 0.638776
22_Wand_Wand-x | 1e verdieping | 3736 | 3620 | 0.3736 | 13.5243 | 13.5243 | 1.35243 | 1.35243
22_Wand_Wand-x | 1e verdieping | 3400 | 3530 | 0.340937 | 12.002 | 12.002 | 1.20351 | 1.20351
22_Wand_Wand-x | 1e verdieping | 652.515 | 3620 | 0.0705728 | 2.26952 | 2.26952 | 0.255473 | 0.255473
22_Wand_Wand-x | 1e verdieping | 1175.18 | 3620 | 0.114477 | 4.09497 | 4.09497 | 0.414408 | 0.414408
22_Wand_Wand-x | 1e verdieping | 3619.34 | 3620 | 0.0478712 | 12.941 | 4.12101 | 1.31299 | 0.430994
22_Wand_Wand-x | 1e verdieping | 417.41 | 3620 | 0.0426785 | 1.51102 | 1.51102 | 0.154496 | 0.154496
22_Wand_Wand-x | 1e verdieping | 7028.24 | 3720 | 0.6957 | 25.5622 | 21.1122 | 2.54878 | 2.10378
22_Wand_Wand-x | 1e verdieping | 4070.91 | 3620 | 0.0749551 | 14.6778 | 5.4378 | 1.46308 | 0.539076
22_Wand_Wand-x | 1e verdieping | 3386 | 3620 | 0.3386 | 12.2436 | 12.2436 | 1.22539 | 1.22539
22_Wand_Wand-x | 1e verdieping | 6776.7 | 3720 | 0.44767 | 24.1106 | 17.6706 | 2.43781 | 1.79381
22_Wand_Wand-x | 1e verdieping | 3249.92 | 3620 | 0.3231 | 11.4907 | 11.4907 | 1.16962 | 1.16962
22_Wand_Wand-x | 1e verdieping | 5209.63 | 3620 | 0.522856 | 18.8589 | 15.6189 | 1.89274 | 1.56874
22_Wand_Wand-x | 1e verdieping | 1956.81 | 3620 | 0.00673584 | 6.89196 | 2.48505 | 0.721016 | 0.265511

# IfcWall: _TenW_22_Metalstud 125 enkel gipsvezelplaat 125 (9)
In: Begane grond
Classification: 22.13 SYSTEEMWANDEN VAST (NL/SfB (4 cijfers)); Wand (ARCHICAD Classification)
Pset_WallCommon - LoadBearing: no; IsExternal: no
BaseQuantities - Width: 125 mm
Name | Length (mm) | Height (mm) | GrossFootprintArea (m2) = NetFootprintArea (m2) | GrossSideArea (m2) | NetSideArea (m2) | GrossVolume (m3) | NetVolume (m3)
22_Wand_Wand-x | 5049.72 | 3375 | 0.397933 | 16.9373 | 10.342 | 2.14459 | 1.32017
22_Wand_Wand-x | 1909 | 3375 | 0.113281 | 6.10538 | 2.85167 | 0.754734 | 0.361746
22_Wand_Wand-x | 6000 | 3375 | 0.613719 | 19.9758 | 16.5535 | 2.50752 | 1.98617
22_Wand_Wand-x | 8387.78 | 3600 | 0.569912 | 28.6195 | 21.2895 | 3.64368 | 2.52499
22_Wand_Wand-x | 8561 | 3375 | 0.659657 | 28.577 | 20.708 | 3.58689 | 2.30667
22_Wand_Wand-x | 3409 | 3375 | 0.295344 | 11.4843 | 7.87128 | 1.4503 | 0.897459
22_Wand_Wand-x | 8511 | 3375 | 0.66075 | 28.4852 | 20.6162 | 3.58459 | 2.30452
22_Wand_Wand-x | 1437.5 | 3375 | 0.205 | 5.23125 | 5.23125 | 0.691875 | 0.691875
22_Wand_Wand-x | 1459 | 3375 | 0.182375 | 4.92413 | 4.92413 | 0.615516 | 0.615516

# IfcWall: _TenW_22_Metalstud 150 enkel gipsvezelplaat 150 (2)
In: Begane grond
Classification: 22.13 SYSTEEMWANDEN VAST (NL/SfB (4 cijfers)); Wand (ARCHICAD Classification)
Pset_WallCommon - LoadBearing: no; IsExternal: no
BaseQuantities - Width: 150 mm
Name | Length (mm) | Height (mm) | GrossFootprintArea (m2) = NetFootprintArea (m2) | GrossSideArea (m2) = NetSideArea (m2) | GrossVolume (m3) = NetVolume (m3)
22_Wand_Wand-x | 6376.12 | 1470 | 0.954167 | 7.18035 | 1.17548
22_Wand_Wand-x | 6300.77 | 1050 | 0.935766 | 6.3981 | 0.981345

# IfcWall: _TenW_22_Spouwmuur ht-150-kz RC 0 60 (4)
In: Begane grond
Classification: Wand (ARCHICAD Classification); 21.22 SPOUWWANDEN (NL/SfB (4 cijfers)); Material: _TenW_21_Hout betimmering
Pset_WallCommon - LoadBearing: yes; IsExternal: yes
BaseQuantities - Width: 60 mm
Component Quantities - Component 1, Skin Thickness: 20 mm; Component 1, Rectangular Component Height: 3480 mm; Component 1, Rectangular Component Width: 20 mm; Component 1, Component Cross Section Area: 0.0696 m2
Name | Length (mm) | Height (mm) | GrossFootprintArea (m2) = NetFootprintArea (m2) | GrossSideArea (m2) | NetSideArea (m2) | GrossVolume (m3) | NetVolume (m3) | Component 1, Mass (kg) | Component 1, Projected Component/Skin Area (m2) | Component 1, Skin/Component Volume (m3)
21_Wand_Wand-x | 6300 | 3450 | 0.37575 | 21.6056 | 21.6056 | 1.29634 | 1.29634 | 237.662 | 21.6056 | 0.432113
21_Wand_Wand-x | 977.671 | 3450 | 0.0766603 | 3.39397 | 3.39397 | 0.203638 | 0.203638 | 37.3336 | 3.39397 | 0.0678793
21_Wand_Wand-x | 1010.15 | 3450 | 0.0608589 | 3.50657 | 3.50657 | 0.209963 | 0.209963 | 38.8095 | 3.52814 | 0.0705627
21_Wand_Wand-x | 759.979 | 3480 | 0.0685587 | 3.61619 | 1.56878 | 0.236856 | 0.109041 | 25.4596 | 2.31451 | 0.0462901

# IfcWall: _TenW_24_Hout - Multiplex 150 (3)
In: 2e verdieping
Classification: Wand (ARCHICAD Classification); 21.22 SPOUWWANDEN (NL/SfB (4 cijfers)); Material: _TenW_24_Hout - Multiplex
Pset_WallCommon - LoadBearing: yes; IsExternal: yes
BaseQuantities - Width: 150 mm
Component Quantities - Component 1, Skin Thickness: 150 mm; Component 1, Rectangular Component Width: 150 mm
Name | Length (mm) | Height (mm) | GrossFootprintArea (m2) = NetFootprintArea (m2) | GrossSideArea (m2) | NetSideArea (m2) | GrossVolume (m3) | NetVolume (m3) = Component 1, Skin/Component Volume (m3) | Component 1, Mass (kg) | Component 1, Projected Component/Skin Area (m2) | Component 1, Rectangular Component Height (mm) | Component 1, Component Cross Section Area (m2)
21_Wand_Wand-x | 6046.08 | 1167.17 | 0.906912 | 7.29727 | 5.44637 | 1.0231 | 0.745468 | 521.828 | 6.18702 | 1329.44 | 0.199416
21_Wand_Wand-x | 1083.18 | 961.582 | 0.162837 | 1.15915 | 0.873122 | 0.173872 | 0.130968 | 91.6778 | 0.88289 | 1314.83 | 0.197224
21_Wand_Wand-x | 277.734 | 961.582 | 0.0420268 | 0.28644 | 0.265363 | 0.0429659 | 0.0398044 | 27.8631 | 0.283062 | 1285.36 | 0.192804

# IfcWall: _TenW_27_dakrand_01 473 x 542 (4)
In: 2e verdieping
Classification: Wand (ARCHICAD Classification); 21.22 SPOUWWANDEN (NL/SfB (4 cijfers))
Pset_WallCommon - LoadBearing: yes; IsExternal: yes
BaseQuantities - Width: 473.476 mm
Name | Length (mm) | Height (mm) | GrossFootprintArea (m2) = NetFootprintArea (m2) | GrossSideArea (m2) = NetSideArea (m2) | GrossVolume (m3) = NetVolume (m3)
2 x 21_Wand_Wand-x | 29394.6 | 542.256 | 14.1341 | 24.5776 | 6.4092
21_Wand_Wand-x | 50594.6 | 542.256 | 23.8766 | 42.2855 | 10.8753
21_Wand_Wand-x | 50594.6 | 542.281 | 23.8765 | 42.2948 | 10.8898

# IfcWall: _TenW_27_lichtstraatrand 01 331 x 1666, 21_Wand_Wand-x
In: 2e verdieping
Classification: Wand (ARCHICAD Classification); 21.22 SPOUWWANDEN (NL/SfB (4 cijfers))
Pset_WallCommon - LoadBearing: yes; IsExternal: yes
BaseQuantities - Length: 6350.11 mm; Height: 1665.52 mm; Width: 331.375 mm; GrossFootprintArea: 1.12328 m2; NetFootprintArea: 1.12328 m2; GrossSideArea: 12.8095 m2; NetSideArea: 12.7058 m2; GrossVolume: 1.43894 m3; NetVolume: 1.43822 m3

# IfcWall: _TenW_82_afw bamboe 20 (24)
Classification: Wand (ARCHICAD Classification); 21.22 SPOUWWANDEN (NL/SfB (4 cijfers)); Material: _TenW_82_afw bamboe
Pset_WallCommon - LoadBearing: yes; IsExternal: yes
BaseQuantities - Width: 20 mm
Component Quantities - Component 1, Skin Thickness: 20 mm; Component 1, Rectangular Component Width: 20 mm
Name | In | Length (mm) | Height (mm) = Component 1, Rectangular Component Height (mm) | GrossFootprintArea (m2) = NetFootprintArea (m2) | GrossSideArea (m2) = NetSideArea (m2) = Component 1, Projected Component/Skin Area (m2) | GrossVolume (m3) = NetVolume (m3) = Component 1, Skin/Component Volume (m3) | Component 1, Mass (kg) | Component 1, Component Cross Section Area (m2)
21_Wand_Wand-x | Begane grond | 4067.76 | 250 | 0.0813551 | 1.01694 | 0.0203388 | 11.1863 | 0.005
21_Wand_Wand-x | Begane grond | 4087.76 | 100 | 0.0817551 | 0.408776 | 0.00817551 | 4.49653 | 0.002
21_Wand_Wand-x | Begane grond | 1360 | 250 | 0.0272 | 0.34 | 0.0068 | 3.74 | 0.005
21_Wand_Wand-x | Begane grond | 1360 | 100 | 0.0272 | 0.136 | 0.00272 | 1.496 | 0.002
21_Wand_Wand-x | Begane grond | 2858.03 | 250 | 0.0571606 | 0.714507 | 0.0142901 | 7.85958 | 0.005
21_Wand_Wand-x | Begane grond | 2858.03 | 100 | 0.0571606 | 0.285803 | 0.00571606 | 3.14383 | 0.002
21_Wand_Wand-x | Begane grond | 1573.65 | 250 | 0.0314729 | 0.393412 | 0.00786823 | 4.32753 | 0.005
21_Wand_Wand-x | Begane grond | 1613.65 | 100 | 0.0322729 | 0.161365 | 0.00322729 | 1.77501 | 0.002
2 x 21_Wand_Wand-x | 1e verdieping | 2896 | 250 | 0.05792 | 0.724 | 0.01448 | 7.964 | 0.005
2 x 21_Wand_Wand-x | 1e verdieping | 2896 | 100 | 0.05792 | 0.2896 | 0.005792 | 3.1856 | 0.002
2 x 21_Wand_Wand-x | 1e verdieping | 2645.37 | 250 | 0.0529074 | 0.661343 | 0.0132269 | 7.27477 | 0.005
2 x 21_Wand_Wand-x | 1e verdieping | 2645.37 | 100 | 0.0529074 | 0.264537 | 0.00529074 | 2.90991 | 0.002
21_Wand_Wand-x | 1e verdieping | 3296 | 250 | 0.06592 | 0.824 | 0.01648 | 9.064 | 0.005
21_Wand_Wand-x | 1e verdieping | 3296 | 100 | 0.06592 | 0.3296 | 0.006592 | 3.6256 | 0.002
21_Wand_Wand-x | 1e verdieping | 3336 | 250 | 0.06672 | 0.834 | 0.01668 | 9.174 | 0.005
21_Wand_Wand-x | 1e verdieping | 3336 | 100 | 0.06672 | 0.3336 | 0.006672 | 3.6696 | 0.002
21_Wand_Wand-x | 1e verdieping | 5728.47 | 250 | 0.114569 | 1.43212 | 0.0286423 | 15.7533 | 0.005
21_Wand_Wand-x | 1e verdieping | 5728.47 | 100 | 0.114569 | 0.572847 | 0.0114569 | 6.30131 | 0.002
21_Wand_Wand-x | 1e verdieping | 4966.78 | 250 | 0.0993356 | 1.2417 | 0.0248339 | 13.6586 | 0.005
21_Wand_Wand-x | 1e verdieping | 4966.78 | 100 | 0.0993356 | 0.496678 | 0.00993356 | 5.46346 | 0.002

# IfcWindow: R rechthoekige opening 24, 31_Raam_-
In: 1e verdieping
Type - OperationType: USERDEFINED; ParameterTakesPrecedence: no; Sizeable: no
OverallHeight: 3235 mm; OverallWidth: 2954.8 mm; Classification: Raam (ARCHICAD Classification); 31.22 RAMEN DRAAIEND AAN EEN KANT (NL/SfB (4 cijfers))
Pset_WindowCommon - Reference: 31_arcering; IsExternal: yes
Material - Afwerking dagkant binnen: n.v.t.; Afwerking dagkant buiten: n.v.t.; Draaiend deel: n.v.t.; Frame: arcering (01); Onderdorpel: n.v.t.; Rollaag / latei: n.v.t.; Spouwlat: n.v.t.; Vensterbank: n.v.t.; Zonwering - behuizing: n.v.t.; Zonwering - isolatie: n.v.t.; Glas: Glas - algemeen
BaseQuantities - GrossArea: 9.55878 m2; Height: 3235 mm; Width: 2954.8 mm; Perimeter: 12379.6 mm; Area: 9.55878 m2; Volume: 0.0217817 m3; Depth: 538 mm; NetVolume: 0.0217817 m3
Component Quantities - Component 1, Skin/Component Volume: 0.0217817 m3

# IfcWindow: R1 24 (2)
In: Begane grond
Type - OperationType: DOUBLE_PANEL_HORIZONTAL; ParameterTakesPrecedence: no; Sizeable: no
OverallHeight: 1600 mm; Classification: Raam (ARCHICAD Classification); 31.22 RAMEN DRAAIEND AAN EEN KANT (NL/SfB (4 cijfers))
Pset_WindowCommon - Reference: 31_n.v.t.; FireRating: 30; IsExternal: yes
Material - Afwerking dagkant binnen: n.v.t.; Afwerking dagkant buiten: n.v.t.; Draaiend deel: n.v.t.; Frame: n.v.t.; Onderdorpel: n.v.t.; Rollaag / latei: n.v.t.; Spouwlat: n.v.t.; Vensterbank: n.v.t.; Ventilatierooster: n.v.t.; Zonwering - behuizing: n.v.t.; Zonwering - isolatie: n.v.t.; Glas: Glas - algemeen
BaseQuantities - Height: 1600 mm; Depth: 100 mm
Name | OverallWidth (mm) = Width (mm) | GrossArea (m2) = Area (m2) | Perimeter (mm) | Volume (m3) = NetVolume (m3) = Component 1, Skin/Component Volume (m3)
31_Raam_Hi-40 | 1989.19 | 3.18271 | 7178.38 | 0.0686434
31_Raam_Hi-39 | 1150 | 1.84 | 5500 | 0.0486488

# IfcWindow: R1 24 (21)
Type - OperationType: SINGLE_PANEL; ParameterTakesPrecedence: no; Sizeable: no
Classification: Raam (ARCHICAD Classification); 31.22 RAMEN DRAAIEND AAN EEN KANT (NL/SfB (4 cijfers))
Pset_WindowCommon - Reference: 31_n.v.t.; IsExternal: yes
Material - Afwerking dagkant binnen: n.v.t.; Afwerking dagkant buiten: n.v.t.; Draaiend deel: n.v.t.; Frame: n.v.t.; Onderdorpel: n.v.t.; Rollaag / latei: n.v.t.; Spouwlat: n.v.t.; Vensterbank: n.v.t.; Ventilatierooster: n.v.t.; Zonwering - behuizing: n.v.t.; Zonwering - isolatie: n.v.t.; Glas: Glas - algemeen
Name | In | OverallHeight (mm) = Height (mm) | OverallWidth (mm) | FireRating | GrossArea (m2) = Area (m2) | Width (mm) | Perimeter (mm) | Volume (m3) = NetVolume (m3) = Component 1, Skin/Component Volume (m3) | Depth (mm)
31_Raam_Hi-49 | Begane grond | 595 | 1925 | n.v.t. | 1.14538 | 1925 | 5040 | 0.0364485 | 125
31_Raam_Hi-48 | Begane grond | 1200 | 825 | n.v.t. | 0.99 | 825 | 4050 | 0.0288869 | 125
31_Raam_Hi-49 | Begane grond | 595 | 1925 | n.v.t. | 1.14538 | 1925 | 5040 | 0.0364485 | 100
31_Raam_Hi-41 | Begane grond | 596.073 | 2345 | n.v.t. | 1.39779 | 2345 | 5882.15 | 0.0428808 | 100
31_Raam_Hi-35 | Begane grond | 2800 | 2271.8 | n.v.t. | 6.36103 | 2271.8 | 10143.6 | 0.0529332 | 100
31_Raam_Hi-38 | Begane grond | 1200 | 809.749 | n.v.t. | 0.971699 | 809.749 | 4019.5 | 0.0286539 | 125
31_Raam_Hi-29 | Begane grond | 2800 | 812.793 | n.v.t. | 2.07694 | 741.763 | 7083.53 | 0.0372927 | 100
31_Raam_Hi-33 | Begane grond | 2800 | 2100 | n.v.t. | 5.88 | 2100 | 9800 | 0.0510915 | 100
31_Raam_Hi-48a | Begane grond | 1200 | 825 | n.v.t. | 0.99 | 825 | 4050 | 0.0288869 | 125
2 x 31_Raam_Hi-47 | Begane grond | 1800 | 1800 | n.v.t. | 3.24 | 1800 | 7200 | 0.0371555 | 100
31_Raam_Hi-36 | Begane grond | 1100 | 706.829 | 30 | 0.777512 | 706.829 | 3613.66 | 0.0179327 | 100
31_Raam_Hi-37 | Begane grond | 2200 | 1317.14 | 30 | 2.89772 | 1317.14 | 7034.29 | 0.0362673 | 100
31_Raam_Hi-34 | 1e verdieping | 2200 | 2200 | n.v.t. | 4.84 | 2200 | 8800 | 0.141509 | 100
2 x 31_Raam_Hi-45 | 1e verdieping | 1100 | 1100 | n.v.t. | 1.21 | 1100 | 4400 | 0.0315602 | 100
31_Raam_Hi-46 | 1e verdieping | 1800 | 1800 | n.v.t. | 3.24 | 1800 | 7200 | 0.103491 | 100
31_Raam_Hi-30 | 1e verdieping | 1825.6 | 920.712 | n.v.t. | 1.68085 | 920.712 | 5492.62 | 0.028004 | 100
31_Raam_Hi-31 | 1e verdieping | 1100 | 1100 | n.v.t. | 1.21 | 1100 | 4400 | 0.0221475 | 100
31_Raam_Hi-32 | 1e verdieping | 1800 | 1800 | n.v.t. | 3.24 | 1800 | 7200 | 0.0371555 | 100
31_Raam_Hi-46a | 1e verdieping | 1800 | 1800 | n.v.t. | 3.24 | 1800 | 7200 | 0.0371555 | 100

# IfcWindow: R1 24 (17)
In: Begane grond
Type - OperationType: TRIPLE_PANEL_HORIZONTAL; ParameterTakesPrecedence: no; Sizeable: no
OverallHeight: 2800 mm; Classification: Raam (ARCHICAD Classification); 31.22 RAMEN DRAAIEND AAN EEN KANT (NL/SfB (4 cijfers))
Pset_WindowCommon - Reference: 31_n.v.t.; IsExternal: yes
Material - Afwerking dagkant binnen: n.v.t.; Afwerking dagkant buiten: n.v.t.; Draaiend deel: n.v.t.; Frame: n.v.t.; Onderdorpel: n.v.t.; Rollaag / latei: n.v.t.; Spouwlat: n.v.t.; Vensterbank: n.v.t.; Ventilatierooster: n.v.t.; Zonwering - behuizing: n.v.t.; Zonwering - isolatie: n.v.t.; Glas: Glas - algemeen
BaseQuantities - Height: 2800 mm
Name | OverallWidth (mm) = Width (mm) | GrossArea (m2) = Area (m2) | Perimeter (mm) | Volume (m3) = NetVolume (m3) = Component 1, Skin/Component Volume (m3) | Depth (mm)
3 x 31_Raam_He-12s | 1084 | 3.0352 | 7768 | 0.0880103 | 574
3 x 31_Raam_He-15 | 1084 | 3.0352 | 7768 | 0.0717972 | 574
3 x 31_Raam_He-12 | 1084 | 3.0352 | 7768 | 0.0880103 | 574
2 x 31_Raam_He-12s | 1084 | 3.0352 | 7768 | 0.0880103 | 488
3 x 31_Raam_He-18 | 1084 | 3.0352 | 7768 | 0.189281 | 574
31_Raam_He-09s | 1082.52 | 3.03106 | 7765.04 | 0.0879553 | 574
2 x 31_Raam_He-09 | 1082.52 | 3.03106 | 7765.04 | 0.0879553 | 488

# IfcWindow: R2 bl ol 24 (57)
Type - OperationType: USERDEFINED; ParameterTakesPrecedence: no; Sizeable: no
Classification: Raam (ARCHICAD Classification); 31.22 RAMEN DRAAIEND AAN EEN KANT (NL/SfB (4 cijfers))
Pset_WindowCommon - Reference: 31_n.v.t.; IsExternal: yes
Material - Afwerking dagkant binnen: n.v.t.; Afwerking dagkant buiten: n.v.t.; Draaiend deel: n.v.t.; Frame: n.v.t.; Onderdorpel: n.v.t.; Rollaag / latei: n.v.t.; Spouwlat: n.v.t.; Vensterbank: n.v.t.; Ventilatierooster: n.v.t.; Zonwering - behuizing: n.v.t.; Zonwering - isolatie: n.v.t.; Glas: Glas - algemeen
Name | In | OverallHeight (mm) = Height (mm) | OverallWidth (mm) = Width (mm) | GrossArea (m2) = Area (m2) | Perimeter (mm) | Volume (m3) = NetVolume (m3) = Component 1, Skin/Component Volume (m3) | Depth (mm)
4 x 31_Raam_He-11 | Begane grond | 2800 | 2190 | 6.132 | 9980 | 0.146623 | 574
31_Raam_He-11s | Begane grond | 2800 | 2190 | 6.132 | 9980 | 0.146623 | 574
2 x 31_Raam_He-11 | Begane grond | 2800 | 2190 | 6.132 | 9980 | 0.146623 | 488
3 x 31_Raam_He-11s | Begane grond | 2800 | 2190 | 6.132 | 9980 | 0.146623 | 488
2 x 31_Raam_He-16 | Begane grond | 3050 | 2190 | 6.6795 | 10480 | 0.157953 | 498
2 x 31_Raam_He-10 | Begane grond | 3050 | 2190 | 6.6795 | 10480 | 0.152631 | 498
2 x 31_Raam_He-16 | Begane grond | 3050 | 2190 | 6.6795 | 10480 | 0.166185 | 498
4 x 31_Raam_Hi-53 | Begane grond | 1600 | 2350 | 3.76 | 7900 | 0.0891331 | 100 | Pset_WindowCommon - FireRating: n.v.t.
31_Raam_He-11 | 1e verdieping | 2800 | 2190 | 6.132 | 9980 | 0.146623 | 488
8 x 31_Raam_He-13 | 1e verdieping | 3235 | 2190 | 7.08465 | 10850 | 0.179981 | 538
9 x 31_Raam_He-13s | 1e verdieping | 3235 | 2190 | 7.08465 | 10850 | 0.179981 | 538
11 x 31_Raam_He-14 | 1e verdieping | 3235 | 2190 | 7.08465 | 10850 | 0.193899 | 538
31_Raam_He-13s | 1e verdieping | 3235 | 2190 | 7.08465 | 10850 | 0.17866 | 538
31_Raam_He-13 | 1e verdieping | 3235 | 2190 | 7.08465 | 10850 | 0.17866 | 538
6 x 31_Raam_Hi-53 | 1e verdieping | 1600 | 2350 | 3.76 | 7900 | 0.0891331 | 100 | Pset_WindowCommon - FireRating: n.v.t.
